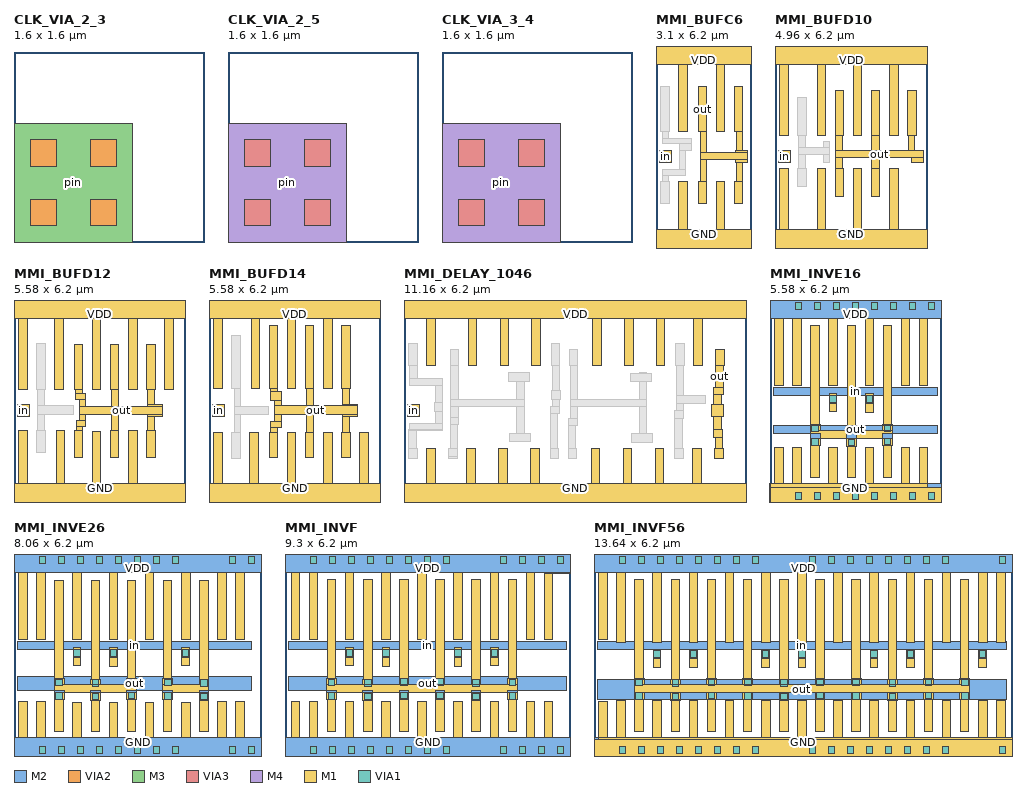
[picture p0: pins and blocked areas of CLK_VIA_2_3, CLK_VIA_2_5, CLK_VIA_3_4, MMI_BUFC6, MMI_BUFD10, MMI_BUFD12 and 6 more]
MACRO CLK_VIA_2_3
	CLASS CORE ;
	FOREIGN CLK_VIA_2_3 -0.3 -0.3 ;
	SIZE 1.6 BY 1.6 ;
	SYMMETRY X Y ;
	SITE CORE1 ;
	PIN pin
		DIRECTION inout ;
		USE SIGNAL ;
		PORT
			LAYER M2 ;
			RECT 0 0 1 1 ;
			LAYER VIA2 ;
			RECT 0.14 0.64 0.36 0.86 ;
			LAYER VIA2 ;
			RECT 0.64 0.64 0.86 0.86 ;
			LAYER VIA2 ;
			RECT 0.14 0.14 0.36 0.36 ;
			LAYER VIA2 ;
			RECT 0.64 0.14 0.86 0.36 ;
			LAYER M3 ;
			RECT 0 0 1 1 ;
		END
	END pin
	OBS
	END
END CLK_VIA_2_3
MACRO CLK_VIA_2_5
	CLASS CORE ;
	FOREIGN CLK_VIA_2_5 -0.3 -0.3 ;
	SIZE 1.6 BY 1.6 ;
	SYMMETRY X Y ;
	SITE CORE1 ;
	PIN pin
		DIRECTION output ;
		USE SIGNAL ;
		PORT
			LAYER M2 ;
			RECT 0 0 1 1 ;
			LAYER VIA2 ;
			RECT 0.14 0.64 0.36 0.86 ;
			LAYER VIA2 ;
			RECT 0.64 0.64 0.86 0.86 ;
			LAYER VIA2 ;
			RECT 0.14 0.14 0.36 0.36 ;
			LAYER VIA2 ;
			RECT 0.64 0.14 0.86 0.36 ;
			LAYER M3 ;
			RECT 0 0 1 1 ;
			LAYER VIA3 ;
			RECT 0.14 0.64 0.36 0.86 ;
			LAYER VIA3 ;
			RECT 0.64 0.64 0.86 0.86 ;
			LAYER VIA3 ;
			RECT 0.14 0.14 0.36 0.36 ;
			LAYER VIA3 ;
			RECT 0.64 0.14 0.86 0.36 ;
			LAYER M4 ;
			RECT 0 0 1 1 ;
		END
	END pin
	OBS
	END
END CLK_VIA_2_5
MACRO CLK_VIA_3_4
	CLASS CORE ;
	FOREIGN CLK_VIA_3_4 -0.3 -0.3 ;
	SIZE 1.6 BY 1.6 ;
	SYMMETRY X Y ;
	SITE CORE1 ;
	PIN pin
		DIRECTION inout ;
		USE SIGNAL ;
		PORT
			LAYER M3 ;
			RECT 0 0 1 1 ;
			LAYER VIA3 ;
			RECT 0.14 0.64 0.36 0.86 ;
			LAYER VIA3 ;
			RECT 0.64 0.64 0.86 0.86 ;
			LAYER VIA3 ;
			RECT 0.14 0.14 0.36 0.36 ;
			LAYER VIA3 ;
			RECT 0.64 0.14 0.86 0.36 ;
			LAYER M4 ;
			RECT 0 0 1 1 ;
		END
	END pin
	OBS
	END
END CLK_VIA_3_4
MACRO MMI_BUFC6
	CLASS CORE ;
	FOREIGN MMI_BUFC6 0 0 ;
	SIZE 3.1 BY 6.2 ;
	SYMMETRY X Y ;
	SITE CORE1 ;
	PIN out
		DIRECTION output ;
		USE SIGNAL ;
		PORT
			LAYER M1 ;
			RECT 1.375 3.59 1.655 5.06 ;
			LAYER M1 ;
			RECT 2.555 3.59 2.835 5.06 ;
			LAYER M1 ;
			RECT 1.465 2.92 1.655 3.59 ;
			LAYER M1 ;
			RECT 2.62 2.98 2.81 3.59 ;
			LAYER M1 ;
			RECT 2.6 2.92 2.98 2.98 ;
			LAYER M1 ;
			RECT 1.465 2.68 2.98 2.92 ;
			LAYER M1 ;
			RECT 1.465 1.96 1.655 2.68 ;
			LAYER M1 ;
			RECT 2.6 2.6 2.98 2.68 ;
			LAYER M1 ;
			RECT 2.62 1.96 2.81 2.6 ;
			LAYER M1 ;
			RECT 1.375 1.26 1.655 1.96 ;
			LAYER M1 ;
			RECT 2.555 1.26 2.835 1.96 ;
		END
	END out
	PIN GND
		DIRECTION inout ;
		USE GROUND ;
		PORT
			LAYER M1 ;
			RECT 0.745 0.42 1.025 1.96 ;
			LAYER M1 ;
			RECT 1.965 0.42 2.245 1.96 ;
			LAYER M1 ;
			RECT 0 -0.42 3.1 0.42 ;
		END
	END GND
	PIN VDD
		DIRECTION inout ;
		USE POWER ;
		PORT
			LAYER M1 ;
			RECT 0 5.78 3.1 6.62 ;
			LAYER M1 ;
			RECT 0.745 3.59 1.025 5.78 ;
			LAYER M1 ;
			RECT 1.965 3.59 2.245 5.78 ;
		END
	END VDD
	PIN in
		DIRECTION input ;
		USE SIGNAL ;
		PORT
			LAYER M1 ;
			RECT 0.12 2.6 0.5 2.98 ;
		END
		ANTENNASIZE 0.351 ;
	END in
	OBS
		LAYER M1 ;
		RECT 0.155 3.59 0.435 5.08 ;
		LAYER M1 ;
		RECT 0.225 3.39 0.415 3.59 ;
		LAYER M1 ;
		RECT 0.225 3.2 1.155 3.39 ;
		LAYER M1 ;
		RECT 0.77 2.97 1.155 3.2 ;
		LAYER M1 ;
		RECT 0.77 2.35 0.96 2.97 ;
		LAYER M1 ;
		RECT 0.22 2.16 0.96 2.35 ;
		LAYER M1 ;
		RECT 0.22 1.96 0.41 2.16 ;
		LAYER M1 ;
		RECT 0.155 1.25 0.435 1.96 ;
	END
END MMI_BUFC6
MACRO MMI_BUFD10
	CLASS CORE ;
	FOREIGN MMI_BUFD10 0 0 ;
	SIZE 4.96 BY 6.2 ;
	SYMMETRY X Y ;
	SITE CORE1 ;
	PIN out
		DIRECTION output ;
		USE SIGNAL ;
		PORT
			LAYER M1 ;
			RECT 1.965 3.49 2.245 4.96 ;
			LAYER M1 ;
			RECT 3.145 3.49 3.425 4.96 ;
			LAYER M1 ;
			RECT 4.325 3.49 4.605 4.96 ;
			LAYER M1 ;
			RECT 1.975 2.99 2.215 3.49 ;
			LAYER M1 ;
			RECT 3.16 2.99 3.4 3.49 ;
			LAYER M1 ;
			RECT 4.365 2.99 4.555 3.49 ;
			LAYER M1 ;
			RECT 1.975 2.98 4.56 2.99 ;
			LAYER M1 ;
			RECT 1.975 2.75 4.84 2.98 ;
			LAYER M1 ;
			RECT 1.975 2.39 2.215 2.75 ;
			LAYER M1 ;
			RECT 3.16 2.39 3.4 2.75 ;
			LAYER M1 ;
			RECT 4.46 2.6 4.84 2.75 ;
			LAYER M1 ;
			RECT 1.965 1.495 2.245 2.39 ;
			LAYER M1 ;
			RECT 3.145 1.495 3.425 2.39 ;
		END
	END out
	PIN GND
		DIRECTION inout ;
		USE GROUND ;
		PORT
			LAYER M1 ;
			RECT 0.155 0.42 0.435 2.39 ;
			LAYER M1 ;
			RECT 1.375 0.42 1.655 2.39 ;
			LAYER M1 ;
			RECT 2.555 0.42 2.835 2.39 ;
			LAYER M1 ;
			RECT 3.735 0.42 4.015 2.39 ;
			LAYER M1 ;
			RECT 0 -0.42 4.96 0.42 ;
		END
	END GND
	PIN VDD
		DIRECTION inout ;
		USE POWER ;
		PORT
			LAYER M1 ;
			RECT 0 5.78 4.96 6.62 ;
			LAYER M1 ;
			RECT 0.155 3.49 0.435 5.78 ;
			LAYER M1 ;
			RECT 1.375 3.49 1.655 5.78 ;
			LAYER M1 ;
			RECT 2.555 3.49 2.835 5.78 ;
			LAYER M1 ;
			RECT 3.735 3.49 4.015 5.78 ;
		END
	END VDD
	PIN in
		DIRECTION input ;
		USE SIGNAL ;
		PORT
			LAYER M1 ;
			RECT 0.12 2.6 0.5 2.98 ;
		END
		ANTENNASIZE 0.585 ;
	END in
	OBS
		LAYER M1 ;
		RECT 0.745 3.49 1.025 4.72 ;
		LAYER M1 ;
		RECT 0.765 3.09 1.005 3.49 ;
		LAYER M1 ;
		RECT 1.585 3.09 1.775 3.27 ;
		LAYER M1 ;
		RECT 0.765 2.85 1.775 3.09 ;
		LAYER M1 ;
		RECT 0.765 2.39 1.005 2.85 ;
		LAYER M1 ;
		RECT 1.585 2.6 1.775 2.85 ;
		LAYER M1 ;
		RECT 0.745 1.81 1.025 2.39 ;
	END
END MMI_BUFD10
MACRO MMI_BUFD12
	CLASS CORE ;
	FOREIGN MMI_BUFD12 0 0 ;
	SIZE 5.58 BY 6.2 ;
	SYMMETRY X Y ;
	SITE CORE1 ;
	PIN out
		DIRECTION output ;
		USE SIGNAL ;
		PORT
			LAYER M1 ;
			RECT 1.965 3.485 2.245 4.955 ;
			LAYER M1 ;
			RECT 3.145 3.485 3.425 4.955 ;
			LAYER M1 ;
			RECT 4.325 3.485 4.605 4.955 ;
			LAYER M1 ;
			RECT 2.005 3.35 2.245 3.485 ;
			LAYER M1 ;
			RECT 2.005 3.145 2.335 3.35 ;
			LAYER M1 ;
			RECT 2.145 2.91 2.335 3.145 ;
			LAYER M1 ;
			RECT 3.17 2.91 3.41 3.485 ;
			LAYER M1 ;
			RECT 4.355 2.98 4.595 3.485 ;
			LAYER M1 ;
			RECT 4.355 2.91 4.84 2.98 ;
			LAYER M1 ;
			RECT 2.145 2.67 4.84 2.91 ;
			LAYER M1 ;
			RECT 2.145 2.465 2.335 2.67 ;
			LAYER M1 ;
			RECT 2.035 2.275 2.335 2.465 ;
			LAYER M1 ;
			RECT 2.035 2.125 2.245 2.275 ;
			LAYER M1 ;
			RECT 3.17 2.125 3.41 2.67 ;
			LAYER M1 ;
			RECT 4.355 2.6 4.84 2.67 ;
			LAYER M1 ;
			RECT 4.355 2.125 4.595 2.6 ;
			LAYER M1 ;
			RECT 1.965 1.27 2.245 2.125 ;
			LAYER M1 ;
			RECT 3.145 1.27 3.425 2.125 ;
			LAYER M1 ;
			RECT 4.325 1.27 4.605 2.125 ;
		END
	END out
	PIN GND
		DIRECTION inout ;
		USE GROUND ;
		PORT
			LAYER M1 ;
			RECT 0.155 0.42 0.435 2.125 ;
			LAYER M1 ;
			RECT 1.375 0.42 1.655 2.125 ;
			LAYER M1 ;
			RECT 2.555 0.42 2.835 2.12 ;
			LAYER M1 ;
			RECT 3.735 0.42 4.015 2.125 ;
			LAYER M1 ;
			RECT 0 -0.42 5.58 0.42 ;
		END
	END GND
	PIN VDD
		DIRECTION inout ;
		USE POWER ;
		PORT
			LAYER M1 ;
			RECT 0 5.78 5.58 6.62 ;
			LAYER M1 ;
			RECT 0.155 3.485 0.435 5.78 ;
			LAYER M1 ;
			RECT 1.335 3.485 1.615 5.78 ;
			LAYER M1 ;
			RECT 2.555 3.485 2.835 5.78 ;
			LAYER M1 ;
			RECT 3.735 3.485 4.015 5.78 ;
			LAYER M1 ;
			RECT 4.915 3.485 5.195 5.78 ;
		END
	END VDD
	PIN in
		DIRECTION input ;
		USE SIGNAL ;
		PORT
			LAYER M1 ;
			RECT 0.12 2.6 0.5 2.98 ;
		END
		ANTENNASIZE 0.702 ;
	END in
	OBS
		LAYER M1 ;
		RECT 0.745 3.485 1.025 4.975 ;
		LAYER M1 ;
		RECT 0.76 2.945 1 3.485 ;
		LAYER M1 ;
		RECT 0.76 2.665 1.935 2.945 ;
		LAYER M1 ;
		RECT 0.76 2.125 1 2.665 ;
		LAYER M1 ;
		RECT 0.745 1.415 1.025 2.125 ;
	END
END MMI_BUFD12
MACRO MMI_BUFD14
	CLASS CORE ;
	FOREIGN MMI_BUFD14 0 0 ;
	SIZE 5.58 BY 6.2 ;
	SYMMETRY X Y ;
	SITE CORE1 ;
	PIN out
		DIRECTION output ;
		USE SIGNAL ;
		PORT
			LAYER M1 ;
			RECT 1.965 3.495 2.245 5.58 ;
			LAYER M1 ;
			RECT 3.145 3.495 3.425 5.58 ;
			LAYER M1 ;
			RECT 4.325 3.495 4.605 5.58 ;
			LAYER M1 ;
			RECT 2.005 3.425 2.245 3.495 ;
			LAYER M1 ;
			RECT 2.005 3.13 2.355 3.425 ;
			LAYER M1 ;
			RECT 2.135 2.94 2.355 3.13 ;
			LAYER M1 ;
			RECT 3.17 2.94 3.41 3.495 ;
			LAYER M1 ;
			RECT 4.34 2.98 4.58 3.495 ;
			LAYER M1 ;
			RECT 4.34 2.94 4.84 2.98 ;
			LAYER M1 ;
			RECT 2.135 2.66 4.84 2.94 ;
			LAYER M1 ;
			RECT 2.135 2.425 2.355 2.66 ;
			LAYER M1 ;
			RECT 2.005 2.235 2.355 2.425 ;
			LAYER M1 ;
			RECT 2.005 2.08 2.245 2.235 ;
			LAYER M1 ;
			RECT 3.17 2.08 3.41 2.66 ;
			LAYER M1 ;
			RECT 4.34 2.6 4.84 2.66 ;
			LAYER M1 ;
			RECT 4.34 2.08 4.58 2.6 ;
			LAYER M1 ;
			RECT 1.965 1.25 2.245 2.08 ;
			LAYER M1 ;
			RECT 3.145 1.25 3.425 2.08 ;
			LAYER M1 ;
			RECT 4.325 1.25 4.605 2.08 ;
		END
	END out
	PIN GND
		DIRECTION inout ;
		USE GROUND ;
		PORT
			LAYER M1 ;
			RECT 0.155 0.42 0.435 2.08 ;
			LAYER M1 ;
			RECT 1.335 0.42 1.615 2.08 ;
			LAYER M1 ;
			RECT 2.555 0.42 2.835 2.08 ;
			LAYER M1 ;
			RECT 3.735 0.42 4.015 2.08 ;
			LAYER M1 ;
			RECT 4.915 0.42 5.195 2.08 ;
			LAYER M1 ;
			RECT 0 -0.42 5.58 0.42 ;
		END
	END GND
	PIN VDD
		DIRECTION inout ;
		USE POWER ;
		PORT
			LAYER M1 ;
			RECT 0 5.78 5.58 6.62 ;
			LAYER M1 ;
			RECT 0.155 3.495 0.435 5.78 ;
			LAYER M1 ;
			RECT 1.375 3.495 1.655 5.78 ;
			LAYER M1 ;
			RECT 2.555 3.495 2.835 5.78 ;
			LAYER M1 ;
			RECT 3.735 3.495 4.015 5.78 ;
		END
	END VDD
	PIN in
		DIRECTION input ;
		USE SIGNAL ;
		PORT
			LAYER M1 ;
			RECT 0.12 2.6 0.5 2.98 ;
		END
		ANTENNASIZE 0.819 ;
	END in
	OBS
		LAYER M1 ;
		RECT 0.745 3.495 1.025 5.245 ;
		LAYER M1 ;
		RECT 0.825 2.93 1.015 3.495 ;
		LAYER M1 ;
		RECT 0.825 2.65 1.935 2.93 ;
		LAYER M1 ;
		RECT 0.825 2.08 1.015 2.65 ;
		LAYER M1 ;
		RECT 0.745 1.24 1.025 2.08 ;
	END
END MMI_BUFD14
MACRO MMI_DELAY_1046
	CLASS CORE ;
	FOREIGN MMI_DELAY_1046 0 0 ;
	SIZE 11.16 BY 6.2 ;
	SYMMETRY X Y ;
	SITE CORE1 ;
	PIN out
		DIRECTION output ;
		USE SIGNAL ;
		PORT
			LAYER M1 ;
			RECT 10.175 4.25 10.455 4.78 ;
			LAYER M1 ;
			RECT 10.18 3.55 10.42 4.25 ;
			LAYER M1 ;
			RECT 10.11 3.31 10.42 3.55 ;
			LAYER M1 ;
			RECT 10.11 2.98 10.35 3.31 ;
			LAYER M1 ;
			RECT 10.04 2.6 10.42 2.98 ;
			LAYER M1 ;
			RECT 10.11 2.17 10.35 2.6 ;
			LAYER M1 ;
			RECT 10.11 1.895 10.395 2.17 ;
			LAYER M1 ;
			RECT 10.155 1.55 10.395 1.895 ;
			LAYER M1 ;
			RECT 10.135 1.22 10.415 1.55 ;
		END
	END out
	PIN GND
		DIRECTION inout ;
		USE GROUND ;
		PORT
			LAYER M1 ;
			RECT 0.745 0.42 1.025 1.55 ;
			LAYER M1 ;
			RECT 2.055 0.42 2.335 1.55 ;
			LAYER M1 ;
			RECT 3.095 0.42 3.375 1.55 ;
			LAYER M1 ;
			RECT 4.135 0.42 4.415 1.55 ;
			LAYER M1 ;
			RECT 6.115 0.42 6.395 1.55 ;
			LAYER M1 ;
			RECT 7.155 0.42 7.435 1.55 ;
			LAYER M1 ;
			RECT 8.195 0.42 8.475 1.55 ;
			LAYER M1 ;
			RECT 9.415 0.42 9.695 1.55 ;
			LAYER M1 ;
			RECT 0 -0.42 11.16 0.42 ;
		END
	END GND
	PIN VDD
		DIRECTION inout ;
		USE POWER ;
		PORT
			LAYER M1 ;
			RECT 0 5.78 11.16 6.62 ;
			LAYER M1 ;
			RECT 0.745 4.25 1.025 5.78 ;
			LAYER M1 ;
			RECT 2.095 4.25 2.375 5.78 ;
			LAYER M1 ;
			RECT 3.135 4.25 3.415 5.78 ;
			LAYER M1 ;
			RECT 4.175 4.25 4.455 5.78 ;
			LAYER M1 ;
			RECT 6.155 4.25 6.435 5.78 ;
			LAYER M1 ;
			RECT 7.195 4.25 7.475 5.78 ;
			LAYER M1 ;
			RECT 8.235 4.25 8.515 5.78 ;
			LAYER M1 ;
			RECT 9.455 4.25 9.735 5.78 ;
		END
	END VDD
	PIN in
		DIRECTION input ;
		USE SIGNAL ;
		PORT
			LAYER M1 ;
			RECT 0.12 2.6 0.5 2.98 ;
		END
		ANTENNASIZE 0.18 ;
	END in
	OBS
		LAYER M1 ;
		RECT 0.155 4.25 0.435 4.98 ;
		LAYER M1 ;
		RECT 1.505 4.25 1.785 4.78 ;
		LAYER M1 ;
		RECT 4.805 4.25 5.085 4.98 ;
		LAYER M1 ;
		RECT 5.395 4.25 5.675 4.78 ;
		LAYER M1 ;
		RECT 8.865 4.25 9.145 4.98 ;
		LAYER M1 ;
		RECT 0.185 3.83 0.425 4.25 ;
		LAYER M1 ;
		RECT 0.185 3.59 1.265 3.83 ;
		LAYER M1 ;
		RECT 1.025 3.04 1.265 3.59 ;
		LAYER M1 ;
		RECT 1.525 3.165 1.765 4.25 ;
		LAYER M1 ;
		RECT 3.685 4.015 3.925 4.025 ;
		LAYER M1 ;
		RECT 3.42 3.735 4.09 4.015 ;
		LAYER M1 ;
		RECT 3.685 3.165 3.925 3.735 ;
		LAYER M1 ;
		RECT 4.83 3.435 5.07 4.25 ;
		LAYER M1 ;
		RECT 0.99 2.76 1.27 3.04 ;
		LAYER M1 ;
		RECT 1.525 2.925 3.925 3.165 ;
		LAYER M1 ;
		RECT 4.825 3.155 5.105 3.435 ;
		LAYER M1 ;
		RECT 5.42 3.16 5.66 4.25 ;
		LAYER M1 ;
		RECT 7.67 4.01 7.91 4.02 ;
		LAYER M1 ;
		RECT 7.405 3.73 8.075 4.01 ;
		LAYER M1 ;
		RECT 7.67 3.16 7.91 3.73 ;
		LAYER M1 ;
		RECT 4.83 2.93 5.07 3.155 ;
		LAYER M1 ;
		RECT 1.025 2.375 1.265 2.76 ;
		LAYER M1 ;
		RECT 1.525 2.565 1.765 2.925 ;
		LAYER M1 ;
		RECT 0.165 2.18 1.27 2.375 ;
		LAYER M1 ;
		RECT 0.16 2.135 1.27 2.18 ;
		LAYER M1 ;
		RECT 1.515 2.32 1.765 2.565 ;
		LAYER M1 ;
		RECT 0.16 1.55 0.4 2.135 ;
		LAYER M1 ;
		RECT 1.515 1.55 1.755 2.32 ;
		LAYER M1 ;
		RECT 3.685 2.045 3.925 2.925 ;
		LAYER M1 ;
		RECT 4.785 2.69 5.07 2.93 ;
		LAYER M1 ;
		RECT 5.42 2.92 7.91 3.16 ;
		LAYER M1 ;
		RECT 3.45 1.765 4.12 2.045 ;
		LAYER M1 ;
		RECT 4.785 1.55 5.025 2.69 ;
		LAYER M1 ;
		RECT 5.42 2.545 5.66 2.92 ;
		LAYER M1 ;
		RECT 5.36 2.305 5.66 2.545 ;
		LAYER M1 ;
		RECT 5.36 1.55 5.6 2.305 ;
		LAYER M1 ;
		RECT 7.67 2.04 7.91 2.92 ;
		LAYER M1 ;
		RECT 8.88 3.265 9.12 4.25 ;
		LAYER M1 ;
		RECT 9.545 3.265 9.825 3.285 ;
		LAYER M1 ;
		RECT 8.88 3.025 9.83 3.265 ;
		LAYER M1 ;
		RECT 8.88 2.785 9.12 3.025 ;
		LAYER M1 ;
		RECT 9.545 3.005 9.825 3.025 ;
		LAYER M1 ;
		RECT 8.84 2.545 9.12 2.785 ;
		LAYER M1 ;
		RECT 7.435 1.76 8.105 2.04 ;
		LAYER M1 ;
		RECT 8.84 1.55 9.08 2.545 ;
		LAYER M1 ;
		RECT 0.155 1.22 0.435 1.55 ;
		LAYER M1 ;
		RECT 1.465 1.29 1.755 1.55 ;
		LAYER M1 ;
		RECT 1.465 1.22 1.745 1.29 ;
		LAYER M1 ;
		RECT 4.765 1.22 5.045 1.55 ;
		LAYER M1 ;
		RECT 5.355 1.22 5.635 1.55 ;
		LAYER M1 ;
		RECT 8.825 1.22 9.105 1.55 ;
	END
END MMI_DELAY_1046
MACRO MMI_INVE16
	CLASS CORE ;
	FOREIGN MMI_INVE16 0 0 ;
	SIZE 5.58 BY 6.2 ;
	SYMMETRY X Y ;
	SITE CORE1 ;
	PIN out
		DIRECTION output ;
		USE SIGNAL ;
		PORT
			LAYER M1 ;
			RECT 1.335 2.32 1.615 5.58 ;
			LAYER M1 ;
			RECT 1.315 2.125 1.635 2.32 ;
			LAYER M1 ;
			RECT 2.515 2.305 2.795 5.58 ;
			LAYER M1 ;
			RECT 3.695 2.335 3.975 5.58 ;
			LAYER M1 ;
			RECT 2.5 2.13 2.82 2.305 ;
			LAYER M1 ;
			RECT 3.675 2.13 3.995 2.335 ;
			LAYER M1 ;
			RECT 2.5 2.125 3.995 2.13 ;
			LAYER M1 ;
			RECT 1.315 1.885 3.995 2.125 ;
			LAYER M1 ;
			RECT 1.315 1.64 1.635 1.885 ;
			LAYER M1 ;
			RECT 1.335 0.62 1.615 1.64 ;
			LAYER M1 ;
			RECT 2.5 1.625 2.82 1.885 ;
			LAYER M1 ;
			RECT 3.675 1.655 3.995 1.885 ;
			LAYER M1 ;
			RECT 2.515 0.62 2.795 1.625 ;
			LAYER M1 ;
			RECT 3.695 0.62 3.975 1.655 ;
			LAYER VIA1 ;
			RECT 1.365 2.09 1.585 2.31 ;
			LAYER VIA1 ;
			RECT 2.55 2.075 2.77 2.295 ;
			LAYER VIA1 ;
			RECT 3.725 2.105 3.945 2.325 ;
			LAYER VIA1 ;
			RECT 1.365 1.65 1.585 1.87 ;
			LAYER VIA1 ;
			RECT 2.55 1.635 2.77 1.855 ;
			LAYER VIA1 ;
			RECT 3.725 1.665 3.945 1.885 ;
			LAYER M2 ;
			RECT 1.315 2.29 1.635 2.32 ;
			LAYER M2 ;
			RECT 2.5 2.29 2.82 2.305 ;
			LAYER M2 ;
			RECT 3.675 2.29 3.995 2.335 ;
			LAYER M2 ;
			RECT 0.12 2.05 5.46 2.29 ;
			LAYER M2 ;
			RECT 1.315 1.64 1.635 2.05 ;
			LAYER M2 ;
			RECT 2.5 1.625 2.82 2.05 ;
			LAYER M2 ;
			RECT 3.675 1.655 3.995 2.05 ;
		END
	END out
	PIN GND
		DIRECTION inout ;
		USE GROUND ;
		PORT
			LAYER M1 ;
			RECT 0.155 0.42 0.435 1.575 ;
			LAYER M1 ;
			RECT 0.745 0.42 1.025 1.575 ;
			LAYER M1 ;
			RECT 1.925 0.42 2.205 1.575 ;
			LAYER M1 ;
			RECT 3.105 0.42 3.385 1.575 ;
			LAYER M1 ;
			RECT 4.285 0.42 4.565 1.575 ;
			LAYER M1 ;
			RECT 4.875 0.42 5.155 1.575 ;
			LAYER M1 ;
			RECT 0 0.265 5.155 0.42 ;
			LAYER M1 ;
			RECT 0 -0.42 5.58 0.265 ;
			LAYER VIA1 ;
			RECT 0.82 -0.11 1.04 0.11 ;
			LAYER VIA1 ;
			RECT 1.44 -0.11 1.66 0.11 ;
			LAYER VIA1 ;
			RECT 2.06 -0.11 2.28 0.11 ;
			LAYER VIA1 ;
			RECT 2.68 -0.11 2.9 0.11 ;
			LAYER VIA1 ;
			RECT 3.3 -0.11 3.52 0.11 ;
			LAYER VIA1 ;
			RECT 3.92 -0.11 4.14 0.11 ;
			LAYER VIA1 ;
			RECT 4.54 -0.11 4.76 0.11 ;
			LAYER VIA1 ;
			RECT 5.16 -0.11 5.38 0.11 ;
			LAYER M2 ;
			RECT -0.005 -0.415 5.58 0.42 ;
		END
	END GND
	PIN VDD
		DIRECTION inout ;
		USE POWER ;
		PORT
			LAYER M1 ;
			RECT 0 5.78 5.58 6.62 ;
			LAYER M1 ;
			RECT 0.155 3.595 0.435 5.78 ;
			LAYER M1 ;
			RECT 0.745 3.595 1.025 5.78 ;
			LAYER M1 ;
			RECT 1.925 3.595 2.205 5.78 ;
			LAYER M1 ;
			RECT 3.105 3.595 3.385 5.78 ;
			LAYER M1 ;
			RECT 4.285 3.595 4.565 5.78 ;
			LAYER M1 ;
			RECT 4.875 3.595 5.155 5.78 ;
			LAYER VIA1 ;
			RECT 0.82 6.09 1.04 6.31 ;
			LAYER VIA1 ;
			RECT 1.44 6.09 1.66 6.31 ;
			LAYER VIA1 ;
			RECT 2.06 6.09 2.28 6.31 ;
			LAYER VIA1 ;
			RECT 2.68 6.09 2.9 6.31 ;
			LAYER VIA1 ;
			RECT 3.3 6.09 3.52 6.31 ;
			LAYER VIA1 ;
			RECT 3.92 6.09 4.14 6.31 ;
			LAYER VIA1 ;
			RECT 4.54 6.09 4.76 6.31 ;
			LAYER VIA1 ;
			RECT 5.16 6.09 5.38 6.31 ;
			LAYER M2 ;
			RECT 0 5.78 5.58 6.615 ;
		END
	END VDD
	PIN in
		DIRECTION input ;
		USE SIGNAL ;
		PORT
			LAYER M1 ;
			RECT 1.94 2.75 2.18 3.35 ;
			LAYER M1 ;
			RECT 3.13 2.735 3.37 3.335 ;
			LAYER VIA1 ;
			RECT 1.95 3.065 2.17 3.285 ;
			LAYER VIA1 ;
			RECT 3.14 3.065 3.36 3.285 ;
			LAYER M2 ;
			RECT 0.12 3.29 5.46 3.53 ;
			LAYER M2 ;
			RECT 1.94 3.015 2.18 3.29 ;
			LAYER M2 ;
			RECT 3.13 3.015 3.37 3.29 ;
		END
		ANTENNASIZE 3.696 ;
	END in
	OBS
	END
END MMI_INVE16
MACRO MMI_INVE26
	CLASS CORE ;
	FOREIGN MMI_INVE26 0 0 ;
	SIZE 8.06 BY 6.2 ;
	SYMMETRY X Y ;
	SITE CORE1 ;
	PIN out
		DIRECTION output ;
		USE SIGNAL ;
		PORT
			LAYER M1 ;
			RECT 1.335 2.32 1.615 5.525 ;
			LAYER M1 ;
			RECT 1.315 2.125 1.635 2.32 ;
			LAYER M1 ;
			RECT 2.515 2.305 2.795 5.525 ;
			LAYER M1 ;
			RECT 3.695 2.335 3.975 5.525 ;
			LAYER M1 ;
			RECT 2.5 2.13 2.82 2.305 ;
			LAYER M1 ;
			RECT 3.675 2.13 3.995 2.335 ;
			LAYER M1 ;
			RECT 4.875 2.32 5.155 5.525 ;
			LAYER M1 ;
			RECT 2.5 2.125 3.995 2.13 ;
			LAYER M1 ;
			RECT 1.315 1.885 3.995 2.125 ;
			LAYER M1 ;
			RECT 1.315 1.64 1.635 1.885 ;
			LAYER M1 ;
			RECT 1.335 0.62 1.615 1.64 ;
			LAYER M1 ;
			RECT 2.5 1.625 2.82 1.885 ;
			LAYER M1 ;
			RECT 3.675 1.655 3.995 1.885 ;
			LAYER M1 ;
			RECT 4.855 2.125 5.175 2.32 ;
			LAYER M1 ;
			RECT 6.055 2.305 6.335 5.525 ;
			LAYER M1 ;
			RECT 6.04 2.125 6.36 2.305 ;
			LAYER M1 ;
			RECT 4.855 1.885 6.36 2.125 ;
			LAYER M1 ;
			RECT 2.515 0.62 2.795 1.625 ;
			LAYER M1 ;
			RECT 3.695 0.62 3.975 1.655 ;
			LAYER M1 ;
			RECT 4.855 1.64 5.175 1.885 ;
			LAYER M1 ;
			RECT 4.875 0.62 5.155 1.64 ;
			LAYER M1 ;
			RECT 6.04 1.625 6.36 1.885 ;
			LAYER M1 ;
			RECT 6.055 0.62 6.335 1.625 ;
			LAYER VIA1 ;
			RECT 1.365 2.09 1.585 2.31 ;
			LAYER VIA1 ;
			RECT 2.55 2.075 2.77 2.295 ;
			LAYER VIA1 ;
			RECT 3.725 2.105 3.945 2.325 ;
			LAYER VIA1 ;
			RECT 4.905 2.09 5.125 2.31 ;
			LAYER VIA1 ;
			RECT 6.09 2.075 6.31 2.295 ;
			LAYER VIA1 ;
			RECT 1.365 1.65 1.585 1.87 ;
			LAYER VIA1 ;
			RECT 2.55 1.635 2.77 1.855 ;
			LAYER VIA1 ;
			RECT 3.725 1.665 3.945 1.885 ;
			LAYER VIA1 ;
			RECT 4.905 1.65 5.125 1.87 ;
			LAYER VIA1 ;
			RECT 6.09 1.635 6.31 1.855 ;
			LAYER M2 ;
			RECT 0.12 1.93 7.75 2.41 ;
			LAYER M2 ;
			RECT 1.315 1.64 1.635 1.93 ;
			LAYER M2 ;
			RECT 2.5 1.625 2.82 1.93 ;
			LAYER M2 ;
			RECT 3.675 1.655 3.995 1.93 ;
			LAYER M2 ;
			RECT 4.855 1.64 5.175 1.93 ;
			LAYER M2 ;
			RECT 6.04 1.625 6.36 1.93 ;
		END
	END out
	PIN GND
		DIRECTION inout ;
		USE GROUND ;
		PORT
			LAYER M1 ;
			RECT 0.155 0.42 0.435 1.575 ;
			LAYER M1 ;
			RECT 0.745 0.42 1.025 1.575 ;
			LAYER M1 ;
			RECT 1.925 0.42 2.205 1.555 ;
			LAYER M1 ;
			RECT 3.105 0.42 3.385 1.555 ;
			LAYER M1 ;
			RECT 4.285 0.42 4.565 1.555 ;
			LAYER M1 ;
			RECT 5.465 0.42 5.745 1.555 ;
			LAYER M1 ;
			RECT 6.645 0.42 6.925 1.575 ;
			LAYER M1 ;
			RECT 7.235 0.42 7.515 1.575 ;
			LAYER M1 ;
			RECT 0 -0.42 8.06 0.42 ;
			LAYER VIA1 ;
			RECT 0.82 -0.11 1.04 0.11 ;
			LAYER VIA1 ;
			RECT 1.44 -0.11 1.66 0.11 ;
			LAYER VIA1 ;
			RECT 2.06 -0.11 2.28 0.11 ;
			LAYER VIA1 ;
			RECT 2.68 -0.11 2.9 0.11 ;
			LAYER VIA1 ;
			RECT 3.3 -0.11 3.52 0.11 ;
			LAYER VIA1 ;
			RECT 3.92 -0.11 4.14 0.11 ;
			LAYER VIA1 ;
			RECT 4.54 -0.11 4.76 0.11 ;
			LAYER VIA1 ;
			RECT 5.16 -0.11 5.38 0.11 ;
			LAYER VIA1 ;
			RECT 7.02 -0.11 7.24 0.11 ;
			LAYER VIA1 ;
			RECT 7.64 -0.11 7.86 0.11 ;
			LAYER M2 ;
			RECT 0 -0.415 8.06 0.42 ;
		END
	END GND
	PIN VDD
		DIRECTION inout ;
		USE POWER ;
		PORT
			LAYER M1 ;
			RECT 0 5.78 8.06 6.62 ;
			LAYER M1 ;
			RECT 0.155 3.595 0.435 5.78 ;
			LAYER M1 ;
			RECT 0.745 3.595 1.025 5.78 ;
			LAYER M1 ;
			RECT 1.925 3.595 2.205 5.78 ;
			LAYER M1 ;
			RECT 3.105 3.595 3.385 5.78 ;
			LAYER M1 ;
			RECT 4.285 3.595 4.565 5.78 ;
			LAYER M1 ;
			RECT 5.465 3.595 5.745 5.78 ;
			LAYER M1 ;
			RECT 6.645 3.595 6.925 5.78 ;
			LAYER M1 ;
			RECT 7.235 3.595 7.515 5.78 ;
			LAYER VIA1 ;
			RECT 0.82 6.09 1.04 6.31 ;
			LAYER VIA1 ;
			RECT 1.44 6.09 1.66 6.31 ;
			LAYER VIA1 ;
			RECT 2.06 6.09 2.28 6.31 ;
			LAYER VIA1 ;
			RECT 2.68 6.09 2.9 6.31 ;
			LAYER VIA1 ;
			RECT 3.3 6.09 3.52 6.31 ;
			LAYER VIA1 ;
			RECT 3.92 6.09 4.14 6.31 ;
			LAYER VIA1 ;
			RECT 4.54 6.09 4.76 6.31 ;
			LAYER VIA1 ;
			RECT 5.16 6.09 5.38 6.31 ;
			LAYER VIA1 ;
			RECT 7.02 6.09 7.24 6.31 ;
			LAYER VIA1 ;
			RECT 7.64 6.09 7.86 6.31 ;
			LAYER M2 ;
			RECT 0 5.78 8.06 6.615 ;
		END
	END VDD
	PIN in
		DIRECTION input ;
		USE SIGNAL ;
		PORT
			LAYER M1 ;
			RECT 1.94 2.75 2.18 3.35 ;
			LAYER M1 ;
			RECT 3.13 2.735 3.37 3.335 ;
			LAYER M1 ;
			RECT 5.48 2.75 5.72 3.35 ;
			LAYER VIA1 ;
			RECT 1.95 3.065 2.17 3.285 ;
			LAYER VIA1 ;
			RECT 3.14 3.065 3.36 3.285 ;
			LAYER VIA1 ;
			RECT 5.49 3.065 5.71 3.285 ;
			LAYER M2 ;
			RECT 0.12 3.29 7.75 3.53 ;
			LAYER M2 ;
			RECT 1.94 3.015 2.18 3.29 ;
			LAYER M2 ;
			RECT 3.13 3.015 3.37 3.29 ;
			LAYER M2 ;
			RECT 5.48 3.015 5.72 3.29 ;
		END
		ANTENNASIZE 5.409 ;
	END in
	OBS
	END
END MMI_INVE26
MACRO MMI_INVF
	CLASS CORE ;
	FOREIGN MMI_INVF 0 0 ;
	SIZE 9.3 BY 6.2 ;
	SYMMETRY X Y ;
	SITE CORE1 ;
	PIN out
		DIRECTION output ;
		USE SIGNAL ;
		PORT
			LAYER M1 ;
			RECT 1.38 2.32 1.66 5.58 ;
			LAYER M1 ;
			RECT 1.36 2.125 1.68 2.32 ;
			LAYER M1 ;
			RECT 2.56 2.305 2.84 5.58 ;
			LAYER M1 ;
			RECT 3.74 2.335 4.02 5.58 ;
			LAYER M1 ;
			RECT 4.92 2.335 5.2 5.58 ;
			LAYER M1 ;
			RECT 2.545 2.13 2.865 2.305 ;
			LAYER M1 ;
			RECT 3.72 2.13 4.04 2.335 ;
			LAYER M1 ;
			RECT 4.9 2.13 5.22 2.335 ;
			LAYER M1 ;
			RECT 6.1 2.305 6.38 5.58 ;
			LAYER M1 ;
			RECT 7.28 2.32 7.56 5.58 ;
			LAYER M1 ;
			RECT 6.075 2.13 6.395 2.305 ;
			LAYER M1 ;
			RECT 2.545 2.125 6.395 2.13 ;
			LAYER M1 ;
			RECT 7.26 2.125 7.58 2.32 ;
			LAYER M1 ;
			RECT 1.36 1.89 7.58 2.125 ;
			LAYER M1 ;
			RECT 1.36 1.885 4.04 1.89 ;
			LAYER M1 ;
			RECT 1.36 1.64 1.68 1.885 ;
			LAYER M1 ;
			RECT 1.38 0.62 1.66 1.64 ;
			LAYER M1 ;
			RECT 2.545 1.625 2.865 1.885 ;
			LAYER M1 ;
			RECT 3.72 1.655 4.04 1.885 ;
			LAYER M1 ;
			RECT 4.9 1.885 7.58 1.89 ;
			LAYER M1 ;
			RECT 4.9 1.655 5.22 1.885 ;
			LAYER M1 ;
			RECT 2.56 0.62 2.84 1.625 ;
			LAYER M1 ;
			RECT 3.74 0.62 4.02 1.655 ;
			LAYER M1 ;
			RECT 4.92 0.62 5.2 1.655 ;
			LAYER M1 ;
			RECT 6.075 1.625 6.395 1.885 ;
			LAYER M1 ;
			RECT 7.26 1.64 7.58 1.885 ;
			LAYER M1 ;
			RECT 6.1 0.62 6.38 1.625 ;
			LAYER M1 ;
			RECT 7.28 0.62 7.56 1.64 ;
			LAYER VIA1 ;
			RECT 1.41 2.09 1.63 2.31 ;
			LAYER VIA1 ;
			RECT 2.595 2.075 2.815 2.295 ;
			LAYER VIA1 ;
			RECT 3.77 2.105 3.99 2.325 ;
			LAYER VIA1 ;
			RECT 4.95 2.105 5.17 2.325 ;
			LAYER VIA1 ;
			RECT 6.125 2.075 6.345 2.295 ;
			LAYER VIA1 ;
			RECT 7.31 2.09 7.53 2.31 ;
			LAYER VIA1 ;
			RECT 1.41 1.65 1.63 1.87 ;
			LAYER VIA1 ;
			RECT 2.595 1.635 2.815 1.855 ;
			LAYER VIA1 ;
			RECT 3.77 1.665 3.99 1.885 ;
			LAYER VIA1 ;
			RECT 4.95 1.665 5.17 1.885 ;
			LAYER VIA1 ;
			RECT 6.125 1.635 6.345 1.855 ;
			LAYER VIA1 ;
			RECT 7.31 1.65 7.53 1.87 ;
			LAYER M2 ;
			RECT 0.12 1.93 9.18 2.41 ;
			LAYER M2 ;
			RECT 1.36 1.64 1.68 1.93 ;
			LAYER M2 ;
			RECT 2.545 1.625 2.865 1.93 ;
			LAYER M2 ;
			RECT 3.72 1.655 4.04 1.93 ;
			LAYER M2 ;
			RECT 4.9 1.655 5.22 1.93 ;
			LAYER M2 ;
			RECT 6.075 1.625 6.395 1.93 ;
			LAYER M2 ;
			RECT 7.26 1.64 7.58 1.93 ;
		END
	END out
	PIN GND
		DIRECTION inout ;
		USE GROUND ;
		PORT
			LAYER M1 ;
			RECT 0.2 0.42 0.48 1.575 ;
			LAYER M1 ;
			RECT 0.79 0.42 1.07 1.575 ;
			LAYER M1 ;
			RECT 1.97 0.42 2.25 1.575 ;
			LAYER M1 ;
			RECT 3.15 0.42 3.43 1.575 ;
			LAYER M1 ;
			RECT 4.33 0.42 4.61 1.575 ;
			LAYER M1 ;
			RECT 5.51 0.42 5.79 1.575 ;
			LAYER M1 ;
			RECT 6.69 0.42 6.97 1.575 ;
			LAYER M1 ;
			RECT 7.87 0.42 8.15 1.575 ;
			LAYER M1 ;
			RECT 8.46 0.42 8.74 1.575 ;
			LAYER M1 ;
			RECT 0 -0.42 9.3 0.42 ;
			LAYER VIA1 ;
			RECT 0.82 -0.11 1.04 0.11 ;
			LAYER VIA1 ;
			RECT 1.44 -0.11 1.66 0.11 ;
			LAYER VIA1 ;
			RECT 2.06 -0.11 2.28 0.11 ;
			LAYER VIA1 ;
			RECT 2.68 -0.11 2.9 0.11 ;
			LAYER VIA1 ;
			RECT 3.3 -0.11 3.52 0.11 ;
			LAYER VIA1 ;
			RECT 3.92 -0.11 4.14 0.11 ;
			LAYER VIA1 ;
			RECT 4.54 -0.11 4.76 0.11 ;
			LAYER VIA1 ;
			RECT 5.16 -0.11 5.38 0.11 ;
			LAYER VIA1 ;
			RECT 7.02 -0.11 7.24 0.11 ;
			LAYER VIA1 ;
			RECT 7.64 -0.11 7.86 0.11 ;
			LAYER VIA1 ;
			RECT 8.26 -0.11 8.48 0.11 ;
			LAYER VIA1 ;
			RECT 8.88 -0.11 9.1 0.11 ;
			LAYER M2 ;
			RECT 0 -0.415 9.3 0.42 ;
		END
	END GND
	PIN VDD
		DIRECTION inout ;
		USE POWER ;
		PORT
			LAYER M1 ;
			RECT 0 5.78 9.3 6.62 ;
			LAYER M1 ;
			RECT 0.2 3.595 0.48 5.78 ;
			LAYER M1 ;
			RECT 0.79 3.595 1.07 5.78 ;
			LAYER M1 ;
			RECT 1.97 3.595 2.25 5.78 ;
			LAYER M1 ;
			RECT 3.15 3.595 3.43 5.78 ;
			LAYER M1 ;
			RECT 4.33 3.595 4.61 5.78 ;
			LAYER M1 ;
			RECT 5.51 3.595 5.79 5.78 ;
			LAYER M1 ;
			RECT 6.69 3.595 6.97 5.78 ;
			LAYER M1 ;
			RECT 7.87 3.595 8.15 5.78 ;
			LAYER M1 ;
			RECT 8.455 5.775 9.3 5.78 ;
			LAYER M1 ;
			RECT 8.46 3.595 8.74 5.775 ;
			LAYER VIA1 ;
			RECT 0.82 6.09 1.04 6.31 ;
			LAYER VIA1 ;
			RECT 1.44 6.09 1.66 6.31 ;
			LAYER VIA1 ;
			RECT 2.06 6.09 2.28 6.31 ;
			LAYER VIA1 ;
			RECT 2.68 6.09 2.9 6.31 ;
			LAYER VIA1 ;
			RECT 3.3 6.09 3.52 6.31 ;
			LAYER VIA1 ;
			RECT 3.92 6.09 4.14 6.31 ;
			LAYER VIA1 ;
			RECT 4.54 6.09 4.76 6.31 ;
			LAYER VIA1 ;
			RECT 5.16 6.09 5.38 6.31 ;
			LAYER VIA1 ;
			RECT 7.02 6.09 7.24 6.31 ;
			LAYER VIA1 ;
			RECT 7.64 6.09 7.86 6.31 ;
			LAYER VIA1 ;
			RECT 8.26 6.09 8.48 6.31 ;
			LAYER VIA1 ;
			RECT 8.88 6.09 9.1 6.31 ;
			LAYER M2 ;
			RECT 0 5.78 9.3 6.615 ;
		END
	END VDD
	PIN in
		DIRECTION input ;
		USE SIGNAL ;
		PORT
			LAYER M1 ;
			RECT 1.985 2.75 2.225 3.35 ;
			LAYER M1 ;
			RECT 3.175 2.735 3.415 3.335 ;
			LAYER M1 ;
			RECT 5.525 2.735 5.765 3.335 ;
			LAYER M1 ;
			RECT 6.715 2.75 6.955 3.35 ;
			LAYER VIA1 ;
			RECT 1.995 3.065 2.215 3.285 ;
			LAYER VIA1 ;
			RECT 3.185 3.065 3.405 3.285 ;
			LAYER VIA1 ;
			RECT 5.535 3.065 5.755 3.285 ;
			LAYER VIA1 ;
			RECT 6.725 3.065 6.945 3.285 ;
			LAYER M2 ;
			RECT 0.12 3.29 9.18 3.53 ;
			LAYER M2 ;
			RECT 1.985 3.015 2.225 3.29 ;
			LAYER M2 ;
			RECT 3.175 3.015 3.415 3.29 ;
			LAYER M2 ;
			RECT 5.525 3.015 5.765 3.29 ;
			LAYER M2 ;
			RECT 6.715 3.015 6.955 3.29 ;
		END
		ANTENNASIZE 6.468 ;
	END in
	OBS
	END
END MMI_INVF
MACRO MMI_INVF56
	CLASS CORE ;
	FOREIGN MMI_INVF56 0 0 ;
	SIZE 13.64 BY 6.2 ;
	SYMMETRY X Y ;
	SITE CORE1 ;
	PIN out
		DIRECTION output ;
		USE SIGNAL ;
		PORT
			LAYER M1 ;
			RECT 1.335 2.32 1.615 5.58 ;
			LAYER M1 ;
			RECT 1.315 2.125 1.635 2.32 ;
			LAYER M1 ;
			RECT 2.515 2.305 2.795 5.58 ;
			LAYER M1 ;
			RECT 3.695 2.335 3.975 5.58 ;
			LAYER M1 ;
			RECT 2.5 2.13 2.82 2.305 ;
			LAYER M1 ;
			RECT 3.675 2.13 3.995 2.335 ;
			LAYER M1 ;
			RECT 4.875 2.32 5.155 5.58 ;
			LAYER M1 ;
			RECT 4.855 2.13 5.175 2.32 ;
			LAYER M1 ;
			RECT 6.055 2.305 6.335 5.58 ;
			LAYER M1 ;
			RECT 7.235 2.335 7.515 5.58 ;
			LAYER M1 ;
			RECT 2.5 2.125 5.175 2.13 ;
			LAYER M1 ;
			RECT 6.04 2.13 6.36 2.305 ;
			LAYER M1 ;
			RECT 7.215 2.13 7.535 2.335 ;
			LAYER M1 ;
			RECT 8.415 2.32 8.695 5.58 ;
			LAYER M1 ;
			RECT 8.395 2.13 8.715 2.32 ;
			LAYER M1 ;
			RECT 9.595 2.305 9.875 5.58 ;
			LAYER M1 ;
			RECT 10.775 2.335 11.055 5.58 ;
			LAYER M1 ;
			RECT 6.04 2.125 8.715 2.13 ;
			LAYER M1 ;
			RECT 9.58 2.13 9.9 2.305 ;
			LAYER M1 ;
			RECT 10.755 2.13 11.075 2.335 ;
			LAYER M1 ;
			RECT 11.955 2.32 12.235 5.58 ;
			LAYER M1 ;
			RECT 9.58 2.125 11.075 2.13 ;
			LAYER M1 ;
			RECT 11.935 2.125 12.255 2.32 ;
			LAYER M1 ;
			RECT 1.315 1.885 12.255 2.125 ;
			LAYER M1 ;
			RECT 1.315 1.64 1.635 1.885 ;
			LAYER M1 ;
			RECT 1.335 0.62 1.615 1.64 ;
			LAYER M1 ;
			RECT 2.5 1.625 2.82 1.885 ;
			LAYER M1 ;
			RECT 3.675 1.655 3.995 1.885 ;
			LAYER M1 ;
			RECT 2.515 0.62 2.795 1.625 ;
			LAYER M1 ;
			RECT 3.695 0.62 3.975 1.655 ;
			LAYER M1 ;
			RECT 4.855 1.64 5.175 1.885 ;
			LAYER M1 ;
			RECT 4.875 0.62 5.155 1.64 ;
			LAYER M1 ;
			RECT 6.04 1.625 6.36 1.885 ;
			LAYER M1 ;
			RECT 7.215 1.655 7.535 1.885 ;
			LAYER M1 ;
			RECT 6.055 0.62 6.335 1.625 ;
			LAYER M1 ;
			RECT 7.235 0.62 7.515 1.655 ;
			LAYER M1 ;
			RECT 8.395 1.64 8.715 1.885 ;
			LAYER M1 ;
			RECT 8.415 0.62 8.695 1.64 ;
			LAYER M1 ;
			RECT 9.58 1.625 9.9 1.885 ;
			LAYER M1 ;
			RECT 10.755 1.655 11.075 1.885 ;
			LAYER M1 ;
			RECT 9.595 0.62 9.875 1.625 ;
			LAYER M1 ;
			RECT 10.775 0.62 11.055 1.655 ;
			LAYER M1 ;
			RECT 11.935 1.64 12.255 1.885 ;
			LAYER M1 ;
			RECT 11.955 0.62 12.235 1.64 ;
			LAYER VIA1 ;
			RECT 1.365 2.09 1.585 2.31 ;
			LAYER VIA1 ;
			RECT 2.55 2.075 2.77 2.295 ;
			LAYER VIA1 ;
			RECT 3.725 2.105 3.945 2.325 ;
			LAYER VIA1 ;
			RECT 4.905 2.09 5.125 2.31 ;
			LAYER VIA1 ;
			RECT 6.09 2.075 6.31 2.295 ;
			LAYER VIA1 ;
			RECT 7.265 2.105 7.485 2.325 ;
			LAYER VIA1 ;
			RECT 8.445 2.09 8.665 2.31 ;
			LAYER VIA1 ;
			RECT 9.63 2.075 9.85 2.295 ;
			LAYER VIA1 ;
			RECT 10.805 2.105 11.025 2.325 ;
			LAYER VIA1 ;
			RECT 11.985 2.09 12.205 2.31 ;
			LAYER VIA1 ;
			RECT 1.365 1.65 1.585 1.87 ;
			LAYER VIA1 ;
			RECT 2.55 1.635 2.77 1.855 ;
			LAYER VIA1 ;
			RECT 3.725 1.665 3.945 1.885 ;
			LAYER VIA1 ;
			RECT 4.905 1.65 5.125 1.87 ;
			LAYER VIA1 ;
			RECT 6.09 1.635 6.31 1.855 ;
			LAYER VIA1 ;
			RECT 7.265 1.665 7.485 1.885 ;
			LAYER VIA1 ;
			RECT 8.445 1.65 8.665 1.87 ;
			LAYER VIA1 ;
			RECT 9.63 1.635 9.85 1.855 ;
			LAYER VIA1 ;
			RECT 10.805 1.665 11.025 1.885 ;
			LAYER VIA1 ;
			RECT 11.985 1.65 12.205 1.87 ;
			LAYER M2 ;
			RECT 1.315 2.3 1.635 2.32 ;
			LAYER M2 ;
			RECT 2.5 2.3 2.82 2.305 ;
			LAYER M2 ;
			RECT 3.675 2.3 3.995 2.335 ;
			LAYER M2 ;
			RECT 4.855 2.3 5.175 2.32 ;
			LAYER M2 ;
			RECT 6.04 2.3 6.36 2.305 ;
			LAYER M2 ;
			RECT 7.215 2.3 7.535 2.335 ;
			LAYER M2 ;
			RECT 8.395 2.3 8.715 2.32 ;
			LAYER M2 ;
			RECT 9.58 2.3 9.9 2.305 ;
			LAYER M2 ;
			RECT 10.755 2.3 11.075 2.335 ;
			LAYER M2 ;
			RECT 11.935 2.3 12.255 2.32 ;
			LAYER M2 ;
			RECT 0.12 1.66 13.45 2.3 ;
			LAYER M2 ;
			RECT 1.315 1.64 1.635 1.66 ;
			LAYER M2 ;
			RECT 2.5 1.625 2.82 1.66 ;
			LAYER M2 ;
			RECT 3.675 1.655 3.995 1.66 ;
			LAYER M2 ;
			RECT 4.855 1.64 5.175 1.66 ;
			LAYER M2 ;
			RECT 6.04 1.625 6.36 1.66 ;
			LAYER M2 ;
			RECT 7.215 1.655 7.535 1.66 ;
			LAYER M2 ;
			RECT 8.395 1.64 8.715 1.66 ;
			LAYER M2 ;
			RECT 9.58 1.625 9.9 1.66 ;
			LAYER M2 ;
			RECT 10.755 1.655 11.075 1.66 ;
			LAYER M2 ;
			RECT 11.935 1.64 12.255 1.66 ;
		END
	END out
	PIN GND
		DIRECTION inout ;
		USE GROUND ;
		PORT
			LAYER M1 ;
			RECT 0.155 0.42 0.435 1.575 ;
			LAYER M1 ;
			RECT 0.745 0.42 1.025 1.63 ;
			LAYER M1 ;
			RECT 1.925 0.42 2.205 1.63 ;
			LAYER M1 ;
			RECT 3.105 0.42 3.385 1.63 ;
			LAYER M1 ;
			RECT 4.285 0.42 4.565 1.63 ;
			LAYER M1 ;
			RECT 5.465 0.42 5.745 1.63 ;
			LAYER M1 ;
			RECT 6.645 0.42 6.925 1.63 ;
			LAYER M1 ;
			RECT 7.825 0.42 8.105 1.63 ;
			LAYER M1 ;
			RECT 9.005 0.42 9.285 1.63 ;
			LAYER M1 ;
			RECT 10.185 0.42 10.465 1.63 ;
			LAYER M1 ;
			RECT 11.365 0.42 11.645 1.63 ;
			LAYER M1 ;
			RECT 12.545 0.42 12.825 1.63 ;
			LAYER M1 ;
			RECT 13.135 0.42 13.415 1.63 ;
			LAYER M1 ;
			RECT 0.155 0.35 13.64 0.42 ;
			LAYER M1 ;
			RECT 0 -0.42 13.64 0.35 ;
			LAYER VIA1 ;
			RECT 0.82 -0.11 1.04 0.11 ;
			LAYER VIA1 ;
			RECT 1.44 -0.11 1.66 0.11 ;
			LAYER VIA1 ;
			RECT 2.06 -0.11 2.28 0.11 ;
			LAYER VIA1 ;
			RECT 2.68 -0.11 2.9 0.11 ;
			LAYER VIA1 ;
			RECT 3.3 -0.11 3.52 0.11 ;
			LAYER VIA1 ;
			RECT 3.92 -0.11 4.14 0.11 ;
			LAYER VIA1 ;
			RECT 4.54 -0.11 4.76 0.11 ;
			LAYER VIA1 ;
			RECT 5.16 -0.11 5.38 0.11 ;
			LAYER VIA1 ;
			RECT 7.02 -0.11 7.24 0.11 ;
			LAYER VIA1 ;
			RECT 7.64 -0.11 7.86 0.11 ;
			LAYER VIA1 ;
			RECT 8.26 -0.11 8.48 0.11 ;
			LAYER VIA1 ;
			RECT 8.88 -0.11 9.1 0.11 ;
			LAYER VIA1 ;
			RECT 9.5 -0.11 9.72 0.11 ;
			LAYER VIA1 ;
			RECT 10.12 -0.11 10.34 0.11 ;
			LAYER VIA1 ;
			RECT 10.74 -0.11 10.96 0.11 ;
			LAYER VIA1 ;
			RECT 11.36 -0.11 11.58 0.11 ;
			LAYER VIA1 ;
			RECT 13.22 -0.11 13.44 0.11 ;
			LAYER M2 ;
			RECT 0 -0.415 13.64 0.42 ;
		END
	END GND
	PIN VDD
		DIRECTION inout ;
		USE POWER ;
		PORT
			LAYER M1 ;
			RECT 0 5.78 13.64 6.62 ;
			LAYER M1 ;
			RECT 0.155 3.595 0.435 5.78 ;
			LAYER M1 ;
			RECT 0.745 3.495 1.025 5.78 ;
			LAYER M1 ;
			RECT 1.925 3.495 2.205 5.78 ;
			LAYER M1 ;
			RECT 3.105 3.495 3.385 5.78 ;
			LAYER M1 ;
			RECT 4.285 3.495 4.565 5.78 ;
			LAYER M1 ;
			RECT 5.465 3.495 5.745 5.78 ;
			LAYER M1 ;
			RECT 6.645 3.495 6.925 5.78 ;
			LAYER M1 ;
			RECT 7.825 3.495 8.105 5.78 ;
			LAYER M1 ;
			RECT 9.005 3.495 9.285 5.78 ;
			LAYER M1 ;
			RECT 10.185 3.495 10.465 5.78 ;
			LAYER M1 ;
			RECT 11.365 3.495 11.645 5.78 ;
			LAYER M1 ;
			RECT 12.545 3.495 12.825 5.78 ;
			LAYER M1 ;
			RECT 13.135 3.495 13.415 5.78 ;
			LAYER VIA1 ;
			RECT 0.82 6.09 1.04 6.31 ;
			LAYER VIA1 ;
			RECT 1.44 6.09 1.66 6.31 ;
			LAYER VIA1 ;
			RECT 2.06 6.09 2.28 6.31 ;
			LAYER VIA1 ;
			RECT 2.68 6.09 2.9 6.31 ;
			LAYER VIA1 ;
			RECT 3.3 6.09 3.52 6.31 ;
			LAYER VIA1 ;
			RECT 3.92 6.09 4.14 6.31 ;
			LAYER VIA1 ;
			RECT 4.54 6.09 4.76 6.31 ;
			LAYER VIA1 ;
			RECT 5.16 6.09 5.38 6.31 ;
			LAYER VIA1 ;
			RECT 7.02 6.09 7.24 6.31 ;
			LAYER VIA1 ;
			RECT 7.64 6.09 7.86 6.31 ;
			LAYER VIA1 ;
			RECT 8.26 6.09 8.48 6.31 ;
			LAYER VIA1 ;
			RECT 8.88 6.09 9.1 6.31 ;
			LAYER VIA1 ;
			RECT 9.5 6.09 9.72 6.31 ;
			LAYER VIA1 ;
			RECT 10.12 6.09 10.34 6.31 ;
			LAYER VIA1 ;
			RECT 10.74 6.09 10.96 6.31 ;
			LAYER VIA1 ;
			RECT 11.36 6.09 11.58 6.31 ;
			LAYER VIA1 ;
			RECT 13.22 6.09 13.44 6.31 ;
			LAYER M2 ;
			RECT 0 5.78 13.64 6.615 ;
		END
	END VDD
	PIN in
		DIRECTION input ;
		USE SIGNAL ;
		PORT
			LAYER M1 ;
			RECT 1.94 2.695 2.18 3.295 ;
			LAYER M1 ;
			RECT 3.13 2.695 3.37 3.295 ;
			LAYER M1 ;
			RECT 5.48 2.695 5.72 3.295 ;
			LAYER M1 ;
			RECT 6.67 2.695 6.91 3.295 ;
			LAYER M1 ;
			RECT 9.02 2.695 9.26 3.295 ;
			LAYER M1 ;
			RECT 10.21 2.695 10.45 3.295 ;
			LAYER M1 ;
			RECT 12.56 2.695 12.8 3.295 ;
			LAYER VIA1 ;
			RECT 1.95 3.025 2.17 3.245 ;
			LAYER VIA1 ;
			RECT 3.14 3.025 3.36 3.245 ;
			LAYER VIA1 ;
			RECT 5.49 3.025 5.71 3.245 ;
			LAYER VIA1 ;
			RECT 6.68 3.025 6.9 3.245 ;
			LAYER VIA1 ;
			RECT 9.03 3.025 9.25 3.245 ;
			LAYER VIA1 ;
			RECT 10.22 3.025 10.44 3.245 ;
			LAYER VIA1 ;
			RECT 12.57 3.025 12.79 3.245 ;
			LAYER M2 ;
			RECT 0.12 3.29 13.45 3.53 ;
			LAYER M2 ;
			RECT 1.94 2.975 2.18 3.29 ;
			LAYER M2 ;
			RECT 3.13 2.975 3.37 3.29 ;
			LAYER M2 ;
			RECT 5.48 2.975 5.72 3.29 ;
			LAYER M2 ;
			RECT 6.67 2.975 6.91 3.29 ;
			LAYER M2 ;
			RECT 9.02 2.975 9.26 3.29 ;
			LAYER M2 ;
			RECT 10.21 2.975 10.45 3.29 ;
			LAYER M2 ;
			RECT 12.56 2.975 12.8 3.29 ;
		END
		ANTENNASIZE 10.6755 ;
	END in
	OBS
	END
END MMI_INVF56
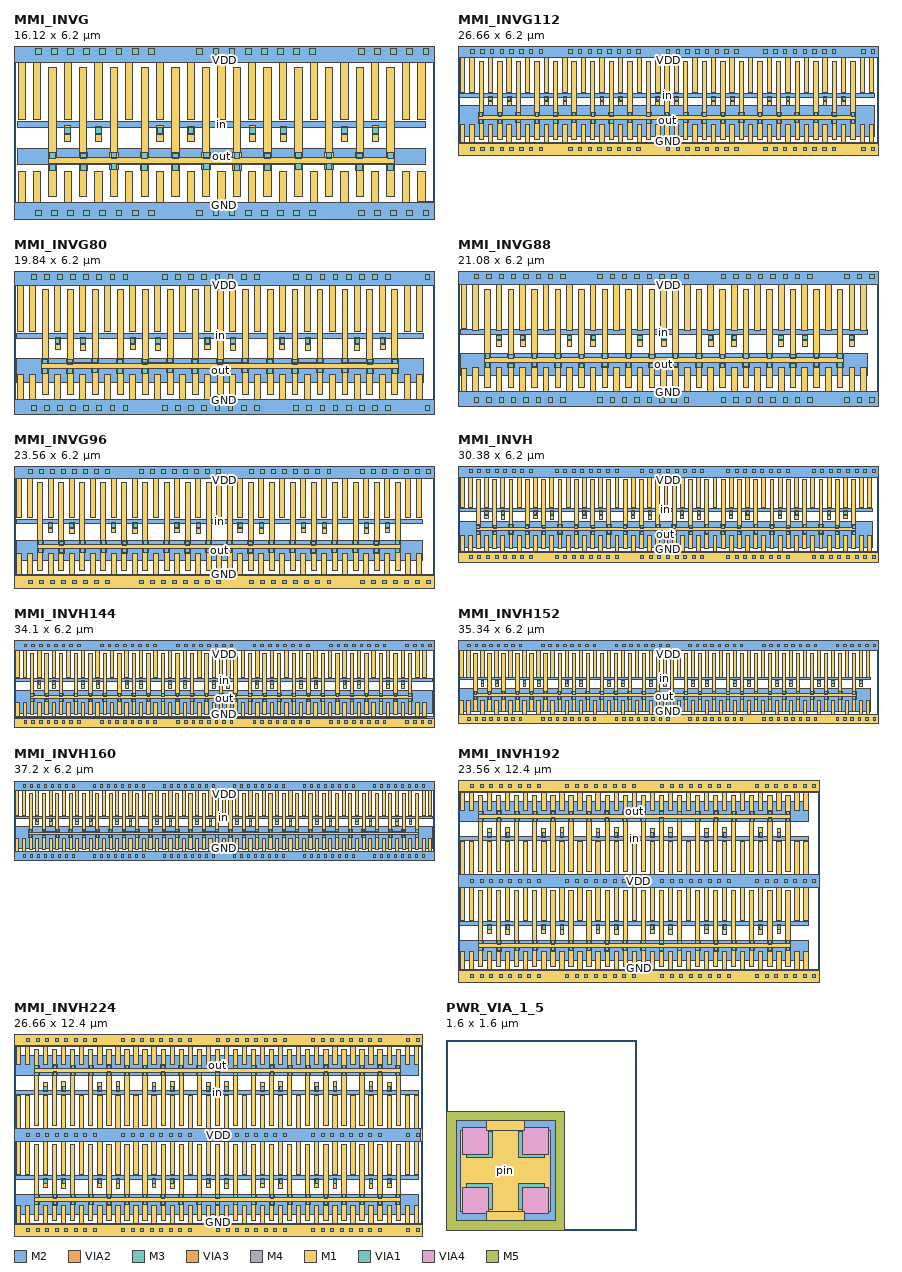
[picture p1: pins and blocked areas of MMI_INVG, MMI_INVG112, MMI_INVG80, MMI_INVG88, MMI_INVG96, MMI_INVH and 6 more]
MACRO MMI_INVG
	CLASS CORE ;
	FOREIGN MMI_INVG 0 0 ;
	SIZE 16.12 BY 6.2 ;
	SYMMETRY X Y ;
	SITE CORE1 ;
	PIN out
		DIRECTION output ;
		USE SIGNAL ;
		PORT
			LAYER M1 ;
			RECT 1.335 2.32 1.615 5.58 ;
			LAYER M1 ;
			RECT 1.315 2.125 1.635 2.32 ;
			LAYER M1 ;
			RECT 2.515 2.305 2.795 5.58 ;
			LAYER M1 ;
			RECT 3.695 2.335 3.975 5.58 ;
			LAYER M1 ;
			RECT 2.5 2.13 2.82 2.305 ;
			LAYER M1 ;
			RECT 3.675 2.13 3.995 2.335 ;
			LAYER M1 ;
			RECT 4.875 2.32 5.155 5.58 ;
			LAYER M1 ;
			RECT 2.5 2.125 3.995 2.13 ;
			LAYER M1 ;
			RECT 4.855 2.125 5.175 2.32 ;
			LAYER M1 ;
			RECT 6.055 2.305 6.335 5.58 ;
			LAYER M1 ;
			RECT 7.235 2.335 7.515 5.58 ;
			LAYER M1 ;
			RECT 6.04 2.13 6.36 2.305 ;
			LAYER M1 ;
			RECT 7.215 2.13 7.535 2.335 ;
			LAYER M1 ;
			RECT 8.415 2.32 8.695 5.58 ;
			LAYER M1 ;
			RECT 6.04 2.125 7.535 2.13 ;
			LAYER M1 ;
			RECT 8.395 2.125 8.715 2.32 ;
			LAYER M1 ;
			RECT 9.595 2.305 9.875 5.58 ;
			LAYER M1 ;
			RECT 10.775 2.335 11.055 5.58 ;
			LAYER M1 ;
			RECT 11.955 2.335 12.235 5.58 ;
			LAYER M1 ;
			RECT 9.58 2.13 9.9 2.305 ;
			LAYER M1 ;
			RECT 10.755 2.13 11.075 2.335 ;
			LAYER M1 ;
			RECT 9.58 2.125 11.075 2.13 ;
			LAYER M1 ;
			RECT 11.935 2.13 12.255 2.335 ;
			LAYER M1 ;
			RECT 13.135 2.305 13.415 5.58 ;
			LAYER M1 ;
			RECT 14.315 2.32 14.595 5.58 ;
			LAYER M1 ;
			RECT 13.11 2.13 13.43 2.305 ;
			LAYER M1 ;
			RECT 11.935 2.125 13.43 2.13 ;
			LAYER M1 ;
			RECT 14.295 2.125 14.615 2.32 ;
			LAYER M1 ;
			RECT 1.315 1.885 14.615 2.125 ;
			LAYER M1 ;
			RECT 1.315 1.64 1.635 1.885 ;
			LAYER M1 ;
			RECT 1.335 0.62 1.615 1.64 ;
			LAYER M1 ;
			RECT 2.5 1.625 2.82 1.885 ;
			LAYER M1 ;
			RECT 3.675 1.655 3.995 1.885 ;
			LAYER M1 ;
			RECT 2.515 0.62 2.795 1.625 ;
			LAYER M1 ;
			RECT 3.695 0.62 3.975 1.655 ;
			LAYER M1 ;
			RECT 4.855 1.64 5.175 1.885 ;
			LAYER M1 ;
			RECT 4.875 0.62 5.155 1.64 ;
			LAYER M1 ;
			RECT 6.04 1.625 6.36 1.885 ;
			LAYER M1 ;
			RECT 7.215 1.655 7.535 1.885 ;
			LAYER M1 ;
			RECT 6.055 0.62 6.335 1.625 ;
			LAYER M1 ;
			RECT 7.235 0.62 7.515 1.655 ;
			LAYER M1 ;
			RECT 8.395 1.64 8.715 1.885 ;
			LAYER M1 ;
			RECT 8.415 0.62 8.695 1.64 ;
			LAYER M1 ;
			RECT 9.58 1.625 9.9 1.885 ;
			LAYER M1 ;
			RECT 10.755 1.655 11.075 1.885 ;
			LAYER M1 ;
			RECT 11.935 1.655 12.255 1.885 ;
			LAYER M1 ;
			RECT 9.595 0.62 9.875 1.625 ;
			LAYER M1 ;
			RECT 10.775 0.62 11.055 1.655 ;
			LAYER M1 ;
			RECT 11.955 0.62 12.235 1.655 ;
			LAYER M1 ;
			RECT 13.11 1.625 13.43 1.885 ;
			LAYER M1 ;
			RECT 14.295 1.64 14.615 1.885 ;
			LAYER M1 ;
			RECT 13.135 0.62 13.415 1.625 ;
			LAYER M1 ;
			RECT 14.315 0.62 14.595 1.64 ;
			LAYER VIA1 ;
			RECT 1.365 2.09 1.585 2.31 ;
			LAYER VIA1 ;
			RECT 2.55 2.075 2.77 2.295 ;
			LAYER VIA1 ;
			RECT 3.725 2.105 3.945 2.325 ;
			LAYER VIA1 ;
			RECT 4.905 2.09 5.125 2.31 ;
			LAYER VIA1 ;
			RECT 6.09 2.075 6.31 2.295 ;
			LAYER VIA1 ;
			RECT 7.265 2.105 7.485 2.325 ;
			LAYER VIA1 ;
			RECT 8.445 2.09 8.665 2.31 ;
			LAYER VIA1 ;
			RECT 9.63 2.075 9.85 2.295 ;
			LAYER VIA1 ;
			RECT 10.805 2.105 11.025 2.325 ;
			LAYER VIA1 ;
			RECT 11.985 2.105 12.205 2.325 ;
			LAYER VIA1 ;
			RECT 13.16 2.075 13.38 2.295 ;
			LAYER VIA1 ;
			RECT 14.345 2.09 14.565 2.31 ;
			LAYER VIA1 ;
			RECT 1.365 1.65 1.585 1.87 ;
			LAYER VIA1 ;
			RECT 2.55 1.635 2.77 1.855 ;
			LAYER VIA1 ;
			RECT 3.725 1.665 3.945 1.885 ;
			LAYER VIA1 ;
			RECT 4.905 1.65 5.125 1.87 ;
			LAYER VIA1 ;
			RECT 6.09 1.635 6.31 1.855 ;
			LAYER VIA1 ;
			RECT 7.265 1.665 7.485 1.885 ;
			LAYER VIA1 ;
			RECT 8.445 1.65 8.665 1.87 ;
			LAYER VIA1 ;
			RECT 9.63 1.635 9.85 1.855 ;
			LAYER VIA1 ;
			RECT 10.805 1.665 11.025 1.885 ;
			LAYER VIA1 ;
			RECT 11.985 1.665 12.205 1.885 ;
			LAYER VIA1 ;
			RECT 13.16 1.635 13.38 1.855 ;
			LAYER VIA1 ;
			RECT 14.345 1.65 14.565 1.87 ;
			LAYER M2 ;
			RECT 0.12 1.85 15.81 2.49 ;
			LAYER M2 ;
			RECT 1.315 1.64 1.635 1.85 ;
			LAYER M2 ;
			RECT 2.5 1.625 2.82 1.85 ;
			LAYER M2 ;
			RECT 3.675 1.655 3.995 1.85 ;
			LAYER M2 ;
			RECT 4.855 1.64 5.175 1.85 ;
			LAYER M2 ;
			RECT 6.04 1.625 6.36 1.85 ;
			LAYER M2 ;
			RECT 7.215 1.655 7.535 1.85 ;
			LAYER M2 ;
			RECT 8.395 1.64 8.715 1.85 ;
			LAYER M2 ;
			RECT 9.58 1.625 9.9 1.85 ;
			LAYER M2 ;
			RECT 10.755 1.655 11.075 1.85 ;
			LAYER M2 ;
			RECT 11.935 1.655 12.255 1.85 ;
			LAYER M2 ;
			RECT 13.11 1.625 13.43 1.85 ;
			LAYER M2 ;
			RECT 14.295 1.64 14.615 1.85 ;
		END
	END out
	PIN GND
		DIRECTION inout ;
		USE GROUND ;
		PORT
			LAYER M1 ;
			RECT 0.155 0.42 0.435 1.575 ;
			LAYER M1 ;
			RECT 0.745 0.42 1.025 1.575 ;
			LAYER M1 ;
			RECT 1.925 0.42 2.205 1.575 ;
			LAYER M1 ;
			RECT 3.105 0.42 3.385 1.575 ;
			LAYER M1 ;
			RECT 4.285 0.42 4.565 1.575 ;
			LAYER M1 ;
			RECT 5.465 0.42 5.745 1.575 ;
			LAYER M1 ;
			RECT 6.645 0.42 6.925 1.575 ;
			LAYER M1 ;
			RECT 7.825 0.42 8.105 1.575 ;
			LAYER M1 ;
			RECT 9.005 0.42 9.285 1.575 ;
			LAYER M1 ;
			RECT 10.185 0.42 10.465 1.575 ;
			LAYER M1 ;
			RECT 11.365 0.42 11.645 1.575 ;
			LAYER M1 ;
			RECT 12.545 0.42 12.825 1.575 ;
			LAYER M1 ;
			RECT 13.725 0.42 14.005 1.575 ;
			LAYER M1 ;
			RECT 14.905 0.42 15.185 1.575 ;
			LAYER M1 ;
			RECT 15.495 0.425 15.775 1.575 ;
			LAYER M1 ;
			RECT 15.495 0.42 16.12 0.425 ;
			LAYER M1 ;
			RECT 0 -0.42 16.12 0.42 ;
			LAYER VIA1 ;
			RECT 0.82 -0.11 1.04 0.11 ;
			LAYER VIA1 ;
			RECT 1.44 -0.11 1.66 0.11 ;
			LAYER VIA1 ;
			RECT 2.06 -0.11 2.28 0.11 ;
			LAYER VIA1 ;
			RECT 2.68 -0.11 2.9 0.11 ;
			LAYER VIA1 ;
			RECT 3.3 -0.11 3.52 0.11 ;
			LAYER VIA1 ;
			RECT 3.92 -0.11 4.14 0.11 ;
			LAYER VIA1 ;
			RECT 4.54 -0.11 4.76 0.11 ;
			LAYER VIA1 ;
			RECT 5.16 -0.11 5.38 0.11 ;
			LAYER VIA1 ;
			RECT 7.02 -0.11 7.24 0.11 ;
			LAYER VIA1 ;
			RECT 7.64 -0.11 7.86 0.11 ;
			LAYER VIA1 ;
			RECT 8.26 -0.11 8.48 0.11 ;
			LAYER VIA1 ;
			RECT 8.88 -0.11 9.1 0.11 ;
			LAYER VIA1 ;
			RECT 9.5 -0.11 9.72 0.11 ;
			LAYER VIA1 ;
			RECT 10.12 -0.11 10.34 0.11 ;
			LAYER VIA1 ;
			RECT 10.74 -0.11 10.96 0.11 ;
			LAYER VIA1 ;
			RECT 11.36 -0.11 11.58 0.11 ;
			LAYER VIA1 ;
			RECT 13.22 -0.11 13.44 0.11 ;
			LAYER VIA1 ;
			RECT 13.84 -0.11 14.06 0.11 ;
			LAYER VIA1 ;
			RECT 14.46 -0.11 14.68 0.11 ;
			LAYER VIA1 ;
			RECT 15.08 -0.11 15.3 0.11 ;
			LAYER VIA1 ;
			RECT 15.7 -0.11 15.92 0.11 ;
			LAYER M2 ;
			RECT 0 -0.42 16.12 0.42 ;
		END
	END GND
	PIN VDD
		DIRECTION inout ;
		USE POWER ;
		PORT
			LAYER M1 ;
			RECT 0 5.78 16.12 6.62 ;
			LAYER M1 ;
			RECT 0.155 3.595 0.435 5.78 ;
			LAYER M1 ;
			RECT 0.745 3.595 1.025 5.78 ;
			LAYER M1 ;
			RECT 1.925 3.595 2.205 5.78 ;
			LAYER M1 ;
			RECT 3.105 3.595 3.385 5.78 ;
			LAYER M1 ;
			RECT 4.285 3.595 4.565 5.78 ;
			LAYER M1 ;
			RECT 5.465 3.595 5.745 5.78 ;
			LAYER M1 ;
			RECT 6.645 3.595 6.925 5.78 ;
			LAYER M1 ;
			RECT 7.825 3.595 8.105 5.78 ;
			LAYER M1 ;
			RECT 9.005 3.595 9.285 5.78 ;
			LAYER M1 ;
			RECT 10.185 3.595 10.465 5.78 ;
			LAYER M1 ;
			RECT 11.365 3.595 11.645 5.78 ;
			LAYER M1 ;
			RECT 12.545 3.595 12.825 5.78 ;
			LAYER M1 ;
			RECT 13.725 3.595 14.005 5.78 ;
			LAYER M1 ;
			RECT 14.905 3.595 15.185 5.78 ;
			LAYER M1 ;
			RECT 15.495 3.595 15.775 5.78 ;
			LAYER VIA1 ;
			RECT 0.82 6.09 1.04 6.31 ;
			LAYER VIA1 ;
			RECT 1.44 6.09 1.66 6.31 ;
			LAYER VIA1 ;
			RECT 2.06 6.09 2.28 6.31 ;
			LAYER VIA1 ;
			RECT 2.68 6.09 2.9 6.31 ;
			LAYER VIA1 ;
			RECT 3.3 6.09 3.52 6.31 ;
			LAYER VIA1 ;
			RECT 3.92 6.09 4.14 6.31 ;
			LAYER VIA1 ;
			RECT 4.54 6.09 4.76 6.31 ;
			LAYER VIA1 ;
			RECT 5.16 6.09 5.38 6.31 ;
			LAYER VIA1 ;
			RECT 7.02 6.09 7.24 6.31 ;
			LAYER VIA1 ;
			RECT 7.64 6.09 7.86 6.31 ;
			LAYER VIA1 ;
			RECT 8.26 6.09 8.48 6.31 ;
			LAYER VIA1 ;
			RECT 8.88 6.09 9.1 6.31 ;
			LAYER VIA1 ;
			RECT 9.5 6.09 9.72 6.31 ;
			LAYER VIA1 ;
			RECT 10.12 6.09 10.34 6.31 ;
			LAYER VIA1 ;
			RECT 10.74 6.09 10.96 6.31 ;
			LAYER VIA1 ;
			RECT 11.36 6.09 11.58 6.31 ;
			LAYER VIA1 ;
			RECT 13.22 6.09 13.44 6.31 ;
			LAYER VIA1 ;
			RECT 13.84 6.09 14.06 6.31 ;
			LAYER VIA1 ;
			RECT 14.46 6.09 14.68 6.31 ;
			LAYER VIA1 ;
			RECT 15.08 6.09 15.3 6.31 ;
			LAYER VIA1 ;
			RECT 15.7 6.09 15.92 6.31 ;
			LAYER M2 ;
			RECT 0 5.78 16.12 6.615 ;
		END
	END VDD
	PIN in
		DIRECTION input ;
		USE SIGNAL ;
		PORT
			LAYER M1 ;
			RECT 1.94 2.75 2.18 3.35 ;
			LAYER M1 ;
			RECT 3.13 2.735 3.37 3.335 ;
			LAYER M1 ;
			RECT 5.48 2.75 5.72 3.35 ;
			LAYER M1 ;
			RECT 6.67 2.735 6.91 3.335 ;
			LAYER M1 ;
			RECT 9.02 2.75 9.26 3.35 ;
			LAYER M1 ;
			RECT 10.21 2.735 10.45 3.335 ;
			LAYER M1 ;
			RECT 12.56 2.735 12.8 3.335 ;
			LAYER M1 ;
			RECT 13.75 2.75 13.99 3.35 ;
			LAYER VIA1 ;
			RECT 1.95 3.065 2.17 3.285 ;
			LAYER VIA1 ;
			RECT 3.14 3.065 3.36 3.285 ;
			LAYER VIA1 ;
			RECT 5.49 3.065 5.71 3.285 ;
			LAYER VIA1 ;
			RECT 6.68 3.065 6.9 3.285 ;
			LAYER VIA1 ;
			RECT 9.03 3.065 9.25 3.285 ;
			LAYER VIA1 ;
			RECT 10.22 3.065 10.44 3.285 ;
			LAYER VIA1 ;
			RECT 12.57 3.065 12.79 3.285 ;
			LAYER VIA1 ;
			RECT 13.76 3.065 13.98 3.285 ;
			LAYER M2 ;
			RECT 0.12 3.29 15.81 3.53 ;
			LAYER M2 ;
			RECT 1.94 3.015 2.18 3.29 ;
			LAYER M2 ;
			RECT 3.13 3.015 3.37 3.29 ;
			LAYER M2 ;
			RECT 5.48 3.015 5.72 3.29 ;
			LAYER M2 ;
			RECT 6.67 3.015 6.91 3.29 ;
			LAYER M2 ;
			RECT 9.02 3.015 9.26 3.29 ;
			LAYER M2 ;
			RECT 10.21 3.015 10.45 3.29 ;
			LAYER M2 ;
			RECT 12.56 3.015 12.8 3.29 ;
			LAYER M2 ;
			RECT 13.75 3.015 13.99 3.29 ;
		END
		ANTENNASIZE 12.012 ;
	END in
	OBS
	END
END MMI_INVG
MACRO MMI_INVG112
	CLASS CORE ;
	FOREIGN MMI_INVG112 0 0 ;
	SIZE 26.66 BY 6.2 ;
	SYMMETRY X Y ;
	SITE CORE1 ;
	PIN out
		DIRECTION output ;
		USE SIGNAL ;
		PORT
			LAYER M1 ;
			RECT 1.335 2.32 1.615 5.58 ;
			LAYER M1 ;
			RECT 1.315 2.125 1.635 2.32 ;
			LAYER M1 ;
			RECT 2.515 2.305 2.795 5.58 ;
			LAYER M1 ;
			RECT 3.695 2.335 3.975 5.58 ;
			LAYER M1 ;
			RECT 2.5 2.13 2.82 2.305 ;
			LAYER M1 ;
			RECT 3.675 2.13 3.995 2.335 ;
			LAYER M1 ;
			RECT 4.875 2.32 5.155 5.58 ;
			LAYER M1 ;
			RECT 2.5 2.125 3.995 2.13 ;
			LAYER M1 ;
			RECT 4.855 2.125 5.175 2.32 ;
			LAYER M1 ;
			RECT 6.055 2.305 6.335 5.58 ;
			LAYER M1 ;
			RECT 7.235 2.335 7.515 5.58 ;
			LAYER M1 ;
			RECT 6.04 2.13 6.36 2.305 ;
			LAYER M1 ;
			RECT 7.215 2.13 7.535 2.335 ;
			LAYER M1 ;
			RECT 8.415 2.32 8.695 5.58 ;
			LAYER M1 ;
			RECT 6.04 2.125 7.535 2.13 ;
			LAYER M1 ;
			RECT 8.395 2.125 8.715 2.32 ;
			LAYER M1 ;
			RECT 9.595 2.305 9.875 5.58 ;
			LAYER M1 ;
			RECT 10.775 2.335 11.055 5.58 ;
			LAYER M1 ;
			RECT 9.58 2.13 9.9 2.305 ;
			LAYER M1 ;
			RECT 10.755 2.13 11.075 2.335 ;
			LAYER M1 ;
			RECT 11.955 2.32 12.235 5.58 ;
			LAYER M1 ;
			RECT 9.58 2.125 11.075 2.13 ;
			LAYER M1 ;
			RECT 11.935 2.125 12.255 2.32 ;
			LAYER M1 ;
			RECT 13.135 2.305 13.415 5.58 ;
			LAYER M1 ;
			RECT 14.315 2.335 14.595 5.58 ;
			LAYER M1 ;
			RECT 13.12 2.13 13.44 2.305 ;
			LAYER M1 ;
			RECT 14.295 2.13 14.615 2.335 ;
			LAYER M1 ;
			RECT 15.495 2.32 15.775 5.58 ;
			LAYER M1 ;
			RECT 13.12 2.125 14.615 2.13 ;
			LAYER M1 ;
			RECT 15.475 2.125 15.795 2.32 ;
			LAYER M1 ;
			RECT 16.675 2.305 16.955 5.58 ;
			LAYER M1 ;
			RECT 17.855 2.335 18.135 5.58 ;
			LAYER M1 ;
			RECT 16.66 2.13 16.98 2.305 ;
			LAYER M1 ;
			RECT 17.835 2.13 18.155 2.335 ;
			LAYER M1 ;
			RECT 19.035 2.32 19.315 5.58 ;
			LAYER M1 ;
			RECT 16.66 2.125 18.155 2.13 ;
			LAYER M1 ;
			RECT 19.015 2.125 19.335 2.32 ;
			LAYER M1 ;
			RECT 20.215 2.305 20.495 5.58 ;
			LAYER M1 ;
			RECT 21.395 2.335 21.675 5.58 ;
			LAYER M1 ;
			RECT 22.575 2.335 22.855 5.58 ;
			LAYER M1 ;
			RECT 20.2 2.13 20.52 2.305 ;
			LAYER M1 ;
			RECT 21.375 2.13 21.695 2.335 ;
			LAYER M1 ;
			RECT 20.2 2.125 21.695 2.13 ;
			LAYER M1 ;
			RECT 22.555 2.13 22.875 2.335 ;
			LAYER M1 ;
			RECT 23.755 2.305 24.035 5.58 ;
			LAYER M1 ;
			RECT 24.935 2.32 25.215 5.58 ;
			LAYER M1 ;
			RECT 23.73 2.13 24.05 2.305 ;
			LAYER M1 ;
			RECT 22.555 2.125 24.05 2.13 ;
			LAYER M1 ;
			RECT 24.915 2.125 25.235 2.32 ;
			LAYER M1 ;
			RECT 1.315 1.885 25.235 2.125 ;
			LAYER M1 ;
			RECT 1.315 1.64 1.635 1.885 ;
			LAYER M1 ;
			RECT 1.335 0.62 1.615 1.64 ;
			LAYER M1 ;
			RECT 2.5 1.625 2.82 1.885 ;
			LAYER M1 ;
			RECT 3.675 1.655 3.995 1.885 ;
			LAYER M1 ;
			RECT 2.515 0.62 2.795 1.625 ;
			LAYER M1 ;
			RECT 3.695 0.62 3.975 1.655 ;
			LAYER M1 ;
			RECT 4.855 1.64 5.175 1.885 ;
			LAYER M1 ;
			RECT 4.875 0.62 5.155 1.64 ;
			LAYER M1 ;
			RECT 6.04 1.625 6.36 1.885 ;
			LAYER M1 ;
			RECT 7.215 1.655 7.535 1.885 ;
			LAYER M1 ;
			RECT 6.055 0.62 6.335 1.625 ;
			LAYER M1 ;
			RECT 7.235 0.62 7.515 1.655 ;
			LAYER M1 ;
			RECT 8.395 1.64 8.715 1.885 ;
			LAYER M1 ;
			RECT 8.415 0.62 8.695 1.64 ;
			LAYER M1 ;
			RECT 9.58 1.625 9.9 1.885 ;
			LAYER M1 ;
			RECT 10.755 1.655 11.075 1.885 ;
			LAYER M1 ;
			RECT 9.595 0.62 9.875 1.625 ;
			LAYER M1 ;
			RECT 10.775 0.62 11.055 1.655 ;
			LAYER M1 ;
			RECT 11.935 1.64 12.255 1.885 ;
			LAYER M1 ;
			RECT 11.955 0.62 12.235 1.64 ;
			LAYER M1 ;
			RECT 13.12 1.625 13.44 1.885 ;
			LAYER M1 ;
			RECT 14.295 1.655 14.615 1.885 ;
			LAYER M1 ;
			RECT 13.135 0.62 13.415 1.625 ;
			LAYER M1 ;
			RECT 14.315 0.62 14.595 1.655 ;
			LAYER M1 ;
			RECT 15.475 1.64 15.795 1.885 ;
			LAYER M1 ;
			RECT 15.495 0.62 15.775 1.64 ;
			LAYER M1 ;
			RECT 16.66 1.625 16.98 1.885 ;
			LAYER M1 ;
			RECT 17.835 1.655 18.155 1.885 ;
			LAYER M1 ;
			RECT 16.675 0.62 16.955 1.625 ;
			LAYER M1 ;
			RECT 17.855 0.62 18.135 1.655 ;
			LAYER M1 ;
			RECT 19.015 1.64 19.335 1.885 ;
			LAYER M1 ;
			RECT 19.035 0.62 19.315 1.64 ;
			LAYER M1 ;
			RECT 20.2 1.625 20.52 1.885 ;
			LAYER M1 ;
			RECT 21.375 1.655 21.695 1.885 ;
			LAYER M1 ;
			RECT 22.555 1.655 22.875 1.885 ;
			LAYER M1 ;
			RECT 20.215 0.62 20.495 1.625 ;
			LAYER M1 ;
			RECT 21.395 0.62 21.675 1.655 ;
			LAYER M1 ;
			RECT 22.575 0.62 22.855 1.655 ;
			LAYER M1 ;
			RECT 23.73 1.625 24.05 1.885 ;
			LAYER M1 ;
			RECT 24.915 1.64 25.235 1.885 ;
			LAYER M1 ;
			RECT 23.755 0.62 24.035 1.625 ;
			LAYER M1 ;
			RECT 24.935 0.62 25.215 1.64 ;
			LAYER VIA1 ;
			RECT 1.365 2.09 1.585 2.31 ;
			LAYER VIA1 ;
			RECT 2.55 2.075 2.77 2.295 ;
			LAYER VIA1 ;
			RECT 3.725 2.105 3.945 2.325 ;
			LAYER VIA1 ;
			RECT 4.905 2.09 5.125 2.31 ;
			LAYER VIA1 ;
			RECT 6.09 2.075 6.31 2.295 ;
			LAYER VIA1 ;
			RECT 7.265 2.105 7.485 2.325 ;
			LAYER VIA1 ;
			RECT 8.445 2.09 8.665 2.31 ;
			LAYER VIA1 ;
			RECT 9.63 2.075 9.85 2.295 ;
			LAYER VIA1 ;
			RECT 10.805 2.105 11.025 2.325 ;
			LAYER VIA1 ;
			RECT 11.985 2.09 12.205 2.31 ;
			LAYER VIA1 ;
			RECT 13.17 2.075 13.39 2.295 ;
			LAYER VIA1 ;
			RECT 14.345 2.105 14.565 2.325 ;
			LAYER VIA1 ;
			RECT 15.525 2.09 15.745 2.31 ;
			LAYER VIA1 ;
			RECT 16.71 2.075 16.93 2.295 ;
			LAYER VIA1 ;
			RECT 17.885 2.105 18.105 2.325 ;
			LAYER VIA1 ;
			RECT 19.065 2.09 19.285 2.31 ;
			LAYER VIA1 ;
			RECT 20.25 2.075 20.47 2.295 ;
			LAYER VIA1 ;
			RECT 21.425 2.105 21.645 2.325 ;
			LAYER VIA1 ;
			RECT 22.605 2.105 22.825 2.325 ;
			LAYER VIA1 ;
			RECT 23.78 2.075 24 2.295 ;
			LAYER VIA1 ;
			RECT 24.965 2.09 25.185 2.31 ;
			LAYER VIA1 ;
			RECT 1.365 1.65 1.585 1.87 ;
			LAYER VIA1 ;
			RECT 2.55 1.635 2.77 1.855 ;
			LAYER VIA1 ;
			RECT 3.725 1.665 3.945 1.885 ;
			LAYER VIA1 ;
			RECT 4.905 1.65 5.125 1.87 ;
			LAYER VIA1 ;
			RECT 6.09 1.635 6.31 1.855 ;
			LAYER VIA1 ;
			RECT 7.265 1.665 7.485 1.885 ;
			LAYER VIA1 ;
			RECT 8.445 1.65 8.665 1.87 ;
			LAYER VIA1 ;
			RECT 9.63 1.635 9.85 1.855 ;
			LAYER VIA1 ;
			RECT 10.805 1.665 11.025 1.885 ;
			LAYER VIA1 ;
			RECT 11.985 1.65 12.205 1.87 ;
			LAYER VIA1 ;
			RECT 13.17 1.635 13.39 1.855 ;
			LAYER VIA1 ;
			RECT 14.345 1.665 14.565 1.885 ;
			LAYER VIA1 ;
			RECT 15.525 1.65 15.745 1.87 ;
			LAYER VIA1 ;
			RECT 16.71 1.635 16.93 1.855 ;
			LAYER VIA1 ;
			RECT 17.885 1.665 18.105 1.885 ;
			LAYER VIA1 ;
			RECT 19.065 1.65 19.285 1.87 ;
			LAYER VIA1 ;
			RECT 20.25 1.635 20.47 1.855 ;
			LAYER VIA1 ;
			RECT 21.425 1.665 21.645 1.885 ;
			LAYER VIA1 ;
			RECT 22.605 1.665 22.825 1.885 ;
			LAYER VIA1 ;
			RECT 23.78 1.635 24 1.855 ;
			LAYER VIA1 ;
			RECT 24.965 1.65 25.185 1.87 ;
			LAYER M2 ;
			RECT 0.12 0.825 26.43 2.745 ;
		END
	END out
	PIN GND
		DIRECTION inout ;
		USE GROUND ;
		PORT
			LAYER M1 ;
			RECT 0.155 0.42 0.435 1.575 ;
			LAYER M1 ;
			RECT 0.745 0.42 1.025 1.575 ;
			LAYER M1 ;
			RECT 1.925 0.42 2.205 1.575 ;
			LAYER M1 ;
			RECT 3.105 0.42 3.385 1.575 ;
			LAYER M1 ;
			RECT 4.285 0.42 4.565 1.575 ;
			LAYER M1 ;
			RECT 5.465 0.42 5.745 1.575 ;
			LAYER M1 ;
			RECT 6.645 0.42 6.925 1.575 ;
			LAYER M1 ;
			RECT 7.825 0.42 8.105 1.575 ;
			LAYER M1 ;
			RECT 9.005 0.42 9.285 1.575 ;
			LAYER M1 ;
			RECT 10.185 0.42 10.465 1.575 ;
			LAYER M1 ;
			RECT 11.365 0.42 11.645 1.575 ;
			LAYER M1 ;
			RECT 12.545 0.42 12.825 1.575 ;
			LAYER M1 ;
			RECT 13.725 0.42 14.005 1.575 ;
			LAYER M1 ;
			RECT 14.905 0.42 15.185 1.575 ;
			LAYER M1 ;
			RECT 16.085 0.42 16.365 1.575 ;
			LAYER M1 ;
			RECT 17.265 0.42 17.545 1.575 ;
			LAYER M1 ;
			RECT 18.445 0.42 18.725 1.575 ;
			LAYER M1 ;
			RECT 19.625 0.42 19.905 1.575 ;
			LAYER M1 ;
			RECT 20.805 0.42 21.085 1.575 ;
			LAYER M1 ;
			RECT 21.985 0.42 22.265 1.575 ;
			LAYER M1 ;
			RECT 23.165 0.42 23.445 1.575 ;
			LAYER M1 ;
			RECT 24.345 0.42 24.625 1.575 ;
			LAYER M1 ;
			RECT 25.525 0.42 25.805 1.575 ;
			LAYER M1 ;
			RECT 26.115 0.42 26.395 1.575 ;
			LAYER M1 ;
			RECT 0 0.35 26.395 0.42 ;
			LAYER M1 ;
			RECT 0 -0.42 26.66 0.35 ;
			LAYER VIA1 ;
			RECT 0.82 -0.11 1.04 0.11 ;
			LAYER VIA1 ;
			RECT 1.44 -0.11 1.66 0.11 ;
			LAYER VIA1 ;
			RECT 2.06 -0.11 2.28 0.11 ;
			LAYER VIA1 ;
			RECT 2.68 -0.11 2.9 0.11 ;
			LAYER VIA1 ;
			RECT 3.3 -0.11 3.52 0.11 ;
			LAYER VIA1 ;
			RECT 3.92 -0.11 4.14 0.11 ;
			LAYER VIA1 ;
			RECT 4.54 -0.11 4.76 0.11 ;
			LAYER VIA1 ;
			RECT 5.16 -0.11 5.38 0.11 ;
			LAYER VIA1 ;
			RECT 7.02 -0.11 7.24 0.11 ;
			LAYER VIA1 ;
			RECT 7.64 -0.11 7.86 0.11 ;
			LAYER VIA1 ;
			RECT 8.26 -0.11 8.48 0.11 ;
			LAYER VIA1 ;
			RECT 8.88 -0.11 9.1 0.11 ;
			LAYER VIA1 ;
			RECT 9.5 -0.11 9.72 0.11 ;
			LAYER VIA1 ;
			RECT 10.12 -0.11 10.34 0.11 ;
			LAYER VIA1 ;
			RECT 10.74 -0.11 10.96 0.11 ;
			LAYER VIA1 ;
			RECT 11.36 -0.11 11.58 0.11 ;
			LAYER VIA1 ;
			RECT 13.22 -0.11 13.44 0.11 ;
			LAYER VIA1 ;
			RECT 13.84 -0.11 14.06 0.11 ;
			LAYER VIA1 ;
			RECT 14.46 -0.11 14.68 0.11 ;
			LAYER VIA1 ;
			RECT 15.08 -0.11 15.3 0.11 ;
			LAYER VIA1 ;
			RECT 15.7 -0.11 15.92 0.11 ;
			LAYER VIA1 ;
			RECT 16.32 -0.11 16.54 0.11 ;
			LAYER VIA1 ;
			RECT 16.94 -0.11 17.16 0.11 ;
			LAYER VIA1 ;
			RECT 17.56 -0.11 17.78 0.11 ;
			LAYER VIA1 ;
			RECT 19.42 -0.11 19.64 0.11 ;
			LAYER VIA1 ;
			RECT 20.04 -0.11 20.26 0.11 ;
			LAYER VIA1 ;
			RECT 20.66 -0.11 20.88 0.11 ;
			LAYER VIA1 ;
			RECT 21.28 -0.11 21.5 0.11 ;
			LAYER VIA1 ;
			RECT 21.9 -0.11 22.12 0.11 ;
			LAYER VIA1 ;
			RECT 22.52 -0.11 22.74 0.11 ;
			LAYER VIA1 ;
			RECT 23.14 -0.11 23.36 0.11 ;
			LAYER VIA1 ;
			RECT 23.76 -0.11 23.98 0.11 ;
			LAYER VIA1 ;
			RECT 25.62 -0.11 25.84 0.11 ;
			LAYER VIA1 ;
			RECT 26.24 -0.11 26.46 0.11 ;
			LAYER M2 ;
			RECT 0 -0.42 26.66 0.42 ;
		END
	END GND
	PIN VDD
		DIRECTION inout ;
		USE POWER ;
		PORT
			LAYER M1 ;
			RECT 0 5.78 26.66 6.62 ;
			LAYER M1 ;
			RECT 0.155 3.595 0.435 5.78 ;
			LAYER M1 ;
			RECT 0.745 3.595 1.025 5.78 ;
			LAYER M1 ;
			RECT 1.925 3.595 2.205 5.78 ;
			LAYER M1 ;
			RECT 3.105 3.595 3.385 5.78 ;
			LAYER M1 ;
			RECT 4.285 3.595 4.565 5.78 ;
			LAYER M1 ;
			RECT 5.465 3.595 5.745 5.78 ;
			LAYER M1 ;
			RECT 6.645 3.595 6.925 5.78 ;
			LAYER M1 ;
			RECT 7.825 3.595 8.105 5.78 ;
			LAYER M1 ;
			RECT 9.005 3.595 9.285 5.78 ;
			LAYER M1 ;
			RECT 10.185 3.595 10.465 5.78 ;
			LAYER M1 ;
			RECT 11.365 3.595 11.645 5.78 ;
			LAYER M1 ;
			RECT 12.545 3.595 12.825 5.78 ;
			LAYER M1 ;
			RECT 13.725 3.595 14.005 5.78 ;
			LAYER M1 ;
			RECT 14.905 3.595 15.185 5.78 ;
			LAYER M1 ;
			RECT 16.085 3.595 16.365 5.78 ;
			LAYER M1 ;
			RECT 17.265 3.595 17.545 5.78 ;
			LAYER M1 ;
			RECT 18.445 3.595 18.725 5.78 ;
			LAYER M1 ;
			RECT 19.625 3.595 19.905 5.78 ;
			LAYER M1 ;
			RECT 20.805 3.595 21.085 5.78 ;
			LAYER M1 ;
			RECT 21.985 3.595 22.265 5.78 ;
			LAYER M1 ;
			RECT 23.165 3.595 23.445 5.78 ;
			LAYER M1 ;
			RECT 24.345 3.595 24.625 5.78 ;
			LAYER M1 ;
			RECT 25.525 3.595 25.805 5.78 ;
			LAYER M1 ;
			RECT 26.115 3.595 26.395 5.78 ;
			LAYER VIA1 ;
			RECT 0.82 6.09 1.04 6.31 ;
			LAYER VIA1 ;
			RECT 1.44 6.09 1.66 6.31 ;
			LAYER VIA1 ;
			RECT 2.06 6.09 2.28 6.31 ;
			LAYER VIA1 ;
			RECT 2.68 6.09 2.9 6.31 ;
			LAYER VIA1 ;
			RECT 3.3 6.09 3.52 6.31 ;
			LAYER VIA1 ;
			RECT 3.92 6.09 4.14 6.31 ;
			LAYER VIA1 ;
			RECT 4.54 6.09 4.76 6.31 ;
			LAYER VIA1 ;
			RECT 5.16 6.09 5.38 6.31 ;
			LAYER VIA1 ;
			RECT 7.02 6.09 7.24 6.31 ;
			LAYER VIA1 ;
			RECT 7.64 6.09 7.86 6.31 ;
			LAYER VIA1 ;
			RECT 8.26 6.09 8.48 6.31 ;
			LAYER VIA1 ;
			RECT 8.88 6.09 9.1 6.31 ;
			LAYER VIA1 ;
			RECT 9.5 6.09 9.72 6.31 ;
			LAYER VIA1 ;
			RECT 10.12 6.09 10.34 6.31 ;
			LAYER VIA1 ;
			RECT 10.74 6.09 10.96 6.31 ;
			LAYER VIA1 ;
			RECT 11.36 6.09 11.58 6.31 ;
			LAYER VIA1 ;
			RECT 13.22 6.09 13.44 6.31 ;
			LAYER VIA1 ;
			RECT 13.84 6.09 14.06 6.31 ;
			LAYER VIA1 ;
			RECT 14.46 6.09 14.68 6.31 ;
			LAYER VIA1 ;
			RECT 15.08 6.09 15.3 6.31 ;
			LAYER VIA1 ;
			RECT 15.7 6.09 15.92 6.31 ;
			LAYER VIA1 ;
			RECT 16.32 6.09 16.54 6.31 ;
			LAYER VIA1 ;
			RECT 16.94 6.09 17.16 6.31 ;
			LAYER VIA1 ;
			RECT 17.56 6.09 17.78 6.31 ;
			LAYER VIA1 ;
			RECT 19.42 6.09 19.64 6.31 ;
			LAYER VIA1 ;
			RECT 20.04 6.09 20.26 6.31 ;
			LAYER VIA1 ;
			RECT 20.66 6.09 20.88 6.31 ;
			LAYER VIA1 ;
			RECT 21.28 6.09 21.5 6.31 ;
			LAYER VIA1 ;
			RECT 21.9 6.09 22.12 6.31 ;
			LAYER VIA1 ;
			RECT 22.52 6.09 22.74 6.31 ;
			LAYER VIA1 ;
			RECT 23.14 6.09 23.36 6.31 ;
			LAYER VIA1 ;
			RECT 23.76 6.09 23.98 6.31 ;
			LAYER VIA1 ;
			RECT 25.62 6.09 25.84 6.31 ;
			LAYER VIA1 ;
			RECT 26.24 6.09 26.46 6.31 ;
			LAYER M2 ;
			RECT 0 5.78 26.66 6.615 ;
		END
	END VDD
	PIN in
		DIRECTION input ;
		USE SIGNAL ;
		PORT
			LAYER M1 ;
			RECT 1.94 2.75 2.18 3.35 ;
			LAYER M1 ;
			RECT 3.13 2.735 3.37 3.335 ;
			LAYER M1 ;
			RECT 5.48 2.75 5.72 3.35 ;
			LAYER M1 ;
			RECT 6.67 2.735 6.91 3.335 ;
			LAYER M1 ;
			RECT 9.02 2.75 9.26 3.35 ;
			LAYER M1 ;
			RECT 10.21 2.735 10.45 3.335 ;
			LAYER M1 ;
			RECT 12.56 2.75 12.8 3.35 ;
			LAYER M1 ;
			RECT 13.75 2.735 13.99 3.335 ;
			LAYER M1 ;
			RECT 16.1 2.75 16.34 3.35 ;
			LAYER M1 ;
			RECT 17.29 2.735 17.53 3.335 ;
			LAYER M1 ;
			RECT 19.64 2.75 19.88 3.35 ;
			LAYER M1 ;
			RECT 20.83 2.735 21.07 3.335 ;
			LAYER M1 ;
			RECT 23.18 2.735 23.42 3.335 ;
			LAYER M1 ;
			RECT 24.37 2.75 24.61 3.35 ;
			LAYER VIA1 ;
			RECT 1.95 3.065 2.17 3.285 ;
			LAYER VIA1 ;
			RECT 3.14 3.065 3.36 3.285 ;
			LAYER VIA1 ;
			RECT 5.49 3.065 5.71 3.285 ;
			LAYER VIA1 ;
			RECT 6.68 3.065 6.9 3.285 ;
			LAYER VIA1 ;
			RECT 9.03 3.065 9.25 3.285 ;
			LAYER VIA1 ;
			RECT 10.22 3.065 10.44 3.285 ;
			LAYER VIA1 ;
			RECT 12.57 3.065 12.79 3.285 ;
			LAYER VIA1 ;
			RECT 13.76 3.065 13.98 3.285 ;
			LAYER VIA1 ;
			RECT 16.11 3.065 16.33 3.285 ;
			LAYER VIA1 ;
			RECT 17.3 3.065 17.52 3.285 ;
			LAYER VIA1 ;
			RECT 19.65 3.065 19.87 3.285 ;
			LAYER VIA1 ;
			RECT 20.84 3.065 21.06 3.285 ;
			LAYER VIA1 ;
			RECT 23.19 3.065 23.41 3.285 ;
			LAYER VIA1 ;
			RECT 24.38 3.065 24.6 3.285 ;
			LAYER M2 ;
			RECT 0.12 3.29 26.43 3.53 ;
			LAYER M2 ;
			RECT 1.94 3.015 2.18 3.29 ;
			LAYER M2 ;
			RECT 3.13 3.015 3.37 3.29 ;
			LAYER M2 ;
			RECT 5.48 3.015 5.72 3.29 ;
			LAYER M2 ;
			RECT 6.67 3.015 6.91 3.29 ;
			LAYER M2 ;
			RECT 9.02 3.015 9.26 3.29 ;
			LAYER M2 ;
			RECT 10.21 3.015 10.45 3.29 ;
			LAYER M2 ;
			RECT 12.56 3.015 12.8 3.29 ;
			LAYER M2 ;
			RECT 13.75 3.015 13.99 3.29 ;
			LAYER M2 ;
			RECT 16.1 3.015 16.34 3.29 ;
			LAYER M2 ;
			RECT 17.29 3.015 17.53 3.29 ;
			LAYER M2 ;
			RECT 19.64 3.015 19.88 3.29 ;
			LAYER M2 ;
			RECT 20.83 3.015 21.07 3.29 ;
			LAYER M2 ;
			RECT 23.18 3.015 23.42 3.29 ;
			LAYER M2 ;
			RECT 24.37 3.015 24.61 3.29 ;
		END
		ANTENNASIZE 20.328 ;
	END in
	OBS
	END
END MMI_INVG112
MACRO MMI_INVG80
	CLASS CORE ;
	FOREIGN MMI_INVG80 0 0 ;
	SIZE 19.84 BY 6.2 ;
	SYMMETRY X Y ;
	SITE CORE1 ;
	PIN out
		DIRECTION output ;
		USE SIGNAL ;
		PORT
			LAYER M1 ;
			RECT 1.335 2.32 1.615 5.58 ;
			LAYER M1 ;
			RECT 1.315 2.125 1.635 2.32 ;
			LAYER M1 ;
			RECT 2.515 2.305 2.795 5.58 ;
			LAYER M1 ;
			RECT 3.695 2.335 3.975 5.58 ;
			LAYER M1 ;
			RECT 2.5 2.13 2.82 2.305 ;
			LAYER M1 ;
			RECT 3.675 2.13 3.995 2.335 ;
			LAYER M1 ;
			RECT 4.875 2.32 5.155 5.58 ;
			LAYER M1 ;
			RECT 2.5 2.125 3.995 2.13 ;
			LAYER M1 ;
			RECT 4.855 2.125 5.175 2.32 ;
			LAYER M1 ;
			RECT 6.055 2.305 6.335 5.58 ;
			LAYER M1 ;
			RECT 7.235 2.335 7.515 5.58 ;
			LAYER M1 ;
			RECT 6.04 2.13 6.36 2.305 ;
			LAYER M1 ;
			RECT 7.215 2.13 7.535 2.335 ;
			LAYER M1 ;
			RECT 8.415 2.32 8.695 5.58 ;
			LAYER M1 ;
			RECT 6.04 2.125 7.535 2.13 ;
			LAYER M1 ;
			RECT 8.395 2.125 8.715 2.32 ;
			LAYER M1 ;
			RECT 9.595 2.305 9.875 5.58 ;
			LAYER M1 ;
			RECT 10.775 2.335 11.055 5.58 ;
			LAYER M1 ;
			RECT 9.58 2.13 9.9 2.305 ;
			LAYER M1 ;
			RECT 10.755 2.13 11.075 2.335 ;
			LAYER M1 ;
			RECT 11.955 2.32 12.235 5.58 ;
			LAYER M1 ;
			RECT 9.58 2.125 11.075 2.13 ;
			LAYER M1 ;
			RECT 11.935 2.125 12.255 2.32 ;
			LAYER M1 ;
			RECT 13.135 2.305 13.415 5.58 ;
			LAYER M1 ;
			RECT 14.315 2.335 14.595 5.58 ;
			LAYER M1 ;
			RECT 15.495 2.335 15.775 5.58 ;
			LAYER M1 ;
			RECT 13.12 2.13 13.44 2.305 ;
			LAYER M1 ;
			RECT 14.295 2.13 14.615 2.335 ;
			LAYER M1 ;
			RECT 13.12 2.125 14.615 2.13 ;
			LAYER M1 ;
			RECT 15.475 2.13 15.795 2.335 ;
			LAYER M1 ;
			RECT 16.675 2.305 16.955 5.58 ;
			LAYER M1 ;
			RECT 17.855 2.32 18.135 5.58 ;
			LAYER M1 ;
			RECT 16.65 2.13 16.97 2.305 ;
			LAYER M1 ;
			RECT 15.475 2.125 16.97 2.13 ;
			LAYER M1 ;
			RECT 17.835 2.125 18.155 2.32 ;
			LAYER M1 ;
			RECT 1.315 1.885 18.155 2.125 ;
			LAYER M1 ;
			RECT 1.315 1.64 1.635 1.885 ;
			LAYER M1 ;
			RECT 1.335 0.62 1.615 1.64 ;
			LAYER M1 ;
			RECT 2.5 1.625 2.82 1.885 ;
			LAYER M1 ;
			RECT 3.675 1.655 3.995 1.885 ;
			LAYER M1 ;
			RECT 2.515 0.62 2.795 1.625 ;
			LAYER M1 ;
			RECT 3.695 0.62 3.975 1.655 ;
			LAYER M1 ;
			RECT 4.855 1.64 5.175 1.885 ;
			LAYER M1 ;
			RECT 4.875 0.62 5.155 1.64 ;
			LAYER M1 ;
			RECT 6.04 1.625 6.36 1.885 ;
			LAYER M1 ;
			RECT 7.215 1.655 7.535 1.885 ;
			LAYER M1 ;
			RECT 6.055 0.62 6.335 1.625 ;
			LAYER M1 ;
			RECT 7.235 0.62 7.515 1.655 ;
			LAYER M1 ;
			RECT 8.395 1.64 8.715 1.885 ;
			LAYER M1 ;
			RECT 8.415 0.62 8.695 1.64 ;
			LAYER M1 ;
			RECT 9.58 1.625 9.9 1.885 ;
			LAYER M1 ;
			RECT 10.755 1.655 11.075 1.885 ;
			LAYER M1 ;
			RECT 9.595 0.62 9.875 1.625 ;
			LAYER M1 ;
			RECT 10.775 0.62 11.055 1.655 ;
			LAYER M1 ;
			RECT 11.935 1.64 12.255 1.885 ;
			LAYER M1 ;
			RECT 11.955 0.62 12.235 1.64 ;
			LAYER M1 ;
			RECT 13.12 1.625 13.44 1.885 ;
			LAYER M1 ;
			RECT 14.295 1.655 14.615 1.885 ;
			LAYER M1 ;
			RECT 15.475 1.655 15.795 1.885 ;
			LAYER M1 ;
			RECT 13.135 0.62 13.415 1.625 ;
			LAYER M1 ;
			RECT 14.315 0.62 14.595 1.655 ;
			LAYER M1 ;
			RECT 15.495 0.62 15.775 1.655 ;
			LAYER M1 ;
			RECT 16.65 1.625 16.97 1.885 ;
			LAYER M1 ;
			RECT 17.835 1.64 18.155 1.885 ;
			LAYER M1 ;
			RECT 16.675 0.62 16.955 1.625 ;
			LAYER M1 ;
			RECT 17.855 0.62 18.135 1.64 ;
			LAYER VIA1 ;
			RECT 1.365 2.09 1.585 2.31 ;
			LAYER VIA1 ;
			RECT 2.55 2.075 2.77 2.295 ;
			LAYER VIA1 ;
			RECT 3.725 2.105 3.945 2.325 ;
			LAYER VIA1 ;
			RECT 4.905 2.09 5.125 2.31 ;
			LAYER VIA1 ;
			RECT 6.09 2.075 6.31 2.295 ;
			LAYER VIA1 ;
			RECT 7.265 2.105 7.485 2.325 ;
			LAYER VIA1 ;
			RECT 8.445 2.09 8.665 2.31 ;
			LAYER VIA1 ;
			RECT 9.63 2.075 9.85 2.295 ;
			LAYER VIA1 ;
			RECT 10.805 2.105 11.025 2.325 ;
			LAYER VIA1 ;
			RECT 11.985 2.09 12.205 2.31 ;
			LAYER VIA1 ;
			RECT 13.17 2.075 13.39 2.295 ;
			LAYER VIA1 ;
			RECT 14.345 2.105 14.565 2.325 ;
			LAYER VIA1 ;
			RECT 15.525 2.105 15.745 2.325 ;
			LAYER VIA1 ;
			RECT 16.7 2.075 16.92 2.295 ;
			LAYER VIA1 ;
			RECT 17.885 2.09 18.105 2.31 ;
			LAYER VIA1 ;
			RECT 1.365 1.65 1.585 1.87 ;
			LAYER VIA1 ;
			RECT 2.55 1.635 2.77 1.855 ;
			LAYER VIA1 ;
			RECT 3.725 1.665 3.945 1.885 ;
			LAYER VIA1 ;
			RECT 4.905 1.65 5.125 1.87 ;
			LAYER VIA1 ;
			RECT 6.09 1.635 6.31 1.855 ;
			LAYER VIA1 ;
			RECT 7.265 1.665 7.485 1.885 ;
			LAYER VIA1 ;
			RECT 8.445 1.65 8.665 1.87 ;
			LAYER VIA1 ;
			RECT 9.63 1.635 9.85 1.855 ;
			LAYER VIA1 ;
			RECT 10.805 1.665 11.025 1.885 ;
			LAYER VIA1 ;
			RECT 11.985 1.65 12.205 1.87 ;
			LAYER VIA1 ;
			RECT 13.17 1.635 13.39 1.855 ;
			LAYER VIA1 ;
			RECT 14.345 1.665 14.565 1.885 ;
			LAYER VIA1 ;
			RECT 15.525 1.665 15.745 1.885 ;
			LAYER VIA1 ;
			RECT 16.7 1.635 16.92 1.855 ;
			LAYER VIA1 ;
			RECT 17.885 1.65 18.105 1.87 ;
			LAYER M2 ;
			RECT 3.675 2.325 3.995 2.335 ;
			LAYER M2 ;
			RECT 7.215 2.325 7.535 2.335 ;
			LAYER M2 ;
			RECT 10.755 2.325 11.075 2.335 ;
			LAYER M2 ;
			RECT 14.295 2.325 14.615 2.335 ;
			LAYER M2 ;
			RECT 15.475 2.325 15.795 2.335 ;
			LAYER M2 ;
			RECT 0.12 1.205 19.35 2.325 ;
		END
	END out
	PIN GND
		DIRECTION inout ;
		USE GROUND ;
		PORT
			LAYER M1 ;
			RECT 0.155 0.42 0.435 1.575 ;
			LAYER M1 ;
			RECT 0.745 0.42 1.025 1.575 ;
			LAYER M1 ;
			RECT 1.925 0.42 2.205 1.575 ;
			LAYER M1 ;
			RECT 3.105 0.42 3.385 1.575 ;
			LAYER M1 ;
			RECT 4.285 0.42 4.565 1.575 ;
			LAYER M1 ;
			RECT 5.465 0.42 5.745 1.575 ;
			LAYER M1 ;
			RECT 6.645 0.42 6.925 1.575 ;
			LAYER M1 ;
			RECT 7.825 0.42 8.105 1.575 ;
			LAYER M1 ;
			RECT 9.005 0.42 9.285 1.575 ;
			LAYER M1 ;
			RECT 10.185 0.42 10.465 1.575 ;
			LAYER M1 ;
			RECT 11.365 0.42 11.645 1.575 ;
			LAYER M1 ;
			RECT 12.545 0.42 12.825 1.575 ;
			LAYER M1 ;
			RECT 13.725 0.42 14.005 1.575 ;
			LAYER M1 ;
			RECT 14.905 0.42 15.185 1.575 ;
			LAYER M1 ;
			RECT 16.085 0.42 16.365 1.575 ;
			LAYER M1 ;
			RECT 17.265 0.42 17.545 1.575 ;
			LAYER M1 ;
			RECT 18.445 0.42 18.725 1.575 ;
			LAYER M1 ;
			RECT 19.035 0.42 19.315 1.575 ;
			LAYER M1 ;
			RECT 0 -0.42 19.84 0.42 ;
			LAYER VIA1 ;
			RECT 0.82 -0.11 1.04 0.11 ;
			LAYER VIA1 ;
			RECT 1.44 -0.11 1.66 0.11 ;
			LAYER VIA1 ;
			RECT 2.06 -0.11 2.28 0.11 ;
			LAYER VIA1 ;
			RECT 2.68 -0.11 2.9 0.11 ;
			LAYER VIA1 ;
			RECT 3.3 -0.11 3.52 0.11 ;
			LAYER VIA1 ;
			RECT 3.92 -0.11 4.14 0.11 ;
			LAYER VIA1 ;
			RECT 4.54 -0.11 4.76 0.11 ;
			LAYER VIA1 ;
			RECT 5.16 -0.11 5.38 0.11 ;
			LAYER VIA1 ;
			RECT 7.02 -0.11 7.24 0.11 ;
			LAYER VIA1 ;
			RECT 7.64 -0.11 7.86 0.11 ;
			LAYER VIA1 ;
			RECT 8.26 -0.11 8.48 0.11 ;
			LAYER VIA1 ;
			RECT 8.88 -0.11 9.1 0.11 ;
			LAYER VIA1 ;
			RECT 9.5 -0.11 9.72 0.11 ;
			LAYER VIA1 ;
			RECT 10.12 -0.11 10.34 0.11 ;
			LAYER VIA1 ;
			RECT 10.74 -0.11 10.96 0.11 ;
			LAYER VIA1 ;
			RECT 11.36 -0.11 11.58 0.11 ;
			LAYER VIA1 ;
			RECT 13.22 -0.11 13.44 0.11 ;
			LAYER VIA1 ;
			RECT 13.84 -0.11 14.06 0.11 ;
			LAYER VIA1 ;
			RECT 14.46 -0.11 14.68 0.11 ;
			LAYER VIA1 ;
			RECT 15.08 -0.11 15.3 0.11 ;
			LAYER VIA1 ;
			RECT 15.7 -0.11 15.92 0.11 ;
			LAYER VIA1 ;
			RECT 16.32 -0.11 16.54 0.11 ;
			LAYER VIA1 ;
			RECT 16.94 -0.11 17.16 0.11 ;
			LAYER VIA1 ;
			RECT 17.56 -0.11 17.78 0.11 ;
			LAYER VIA1 ;
			RECT 19.42 -0.11 19.64 0.11 ;
			LAYER M2 ;
			RECT 0 -0.415 19.84 0.42 ;
		END
	END GND
	PIN VDD
		DIRECTION inout ;
		USE POWER ;
		PORT
			LAYER M1 ;
			RECT 0 5.78 19.84 6.62 ;
			LAYER M1 ;
			RECT 0.155 3.595 0.435 5.78 ;
			LAYER M1 ;
			RECT 0.745 3.595 1.025 5.78 ;
			LAYER M1 ;
			RECT 1.925 3.595 2.205 5.78 ;
			LAYER M1 ;
			RECT 3.105 3.595 3.385 5.78 ;
			LAYER M1 ;
			RECT 4.285 3.595 4.565 5.78 ;
			LAYER M1 ;
			RECT 5.465 3.595 5.745 5.78 ;
			LAYER M1 ;
			RECT 6.645 3.595 6.925 5.78 ;
			LAYER M1 ;
			RECT 7.825 3.595 8.105 5.78 ;
			LAYER M1 ;
			RECT 9.005 3.595 9.285 5.78 ;
			LAYER M1 ;
			RECT 10.185 3.595 10.465 5.78 ;
			LAYER M1 ;
			RECT 11.365 3.595 11.645 5.78 ;
			LAYER M1 ;
			RECT 12.545 3.595 12.825 5.78 ;
			LAYER M1 ;
			RECT 13.725 3.595 14.005 5.78 ;
			LAYER M1 ;
			RECT 14.905 3.595 15.185 5.78 ;
			LAYER M1 ;
			RECT 16.085 3.595 16.365 5.78 ;
			LAYER M1 ;
			RECT 17.265 3.595 17.545 5.78 ;
			LAYER M1 ;
			RECT 18.445 3.595 18.725 5.78 ;
			LAYER M1 ;
			RECT 19.035 3.595 19.315 5.78 ;
			LAYER VIA1 ;
			RECT 0.82 6.09 1.04 6.31 ;
			LAYER VIA1 ;
			RECT 1.44 6.09 1.66 6.31 ;
			LAYER VIA1 ;
			RECT 2.06 6.09 2.28 6.31 ;
			LAYER VIA1 ;
			RECT 2.68 6.09 2.9 6.31 ;
			LAYER VIA1 ;
			RECT 3.3 6.09 3.52 6.31 ;
			LAYER VIA1 ;
			RECT 3.92 6.09 4.14 6.31 ;
			LAYER VIA1 ;
			RECT 4.54 6.09 4.76 6.31 ;
			LAYER VIA1 ;
			RECT 5.16 6.09 5.38 6.31 ;
			LAYER VIA1 ;
			RECT 7.02 6.09 7.24 6.31 ;
			LAYER VIA1 ;
			RECT 7.64 6.09 7.86 6.31 ;
			LAYER VIA1 ;
			RECT 8.26 6.09 8.48 6.31 ;
			LAYER VIA1 ;
			RECT 8.88 6.09 9.1 6.31 ;
			LAYER VIA1 ;
			RECT 9.5 6.09 9.72 6.31 ;
			LAYER VIA1 ;
			RECT 10.12 6.09 10.34 6.31 ;
			LAYER VIA1 ;
			RECT 10.74 6.09 10.96 6.31 ;
			LAYER VIA1 ;
			RECT 11.36 6.09 11.58 6.31 ;
			LAYER VIA1 ;
			RECT 13.22 6.09 13.44 6.31 ;
			LAYER VIA1 ;
			RECT 13.84 6.09 14.06 6.31 ;
			LAYER VIA1 ;
			RECT 14.46 6.09 14.68 6.31 ;
			LAYER VIA1 ;
			RECT 15.08 6.09 15.3 6.31 ;
			LAYER VIA1 ;
			RECT 15.7 6.09 15.92 6.31 ;
			LAYER VIA1 ;
			RECT 16.32 6.09 16.54 6.31 ;
			LAYER VIA1 ;
			RECT 16.94 6.09 17.16 6.31 ;
			LAYER VIA1 ;
			RECT 17.56 6.09 17.78 6.31 ;
			LAYER VIA1 ;
			RECT 19.42 6.09 19.64 6.31 ;
			LAYER M2 ;
			RECT 0 5.78 19.84 6.615 ;
		END
	END VDD
	PIN in
		DIRECTION input ;
		USE SIGNAL ;
		PORT
			LAYER M1 ;
			RECT 1.94 2.75 2.18 3.35 ;
			LAYER M1 ;
			RECT 3.13 2.735 3.37 3.335 ;
			LAYER M1 ;
			RECT 5.48 2.75 5.72 3.35 ;
			LAYER M1 ;
			RECT 6.67 2.735 6.91 3.335 ;
			LAYER M1 ;
			RECT 9.02 2.75 9.26 3.35 ;
			LAYER M1 ;
			RECT 10.21 2.735 10.45 3.335 ;
			LAYER M1 ;
			RECT 12.56 2.75 12.8 3.35 ;
			LAYER M1 ;
			RECT 13.75 2.735 13.99 3.335 ;
			LAYER M1 ;
			RECT 16.1 2.735 16.34 3.335 ;
			LAYER M1 ;
			RECT 17.29 2.75 17.53 3.35 ;
			LAYER VIA1 ;
			RECT 1.95 3.065 2.17 3.285 ;
			LAYER VIA1 ;
			RECT 3.14 3.065 3.36 3.285 ;
			LAYER VIA1 ;
			RECT 5.49 3.065 5.71 3.285 ;
			LAYER VIA1 ;
			RECT 6.68 3.065 6.9 3.285 ;
			LAYER VIA1 ;
			RECT 9.03 3.065 9.25 3.285 ;
			LAYER VIA1 ;
			RECT 10.22 3.065 10.44 3.285 ;
			LAYER VIA1 ;
			RECT 12.57 3.065 12.79 3.285 ;
			LAYER VIA1 ;
			RECT 13.76 3.065 13.98 3.285 ;
			LAYER VIA1 ;
			RECT 16.11 3.065 16.33 3.285 ;
			LAYER VIA1 ;
			RECT 17.3 3.065 17.52 3.285 ;
			LAYER M2 ;
			RECT 0.12 3.29 19.35 3.53 ;
			LAYER M2 ;
			RECT 1.94 3.015 2.18 3.29 ;
			LAYER M2 ;
			RECT 3.13 3.015 3.37 3.29 ;
			LAYER M2 ;
			RECT 5.48 3.015 5.72 3.29 ;
			LAYER M2 ;
			RECT 6.67 3.015 6.91 3.29 ;
			LAYER M2 ;
			RECT 9.02 3.015 9.26 3.29 ;
			LAYER M2 ;
			RECT 10.21 3.015 10.45 3.29 ;
			LAYER M2 ;
			RECT 12.56 3.015 12.8 3.29 ;
			LAYER M2 ;
			RECT 13.75 3.015 13.99 3.29 ;
			LAYER M2 ;
			RECT 16.1 3.015 16.34 3.29 ;
			LAYER M2 ;
			RECT 17.29 3.015 17.53 3.29 ;
		END
		ANTENNASIZE 14.784 ;
	END in
	OBS
	END
END MMI_INVG80
MACRO MMI_INVG88
	CLASS CORE ;
	FOREIGN MMI_INVG88 0 0 ;
	SIZE 21.08 BY 6.2 ;
	SYMMETRY X Y ;
	SITE CORE1 ;
	PIN out
		DIRECTION output ;
		USE SIGNAL ;
		PORT
			LAYER M1 ;
			RECT 1.335 2.32 1.615 5.545 ;
			LAYER M1 ;
			RECT 1.315 2.125 1.635 2.32 ;
			LAYER M1 ;
			RECT 2.515 2.305 2.795 5.545 ;
			LAYER M1 ;
			RECT 3.695 2.335 3.975 5.545 ;
			LAYER M1 ;
			RECT 2.5 2.13 2.82 2.305 ;
			LAYER M1 ;
			RECT 3.675 2.13 3.995 2.335 ;
			LAYER M1 ;
			RECT 4.875 2.32 5.155 5.545 ;
			LAYER M1 ;
			RECT 4.855 2.13 5.175 2.32 ;
			LAYER M1 ;
			RECT 6.055 2.305 6.335 5.545 ;
			LAYER M1 ;
			RECT 7.235 2.335 7.515 5.545 ;
			LAYER M1 ;
			RECT 6.04 2.13 6.36 2.305 ;
			LAYER M1 ;
			RECT 7.215 2.13 7.535 2.335 ;
			LAYER M1 ;
			RECT 8.415 2.32 8.695 5.545 ;
			LAYER M1 ;
			RECT 8.395 2.13 8.715 2.32 ;
			LAYER M1 ;
			RECT 9.595 2.305 9.875 5.545 ;
			LAYER M1 ;
			RECT 10.775 2.335 11.055 5.545 ;
			LAYER M1 ;
			RECT 9.58 2.13 9.9 2.305 ;
			LAYER M1 ;
			RECT 10.755 2.13 11.075 2.335 ;
			LAYER M1 ;
			RECT 11.955 2.32 12.235 5.545 ;
			LAYER M1 ;
			RECT 11.935 2.13 12.255 2.32 ;
			LAYER M1 ;
			RECT 13.135 2.305 13.415 5.545 ;
			LAYER M1 ;
			RECT 14.315 2.335 14.595 5.545 ;
			LAYER M1 ;
			RECT 13.12 2.13 13.44 2.305 ;
			LAYER M1 ;
			RECT 14.295 2.13 14.615 2.335 ;
			LAYER M1 ;
			RECT 15.495 2.32 15.775 5.545 ;
			LAYER M1 ;
			RECT 15.475 2.13 15.795 2.32 ;
			LAYER M1 ;
			RECT 16.675 2.305 16.955 5.545 ;
			LAYER M1 ;
			RECT 17.855 2.335 18.135 5.545 ;
			LAYER M1 ;
			RECT 2.5 2.125 15.795 2.13 ;
			LAYER M1 ;
			RECT 16.66 2.13 16.98 2.305 ;
			LAYER M1 ;
			RECT 17.835 2.13 18.155 2.335 ;
			LAYER M1 ;
			RECT 19.035 2.32 19.315 5.545 ;
			LAYER M1 ;
			RECT 16.66 2.125 18.155 2.13 ;
			LAYER M1 ;
			RECT 19.015 2.125 19.335 2.32 ;
			LAYER M1 ;
			RECT 1.315 1.885 19.335 2.125 ;
			LAYER M1 ;
			RECT 1.315 1.64 1.635 1.885 ;
			LAYER M1 ;
			RECT 1.335 0.62 1.615 1.64 ;
			LAYER M1 ;
			RECT 2.5 1.625 2.82 1.885 ;
			LAYER M1 ;
			RECT 3.675 1.655 3.995 1.885 ;
			LAYER M1 ;
			RECT 2.515 0.62 2.795 1.625 ;
			LAYER M1 ;
			RECT 3.695 0.62 3.975 1.655 ;
			LAYER M1 ;
			RECT 4.855 1.64 5.175 1.885 ;
			LAYER M1 ;
			RECT 4.875 0.62 5.155 1.64 ;
			LAYER M1 ;
			RECT 6.04 1.625 6.36 1.885 ;
			LAYER M1 ;
			RECT 7.215 1.655 7.535 1.885 ;
			LAYER M1 ;
			RECT 6.055 0.62 6.335 1.625 ;
			LAYER M1 ;
			RECT 7.235 0.62 7.515 1.655 ;
			LAYER M1 ;
			RECT 8.395 1.64 8.715 1.885 ;
			LAYER M1 ;
			RECT 8.415 0.62 8.695 1.64 ;
			LAYER M1 ;
			RECT 9.58 1.625 9.9 1.885 ;
			LAYER M1 ;
			RECT 10.755 1.655 11.075 1.885 ;
			LAYER M1 ;
			RECT 9.595 0.62 9.875 1.625 ;
			LAYER M1 ;
			RECT 10.775 0.62 11.055 1.655 ;
			LAYER M1 ;
			RECT 11.935 1.64 12.255 1.885 ;
			LAYER M1 ;
			RECT 11.955 0.62 12.235 1.64 ;
			LAYER M1 ;
			RECT 13.12 1.625 13.44 1.885 ;
			LAYER M1 ;
			RECT 14.295 1.655 14.615 1.885 ;
			LAYER M1 ;
			RECT 13.135 0.62 13.415 1.625 ;
			LAYER M1 ;
			RECT 14.315 0.62 14.595 1.655 ;
			LAYER M1 ;
			RECT 15.475 1.64 15.795 1.885 ;
			LAYER M1 ;
			RECT 15.495 0.62 15.775 1.64 ;
			LAYER M1 ;
			RECT 16.66 1.625 16.98 1.885 ;
			LAYER M1 ;
			RECT 17.835 1.655 18.155 1.885 ;
			LAYER M1 ;
			RECT 16.675 0.62 16.955 1.625 ;
			LAYER M1 ;
			RECT 17.855 0.62 18.135 1.655 ;
			LAYER M1 ;
			RECT 19.015 1.64 19.335 1.885 ;
			LAYER M1 ;
			RECT 19.035 0.62 19.315 1.64 ;
			LAYER VIA1 ;
			RECT 1.365 2.09 1.585 2.31 ;
			LAYER VIA1 ;
			RECT 2.55 2.075 2.77 2.295 ;
			LAYER VIA1 ;
			RECT 3.725 2.105 3.945 2.325 ;
			LAYER VIA1 ;
			RECT 4.905 2.09 5.125 2.31 ;
			LAYER VIA1 ;
			RECT 6.09 2.075 6.31 2.295 ;
			LAYER VIA1 ;
			RECT 7.265 2.105 7.485 2.325 ;
			LAYER VIA1 ;
			RECT 8.445 2.09 8.665 2.31 ;
			LAYER VIA1 ;
			RECT 9.63 2.075 9.85 2.295 ;
			LAYER VIA1 ;
			RECT 10.805 2.105 11.025 2.325 ;
			LAYER VIA1 ;
			RECT 11.985 2.09 12.205 2.31 ;
			LAYER VIA1 ;
			RECT 13.17 2.075 13.39 2.295 ;
			LAYER VIA1 ;
			RECT 14.345 2.105 14.565 2.325 ;
			LAYER VIA1 ;
			RECT 15.525 2.09 15.745 2.31 ;
			LAYER VIA1 ;
			RECT 16.71 2.075 16.93 2.295 ;
			LAYER VIA1 ;
			RECT 17.885 2.105 18.105 2.325 ;
			LAYER VIA1 ;
			RECT 19.065 2.09 19.285 2.31 ;
			LAYER VIA1 ;
			RECT 1.365 1.65 1.585 1.87 ;
			LAYER VIA1 ;
			RECT 2.55 1.635 2.77 1.855 ;
			LAYER VIA1 ;
			RECT 3.725 1.665 3.945 1.885 ;
			LAYER VIA1 ;
			RECT 4.905 1.65 5.125 1.87 ;
			LAYER VIA1 ;
			RECT 6.09 1.635 6.31 1.855 ;
			LAYER VIA1 ;
			RECT 7.265 1.665 7.485 1.885 ;
			LAYER VIA1 ;
			RECT 8.445 1.65 8.665 1.87 ;
			LAYER VIA1 ;
			RECT 9.63 1.635 9.85 1.855 ;
			LAYER VIA1 ;
			RECT 10.805 1.665 11.025 1.885 ;
			LAYER VIA1 ;
			RECT 11.985 1.65 12.205 1.87 ;
			LAYER VIA1 ;
			RECT 13.17 1.635 13.39 1.855 ;
			LAYER VIA1 ;
			RECT 14.345 1.665 14.565 1.885 ;
			LAYER VIA1 ;
			RECT 15.525 1.65 15.745 1.87 ;
			LAYER VIA1 ;
			RECT 16.71 1.635 16.93 1.855 ;
			LAYER VIA1 ;
			RECT 17.885 1.665 18.105 1.885 ;
			LAYER VIA1 ;
			RECT 19.065 1.65 19.285 1.87 ;
			LAYER M2 ;
			RECT 3.675 2.325 3.995 2.335 ;
			LAYER M2 ;
			RECT 7.215 2.325 7.535 2.335 ;
			LAYER M2 ;
			RECT 10.755 2.325 11.075 2.335 ;
			LAYER M2 ;
			RECT 14.295 2.325 14.615 2.335 ;
			LAYER M2 ;
			RECT 17.835 2.325 18.155 2.335 ;
			LAYER M2 ;
			RECT 0.12 1.205 20.53 2.325 ;
		END
	END out
	PIN GND
		DIRECTION inout ;
		USE GROUND ;
		PORT
			LAYER M1 ;
			RECT 0.155 0.42 0.435 1.575 ;
			LAYER M1 ;
			RECT 0.745 0.42 1.025 1.61 ;
			LAYER M1 ;
			RECT 1.925 0.42 2.205 1.61 ;
			LAYER M1 ;
			RECT 3.105 0.42 3.385 1.61 ;
			LAYER M1 ;
			RECT 4.285 0.42 4.565 1.61 ;
			LAYER M1 ;
			RECT 5.465 0.42 5.745 1.61 ;
			LAYER M1 ;
			RECT 6.645 0.42 6.925 1.61 ;
			LAYER M1 ;
			RECT 7.825 0.42 8.105 1.61 ;
			LAYER M1 ;
			RECT 9.005 0.42 9.285 1.61 ;
			LAYER M1 ;
			RECT 10.185 0.42 10.465 1.61 ;
			LAYER M1 ;
			RECT 11.365 0.42 11.645 1.61 ;
			LAYER M1 ;
			RECT 12.545 0.42 12.825 1.61 ;
			LAYER M1 ;
			RECT 13.725 0.42 14.005 1.61 ;
			LAYER M1 ;
			RECT 14.905 0.42 15.185 1.61 ;
			LAYER M1 ;
			RECT 16.085 0.42 16.365 1.61 ;
			LAYER M1 ;
			RECT 17.265 0.42 17.545 1.61 ;
			LAYER M1 ;
			RECT 18.445 0.42 18.725 1.61 ;
			LAYER M1 ;
			RECT 19.625 0.42 19.905 1.61 ;
			LAYER M1 ;
			RECT 20.215 0.42 20.495 1.61 ;
			LAYER M1 ;
			RECT 0 -0.42 21.08 0.42 ;
			LAYER VIA1 ;
			RECT 0.82 -0.11 1.04 0.11 ;
			LAYER VIA1 ;
			RECT 1.44 -0.11 1.66 0.11 ;
			LAYER VIA1 ;
			RECT 2.06 -0.11 2.28 0.11 ;
			LAYER VIA1 ;
			RECT 2.68 -0.11 2.9 0.11 ;
			LAYER VIA1 ;
			RECT 3.3 -0.11 3.52 0.11 ;
			LAYER VIA1 ;
			RECT 3.92 -0.11 4.14 0.11 ;
			LAYER VIA1 ;
			RECT 4.54 -0.11 4.76 0.11 ;
			LAYER VIA1 ;
			RECT 5.16 -0.11 5.38 0.11 ;
			LAYER VIA1 ;
			RECT 7.02 -0.11 7.24 0.11 ;
			LAYER VIA1 ;
			RECT 7.64 -0.11 7.86 0.11 ;
			LAYER VIA1 ;
			RECT 8.26 -0.11 8.48 0.11 ;
			LAYER VIA1 ;
			RECT 8.88 -0.11 9.1 0.11 ;
			LAYER VIA1 ;
			RECT 9.5 -0.11 9.72 0.11 ;
			LAYER VIA1 ;
			RECT 10.12 -0.11 10.34 0.11 ;
			LAYER VIA1 ;
			RECT 10.74 -0.11 10.96 0.11 ;
			LAYER VIA1 ;
			RECT 11.36 -0.11 11.58 0.11 ;
			LAYER VIA1 ;
			RECT 13.22 -0.11 13.44 0.11 ;
			LAYER VIA1 ;
			RECT 13.84 -0.11 14.06 0.11 ;
			LAYER VIA1 ;
			RECT 14.46 -0.11 14.68 0.11 ;
			LAYER VIA1 ;
			RECT 15.08 -0.11 15.3 0.11 ;
			LAYER VIA1 ;
			RECT 15.7 -0.11 15.92 0.11 ;
			LAYER VIA1 ;
			RECT 16.32 -0.11 16.54 0.11 ;
			LAYER VIA1 ;
			RECT 16.94 -0.11 17.16 0.11 ;
			LAYER VIA1 ;
			RECT 17.56 -0.11 17.78 0.11 ;
			LAYER VIA1 ;
			RECT 19.42 -0.11 19.64 0.11 ;
			LAYER VIA1 ;
			RECT 20.04 -0.11 20.26 0.11 ;
			LAYER VIA1 ;
			RECT 20.66 -0.11 20.88 0.11 ;
			LAYER M2 ;
			RECT 0 -0.415 21.08 0.42 ;
		END
	END GND
	PIN VDD
		DIRECTION inout ;
		USE POWER ;
		PORT
			LAYER M1 ;
			RECT 0 5.78 21.08 6.62 ;
			LAYER M1 ;
			RECT 0.155 3.595 0.435 5.78 ;
			LAYER M1 ;
			RECT 0.745 3.495 1.025 5.78 ;
			LAYER M1 ;
			RECT 1.925 3.495 2.205 5.78 ;
			LAYER M1 ;
			RECT 3.105 3.495 3.385 5.78 ;
			LAYER M1 ;
			RECT 4.285 3.495 4.565 5.78 ;
			LAYER M1 ;
			RECT 5.465 3.495 5.745 5.78 ;
			LAYER M1 ;
			RECT 6.645 3.495 6.925 5.78 ;
			LAYER M1 ;
			RECT 7.825 3.495 8.105 5.78 ;
			LAYER M1 ;
			RECT 9.005 3.495 9.285 5.78 ;
			LAYER M1 ;
			RECT 10.185 3.495 10.465 5.78 ;
			LAYER M1 ;
			RECT 11.365 3.495 11.645 5.78 ;
			LAYER M1 ;
			RECT 12.545 3.495 12.825 5.78 ;
			LAYER M1 ;
			RECT 13.725 3.495 14.005 5.78 ;
			LAYER M1 ;
			RECT 14.905 3.495 15.185 5.78 ;
			LAYER M1 ;
			RECT 16.085 3.495 16.365 5.78 ;
			LAYER M1 ;
			RECT 17.265 3.495 17.545 5.78 ;
			LAYER M1 ;
			RECT 18.445 3.495 18.725 5.78 ;
			LAYER M1 ;
			RECT 19.625 3.495 19.905 5.78 ;
			LAYER M1 ;
			RECT 20.215 3.495 20.495 5.78 ;
			LAYER VIA1 ;
			RECT 0.82 6.09 1.04 6.31 ;
			LAYER VIA1 ;
			RECT 1.44 6.09 1.66 6.31 ;
			LAYER VIA1 ;
			RECT 2.06 6.09 2.28 6.31 ;
			LAYER VIA1 ;
			RECT 2.68 6.09 2.9 6.31 ;
			LAYER VIA1 ;
			RECT 3.3 6.09 3.52 6.31 ;
			LAYER VIA1 ;
			RECT 3.92 6.09 4.14 6.31 ;
			LAYER VIA1 ;
			RECT 4.54 6.09 4.76 6.31 ;
			LAYER VIA1 ;
			RECT 5.16 6.09 5.38 6.31 ;
			LAYER VIA1 ;
			RECT 7.02 6.09 7.24 6.31 ;
			LAYER VIA1 ;
			RECT 7.64 6.09 7.86 6.31 ;
			LAYER VIA1 ;
			RECT 8.26 6.09 8.48 6.31 ;
			LAYER VIA1 ;
			RECT 8.88 6.09 9.1 6.31 ;
			LAYER VIA1 ;
			RECT 9.5 6.09 9.72 6.31 ;
			LAYER VIA1 ;
			RECT 10.12 6.09 10.34 6.31 ;
			LAYER VIA1 ;
			RECT 10.74 6.09 10.96 6.31 ;
			LAYER VIA1 ;
			RECT 11.36 6.09 11.58 6.31 ;
			LAYER VIA1 ;
			RECT 13.22 6.09 13.44 6.31 ;
			LAYER VIA1 ;
			RECT 13.84 6.09 14.06 6.31 ;
			LAYER VIA1 ;
			RECT 14.46 6.09 14.68 6.31 ;
			LAYER VIA1 ;
			RECT 15.08 6.09 15.3 6.31 ;
			LAYER VIA1 ;
			RECT 15.7 6.09 15.92 6.31 ;
			LAYER VIA1 ;
			RECT 16.32 6.09 16.54 6.31 ;
			LAYER VIA1 ;
			RECT 16.94 6.09 17.16 6.31 ;
			LAYER VIA1 ;
			RECT 17.56 6.09 17.78 6.31 ;
			LAYER VIA1 ;
			RECT 19.42 6.09 19.64 6.31 ;
			LAYER VIA1 ;
			RECT 20.04 6.09 20.26 6.31 ;
			LAYER VIA1 ;
			RECT 20.66 6.09 20.88 6.31 ;
			LAYER M2 ;
			RECT 0 5.78 21.08 6.615 ;
		END
	END VDD
	PIN in
		DIRECTION input ;
		USE SIGNAL ;
		PORT
			LAYER M1 ;
			RECT 1.94 2.695 2.18 3.295 ;
			LAYER M1 ;
			RECT 3.13 2.695 3.37 3.295 ;
			LAYER M1 ;
			RECT 5.48 2.695 5.72 3.295 ;
			LAYER M1 ;
			RECT 6.67 2.695 6.91 3.295 ;
			LAYER M1 ;
			RECT 9.02 2.695 9.26 3.295 ;
			LAYER M1 ;
			RECT 10.21 2.695 10.45 3.295 ;
			LAYER M1 ;
			RECT 12.56 2.695 12.8 3.295 ;
			LAYER M1 ;
			RECT 13.75 2.695 13.99 3.295 ;
			LAYER M1 ;
			RECT 16.1 2.695 16.34 3.295 ;
			LAYER M1 ;
			RECT 17.29 2.695 17.53 3.295 ;
			LAYER M1 ;
			RECT 19.64 2.695 19.88 3.295 ;
			LAYER VIA1 ;
			RECT 1.95 3.025 2.17 3.245 ;
			LAYER VIA1 ;
			RECT 3.14 3.025 3.36 3.245 ;
			LAYER VIA1 ;
			RECT 5.49 3.025 5.71 3.245 ;
			LAYER VIA1 ;
			RECT 6.68 3.025 6.9 3.245 ;
			LAYER VIA1 ;
			RECT 9.03 3.025 9.25 3.245 ;
			LAYER VIA1 ;
			RECT 10.22 3.025 10.44 3.245 ;
			LAYER VIA1 ;
			RECT 12.57 3.025 12.79 3.245 ;
			LAYER VIA1 ;
			RECT 13.76 3.025 13.98 3.245 ;
			LAYER VIA1 ;
			RECT 16.11 3.025 16.33 3.245 ;
			LAYER VIA1 ;
			RECT 17.3 3.025 17.52 3.245 ;
			LAYER VIA1 ;
			RECT 19.65 3.025 19.87 3.245 ;
			LAYER M2 ;
			RECT 0.12 3.28 20.53 3.52 ;
			LAYER M2 ;
			RECT 1.94 2.975 2.18 3.28 ;
			LAYER M2 ;
			RECT 3.13 2.975 3.37 3.28 ;
			LAYER M2 ;
			RECT 5.48 2.975 5.72 3.28 ;
			LAYER M2 ;
			RECT 6.67 2.975 6.91 3.28 ;
			LAYER M2 ;
			RECT 9.02 2.975 9.26 3.28 ;
			LAYER M2 ;
			RECT 10.21 2.975 10.45 3.28 ;
			LAYER M2 ;
			RECT 12.56 2.975 12.8 3.28 ;
			LAYER M2 ;
			RECT 13.75 2.975 13.99 3.28 ;
			LAYER M2 ;
			RECT 16.1 2.975 16.34 3.28 ;
			LAYER M2 ;
			RECT 17.29 2.975 17.53 3.28 ;
			LAYER M2 ;
			RECT 19.64 2.975 19.88 3.28 ;
		END
		ANTENNASIZE 16.218 ;
	END in
	OBS
	END
END MMI_INVG88
MACRO MMI_INVG96
	CLASS CORE ;
	FOREIGN MMI_INVG96 0 0 ;
	SIZE 23.56 BY 6.2 ;
	SYMMETRY X Y ;
	SITE CORE1 ;
	PIN out
		DIRECTION output ;
		USE SIGNAL ;
		PORT
			LAYER M1 ;
			RECT 1.335 2.32 1.615 5.58 ;
			LAYER M1 ;
			RECT 1.315 2.125 1.635 2.32 ;
			LAYER M1 ;
			RECT 2.515 2.305 2.795 5.58 ;
			LAYER M1 ;
			RECT 3.695 2.335 3.975 5.58 ;
			LAYER M1 ;
			RECT 2.5 2.13 2.82 2.305 ;
			LAYER M1 ;
			RECT 3.675 2.13 3.995 2.335 ;
			LAYER M1 ;
			RECT 4.875 2.32 5.155 5.58 ;
			LAYER M1 ;
			RECT 2.5 2.125 3.995 2.13 ;
			LAYER M1 ;
			RECT 4.855 2.125 5.175 2.32 ;
			LAYER M1 ;
			RECT 6.055 2.305 6.335 5.58 ;
			LAYER M1 ;
			RECT 7.235 2.335 7.515 5.58 ;
			LAYER M1 ;
			RECT 6.04 2.13 6.36 2.305 ;
			LAYER M1 ;
			RECT 7.215 2.13 7.535 2.335 ;
			LAYER M1 ;
			RECT 8.415 2.32 8.695 5.58 ;
			LAYER M1 ;
			RECT 6.04 2.125 7.535 2.13 ;
			LAYER M1 ;
			RECT 8.395 2.125 8.715 2.32 ;
			LAYER M1 ;
			RECT 9.595 2.305 9.875 5.58 ;
			LAYER M1 ;
			RECT 10.775 2.335 11.055 5.58 ;
			LAYER M1 ;
			RECT 9.58 2.13 9.9 2.305 ;
			LAYER M1 ;
			RECT 10.755 2.13 11.075 2.335 ;
			LAYER M1 ;
			RECT 11.955 2.32 12.235 5.58 ;
			LAYER M1 ;
			RECT 9.58 2.125 11.075 2.13 ;
			LAYER M1 ;
			RECT 11.935 2.125 12.255 2.32 ;
			LAYER M1 ;
			RECT 13.135 2.305 13.415 5.58 ;
			LAYER M1 ;
			RECT 14.315 2.335 14.595 5.58 ;
			LAYER M1 ;
			RECT 13.12 2.13 13.44 2.305 ;
			LAYER M1 ;
			RECT 14.295 2.13 14.615 2.335 ;
			LAYER M1 ;
			RECT 15.495 2.32 15.775 5.58 ;
			LAYER M1 ;
			RECT 13.12 2.125 14.615 2.13 ;
			LAYER M1 ;
			RECT 15.475 2.125 15.795 2.32 ;
			LAYER M1 ;
			RECT 16.675 2.305 16.955 5.58 ;
			LAYER M1 ;
			RECT 17.855 2.335 18.135 5.58 ;
			LAYER M1 ;
			RECT 19.035 2.335 19.315 5.58 ;
			LAYER M1 ;
			RECT 16.66 2.13 16.98 2.305 ;
			LAYER M1 ;
			RECT 17.835 2.13 18.155 2.335 ;
			LAYER M1 ;
			RECT 16.66 2.125 18.155 2.13 ;
			LAYER M1 ;
			RECT 19.015 2.13 19.335 2.335 ;
			LAYER M1 ;
			RECT 20.215 2.305 20.495 5.58 ;
			LAYER M1 ;
			RECT 21.395 2.32 21.675 5.58 ;
			LAYER M1 ;
			RECT 20.19 2.13 20.51 2.305 ;
			LAYER M1 ;
			RECT 19.015 2.125 20.51 2.13 ;
			LAYER M1 ;
			RECT 21.375 2.125 21.695 2.32 ;
			LAYER M1 ;
			RECT 1.315 1.885 21.695 2.125 ;
			LAYER M1 ;
			RECT 1.315 1.64 1.635 1.885 ;
			LAYER M1 ;
			RECT 1.335 0.62 1.615 1.64 ;
			LAYER M1 ;
			RECT 2.5 1.625 2.82 1.885 ;
			LAYER M1 ;
			RECT 3.675 1.655 3.995 1.885 ;
			LAYER M1 ;
			RECT 2.515 0.62 2.795 1.625 ;
			LAYER M1 ;
			RECT 3.695 0.62 3.975 1.655 ;
			LAYER M1 ;
			RECT 4.855 1.64 5.175 1.885 ;
			LAYER M1 ;
			RECT 4.875 0.62 5.155 1.64 ;
			LAYER M1 ;
			RECT 6.04 1.625 6.36 1.885 ;
			LAYER M1 ;
			RECT 7.215 1.655 7.535 1.885 ;
			LAYER M1 ;
			RECT 6.055 0.62 6.335 1.625 ;
			LAYER M1 ;
			RECT 7.235 0.62 7.515 1.655 ;
			LAYER M1 ;
			RECT 8.395 1.64 8.715 1.885 ;
			LAYER M1 ;
			RECT 8.415 0.62 8.695 1.64 ;
			LAYER M1 ;
			RECT 9.58 1.625 9.9 1.885 ;
			LAYER M1 ;
			RECT 10.755 1.655 11.075 1.885 ;
			LAYER M1 ;
			RECT 9.595 0.62 9.875 1.625 ;
			LAYER M1 ;
			RECT 10.775 0.62 11.055 1.655 ;
			LAYER M1 ;
			RECT 11.935 1.64 12.255 1.885 ;
			LAYER M1 ;
			RECT 11.955 0.62 12.235 1.64 ;
			LAYER M1 ;
			RECT 13.12 1.625 13.44 1.885 ;
			LAYER M1 ;
			RECT 14.295 1.655 14.615 1.885 ;
			LAYER M1 ;
			RECT 13.135 0.62 13.415 1.625 ;
			LAYER M1 ;
			RECT 14.315 0.62 14.595 1.655 ;
			LAYER M1 ;
			RECT 15.475 1.64 15.795 1.885 ;
			LAYER M1 ;
			RECT 15.495 0.62 15.775 1.64 ;
			LAYER M1 ;
			RECT 16.66 1.625 16.98 1.885 ;
			LAYER M1 ;
			RECT 17.835 1.655 18.155 1.885 ;
			LAYER M1 ;
			RECT 19.015 1.655 19.335 1.885 ;
			LAYER M1 ;
			RECT 16.675 0.62 16.955 1.625 ;
			LAYER M1 ;
			RECT 17.855 0.62 18.135 1.655 ;
			LAYER M1 ;
			RECT 19.035 0.62 19.315 1.655 ;
			LAYER M1 ;
			RECT 20.19 1.625 20.51 1.885 ;
			LAYER M1 ;
			RECT 21.375 1.64 21.695 1.885 ;
			LAYER M1 ;
			RECT 20.215 0.62 20.495 1.625 ;
			LAYER M1 ;
			RECT 21.395 0.62 21.675 1.64 ;
			LAYER VIA1 ;
			RECT 1.365 2.09 1.585 2.31 ;
			LAYER VIA1 ;
			RECT 2.55 2.075 2.77 2.295 ;
			LAYER VIA1 ;
			RECT 3.725 2.105 3.945 2.325 ;
			LAYER VIA1 ;
			RECT 4.905 2.09 5.125 2.31 ;
			LAYER VIA1 ;
			RECT 6.09 2.075 6.31 2.295 ;
			LAYER VIA1 ;
			RECT 7.265 2.105 7.485 2.325 ;
			LAYER VIA1 ;
			RECT 8.445 2.09 8.665 2.31 ;
			LAYER VIA1 ;
			RECT 9.63 2.075 9.85 2.295 ;
			LAYER VIA1 ;
			RECT 10.805 2.105 11.025 2.325 ;
			LAYER VIA1 ;
			RECT 11.985 2.09 12.205 2.31 ;
			LAYER VIA1 ;
			RECT 13.17 2.075 13.39 2.295 ;
			LAYER VIA1 ;
			RECT 14.345 2.105 14.565 2.325 ;
			LAYER VIA1 ;
			RECT 15.525 2.09 15.745 2.31 ;
			LAYER VIA1 ;
			RECT 16.71 2.075 16.93 2.295 ;
			LAYER VIA1 ;
			RECT 17.885 2.105 18.105 2.325 ;
			LAYER VIA1 ;
			RECT 19.065 2.105 19.285 2.325 ;
			LAYER VIA1 ;
			RECT 20.24 2.075 20.46 2.295 ;
			LAYER VIA1 ;
			RECT 21.425 2.09 21.645 2.31 ;
			LAYER VIA1 ;
			RECT 1.365 1.65 1.585 1.87 ;
			LAYER VIA1 ;
			RECT 2.55 1.635 2.77 1.855 ;
			LAYER VIA1 ;
			RECT 3.725 1.665 3.945 1.885 ;
			LAYER VIA1 ;
			RECT 4.905 1.65 5.125 1.87 ;
			LAYER VIA1 ;
			RECT 6.09 1.635 6.31 1.855 ;
			LAYER VIA1 ;
			RECT 7.265 1.665 7.485 1.885 ;
			LAYER VIA1 ;
			RECT 8.445 1.65 8.665 1.87 ;
			LAYER VIA1 ;
			RECT 9.63 1.635 9.85 1.855 ;
			LAYER VIA1 ;
			RECT 10.805 1.665 11.025 1.885 ;
			LAYER VIA1 ;
			RECT 11.985 1.65 12.205 1.87 ;
			LAYER VIA1 ;
			RECT 13.17 1.635 13.39 1.855 ;
			LAYER VIA1 ;
			RECT 14.345 1.665 14.565 1.885 ;
			LAYER VIA1 ;
			RECT 15.525 1.65 15.745 1.87 ;
			LAYER VIA1 ;
			RECT 16.71 1.635 16.93 1.855 ;
			LAYER VIA1 ;
			RECT 17.885 1.665 18.105 1.885 ;
			LAYER VIA1 ;
			RECT 19.065 1.665 19.285 1.885 ;
			LAYER VIA1 ;
			RECT 20.24 1.635 20.46 1.855 ;
			LAYER VIA1 ;
			RECT 21.425 1.65 21.645 1.87 ;
			LAYER M2 ;
			RECT 3.675 2.33 3.995 2.335 ;
			LAYER M2 ;
			RECT 7.215 2.33 7.535 2.335 ;
			LAYER M2 ;
			RECT 10.755 2.33 11.075 2.335 ;
			LAYER M2 ;
			RECT 14.295 2.33 14.615 2.335 ;
			LAYER M2 ;
			RECT 17.835 2.33 18.155 2.335 ;
			LAYER M2 ;
			RECT 19.015 2.33 19.335 2.335 ;
			LAYER M2 ;
			RECT 0.12 1.21 22.89 2.33 ;
		END
	END out
	PIN GND
		DIRECTION inout ;
		USE GROUND ;
		PORT
			LAYER M1 ;
			RECT 0.155 0.42 0.435 1.575 ;
			LAYER M1 ;
			RECT 0.745 0.42 1.025 1.575 ;
			LAYER M1 ;
			RECT 1.925 0.42 2.205 1.575 ;
			LAYER M1 ;
			RECT 3.105 0.42 3.385 1.575 ;
			LAYER M1 ;
			RECT 4.285 0.42 4.565 1.575 ;
			LAYER M1 ;
			RECT 5.465 0.42 5.745 1.575 ;
			LAYER M1 ;
			RECT 6.645 0.42 6.925 1.575 ;
			LAYER M1 ;
			RECT 7.825 0.42 8.105 1.575 ;
			LAYER M1 ;
			RECT 9.005 0.42 9.285 1.575 ;
			LAYER M1 ;
			RECT 10.185 0.42 10.465 1.575 ;
			LAYER M1 ;
			RECT 11.365 0.42 11.645 1.575 ;
			LAYER M1 ;
			RECT 12.545 0.42 12.825 1.575 ;
			LAYER M1 ;
			RECT 13.725 0.42 14.005 1.575 ;
			LAYER M1 ;
			RECT 14.905 0.42 15.185 1.575 ;
			LAYER M1 ;
			RECT 16.085 0.42 16.365 1.575 ;
			LAYER M1 ;
			RECT 17.265 0.42 17.545 1.575 ;
			LAYER M1 ;
			RECT 18.445 0.42 18.725 1.575 ;
			LAYER M1 ;
			RECT 19.625 0.42 19.905 1.575 ;
			LAYER M1 ;
			RECT 20.805 0.42 21.085 1.575 ;
			LAYER M1 ;
			RECT 21.985 0.42 22.265 1.575 ;
			LAYER M1 ;
			RECT 22.575 0.42 22.855 1.575 ;
			LAYER M1 ;
			RECT 0 0.35 22.855 0.42 ;
			LAYER M1 ;
			RECT 0 -0.42 23.56 0.35 ;
			LAYER VIA1 ;
			RECT 0.82 -0.11 1.04 0.11 ;
			LAYER VIA1 ;
			RECT 1.44 -0.11 1.66 0.11 ;
			LAYER VIA1 ;
			RECT 2.06 -0.11 2.28 0.11 ;
			LAYER VIA1 ;
			RECT 2.68 -0.11 2.9 0.11 ;
			LAYER VIA1 ;
			RECT 3.3 -0.11 3.52 0.11 ;
			LAYER VIA1 ;
			RECT 3.92 -0.11 4.14 0.11 ;
			LAYER VIA1 ;
			RECT 4.54 -0.11 4.76 0.11 ;
			LAYER VIA1 ;
			RECT 5.16 -0.11 5.38 0.11 ;
			LAYER VIA1 ;
			RECT 7.02 -0.11 7.24 0.11 ;
			LAYER VIA1 ;
			RECT 7.64 -0.11 7.86 0.11 ;
			LAYER VIA1 ;
			RECT 8.26 -0.11 8.48 0.11 ;
			LAYER VIA1 ;
			RECT 8.88 -0.11 9.1 0.11 ;
			LAYER VIA1 ;
			RECT 9.5 -0.11 9.72 0.11 ;
			LAYER VIA1 ;
			RECT 10.12 -0.11 10.34 0.11 ;
			LAYER VIA1 ;
			RECT 10.74 -0.11 10.96 0.11 ;
			LAYER VIA1 ;
			RECT 11.36 -0.11 11.58 0.11 ;
			LAYER VIA1 ;
			RECT 13.22 -0.11 13.44 0.11 ;
			LAYER VIA1 ;
			RECT 13.84 -0.11 14.06 0.11 ;
			LAYER VIA1 ;
			RECT 14.46 -0.11 14.68 0.11 ;
			LAYER VIA1 ;
			RECT 15.08 -0.11 15.3 0.11 ;
			LAYER VIA1 ;
			RECT 15.7 -0.11 15.92 0.11 ;
			LAYER VIA1 ;
			RECT 16.32 -0.11 16.54 0.11 ;
			LAYER VIA1 ;
			RECT 16.94 -0.11 17.16 0.11 ;
			LAYER VIA1 ;
			RECT 17.56 -0.11 17.78 0.11 ;
			LAYER VIA1 ;
			RECT 19.42 -0.11 19.64 0.11 ;
			LAYER VIA1 ;
			RECT 20.04 -0.11 20.26 0.11 ;
			LAYER VIA1 ;
			RECT 20.66 -0.11 20.88 0.11 ;
			LAYER VIA1 ;
			RECT 21.28 -0.11 21.5 0.11 ;
			LAYER VIA1 ;
			RECT 21.9 -0.11 22.12 0.11 ;
			LAYER VIA1 ;
			RECT 22.52 -0.11 22.74 0.11 ;
			LAYER VIA1 ;
			RECT 23.14 -0.11 23.36 0.11 ;
			LAYER M2 ;
			RECT 0 -0.415 23.56 0.42 ;
		END
	END GND
	PIN VDD
		DIRECTION inout ;
		USE POWER ;
		PORT
			LAYER M1 ;
			RECT 0 5.78 23.56 6.62 ;
			LAYER M1 ;
			RECT 0.155 3.595 0.435 5.78 ;
			LAYER M1 ;
			RECT 0.745 3.595 1.025 5.78 ;
			LAYER M1 ;
			RECT 1.925 3.595 2.205 5.78 ;
			LAYER M1 ;
			RECT 3.105 3.595 3.385 5.78 ;
			LAYER M1 ;
			RECT 4.285 3.595 4.565 5.78 ;
			LAYER M1 ;
			RECT 5.465 3.595 5.745 5.78 ;
			LAYER M1 ;
			RECT 6.645 3.595 6.925 5.78 ;
			LAYER M1 ;
			RECT 7.825 3.595 8.105 5.78 ;
			LAYER M1 ;
			RECT 9.005 3.595 9.285 5.78 ;
			LAYER M1 ;
			RECT 10.185 3.595 10.465 5.78 ;
			LAYER M1 ;
			RECT 11.365 3.595 11.645 5.78 ;
			LAYER M1 ;
			RECT 12.545 3.595 12.825 5.78 ;
			LAYER M1 ;
			RECT 13.725 3.595 14.005 5.78 ;
			LAYER M1 ;
			RECT 14.905 3.595 15.185 5.78 ;
			LAYER M1 ;
			RECT 16.085 3.595 16.365 5.78 ;
			LAYER M1 ;
			RECT 17.265 3.595 17.545 5.78 ;
			LAYER M1 ;
			RECT 18.445 3.595 18.725 5.78 ;
			LAYER M1 ;
			RECT 19.625 3.595 19.905 5.78 ;
			LAYER M1 ;
			RECT 20.805 3.595 21.085 5.78 ;
			LAYER M1 ;
			RECT 21.985 3.595 22.265 5.78 ;
			LAYER M1 ;
			RECT 22.575 3.595 22.855 5.78 ;
			LAYER VIA1 ;
			RECT 0.82 6.09 1.04 6.31 ;
			LAYER VIA1 ;
			RECT 1.44 6.09 1.66 6.31 ;
			LAYER VIA1 ;
			RECT 2.06 6.09 2.28 6.31 ;
			LAYER VIA1 ;
			RECT 2.68 6.09 2.9 6.31 ;
			LAYER VIA1 ;
			RECT 3.3 6.09 3.52 6.31 ;
			LAYER VIA1 ;
			RECT 3.92 6.09 4.14 6.31 ;
			LAYER VIA1 ;
			RECT 4.54 6.09 4.76 6.31 ;
			LAYER VIA1 ;
			RECT 5.16 6.09 5.38 6.31 ;
			LAYER VIA1 ;
			RECT 7.02 6.09 7.24 6.31 ;
			LAYER VIA1 ;
			RECT 7.64 6.09 7.86 6.31 ;
			LAYER VIA1 ;
			RECT 8.26 6.09 8.48 6.31 ;
			LAYER VIA1 ;
			RECT 8.88 6.09 9.1 6.31 ;
			LAYER VIA1 ;
			RECT 9.5 6.09 9.72 6.31 ;
			LAYER VIA1 ;
			RECT 10.12 6.09 10.34 6.31 ;
			LAYER VIA1 ;
			RECT 10.74 6.09 10.96 6.31 ;
			LAYER VIA1 ;
			RECT 11.36 6.09 11.58 6.31 ;
			LAYER VIA1 ;
			RECT 13.22 6.09 13.44 6.31 ;
			LAYER VIA1 ;
			RECT 13.84 6.09 14.06 6.31 ;
			LAYER VIA1 ;
			RECT 14.46 6.09 14.68 6.31 ;
			LAYER VIA1 ;
			RECT 15.08 6.09 15.3 6.31 ;
			LAYER VIA1 ;
			RECT 15.7 6.09 15.92 6.31 ;
			LAYER VIA1 ;
			RECT 16.32 6.09 16.54 6.31 ;
			LAYER VIA1 ;
			RECT 16.94 6.09 17.16 6.31 ;
			LAYER VIA1 ;
			RECT 17.56 6.09 17.78 6.31 ;
			LAYER VIA1 ;
			RECT 19.42 6.09 19.64 6.31 ;
			LAYER VIA1 ;
			RECT 20.04 6.09 20.26 6.31 ;
			LAYER VIA1 ;
			RECT 20.66 6.09 20.88 6.31 ;
			LAYER VIA1 ;
			RECT 21.28 6.09 21.5 6.31 ;
			LAYER VIA1 ;
			RECT 21.9 6.09 22.12 6.31 ;
			LAYER VIA1 ;
			RECT 22.52 6.09 22.74 6.31 ;
			LAYER VIA1 ;
			RECT 23.14 6.09 23.36 6.31 ;
			LAYER M2 ;
			RECT 0 5.78 23.56 6.615 ;
		END
	END VDD
	PIN in
		DIRECTION input ;
		USE SIGNAL ;
		PORT
			LAYER M1 ;
			RECT 1.94 2.75 2.18 3.35 ;
			LAYER M1 ;
			RECT 3.13 2.735 3.37 3.335 ;
			LAYER M1 ;
			RECT 5.48 2.75 5.72 3.35 ;
			LAYER M1 ;
			RECT 6.67 2.735 6.91 3.335 ;
			LAYER M1 ;
			RECT 9.02 2.75 9.26 3.35 ;
			LAYER M1 ;
			RECT 10.21 2.735 10.45 3.335 ;
			LAYER M1 ;
			RECT 12.56 2.75 12.8 3.35 ;
			LAYER M1 ;
			RECT 13.75 2.735 13.99 3.335 ;
			LAYER M1 ;
			RECT 16.1 2.75 16.34 3.35 ;
			LAYER M1 ;
			RECT 17.29 2.735 17.53 3.335 ;
			LAYER M1 ;
			RECT 19.64 2.735 19.88 3.335 ;
			LAYER M1 ;
			RECT 20.83 2.75 21.07 3.35 ;
			LAYER VIA1 ;
			RECT 1.95 3.065 2.17 3.285 ;
			LAYER VIA1 ;
			RECT 3.14 3.065 3.36 3.285 ;
			LAYER VIA1 ;
			RECT 5.49 3.065 5.71 3.285 ;
			LAYER VIA1 ;
			RECT 6.68 3.065 6.9 3.285 ;
			LAYER VIA1 ;
			RECT 9.03 3.065 9.25 3.285 ;
			LAYER VIA1 ;
			RECT 10.22 3.065 10.44 3.285 ;
			LAYER VIA1 ;
			RECT 12.57 3.065 12.79 3.285 ;
			LAYER VIA1 ;
			RECT 13.76 3.065 13.98 3.285 ;
			LAYER VIA1 ;
			RECT 16.11 3.065 16.33 3.285 ;
			LAYER VIA1 ;
			RECT 17.3 3.065 17.52 3.285 ;
			LAYER VIA1 ;
			RECT 19.65 3.065 19.87 3.285 ;
			LAYER VIA1 ;
			RECT 20.84 3.065 21.06 3.285 ;
			LAYER M2 ;
			RECT 0.12 3.29 22.89 3.53 ;
			LAYER M2 ;
			RECT 1.94 3.015 2.18 3.29 ;
			LAYER M2 ;
			RECT 3.13 3.015 3.37 3.29 ;
			LAYER M2 ;
			RECT 5.48 3.015 5.72 3.29 ;
			LAYER M2 ;
			RECT 6.67 3.015 6.91 3.29 ;
			LAYER M2 ;
			RECT 9.02 3.015 9.26 3.29 ;
			LAYER M2 ;
			RECT 10.21 3.015 10.45 3.29 ;
			LAYER M2 ;
			RECT 12.56 3.015 12.8 3.29 ;
			LAYER M2 ;
			RECT 13.75 3.015 13.99 3.29 ;
			LAYER M2 ;
			RECT 16.1 3.015 16.34 3.29 ;
			LAYER M2 ;
			RECT 17.29 3.015 17.53 3.29 ;
			LAYER M2 ;
			RECT 19.64 3.015 19.88 3.29 ;
			LAYER M2 ;
			RECT 20.83 3.015 21.07 3.29 ;
		END
		ANTENNASIZE 17.556 ;
	END in
	OBS
	END
END MMI_INVG96
MACRO MMI_INVH
	CLASS CORE ;
	FOREIGN MMI_INVH 0 0 ;
	SIZE 30.38 BY 6.2 ;
	SYMMETRY X Y ;
	SITE CORE1 ;
	PIN out
		DIRECTION output ;
		USE SIGNAL ;
		PORT
			LAYER M1 ;
			RECT 1.335 2.32 1.615 5.58 ;
			LAYER M1 ;
			RECT 1.315 2.125 1.635 2.32 ;
			LAYER M1 ;
			RECT 2.515 2.305 2.795 5.58 ;
			LAYER M1 ;
			RECT 3.695 2.335 3.975 5.58 ;
			LAYER M1 ;
			RECT 2.5 2.13 2.82 2.305 ;
			LAYER M1 ;
			RECT 3.675 2.13 3.995 2.335 ;
			LAYER M1 ;
			RECT 4.875 2.32 5.155 5.58 ;
			LAYER M1 ;
			RECT 2.5 2.125 3.995 2.13 ;
			LAYER M1 ;
			RECT 4.855 2.125 5.175 2.32 ;
			LAYER M1 ;
			RECT 6.055 2.305 6.335 5.58 ;
			LAYER M1 ;
			RECT 7.235 2.335 7.515 5.58 ;
			LAYER M1 ;
			RECT 6.04 2.13 6.36 2.305 ;
			LAYER M1 ;
			RECT 7.215 2.13 7.535 2.335 ;
			LAYER M1 ;
			RECT 8.415 2.32 8.695 5.58 ;
			LAYER M1 ;
			RECT 6.04 2.125 7.535 2.13 ;
			LAYER M1 ;
			RECT 8.395 2.125 8.715 2.32 ;
			LAYER M1 ;
			RECT 9.595 2.305 9.875 5.58 ;
			LAYER M1 ;
			RECT 10.775 2.335 11.055 5.58 ;
			LAYER M1 ;
			RECT 9.58 2.13 9.9 2.305 ;
			LAYER M1 ;
			RECT 10.755 2.13 11.075 2.335 ;
			LAYER M1 ;
			RECT 11.955 2.32 12.235 5.58 ;
			LAYER M1 ;
			RECT 9.58 2.125 11.075 2.13 ;
			LAYER M1 ;
			RECT 11.935 2.125 12.255 2.32 ;
			LAYER M1 ;
			RECT 13.135 2.305 13.415 5.58 ;
			LAYER M1 ;
			RECT 14.315 2.335 14.595 5.58 ;
			LAYER M1 ;
			RECT 13.12 2.13 13.44 2.305 ;
			LAYER M1 ;
			RECT 14.295 2.13 14.615 2.335 ;
			LAYER M1 ;
			RECT 15.495 2.32 15.775 5.58 ;
			LAYER M1 ;
			RECT 13.12 2.125 14.615 2.13 ;
			LAYER M1 ;
			RECT 15.475 2.125 15.795 2.32 ;
			LAYER M1 ;
			RECT 16.675 2.305 16.955 5.58 ;
			LAYER M1 ;
			RECT 17.855 2.335 18.135 5.58 ;
			LAYER M1 ;
			RECT 16.66 2.13 16.98 2.305 ;
			LAYER M1 ;
			RECT 17.835 2.13 18.155 2.335 ;
			LAYER M1 ;
			RECT 19.035 2.32 19.315 5.58 ;
			LAYER M1 ;
			RECT 16.66 2.125 18.155 2.13 ;
			LAYER M1 ;
			RECT 19.015 2.125 19.335 2.32 ;
			LAYER M1 ;
			RECT 20.215 2.305 20.495 5.58 ;
			LAYER M1 ;
			RECT 21.395 2.335 21.675 5.58 ;
			LAYER M1 ;
			RECT 20.2 2.13 20.52 2.305 ;
			LAYER M1 ;
			RECT 21.375 2.13 21.695 2.335 ;
			LAYER M1 ;
			RECT 22.575 2.32 22.855 5.58 ;
			LAYER M1 ;
			RECT 20.2 2.125 21.695 2.13 ;
			LAYER M1 ;
			RECT 22.555 2.125 22.875 2.32 ;
			LAYER M1 ;
			RECT 23.755 2.305 24.035 5.58 ;
			LAYER M1 ;
			RECT 24.935 2.335 25.215 5.58 ;
			LAYER M1 ;
			RECT 26.115 2.335 26.395 5.58 ;
			LAYER M1 ;
			RECT 23.74 2.13 24.06 2.305 ;
			LAYER M1 ;
			RECT 24.915 2.13 25.235 2.335 ;
			LAYER M1 ;
			RECT 23.74 2.125 25.235 2.13 ;
			LAYER M1 ;
			RECT 26.095 2.13 26.415 2.335 ;
			LAYER M1 ;
			RECT 27.295 2.305 27.575 5.58 ;
			LAYER M1 ;
			RECT 28.475 2.32 28.755 5.58 ;
			LAYER M1 ;
			RECT 27.27 2.13 27.59 2.305 ;
			LAYER M1 ;
			RECT 26.095 2.125 27.59 2.13 ;
			LAYER M1 ;
			RECT 28.455 2.125 28.775 2.32 ;
			LAYER M1 ;
			RECT 1.315 1.885 28.775 2.125 ;
			LAYER M1 ;
			RECT 1.315 1.64 1.635 1.885 ;
			LAYER M1 ;
			RECT 1.335 0.62 1.615 1.64 ;
			LAYER M1 ;
			RECT 2.5 1.625 2.82 1.885 ;
			LAYER M1 ;
			RECT 3.675 1.655 3.995 1.885 ;
			LAYER M1 ;
			RECT 2.515 0.62 2.795 1.625 ;
			LAYER M1 ;
			RECT 3.695 0.62 3.975 1.655 ;
			LAYER M1 ;
			RECT 4.855 1.64 5.175 1.885 ;
			LAYER M1 ;
			RECT 4.875 0.62 5.155 1.64 ;
			LAYER M1 ;
			RECT 6.04 1.625 6.36 1.885 ;
			LAYER M1 ;
			RECT 7.215 1.655 7.535 1.885 ;
			LAYER M1 ;
			RECT 6.055 0.62 6.335 1.625 ;
			LAYER M1 ;
			RECT 7.235 0.62 7.515 1.655 ;
			LAYER M1 ;
			RECT 8.395 1.64 8.715 1.885 ;
			LAYER M1 ;
			RECT 8.415 0.62 8.695 1.64 ;
			LAYER M1 ;
			RECT 9.58 1.625 9.9 1.885 ;
			LAYER M1 ;
			RECT 10.755 1.655 11.075 1.885 ;
			LAYER M1 ;
			RECT 9.595 0.62 9.875 1.625 ;
			LAYER M1 ;
			RECT 10.775 0.62 11.055 1.655 ;
			LAYER M1 ;
			RECT 11.935 1.64 12.255 1.885 ;
			LAYER M1 ;
			RECT 11.955 0.62 12.235 1.64 ;
			LAYER M1 ;
			RECT 13.12 1.625 13.44 1.885 ;
			LAYER M1 ;
			RECT 14.295 1.655 14.615 1.885 ;
			LAYER M1 ;
			RECT 13.135 0.62 13.415 1.625 ;
			LAYER M1 ;
			RECT 14.315 0.62 14.595 1.655 ;
			LAYER M1 ;
			RECT 15.475 1.64 15.795 1.885 ;
			LAYER M1 ;
			RECT 15.495 0.62 15.775 1.64 ;
			LAYER M1 ;
			RECT 16.66 1.625 16.98 1.885 ;
			LAYER M1 ;
			RECT 17.835 1.655 18.155 1.885 ;
			LAYER M1 ;
			RECT 16.675 0.62 16.955 1.625 ;
			LAYER M1 ;
			RECT 17.855 0.62 18.135 1.655 ;
			LAYER M1 ;
			RECT 19.015 1.64 19.335 1.885 ;
			LAYER M1 ;
			RECT 19.035 0.62 19.315 1.64 ;
			LAYER M1 ;
			RECT 20.2 1.625 20.52 1.885 ;
			LAYER M1 ;
			RECT 21.375 1.655 21.695 1.885 ;
			LAYER M1 ;
			RECT 20.215 0.62 20.495 1.625 ;
			LAYER M1 ;
			RECT 21.395 0.62 21.675 1.655 ;
			LAYER M1 ;
			RECT 22.555 1.64 22.875 1.885 ;
			LAYER M1 ;
			RECT 22.575 0.62 22.855 1.64 ;
			LAYER M1 ;
			RECT 23.74 1.625 24.06 1.885 ;
			LAYER M1 ;
			RECT 24.915 1.655 25.235 1.885 ;
			LAYER M1 ;
			RECT 26.095 1.655 26.415 1.885 ;
			LAYER M1 ;
			RECT 23.755 0.62 24.035 1.625 ;
			LAYER M1 ;
			RECT 24.935 0.62 25.215 1.655 ;
			LAYER M1 ;
			RECT 26.115 0.62 26.395 1.655 ;
			LAYER M1 ;
			RECT 27.27 1.625 27.59 1.885 ;
			LAYER M1 ;
			RECT 28.455 1.64 28.775 1.885 ;
			LAYER M1 ;
			RECT 27.295 0.62 27.575 1.625 ;
			LAYER M1 ;
			RECT 28.475 0.62 28.755 1.64 ;
			LAYER VIA1 ;
			RECT 1.365 2.09 1.585 2.31 ;
			LAYER VIA1 ;
			RECT 2.55 2.075 2.77 2.295 ;
			LAYER VIA1 ;
			RECT 3.725 2.105 3.945 2.325 ;
			LAYER VIA1 ;
			RECT 4.905 2.09 5.125 2.31 ;
			LAYER VIA1 ;
			RECT 6.09 2.075 6.31 2.295 ;
			LAYER VIA1 ;
			RECT 7.265 2.105 7.485 2.325 ;
			LAYER VIA1 ;
			RECT 8.445 2.09 8.665 2.31 ;
			LAYER VIA1 ;
			RECT 9.63 2.075 9.85 2.295 ;
			LAYER VIA1 ;
			RECT 10.805 2.105 11.025 2.325 ;
			LAYER VIA1 ;
			RECT 11.985 2.09 12.205 2.31 ;
			LAYER VIA1 ;
			RECT 13.17 2.075 13.39 2.295 ;
			LAYER VIA1 ;
			RECT 14.345 2.105 14.565 2.325 ;
			LAYER VIA1 ;
			RECT 15.525 2.09 15.745 2.31 ;
			LAYER VIA1 ;
			RECT 16.71 2.075 16.93 2.295 ;
			LAYER VIA1 ;
			RECT 17.885 2.105 18.105 2.325 ;
			LAYER VIA1 ;
			RECT 19.065 2.09 19.285 2.31 ;
			LAYER VIA1 ;
			RECT 20.25 2.075 20.47 2.295 ;
			LAYER VIA1 ;
			RECT 21.425 2.105 21.645 2.325 ;
			LAYER VIA1 ;
			RECT 22.605 2.09 22.825 2.31 ;
			LAYER VIA1 ;
			RECT 23.79 2.075 24.01 2.295 ;
			LAYER VIA1 ;
			RECT 24.965 2.105 25.185 2.325 ;
			LAYER VIA1 ;
			RECT 26.145 2.105 26.365 2.325 ;
			LAYER VIA1 ;
			RECT 27.32 2.075 27.54 2.295 ;
			LAYER VIA1 ;
			RECT 28.505 2.09 28.725 2.31 ;
			LAYER VIA1 ;
			RECT 1.365 1.65 1.585 1.87 ;
			LAYER VIA1 ;
			RECT 2.55 1.635 2.77 1.855 ;
			LAYER VIA1 ;
			RECT 3.725 1.665 3.945 1.885 ;
			LAYER VIA1 ;
			RECT 4.905 1.65 5.125 1.87 ;
			LAYER VIA1 ;
			RECT 6.09 1.635 6.31 1.855 ;
			LAYER VIA1 ;
			RECT 7.265 1.665 7.485 1.885 ;
			LAYER VIA1 ;
			RECT 8.445 1.65 8.665 1.87 ;
			LAYER VIA1 ;
			RECT 9.63 1.635 9.85 1.855 ;
			LAYER VIA1 ;
			RECT 10.805 1.665 11.025 1.885 ;
			LAYER VIA1 ;
			RECT 11.985 1.65 12.205 1.87 ;
			LAYER VIA1 ;
			RECT 13.17 1.635 13.39 1.855 ;
			LAYER VIA1 ;
			RECT 14.345 1.665 14.565 1.885 ;
			LAYER VIA1 ;
			RECT 15.525 1.65 15.745 1.87 ;
			LAYER VIA1 ;
			RECT 16.71 1.635 16.93 1.855 ;
			LAYER VIA1 ;
			RECT 17.885 1.665 18.105 1.885 ;
			LAYER VIA1 ;
			RECT 19.065 1.65 19.285 1.87 ;
			LAYER VIA1 ;
			RECT 20.25 1.635 20.47 1.855 ;
			LAYER VIA1 ;
			RECT 21.425 1.665 21.645 1.885 ;
			LAYER VIA1 ;
			RECT 22.605 1.65 22.825 1.87 ;
			LAYER VIA1 ;
			RECT 23.79 1.635 24.01 1.855 ;
			LAYER VIA1 ;
			RECT 24.965 1.665 25.185 1.885 ;
			LAYER VIA1 ;
			RECT 26.145 1.665 26.365 1.885 ;
			LAYER VIA1 ;
			RECT 27.32 1.635 27.54 1.855 ;
			LAYER VIA1 ;
			RECT 28.505 1.65 28.725 1.87 ;
			LAYER M2 ;
			RECT 0.12 0.66 29.97 2.58 ;
		END
	END out
	PIN GND
		DIRECTION inout ;
		USE GROUND ;
		PORT
			LAYER M1 ;
			RECT 0.155 0.42 0.435 1.575 ;
			LAYER M1 ;
			RECT 0.745 0.42 1.025 1.575 ;
			LAYER M1 ;
			RECT 1.925 0.42 2.205 1.575 ;
			LAYER M1 ;
			RECT 3.105 0.42 3.385 1.575 ;
			LAYER M1 ;
			RECT 4.285 0.42 4.565 1.575 ;
			LAYER M1 ;
			RECT 5.465 0.42 5.745 1.575 ;
			LAYER M1 ;
			RECT 6.645 0.42 6.925 1.575 ;
			LAYER M1 ;
			RECT 7.825 0.42 8.105 1.575 ;
			LAYER M1 ;
			RECT 9.005 0.42 9.285 1.575 ;
			LAYER M1 ;
			RECT 10.185 0.42 10.465 1.575 ;
			LAYER M1 ;
			RECT 11.365 0.42 11.645 1.575 ;
			LAYER M1 ;
			RECT 12.545 0.42 12.825 1.575 ;
			LAYER M1 ;
			RECT 13.725 0.42 14.005 1.575 ;
			LAYER M1 ;
			RECT 14.905 0.42 15.185 1.575 ;
			LAYER M1 ;
			RECT 16.085 0.42 16.365 1.575 ;
			LAYER M1 ;
			RECT 17.265 0.42 17.545 1.575 ;
			LAYER M1 ;
			RECT 18.445 0.42 18.725 1.575 ;
			LAYER M1 ;
			RECT 19.625 0.42 19.905 1.575 ;
			LAYER M1 ;
			RECT 20.805 0.42 21.085 1.575 ;
			LAYER M1 ;
			RECT 21.985 0.42 22.265 1.575 ;
			LAYER M1 ;
			RECT 23.165 0.42 23.445 1.575 ;
			LAYER M1 ;
			RECT 24.345 0.42 24.625 1.575 ;
			LAYER M1 ;
			RECT 25.525 0.42 25.805 1.575 ;
			LAYER M1 ;
			RECT 26.705 0.42 26.985 1.575 ;
			LAYER M1 ;
			RECT 27.885 0.42 28.165 1.575 ;
			LAYER M1 ;
			RECT 29.065 0.42 29.345 1.575 ;
			LAYER M1 ;
			RECT 29.655 0.42 29.935 1.575 ;
			LAYER M1 ;
			RECT 0 0.35 29.935 0.42 ;
			LAYER M1 ;
			RECT 0 -0.42 30.38 0.35 ;
			LAYER VIA1 ;
			RECT 0.82 -0.11 1.04 0.11 ;
			LAYER VIA1 ;
			RECT 1.44 -0.11 1.66 0.11 ;
			LAYER VIA1 ;
			RECT 2.06 -0.11 2.28 0.11 ;
			LAYER VIA1 ;
			RECT 2.68 -0.11 2.9 0.11 ;
			LAYER VIA1 ;
			RECT 3.3 -0.11 3.52 0.11 ;
			LAYER VIA1 ;
			RECT 3.92 -0.11 4.14 0.11 ;
			LAYER VIA1 ;
			RECT 4.54 -0.11 4.76 0.11 ;
			LAYER VIA1 ;
			RECT 5.16 -0.11 5.38 0.11 ;
			LAYER VIA1 ;
			RECT 7.02 -0.11 7.24 0.11 ;
			LAYER VIA1 ;
			RECT 7.64 -0.11 7.86 0.11 ;
			LAYER VIA1 ;
			RECT 8.26 -0.11 8.48 0.11 ;
			LAYER VIA1 ;
			RECT 8.88 -0.11 9.1 0.11 ;
			LAYER VIA1 ;
			RECT 9.5 -0.11 9.72 0.11 ;
			LAYER VIA1 ;
			RECT 10.12 -0.11 10.34 0.11 ;
			LAYER VIA1 ;
			RECT 10.74 -0.11 10.96 0.11 ;
			LAYER VIA1 ;
			RECT 11.36 -0.11 11.58 0.11 ;
			LAYER VIA1 ;
			RECT 13.22 -0.11 13.44 0.11 ;
			LAYER VIA1 ;
			RECT 13.84 -0.11 14.06 0.11 ;
			LAYER VIA1 ;
			RECT 14.46 -0.11 14.68 0.11 ;
			LAYER VIA1 ;
			RECT 15.08 -0.11 15.3 0.11 ;
			LAYER VIA1 ;
			RECT 15.7 -0.11 15.92 0.11 ;
			LAYER VIA1 ;
			RECT 16.32 -0.11 16.54 0.11 ;
			LAYER VIA1 ;
			RECT 16.94 -0.11 17.16 0.11 ;
			LAYER VIA1 ;
			RECT 17.56 -0.11 17.78 0.11 ;
			LAYER VIA1 ;
			RECT 19.42 -0.11 19.64 0.11 ;
			LAYER VIA1 ;
			RECT 20.04 -0.11 20.26 0.11 ;
			LAYER VIA1 ;
			RECT 20.66 -0.11 20.88 0.11 ;
			LAYER VIA1 ;
			RECT 21.28 -0.11 21.5 0.11 ;
			LAYER VIA1 ;
			RECT 21.9 -0.11 22.12 0.11 ;
			LAYER VIA1 ;
			RECT 22.52 -0.11 22.74 0.11 ;
			LAYER VIA1 ;
			RECT 23.14 -0.11 23.36 0.11 ;
			LAYER VIA1 ;
			RECT 23.76 -0.11 23.98 0.11 ;
			LAYER VIA1 ;
			RECT 25.62 -0.11 25.84 0.11 ;
			LAYER VIA1 ;
			RECT 26.24 -0.11 26.46 0.11 ;
			LAYER VIA1 ;
			RECT 26.86 -0.11 27.08 0.11 ;
			LAYER VIA1 ;
			RECT 27.48 -0.11 27.7 0.11 ;
			LAYER VIA1 ;
			RECT 28.1 -0.11 28.32 0.11 ;
			LAYER VIA1 ;
			RECT 28.72 -0.11 28.94 0.11 ;
			LAYER VIA1 ;
			RECT 29.34 -0.11 29.56 0.11 ;
			LAYER VIA1 ;
			RECT 29.96 -0.11 30.18 0.11 ;
			LAYER M2 ;
			RECT 0 -0.42 30.38 0.42 ;
		END
	END GND
	PIN VDD
		DIRECTION inout ;
		USE POWER ;
		PORT
			LAYER M1 ;
			RECT 0 5.78 30.38 6.62 ;
			LAYER M1 ;
			RECT 0.155 3.595 0.435 5.78 ;
			LAYER M1 ;
			RECT 0.745 3.595 1.025 5.78 ;
			LAYER M1 ;
			RECT 1.925 3.595 2.205 5.78 ;
			LAYER M1 ;
			RECT 3.105 3.595 3.385 5.78 ;
			LAYER M1 ;
			RECT 4.285 3.595 4.565 5.78 ;
			LAYER M1 ;
			RECT 5.465 3.595 5.745 5.78 ;
			LAYER M1 ;
			RECT 6.645 3.595 6.925 5.78 ;
			LAYER M1 ;
			RECT 7.825 3.595 8.105 5.78 ;
			LAYER M1 ;
			RECT 9.005 3.595 9.285 5.78 ;
			LAYER M1 ;
			RECT 10.185 3.595 10.465 5.78 ;
			LAYER M1 ;
			RECT 11.365 3.595 11.645 5.78 ;
			LAYER M1 ;
			RECT 12.545 3.595 12.825 5.78 ;
			LAYER M1 ;
			RECT 13.725 3.595 14.005 5.78 ;
			LAYER M1 ;
			RECT 14.905 3.595 15.185 5.78 ;
			LAYER M1 ;
			RECT 16.085 3.595 16.365 5.78 ;
			LAYER M1 ;
			RECT 17.265 3.595 17.545 5.78 ;
			LAYER M1 ;
			RECT 18.445 3.595 18.725 5.78 ;
			LAYER M1 ;
			RECT 19.625 3.595 19.905 5.78 ;
			LAYER M1 ;
			RECT 20.805 3.595 21.085 5.78 ;
			LAYER M1 ;
			RECT 21.985 3.595 22.265 5.78 ;
			LAYER M1 ;
			RECT 23.165 3.595 23.445 5.78 ;
			LAYER M1 ;
			RECT 24.345 3.595 24.625 5.78 ;
			LAYER M1 ;
			RECT 25.525 3.595 25.805 5.78 ;
			LAYER M1 ;
			RECT 26.705 3.595 26.985 5.78 ;
			LAYER M1 ;
			RECT 27.885 3.595 28.165 5.78 ;
			LAYER M1 ;
			RECT 29.065 3.595 29.345 5.78 ;
			LAYER M1 ;
			RECT 29.655 3.595 29.935 5.78 ;
			LAYER VIA1 ;
			RECT 0.82 6.09 1.04 6.31 ;
			LAYER VIA1 ;
			RECT 1.44 6.09 1.66 6.31 ;
			LAYER VIA1 ;
			RECT 2.06 6.09 2.28 6.31 ;
			LAYER VIA1 ;
			RECT 2.68 6.09 2.9 6.31 ;
			LAYER VIA1 ;
			RECT 3.3 6.09 3.52 6.31 ;
			LAYER VIA1 ;
			RECT 3.92 6.09 4.14 6.31 ;
			LAYER VIA1 ;
			RECT 4.54 6.09 4.76 6.31 ;
			LAYER VIA1 ;
			RECT 5.16 6.09 5.38 6.31 ;
			LAYER VIA1 ;
			RECT 7.02 6.09 7.24 6.31 ;
			LAYER VIA1 ;
			RECT 7.64 6.09 7.86 6.31 ;
			LAYER VIA1 ;
			RECT 8.26 6.09 8.48 6.31 ;
			LAYER VIA1 ;
			RECT 8.88 6.09 9.1 6.31 ;
			LAYER VIA1 ;
			RECT 9.5 6.09 9.72 6.31 ;
			LAYER VIA1 ;
			RECT 10.12 6.09 10.34 6.31 ;
			LAYER VIA1 ;
			RECT 10.74 6.09 10.96 6.31 ;
			LAYER VIA1 ;
			RECT 11.36 6.09 11.58 6.31 ;
			LAYER VIA1 ;
			RECT 13.22 6.09 13.44 6.31 ;
			LAYER VIA1 ;
			RECT 13.84 6.09 14.06 6.31 ;
			LAYER VIA1 ;
			RECT 14.46 6.09 14.68 6.31 ;
			LAYER VIA1 ;
			RECT 15.08 6.09 15.3 6.31 ;
			LAYER VIA1 ;
			RECT 15.7 6.09 15.92 6.31 ;
			LAYER VIA1 ;
			RECT 16.32 6.09 16.54 6.31 ;
			LAYER VIA1 ;
			RECT 16.94 6.09 17.16 6.31 ;
			LAYER VIA1 ;
			RECT 17.56 6.09 17.78 6.31 ;
			LAYER VIA1 ;
			RECT 19.42 6.09 19.64 6.31 ;
			LAYER VIA1 ;
			RECT 20.04 6.09 20.26 6.31 ;
			LAYER VIA1 ;
			RECT 20.66 6.09 20.88 6.31 ;
			LAYER VIA1 ;
			RECT 21.28 6.09 21.5 6.31 ;
			LAYER VIA1 ;
			RECT 21.9 6.09 22.12 6.31 ;
			LAYER VIA1 ;
			RECT 22.52 6.09 22.74 6.31 ;
			LAYER VIA1 ;
			RECT 23.14 6.09 23.36 6.31 ;
			LAYER VIA1 ;
			RECT 23.76 6.09 23.98 6.31 ;
			LAYER VIA1 ;
			RECT 25.62 6.09 25.84 6.31 ;
			LAYER VIA1 ;
			RECT 26.24 6.09 26.46 6.31 ;
			LAYER VIA1 ;
			RECT 26.86 6.09 27.08 6.31 ;
			LAYER VIA1 ;
			RECT 27.48 6.09 27.7 6.31 ;
			LAYER VIA1 ;
			RECT 28.1 6.09 28.32 6.31 ;
			LAYER VIA1 ;
			RECT 28.72 6.09 28.94 6.31 ;
			LAYER VIA1 ;
			RECT 29.34 6.09 29.56 6.31 ;
			LAYER VIA1 ;
			RECT 29.96 6.09 30.18 6.31 ;
			LAYER M2 ;
			RECT 0 5.78 30.38 6.62 ;
		END
	END VDD
	PIN in
		DIRECTION input ;
		USE SIGNAL ;
		PORT
			LAYER M1 ;
			RECT 1.94 2.75 2.18 3.35 ;
			LAYER M1 ;
			RECT 3.13 2.735 3.37 3.335 ;
			LAYER M1 ;
			RECT 5.48 2.75 5.72 3.35 ;
			LAYER M1 ;
			RECT 6.67 2.735 6.91 3.335 ;
			LAYER M1 ;
			RECT 9.02 2.75 9.26 3.35 ;
			LAYER M1 ;
			RECT 10.21 2.735 10.45 3.335 ;
			LAYER M1 ;
			RECT 12.56 2.75 12.8 3.35 ;
			LAYER M1 ;
			RECT 13.75 2.735 13.99 3.335 ;
			LAYER M1 ;
			RECT 16.1 2.75 16.34 3.35 ;
			LAYER M1 ;
			RECT 17.29 2.735 17.53 3.335 ;
			LAYER M1 ;
			RECT 19.64 2.75 19.88 3.35 ;
			LAYER M1 ;
			RECT 20.83 2.735 21.07 3.335 ;
			LAYER M1 ;
			RECT 23.18 2.75 23.42 3.35 ;
			LAYER M1 ;
			RECT 24.37 2.735 24.61 3.335 ;
			LAYER M1 ;
			RECT 26.72 2.735 26.96 3.335 ;
			LAYER M1 ;
			RECT 27.91 2.75 28.15 3.35 ;
			LAYER VIA1 ;
			RECT 1.95 3.065 2.17 3.285 ;
			LAYER VIA1 ;
			RECT 3.14 3.065 3.36 3.285 ;
			LAYER VIA1 ;
			RECT 5.49 3.065 5.71 3.285 ;
			LAYER VIA1 ;
			RECT 6.68 3.065 6.9 3.285 ;
			LAYER VIA1 ;
			RECT 9.03 3.065 9.25 3.285 ;
			LAYER VIA1 ;
			RECT 10.22 3.065 10.44 3.285 ;
			LAYER VIA1 ;
			RECT 12.57 3.065 12.79 3.285 ;
			LAYER VIA1 ;
			RECT 13.76 3.065 13.98 3.285 ;
			LAYER VIA1 ;
			RECT 16.11 3.065 16.33 3.285 ;
			LAYER VIA1 ;
			RECT 17.3 3.065 17.52 3.285 ;
			LAYER VIA1 ;
			RECT 19.65 3.065 19.87 3.285 ;
			LAYER VIA1 ;
			RECT 20.84 3.065 21.06 3.285 ;
			LAYER VIA1 ;
			RECT 23.19 3.065 23.41 3.285 ;
			LAYER VIA1 ;
			RECT 24.38 3.065 24.6 3.285 ;
			LAYER VIA1 ;
			RECT 26.73 3.065 26.95 3.285 ;
			LAYER VIA1 ;
			RECT 27.92 3.065 28.14 3.285 ;
			LAYER M2 ;
			RECT 0.12 3.29 29.97 3.53 ;
			LAYER M2 ;
			RECT 1.94 3.015 2.18 3.29 ;
			LAYER M2 ;
			RECT 3.13 3.015 3.37 3.29 ;
			LAYER M2 ;
			RECT 5.48 3.015 5.72 3.29 ;
			LAYER M2 ;
			RECT 6.67 3.015 6.91 3.29 ;
			LAYER M2 ;
			RECT 9.02 3.015 9.26 3.29 ;
			LAYER M2 ;
			RECT 10.21 3.015 10.45 3.29 ;
			LAYER M2 ;
			RECT 12.56 3.015 12.8 3.29 ;
			LAYER M2 ;
			RECT 13.75 3.015 13.99 3.29 ;
			LAYER M2 ;
			RECT 16.1 3.015 16.34 3.29 ;
			LAYER M2 ;
			RECT 17.29 3.015 17.53 3.29 ;
			LAYER M2 ;
			RECT 19.64 3.015 19.88 3.29 ;
			LAYER M2 ;
			RECT 20.83 3.015 21.07 3.29 ;
			LAYER M2 ;
			RECT 23.18 3.015 23.42 3.29 ;
			LAYER M2 ;
			RECT 24.37 3.015 24.61 3.29 ;
			LAYER M2 ;
			RECT 26.72 3.015 26.96 3.29 ;
			LAYER M2 ;
			RECT 27.91 3.015 28.15 3.29 ;
		END
		ANTENNASIZE 23.1 ;
	END in
	OBS
	END
END MMI_INVH
MACRO MMI_INVH144
	CLASS CORE ;
	FOREIGN MMI_INVH144 0 0 ;
	SIZE 34.1 BY 6.2 ;
	SYMMETRY X Y ;
	SITE CORE1 ;
	PIN out
		DIRECTION output ;
		USE SIGNAL ;
		PORT
			LAYER M1 ;
			RECT 1.335 2.32 1.615 5.58 ;
			LAYER M1 ;
			RECT 1.315 2.125 1.635 2.32 ;
			LAYER M1 ;
			RECT 2.515 2.305 2.795 5.58 ;
			LAYER M1 ;
			RECT 3.695 2.335 3.975 5.58 ;
			LAYER M1 ;
			RECT 2.5 2.13 2.82 2.305 ;
			LAYER M1 ;
			RECT 3.675 2.13 3.995 2.335 ;
			LAYER M1 ;
			RECT 4.875 2.32 5.155 5.58 ;
			LAYER M1 ;
			RECT 2.5 2.125 3.995 2.13 ;
			LAYER M1 ;
			RECT 4.855 2.125 5.175 2.32 ;
			LAYER M1 ;
			RECT 6.055 2.305 6.335 5.58 ;
			LAYER M1 ;
			RECT 7.235 2.335 7.515 5.58 ;
			LAYER M1 ;
			RECT 6.04 2.13 6.36 2.305 ;
			LAYER M1 ;
			RECT 7.215 2.13 7.535 2.335 ;
			LAYER M1 ;
			RECT 8.415 2.32 8.695 5.58 ;
			LAYER M1 ;
			RECT 6.04 2.125 7.535 2.13 ;
			LAYER M1 ;
			RECT 8.395 2.125 8.715 2.32 ;
			LAYER M1 ;
			RECT 9.595 2.305 9.875 5.58 ;
			LAYER M1 ;
			RECT 10.775 2.335 11.055 5.58 ;
			LAYER M1 ;
			RECT 9.58 2.13 9.9 2.305 ;
			LAYER M1 ;
			RECT 10.755 2.13 11.075 2.335 ;
			LAYER M1 ;
			RECT 11.955 2.32 12.235 5.58 ;
			LAYER M1 ;
			RECT 9.58 2.125 11.075 2.13 ;
			LAYER M1 ;
			RECT 11.935 2.125 12.255 2.32 ;
			LAYER M1 ;
			RECT 13.135 2.305 13.415 5.58 ;
			LAYER M1 ;
			RECT 14.315 2.335 14.595 5.58 ;
			LAYER M1 ;
			RECT 13.12 2.13 13.44 2.305 ;
			LAYER M1 ;
			RECT 14.295 2.13 14.615 2.335 ;
			LAYER M1 ;
			RECT 15.495 2.32 15.775 5.58 ;
			LAYER M1 ;
			RECT 13.12 2.125 14.615 2.13 ;
			LAYER M1 ;
			RECT 15.475 2.125 15.795 2.32 ;
			LAYER M1 ;
			RECT 16.675 2.305 16.955 5.58 ;
			LAYER M1 ;
			RECT 17.855 2.335 18.135 5.58 ;
			LAYER M1 ;
			RECT 16.66 2.13 16.98 2.305 ;
			LAYER M1 ;
			RECT 17.835 2.13 18.155 2.335 ;
			LAYER M1 ;
			RECT 19.035 2.32 19.315 5.58 ;
			LAYER M1 ;
			RECT 16.66 2.125 18.155 2.13 ;
			LAYER M1 ;
			RECT 19.015 2.125 19.335 2.32 ;
			LAYER M1 ;
			RECT 20.215 2.305 20.495 5.58 ;
			LAYER M1 ;
			RECT 21.395 2.335 21.675 5.58 ;
			LAYER M1 ;
			RECT 20.2 2.13 20.52 2.305 ;
			LAYER M1 ;
			RECT 21.375 2.13 21.695 2.335 ;
			LAYER M1 ;
			RECT 22.575 2.32 22.855 5.58 ;
			LAYER M1 ;
			RECT 20.2 2.125 21.695 2.13 ;
			LAYER M1 ;
			RECT 22.555 2.125 22.875 2.32 ;
			LAYER M1 ;
			RECT 23.755 2.305 24.035 5.58 ;
			LAYER M1 ;
			RECT 24.935 2.335 25.215 5.58 ;
			LAYER M1 ;
			RECT 23.74 2.13 24.06 2.305 ;
			LAYER M1 ;
			RECT 24.915 2.13 25.235 2.335 ;
			LAYER M1 ;
			RECT 26.115 2.32 26.395 5.58 ;
			LAYER M1 ;
			RECT 23.74 2.125 25.235 2.13 ;
			LAYER M1 ;
			RECT 26.095 2.125 26.415 2.32 ;
			LAYER M1 ;
			RECT 27.295 2.305 27.575 5.58 ;
			LAYER M1 ;
			RECT 28.475 2.335 28.755 5.58 ;
			LAYER M1 ;
			RECT 29.655 2.335 29.935 5.58 ;
			LAYER M1 ;
			RECT 27.28 2.13 27.6 2.305 ;
			LAYER M1 ;
			RECT 28.455 2.13 28.775 2.335 ;
			LAYER M1 ;
			RECT 27.28 2.125 28.775 2.13 ;
			LAYER M1 ;
			RECT 29.635 2.13 29.955 2.335 ;
			LAYER M1 ;
			RECT 30.835 2.305 31.115 5.58 ;
			LAYER M1 ;
			RECT 32.015 2.32 32.295 5.58 ;
			LAYER M1 ;
			RECT 30.81 2.13 31.13 2.305 ;
			LAYER M1 ;
			RECT 29.635 2.125 31.13 2.13 ;
			LAYER M1 ;
			RECT 31.995 2.125 32.315 2.32 ;
			LAYER M1 ;
			RECT 1.315 1.885 32.315 2.125 ;
			LAYER M1 ;
			RECT 1.315 1.64 1.635 1.885 ;
			LAYER M1 ;
			RECT 1.335 0.62 1.615 1.64 ;
			LAYER M1 ;
			RECT 2.5 1.625 2.82 1.885 ;
			LAYER M1 ;
			RECT 3.675 1.655 3.995 1.885 ;
			LAYER M1 ;
			RECT 2.515 0.62 2.795 1.625 ;
			LAYER M1 ;
			RECT 3.695 0.62 3.975 1.655 ;
			LAYER M1 ;
			RECT 4.855 1.64 5.175 1.885 ;
			LAYER M1 ;
			RECT 4.875 0.62 5.155 1.64 ;
			LAYER M1 ;
			RECT 6.04 1.625 6.36 1.885 ;
			LAYER M1 ;
			RECT 7.215 1.655 7.535 1.885 ;
			LAYER M1 ;
			RECT 6.055 0.62 6.335 1.625 ;
			LAYER M1 ;
			RECT 7.235 0.62 7.515 1.655 ;
			LAYER M1 ;
			RECT 8.395 1.64 8.715 1.885 ;
			LAYER M1 ;
			RECT 8.415 0.62 8.695 1.64 ;
			LAYER M1 ;
			RECT 9.58 1.625 9.9 1.885 ;
			LAYER M1 ;
			RECT 10.755 1.655 11.075 1.885 ;
			LAYER M1 ;
			RECT 9.595 0.62 9.875 1.625 ;
			LAYER M1 ;
			RECT 10.775 0.62 11.055 1.655 ;
			LAYER M1 ;
			RECT 11.935 1.64 12.255 1.885 ;
			LAYER M1 ;
			RECT 11.955 0.62 12.235 1.64 ;
			LAYER M1 ;
			RECT 13.12 1.625 13.44 1.885 ;
			LAYER M1 ;
			RECT 14.295 1.655 14.615 1.885 ;
			LAYER M1 ;
			RECT 13.135 0.62 13.415 1.625 ;
			LAYER M1 ;
			RECT 14.315 0.62 14.595 1.655 ;
			LAYER M1 ;
			RECT 15.475 1.64 15.795 1.885 ;
			LAYER M1 ;
			RECT 15.495 0.62 15.775 1.64 ;
			LAYER M1 ;
			RECT 16.66 1.625 16.98 1.885 ;
			LAYER M1 ;
			RECT 17.835 1.655 18.155 1.885 ;
			LAYER M1 ;
			RECT 16.675 0.62 16.955 1.625 ;
			LAYER M1 ;
			RECT 17.855 0.62 18.135 1.655 ;
			LAYER M1 ;
			RECT 19.015 1.64 19.335 1.885 ;
			LAYER M1 ;
			RECT 19.035 0.62 19.315 1.64 ;
			LAYER M1 ;
			RECT 20.2 1.625 20.52 1.885 ;
			LAYER M1 ;
			RECT 21.375 1.655 21.695 1.885 ;
			LAYER M1 ;
			RECT 20.215 0.62 20.495 1.625 ;
			LAYER M1 ;
			RECT 21.395 0.62 21.675 1.655 ;
			LAYER M1 ;
			RECT 22.555 1.64 22.875 1.885 ;
			LAYER M1 ;
			RECT 22.575 0.62 22.855 1.64 ;
			LAYER M1 ;
			RECT 23.74 1.625 24.06 1.885 ;
			LAYER M1 ;
			RECT 24.915 1.655 25.235 1.885 ;
			LAYER M1 ;
			RECT 23.755 0.62 24.035 1.625 ;
			LAYER M1 ;
			RECT 24.935 0.62 25.215 1.655 ;
			LAYER M1 ;
			RECT 26.095 1.64 26.415 1.885 ;
			LAYER M1 ;
			RECT 26.115 0.62 26.395 1.64 ;
			LAYER M1 ;
			RECT 27.28 1.625 27.6 1.885 ;
			LAYER M1 ;
			RECT 28.455 1.655 28.775 1.885 ;
			LAYER M1 ;
			RECT 29.635 1.655 29.955 1.885 ;
			LAYER M1 ;
			RECT 27.295 0.62 27.575 1.625 ;
			LAYER M1 ;
			RECT 28.475 0.62 28.755 1.655 ;
			LAYER M1 ;
			RECT 29.655 0.62 29.935 1.655 ;
			LAYER M1 ;
			RECT 30.81 1.625 31.13 1.885 ;
			LAYER M1 ;
			RECT 31.995 1.64 32.315 1.885 ;
			LAYER M1 ;
			RECT 30.835 0.62 31.115 1.625 ;
			LAYER M1 ;
			RECT 32.015 0.62 32.295 1.64 ;
			LAYER VIA1 ;
			RECT 1.365 2.09 1.585 2.31 ;
			LAYER VIA1 ;
			RECT 2.55 2.075 2.77 2.295 ;
			LAYER VIA1 ;
			RECT 3.725 2.105 3.945 2.325 ;
			LAYER VIA1 ;
			RECT 4.905 2.09 5.125 2.31 ;
			LAYER VIA1 ;
			RECT 6.09 2.075 6.31 2.295 ;
			LAYER VIA1 ;
			RECT 7.265 2.105 7.485 2.325 ;
			LAYER VIA1 ;
			RECT 8.445 2.09 8.665 2.31 ;
			LAYER VIA1 ;
			RECT 9.63 2.075 9.85 2.295 ;
			LAYER VIA1 ;
			RECT 10.805 2.105 11.025 2.325 ;
			LAYER VIA1 ;
			RECT 11.985 2.09 12.205 2.31 ;
			LAYER VIA1 ;
			RECT 13.17 2.075 13.39 2.295 ;
			LAYER VIA1 ;
			RECT 14.345 2.105 14.565 2.325 ;
			LAYER VIA1 ;
			RECT 15.525 2.09 15.745 2.31 ;
			LAYER VIA1 ;
			RECT 16.71 2.075 16.93 2.295 ;
			LAYER VIA1 ;
			RECT 17.885 2.105 18.105 2.325 ;
			LAYER VIA1 ;
			RECT 19.065 2.09 19.285 2.31 ;
			LAYER VIA1 ;
			RECT 20.25 2.075 20.47 2.295 ;
			LAYER VIA1 ;
			RECT 21.425 2.105 21.645 2.325 ;
			LAYER VIA1 ;
			RECT 22.605 2.09 22.825 2.31 ;
			LAYER VIA1 ;
			RECT 23.79 2.075 24.01 2.295 ;
			LAYER VIA1 ;
			RECT 24.965 2.105 25.185 2.325 ;
			LAYER VIA1 ;
			RECT 26.145 2.09 26.365 2.31 ;
			LAYER VIA1 ;
			RECT 27.33 2.075 27.55 2.295 ;
			LAYER VIA1 ;
			RECT 28.505 2.105 28.725 2.325 ;
			LAYER VIA1 ;
			RECT 29.685 2.105 29.905 2.325 ;
			LAYER VIA1 ;
			RECT 30.86 2.075 31.08 2.295 ;
			LAYER VIA1 ;
			RECT 32.045 2.09 32.265 2.31 ;
			LAYER VIA1 ;
			RECT 1.365 1.65 1.585 1.87 ;
			LAYER VIA1 ;
			RECT 2.55 1.635 2.77 1.855 ;
			LAYER VIA1 ;
			RECT 3.725 1.665 3.945 1.885 ;
			LAYER VIA1 ;
			RECT 4.905 1.65 5.125 1.87 ;
			LAYER VIA1 ;
			RECT 6.09 1.635 6.31 1.855 ;
			LAYER VIA1 ;
			RECT 7.265 1.665 7.485 1.885 ;
			LAYER VIA1 ;
			RECT 8.445 1.65 8.665 1.87 ;
			LAYER VIA1 ;
			RECT 9.63 1.635 9.85 1.855 ;
			LAYER VIA1 ;
			RECT 10.805 1.665 11.025 1.885 ;
			LAYER VIA1 ;
			RECT 11.985 1.65 12.205 1.87 ;
			LAYER VIA1 ;
			RECT 13.17 1.635 13.39 1.855 ;
			LAYER VIA1 ;
			RECT 14.345 1.665 14.565 1.885 ;
			LAYER VIA1 ;
			RECT 15.525 1.65 15.745 1.87 ;
			LAYER VIA1 ;
			RECT 16.71 1.635 16.93 1.855 ;
			LAYER VIA1 ;
			RECT 17.885 1.665 18.105 1.885 ;
			LAYER VIA1 ;
			RECT 19.065 1.65 19.285 1.87 ;
			LAYER VIA1 ;
			RECT 20.25 1.635 20.47 1.855 ;
			LAYER VIA1 ;
			RECT 21.425 1.665 21.645 1.885 ;
			LAYER VIA1 ;
			RECT 22.605 1.65 22.825 1.87 ;
			LAYER VIA1 ;
			RECT 23.79 1.635 24.01 1.855 ;
			LAYER VIA1 ;
			RECT 24.965 1.665 25.185 1.885 ;
			LAYER VIA1 ;
			RECT 26.145 1.65 26.365 1.87 ;
			LAYER VIA1 ;
			RECT 27.33 1.635 27.55 1.855 ;
			LAYER VIA1 ;
			RECT 28.505 1.665 28.725 1.885 ;
			LAYER VIA1 ;
			RECT 29.685 1.665 29.905 1.885 ;
			LAYER VIA1 ;
			RECT 30.86 1.635 31.08 1.855 ;
			LAYER VIA1 ;
			RECT 32.045 1.65 32.265 1.87 ;
			LAYER M2 ;
			RECT 0.12 0.66 33.98 2.58 ;
		END
	END out
	PIN GND
		DIRECTION inout ;
		USE GROUND ;
		PORT
			LAYER M1 ;
			RECT 0.155 0.42 0.435 1.575 ;
			LAYER M1 ;
			RECT 0.745 0.42 1.025 1.575 ;
			LAYER M1 ;
			RECT 1.925 0.42 2.205 1.575 ;
			LAYER M1 ;
			RECT 3.105 0.42 3.385 1.575 ;
			LAYER M1 ;
			RECT 4.285 0.42 4.565 1.575 ;
			LAYER M1 ;
			RECT 5.465 0.42 5.745 1.575 ;
			LAYER M1 ;
			RECT 6.645 0.42 6.925 1.575 ;
			LAYER M1 ;
			RECT 7.825 0.42 8.105 1.575 ;
			LAYER M1 ;
			RECT 9.005 0.42 9.285 1.575 ;
			LAYER M1 ;
			RECT 10.185 0.42 10.465 1.575 ;
			LAYER M1 ;
			RECT 11.365 0.42 11.645 1.575 ;
			LAYER M1 ;
			RECT 12.545 0.42 12.825 1.575 ;
			LAYER M1 ;
			RECT 13.725 0.42 14.005 1.575 ;
			LAYER M1 ;
			RECT 14.905 0.42 15.185 1.575 ;
			LAYER M1 ;
			RECT 16.085 0.42 16.365 1.575 ;
			LAYER M1 ;
			RECT 17.265 0.42 17.545 1.575 ;
			LAYER M1 ;
			RECT 18.445 0.42 18.725 1.575 ;
			LAYER M1 ;
			RECT 19.625 0.42 19.905 1.575 ;
			LAYER M1 ;
			RECT 20.805 0.42 21.085 1.575 ;
			LAYER M1 ;
			RECT 21.985 0.42 22.265 1.575 ;
			LAYER M1 ;
			RECT 23.165 0.42 23.445 1.575 ;
			LAYER M1 ;
			RECT 24.345 0.42 24.625 1.575 ;
			LAYER M1 ;
			RECT 25.525 0.42 25.805 1.575 ;
			LAYER M1 ;
			RECT 26.705 0.42 26.985 1.575 ;
			LAYER M1 ;
			RECT 27.885 0.42 28.165 1.575 ;
			LAYER M1 ;
			RECT 29.065 0.42 29.345 1.575 ;
			LAYER M1 ;
			RECT 30.245 0.42 30.525 1.575 ;
			LAYER M1 ;
			RECT 31.425 0.42 31.705 1.575 ;
			LAYER M1 ;
			RECT 32.605 0.42 32.885 1.575 ;
			LAYER M1 ;
			RECT 33.195 0.42 33.475 1.575 ;
			LAYER M1 ;
			RECT 0.155 0.35 33.475 0.42 ;
			LAYER M1 ;
			RECT 0 0.31 33.475 0.35 ;
			LAYER M1 ;
			RECT 0 -0.42 34.1 0.31 ;
			LAYER VIA1 ;
			RECT 0.82 -0.11 1.04 0.11 ;
			LAYER VIA1 ;
			RECT 1.44 -0.11 1.66 0.11 ;
			LAYER VIA1 ;
			RECT 2.06 -0.11 2.28 0.11 ;
			LAYER VIA1 ;
			RECT 2.68 -0.11 2.9 0.11 ;
			LAYER VIA1 ;
			RECT 3.3 -0.11 3.52 0.11 ;
			LAYER VIA1 ;
			RECT 3.92 -0.11 4.14 0.11 ;
			LAYER VIA1 ;
			RECT 4.54 -0.11 4.76 0.11 ;
			LAYER VIA1 ;
			RECT 5.16 -0.11 5.38 0.11 ;
			LAYER VIA1 ;
			RECT 7.02 -0.11 7.24 0.11 ;
			LAYER VIA1 ;
			RECT 7.64 -0.11 7.86 0.11 ;
			LAYER VIA1 ;
			RECT 8.26 -0.11 8.48 0.11 ;
			LAYER VIA1 ;
			RECT 8.88 -0.11 9.1 0.11 ;
			LAYER VIA1 ;
			RECT 9.5 -0.11 9.72 0.11 ;
			LAYER VIA1 ;
			RECT 10.12 -0.11 10.34 0.11 ;
			LAYER VIA1 ;
			RECT 10.74 -0.11 10.96 0.11 ;
			LAYER VIA1 ;
			RECT 11.36 -0.11 11.58 0.11 ;
			LAYER VIA1 ;
			RECT 13.22 -0.11 13.44 0.11 ;
			LAYER VIA1 ;
			RECT 13.84 -0.11 14.06 0.11 ;
			LAYER VIA1 ;
			RECT 14.46 -0.11 14.68 0.11 ;
			LAYER VIA1 ;
			RECT 15.08 -0.11 15.3 0.11 ;
			LAYER VIA1 ;
			RECT 15.7 -0.11 15.92 0.11 ;
			LAYER VIA1 ;
			RECT 16.32 -0.11 16.54 0.11 ;
			LAYER VIA1 ;
			RECT 16.94 -0.11 17.16 0.11 ;
			LAYER VIA1 ;
			RECT 17.56 -0.11 17.78 0.11 ;
			LAYER VIA1 ;
			RECT 19.42 -0.11 19.64 0.11 ;
			LAYER VIA1 ;
			RECT 20.04 -0.11 20.26 0.11 ;
			LAYER VIA1 ;
			RECT 20.66 -0.11 20.88 0.11 ;
			LAYER VIA1 ;
			RECT 21.28 -0.11 21.5 0.11 ;
			LAYER VIA1 ;
			RECT 21.9 -0.11 22.12 0.11 ;
			LAYER VIA1 ;
			RECT 22.52 -0.11 22.74 0.11 ;
			LAYER VIA1 ;
			RECT 23.14 -0.11 23.36 0.11 ;
			LAYER VIA1 ;
			RECT 23.76 -0.11 23.98 0.11 ;
			LAYER VIA1 ;
			RECT 25.62 -0.11 25.84 0.11 ;
			LAYER VIA1 ;
			RECT 26.24 -0.11 26.46 0.11 ;
			LAYER VIA1 ;
			RECT 26.86 -0.11 27.08 0.11 ;
			LAYER VIA1 ;
			RECT 27.48 -0.11 27.7 0.11 ;
			LAYER VIA1 ;
			RECT 28.1 -0.11 28.32 0.11 ;
			LAYER VIA1 ;
			RECT 28.72 -0.11 28.94 0.11 ;
			LAYER VIA1 ;
			RECT 29.34 -0.11 29.56 0.11 ;
			LAYER VIA1 ;
			RECT 29.96 -0.11 30.18 0.11 ;
			LAYER VIA1 ;
			RECT 31.82 -0.11 32.04 0.11 ;
			LAYER VIA1 ;
			RECT 32.44 -0.11 32.66 0.11 ;
			LAYER VIA1 ;
			RECT 33.06 -0.11 33.28 0.11 ;
			LAYER VIA1 ;
			RECT 33.68 -0.11 33.9 0.11 ;
			LAYER M2 ;
			RECT 0 -0.415 34.1 0.42 ;
		END
	END GND
	PIN VDD
		DIRECTION inout ;
		USE POWER ;
		PORT
			LAYER M1 ;
			RECT 0 5.78 34.1 6.62 ;
			LAYER M1 ;
			RECT 0.155 3.595 0.435 5.78 ;
			LAYER M1 ;
			RECT 0.745 3.595 1.025 5.78 ;
			LAYER M1 ;
			RECT 1.925 3.595 2.205 5.78 ;
			LAYER M1 ;
			RECT 3.105 3.595 3.385 5.78 ;
			LAYER M1 ;
			RECT 4.285 3.595 4.565 5.78 ;
			LAYER M1 ;
			RECT 5.465 3.595 5.745 5.78 ;
			LAYER M1 ;
			RECT 6.645 3.595 6.925 5.78 ;
			LAYER M1 ;
			RECT 7.825 3.595 8.105 5.78 ;
			LAYER M1 ;
			RECT 9.005 3.595 9.285 5.78 ;
			LAYER M1 ;
			RECT 10.185 3.595 10.465 5.78 ;
			LAYER M1 ;
			RECT 11.365 3.595 11.645 5.78 ;
			LAYER M1 ;
			RECT 12.545 3.595 12.825 5.78 ;
			LAYER M1 ;
			RECT 13.725 3.595 14.005 5.78 ;
			LAYER M1 ;
			RECT 14.905 3.595 15.185 5.78 ;
			LAYER M1 ;
			RECT 16.085 3.595 16.365 5.78 ;
			LAYER M1 ;
			RECT 17.265 3.595 17.545 5.78 ;
			LAYER M1 ;
			RECT 18.445 3.595 18.725 5.78 ;
			LAYER M1 ;
			RECT 19.625 3.595 19.905 5.78 ;
			LAYER M1 ;
			RECT 20.805 3.595 21.085 5.78 ;
			LAYER M1 ;
			RECT 21.985 3.595 22.265 5.78 ;
			LAYER M1 ;
			RECT 23.165 3.595 23.445 5.78 ;
			LAYER M1 ;
			RECT 24.345 3.595 24.625 5.78 ;
			LAYER M1 ;
			RECT 25.525 3.595 25.805 5.78 ;
			LAYER M1 ;
			RECT 26.705 3.595 26.985 5.78 ;
			LAYER M1 ;
			RECT 27.885 3.595 28.165 5.78 ;
			LAYER M1 ;
			RECT 29.065 3.595 29.345 5.78 ;
			LAYER M1 ;
			RECT 30.245 3.595 30.525 5.78 ;
			LAYER M1 ;
			RECT 31.425 3.595 31.705 5.78 ;
			LAYER M1 ;
			RECT 32.605 3.595 32.885 5.78 ;
			LAYER M1 ;
			RECT 33.195 3.595 33.475 5.78 ;
			LAYER VIA1 ;
			RECT 0.82 6.09 1.04 6.31 ;
			LAYER VIA1 ;
			RECT 1.44 6.09 1.66 6.31 ;
			LAYER VIA1 ;
			RECT 2.06 6.09 2.28 6.31 ;
			LAYER VIA1 ;
			RECT 2.68 6.09 2.9 6.31 ;
			LAYER VIA1 ;
			RECT 3.3 6.09 3.52 6.31 ;
			LAYER VIA1 ;
			RECT 3.92 6.09 4.14 6.31 ;
			LAYER VIA1 ;
			RECT 4.54 6.09 4.76 6.31 ;
			LAYER VIA1 ;
			RECT 5.16 6.09 5.38 6.31 ;
			LAYER VIA1 ;
			RECT 7.02 6.09 7.24 6.31 ;
			LAYER VIA1 ;
			RECT 7.64 6.09 7.86 6.31 ;
			LAYER VIA1 ;
			RECT 8.26 6.09 8.48 6.31 ;
			LAYER VIA1 ;
			RECT 8.88 6.09 9.1 6.31 ;
			LAYER VIA1 ;
			RECT 9.5 6.09 9.72 6.31 ;
			LAYER VIA1 ;
			RECT 10.12 6.09 10.34 6.31 ;
			LAYER VIA1 ;
			RECT 10.74 6.09 10.96 6.31 ;
			LAYER VIA1 ;
			RECT 11.36 6.09 11.58 6.31 ;
			LAYER VIA1 ;
			RECT 13.22 6.09 13.44 6.31 ;
			LAYER VIA1 ;
			RECT 13.84 6.09 14.06 6.31 ;
			LAYER VIA1 ;
			RECT 14.46 6.09 14.68 6.31 ;
			LAYER VIA1 ;
			RECT 15.08 6.09 15.3 6.31 ;
			LAYER VIA1 ;
			RECT 15.7 6.09 15.92 6.31 ;
			LAYER VIA1 ;
			RECT 16.32 6.09 16.54 6.31 ;
			LAYER VIA1 ;
			RECT 16.94 6.09 17.16 6.31 ;
			LAYER VIA1 ;
			RECT 17.56 6.09 17.78 6.31 ;
			LAYER VIA1 ;
			RECT 19.42 6.09 19.64 6.31 ;
			LAYER VIA1 ;
			RECT 20.04 6.09 20.26 6.31 ;
			LAYER VIA1 ;
			RECT 20.66 6.09 20.88 6.31 ;
			LAYER VIA1 ;
			RECT 21.28 6.09 21.5 6.31 ;
			LAYER VIA1 ;
			RECT 21.9 6.09 22.12 6.31 ;
			LAYER VIA1 ;
			RECT 22.52 6.09 22.74 6.31 ;
			LAYER VIA1 ;
			RECT 23.14 6.09 23.36 6.31 ;
			LAYER VIA1 ;
			RECT 23.76 6.09 23.98 6.31 ;
			LAYER VIA1 ;
			RECT 25.62 6.09 25.84 6.31 ;
			LAYER VIA1 ;
			RECT 26.24 6.09 26.46 6.31 ;
			LAYER VIA1 ;
			RECT 26.86 6.09 27.08 6.31 ;
			LAYER VIA1 ;
			RECT 27.48 6.09 27.7 6.31 ;
			LAYER VIA1 ;
			RECT 28.1 6.09 28.32 6.31 ;
			LAYER VIA1 ;
			RECT 28.72 6.09 28.94 6.31 ;
			LAYER VIA1 ;
			RECT 29.34 6.09 29.56 6.31 ;
			LAYER VIA1 ;
			RECT 29.96 6.09 30.18 6.31 ;
			LAYER VIA1 ;
			RECT 31.82 6.09 32.04 6.31 ;
			LAYER VIA1 ;
			RECT 32.44 6.09 32.66 6.31 ;
			LAYER VIA1 ;
			RECT 33.06 6.09 33.28 6.31 ;
			LAYER VIA1 ;
			RECT 33.68 6.09 33.9 6.31 ;
			LAYER M2 ;
			RECT 0 5.78 34.1 6.615 ;
		END
	END VDD
	PIN in
		DIRECTION input ;
		USE SIGNAL ;
		PORT
			LAYER M1 ;
			RECT 1.94 2.75 2.18 3.35 ;
			LAYER M1 ;
			RECT 3.13 2.735 3.37 3.335 ;
			LAYER M1 ;
			RECT 5.48 2.75 5.72 3.35 ;
			LAYER M1 ;
			RECT 6.67 2.735 6.91 3.335 ;
			LAYER M1 ;
			RECT 9.02 2.75 9.26 3.35 ;
			LAYER M1 ;
			RECT 10.21 2.735 10.45 3.335 ;
			LAYER M1 ;
			RECT 12.56 2.75 12.8 3.35 ;
			LAYER M1 ;
			RECT 13.75 2.735 13.99 3.335 ;
			LAYER M1 ;
			RECT 16.1 2.75 16.34 3.35 ;
			LAYER M1 ;
			RECT 17.29 2.735 17.53 3.335 ;
			LAYER M1 ;
			RECT 19.64 2.75 19.88 3.35 ;
			LAYER M1 ;
			RECT 20.83 2.735 21.07 3.335 ;
			LAYER M1 ;
			RECT 23.18 2.75 23.42 3.35 ;
			LAYER M1 ;
			RECT 24.37 2.735 24.61 3.335 ;
			LAYER M1 ;
			RECT 26.72 2.75 26.96 3.35 ;
			LAYER M1 ;
			RECT 27.91 2.735 28.15 3.335 ;
			LAYER M1 ;
			RECT 30.26 2.735 30.5 3.335 ;
			LAYER M1 ;
			RECT 31.45 2.75 31.69 3.35 ;
			LAYER VIA1 ;
			RECT 1.95 3.065 2.17 3.285 ;
			LAYER VIA1 ;
			RECT 3.14 3.065 3.36 3.285 ;
			LAYER VIA1 ;
			RECT 5.49 3.065 5.71 3.285 ;
			LAYER VIA1 ;
			RECT 6.68 3.065 6.9 3.285 ;
			LAYER VIA1 ;
			RECT 9.03 3.065 9.25 3.285 ;
			LAYER VIA1 ;
			RECT 10.22 3.065 10.44 3.285 ;
			LAYER VIA1 ;
			RECT 12.57 3.065 12.79 3.285 ;
			LAYER VIA1 ;
			RECT 13.76 3.065 13.98 3.285 ;
			LAYER VIA1 ;
			RECT 16.11 3.065 16.33 3.285 ;
			LAYER VIA1 ;
			RECT 17.3 3.065 17.52 3.285 ;
			LAYER VIA1 ;
			RECT 19.65 3.065 19.87 3.285 ;
			LAYER VIA1 ;
			RECT 20.84 3.065 21.06 3.285 ;
			LAYER VIA1 ;
			RECT 23.19 3.065 23.41 3.285 ;
			LAYER VIA1 ;
			RECT 24.38 3.065 24.6 3.285 ;
			LAYER VIA1 ;
			RECT 26.73 3.065 26.95 3.285 ;
			LAYER VIA1 ;
			RECT 27.92 3.065 28.14 3.285 ;
			LAYER VIA1 ;
			RECT 30.27 3.065 30.49 3.285 ;
			LAYER VIA1 ;
			RECT 31.46 3.065 31.68 3.285 ;
			LAYER M2 ;
			RECT 0.12 3.29 33.98 3.53 ;
			LAYER M2 ;
			RECT 1.94 3.015 2.18 3.29 ;
			LAYER M2 ;
			RECT 3.13 3.015 3.37 3.29 ;
			LAYER M2 ;
			RECT 5.48 3.015 5.72 3.29 ;
			LAYER M2 ;
			RECT 6.67 3.015 6.91 3.29 ;
			LAYER M2 ;
			RECT 9.02 3.015 9.26 3.29 ;
			LAYER M2 ;
			RECT 10.21 3.015 10.45 3.29 ;
			LAYER M2 ;
			RECT 12.56 3.015 12.8 3.29 ;
			LAYER M2 ;
			RECT 13.75 3.015 13.99 3.29 ;
			LAYER M2 ;
			RECT 16.1 3.015 16.34 3.29 ;
			LAYER M2 ;
			RECT 17.29 3.015 17.53 3.29 ;
			LAYER M2 ;
			RECT 19.64 3.015 19.88 3.29 ;
			LAYER M2 ;
			RECT 20.83 3.015 21.07 3.29 ;
			LAYER M2 ;
			RECT 23.18 3.015 23.42 3.29 ;
			LAYER M2 ;
			RECT 24.37 3.015 24.61 3.29 ;
			LAYER M2 ;
			RECT 26.72 3.015 26.96 3.29 ;
			LAYER M2 ;
			RECT 27.91 3.015 28.15 3.29 ;
			LAYER M2 ;
			RECT 30.26 3.015 30.5 3.29 ;
			LAYER M2 ;
			RECT 31.45 3.015 31.69 3.29 ;
		END
		ANTENNASIZE 25.872 ;
	END in
	OBS
	END
END MMI_INVH144
MACRO MMI_INVH152
	CLASS CORE ;
	FOREIGN MMI_INVH152 0 0 ;
	SIZE 35.34 BY 6.2 ;
	SYMMETRY X Y ;
	SITE CORE1 ;
	PIN out
		DIRECTION output ;
		USE SIGNAL ;
		PORT
			LAYER M1 ;
			RECT 1.335 2.32 1.615 5.48 ;
			LAYER M1 ;
			RECT 1.315 2.125 1.635 2.32 ;
			LAYER M1 ;
			RECT 2.515 2.305 2.795 5.48 ;
			LAYER M1 ;
			RECT 3.695 2.335 3.975 5.48 ;
			LAYER M1 ;
			RECT 2.5 2.13 2.82 2.305 ;
			LAYER M1 ;
			RECT 3.675 2.13 3.995 2.335 ;
			LAYER M1 ;
			RECT 4.875 2.32 5.155 5.48 ;
			LAYER M1 ;
			RECT 4.855 2.13 5.175 2.32 ;
			LAYER M1 ;
			RECT 6.055 2.305 6.335 5.48 ;
			LAYER M1 ;
			RECT 7.235 2.335 7.515 5.48 ;
			LAYER M1 ;
			RECT 6.04 2.13 6.36 2.305 ;
			LAYER M1 ;
			RECT 7.215 2.13 7.535 2.335 ;
			LAYER M1 ;
			RECT 8.415 2.32 8.695 5.48 ;
			LAYER M1 ;
			RECT 8.395 2.13 8.715 2.32 ;
			LAYER M1 ;
			RECT 9.595 2.305 9.875 5.48 ;
			LAYER M1 ;
			RECT 10.775 2.335 11.055 5.48 ;
			LAYER M1 ;
			RECT 9.58 2.13 9.9 2.305 ;
			LAYER M1 ;
			RECT 10.755 2.13 11.075 2.335 ;
			LAYER M1 ;
			RECT 11.955 2.32 12.235 5.48 ;
			LAYER M1 ;
			RECT 11.935 2.13 12.255 2.32 ;
			LAYER M1 ;
			RECT 13.135 2.305 13.415 5.48 ;
			LAYER M1 ;
			RECT 14.315 2.335 14.595 5.48 ;
			LAYER M1 ;
			RECT 2.5 2.125 12.255 2.13 ;
			LAYER M1 ;
			RECT 13.12 2.13 13.44 2.305 ;
			LAYER M1 ;
			RECT 14.295 2.13 14.615 2.335 ;
			LAYER M1 ;
			RECT 15.495 2.32 15.775 5.48 ;
			LAYER M1 ;
			RECT 13.12 2.125 14.615 2.13 ;
			LAYER M1 ;
			RECT 15.475 2.125 15.795 2.32 ;
			LAYER M1 ;
			RECT 16.675 2.305 16.955 5.48 ;
			LAYER M1 ;
			RECT 17.855 2.335 18.135 5.48 ;
			LAYER M1 ;
			RECT 16.66 2.13 16.98 2.305 ;
			LAYER M1 ;
			RECT 17.835 2.13 18.155 2.335 ;
			LAYER M1 ;
			RECT 19.035 2.32 19.315 5.48 ;
			LAYER M1 ;
			RECT 16.66 2.125 18.155 2.13 ;
			LAYER M1 ;
			RECT 19.015 2.125 19.335 2.32 ;
			LAYER M1 ;
			RECT 20.215 2.305 20.495 5.48 ;
			LAYER M1 ;
			RECT 21.395 2.335 21.675 5.48 ;
			LAYER M1 ;
			RECT 20.2 2.13 20.52 2.305 ;
			LAYER M1 ;
			RECT 21.375 2.13 21.695 2.335 ;
			LAYER M1 ;
			RECT 22.575 2.32 22.855 5.48 ;
			LAYER M1 ;
			RECT 20.2 2.125 21.695 2.13 ;
			LAYER M1 ;
			RECT 22.555 2.125 22.875 2.32 ;
			LAYER M1 ;
			RECT 23.755 2.305 24.035 5.48 ;
			LAYER M1 ;
			RECT 24.935 2.335 25.215 5.48 ;
			LAYER M1 ;
			RECT 23.74 2.13 24.06 2.305 ;
			LAYER M1 ;
			RECT 24.915 2.13 25.235 2.335 ;
			LAYER M1 ;
			RECT 26.115 2.32 26.395 5.48 ;
			LAYER M1 ;
			RECT 26.095 2.13 26.415 2.32 ;
			LAYER M1 ;
			RECT 27.295 2.305 27.575 5.48 ;
			LAYER M1 ;
			RECT 28.475 2.335 28.755 5.48 ;
			LAYER M1 ;
			RECT 27.28 2.13 27.6 2.305 ;
			LAYER M1 ;
			RECT 28.455 2.13 28.775 2.335 ;
			LAYER M1 ;
			RECT 29.655 2.32 29.935 5.48 ;
			LAYER M1 ;
			RECT 29.635 2.13 29.955 2.32 ;
			LAYER M1 ;
			RECT 30.835 2.305 31.115 5.48 ;
			LAYER M1 ;
			RECT 32.015 2.335 32.295 5.48 ;
			LAYER M1 ;
			RECT 30.82 2.13 31.14 2.305 ;
			LAYER M1 ;
			RECT 31.995 2.13 32.315 2.335 ;
			LAYER M1 ;
			RECT 33.195 2.32 33.475 5.48 ;
			LAYER M1 ;
			RECT 23.74 2.125 30.215 2.13 ;
			LAYER M1 ;
			RECT 30.82 2.125 32.315 2.13 ;
			LAYER M1 ;
			RECT 33.175 2.125 33.495 2.32 ;
			LAYER M1 ;
			RECT 1.315 1.885 33.495 2.125 ;
			LAYER M1 ;
			RECT 1.315 1.64 1.635 1.885 ;
			LAYER M1 ;
			RECT 1.335 0.62 1.615 1.64 ;
			LAYER M1 ;
			RECT 2.5 1.625 2.82 1.885 ;
			LAYER M1 ;
			RECT 3.675 1.655 3.995 1.885 ;
			LAYER M1 ;
			RECT 2.515 0.62 2.795 1.625 ;
			LAYER M1 ;
			RECT 3.695 0.62 3.975 1.655 ;
			LAYER M1 ;
			RECT 4.855 1.64 5.175 1.885 ;
			LAYER M1 ;
			RECT 4.875 0.62 5.155 1.64 ;
			LAYER M1 ;
			RECT 6.04 1.625 6.36 1.885 ;
			LAYER M1 ;
			RECT 7.215 1.655 7.535 1.885 ;
			LAYER M1 ;
			RECT 6.055 0.62 6.335 1.625 ;
			LAYER M1 ;
			RECT 7.235 0.62 7.515 1.655 ;
			LAYER M1 ;
			RECT 8.395 1.64 8.715 1.885 ;
			LAYER M1 ;
			RECT 8.415 0.62 8.695 1.64 ;
			LAYER M1 ;
			RECT 9.58 1.625 9.9 1.885 ;
			LAYER M1 ;
			RECT 10.755 1.655 11.075 1.885 ;
			LAYER M1 ;
			RECT 9.595 0.62 9.875 1.625 ;
			LAYER M1 ;
			RECT 10.775 0.62 11.055 1.655 ;
			LAYER M1 ;
			RECT 11.935 1.64 12.255 1.885 ;
			LAYER M1 ;
			RECT 11.955 0.62 12.235 1.64 ;
			LAYER M1 ;
			RECT 13.12 1.625 13.44 1.885 ;
			LAYER M1 ;
			RECT 14.295 1.655 14.615 1.885 ;
			LAYER M1 ;
			RECT 13.135 0.62 13.415 1.625 ;
			LAYER M1 ;
			RECT 14.315 0.62 14.595 1.655 ;
			LAYER M1 ;
			RECT 15.475 1.64 15.795 1.885 ;
			LAYER M1 ;
			RECT 15.495 0.62 15.775 1.64 ;
			LAYER M1 ;
			RECT 16.66 1.625 16.98 1.885 ;
			LAYER M1 ;
			RECT 17.835 1.655 18.155 1.885 ;
			LAYER M1 ;
			RECT 16.675 0.62 16.955 1.625 ;
			LAYER M1 ;
			RECT 17.855 0.62 18.135 1.655 ;
			LAYER M1 ;
			RECT 19.015 1.64 19.335 1.885 ;
			LAYER M1 ;
			RECT 19.035 0.62 19.315 1.64 ;
			LAYER M1 ;
			RECT 20.2 1.625 20.52 1.885 ;
			LAYER M1 ;
			RECT 21.375 1.655 21.695 1.885 ;
			LAYER M1 ;
			RECT 20.215 0.62 20.495 1.625 ;
			LAYER M1 ;
			RECT 21.395 0.62 21.675 1.655 ;
			LAYER M1 ;
			RECT 22.555 1.64 22.875 1.885 ;
			LAYER M1 ;
			RECT 22.575 0.62 22.855 1.64 ;
			LAYER M1 ;
			RECT 23.74 1.625 24.06 1.885 ;
			LAYER M1 ;
			RECT 24.915 1.655 25.235 1.885 ;
			LAYER M1 ;
			RECT 23.755 0.62 24.035 1.625 ;
			LAYER M1 ;
			RECT 24.935 0.62 25.215 1.655 ;
			LAYER M1 ;
			RECT 26.095 1.64 26.415 1.885 ;
			LAYER M1 ;
			RECT 26.115 0.62 26.395 1.64 ;
			LAYER M1 ;
			RECT 27.28 1.625 27.6 1.885 ;
			LAYER M1 ;
			RECT 28.455 1.655 28.775 1.885 ;
			LAYER M1 ;
			RECT 27.295 0.62 27.575 1.625 ;
			LAYER M1 ;
			RECT 28.475 0.62 28.755 1.655 ;
			LAYER M1 ;
			RECT 29.635 1.64 29.955 1.885 ;
			LAYER M1 ;
			RECT 29.655 0.62 29.935 1.64 ;
			LAYER M1 ;
			RECT 30.82 1.625 31.14 1.885 ;
			LAYER M1 ;
			RECT 31.995 1.655 32.315 1.885 ;
			LAYER M1 ;
			RECT 30.835 0.62 31.115 1.625 ;
			LAYER M1 ;
			RECT 32.015 0.62 32.295 1.655 ;
			LAYER M1 ;
			RECT 33.175 1.64 33.495 1.885 ;
			LAYER M1 ;
			RECT 33.195 0.62 33.475 1.64 ;
			LAYER VIA1 ;
			RECT 1.365 2.09 1.585 2.31 ;
			LAYER VIA1 ;
			RECT 2.55 2.075 2.77 2.295 ;
			LAYER VIA1 ;
			RECT 3.725 2.105 3.945 2.325 ;
			LAYER VIA1 ;
			RECT 4.905 2.09 5.125 2.31 ;
			LAYER VIA1 ;
			RECT 6.09 2.075 6.31 2.295 ;
			LAYER VIA1 ;
			RECT 7.265 2.105 7.485 2.325 ;
			LAYER VIA1 ;
			RECT 8.445 2.09 8.665 2.31 ;
			LAYER VIA1 ;
			RECT 9.63 2.075 9.85 2.295 ;
			LAYER VIA1 ;
			RECT 10.805 2.105 11.025 2.325 ;
			LAYER VIA1 ;
			RECT 11.985 2.09 12.205 2.31 ;
			LAYER VIA1 ;
			RECT 13.17 2.075 13.39 2.295 ;
			LAYER VIA1 ;
			RECT 14.345 2.105 14.565 2.325 ;
			LAYER VIA1 ;
			RECT 15.525 2.09 15.745 2.31 ;
			LAYER VIA1 ;
			RECT 16.71 2.075 16.93 2.295 ;
			LAYER VIA1 ;
			RECT 17.885 2.105 18.105 2.325 ;
			LAYER VIA1 ;
			RECT 19.065 2.09 19.285 2.31 ;
			LAYER VIA1 ;
			RECT 20.25 2.075 20.47 2.295 ;
			LAYER VIA1 ;
			RECT 21.425 2.105 21.645 2.325 ;
			LAYER VIA1 ;
			RECT 22.605 2.09 22.825 2.31 ;
			LAYER VIA1 ;
			RECT 23.79 2.075 24.01 2.295 ;
			LAYER VIA1 ;
			RECT 24.965 2.105 25.185 2.325 ;
			LAYER VIA1 ;
			RECT 26.145 2.09 26.365 2.31 ;
			LAYER VIA1 ;
			RECT 27.33 2.075 27.55 2.295 ;
			LAYER VIA1 ;
			RECT 28.505 2.105 28.725 2.325 ;
			LAYER VIA1 ;
			RECT 29.685 2.09 29.905 2.31 ;
			LAYER VIA1 ;
			RECT 30.87 2.075 31.09 2.295 ;
			LAYER VIA1 ;
			RECT 32.045 2.105 32.265 2.325 ;
			LAYER VIA1 ;
			RECT 33.225 2.09 33.445 2.31 ;
			LAYER VIA1 ;
			RECT 1.365 1.65 1.585 1.87 ;
			LAYER VIA1 ;
			RECT 2.55 1.635 2.77 1.855 ;
			LAYER VIA1 ;
			RECT 3.725 1.665 3.945 1.885 ;
			LAYER VIA1 ;
			RECT 4.905 1.65 5.125 1.87 ;
			LAYER VIA1 ;
			RECT 6.09 1.635 6.31 1.855 ;
			LAYER VIA1 ;
			RECT 7.265 1.665 7.485 1.885 ;
			LAYER VIA1 ;
			RECT 8.445 1.65 8.665 1.87 ;
			LAYER VIA1 ;
			RECT 9.63 1.635 9.85 1.855 ;
			LAYER VIA1 ;
			RECT 10.805 1.665 11.025 1.885 ;
			LAYER VIA1 ;
			RECT 11.985 1.65 12.205 1.87 ;
			LAYER VIA1 ;
			RECT 13.17 1.635 13.39 1.855 ;
			LAYER VIA1 ;
			RECT 14.345 1.665 14.565 1.885 ;
			LAYER VIA1 ;
			RECT 15.525 1.65 15.745 1.87 ;
			LAYER VIA1 ;
			RECT 16.71 1.635 16.93 1.855 ;
			LAYER VIA1 ;
			RECT 17.885 1.665 18.105 1.885 ;
			LAYER VIA1 ;
			RECT 19.065 1.65 19.285 1.87 ;
			LAYER VIA1 ;
			RECT 20.25 1.635 20.47 1.855 ;
			LAYER VIA1 ;
			RECT 21.425 1.665 21.645 1.885 ;
			LAYER VIA1 ;
			RECT 22.605 1.65 22.825 1.87 ;
			LAYER VIA1 ;
			RECT 23.79 1.635 24.01 1.855 ;
			LAYER VIA1 ;
			RECT 24.965 1.665 25.185 1.885 ;
			LAYER VIA1 ;
			RECT 26.145 1.65 26.365 1.87 ;
			LAYER VIA1 ;
			RECT 27.33 1.635 27.55 1.855 ;
			LAYER VIA1 ;
			RECT 28.505 1.665 28.725 1.885 ;
			LAYER VIA1 ;
			RECT 29.685 1.65 29.905 1.87 ;
			LAYER VIA1 ;
			RECT 30.87 1.635 31.09 1.855 ;
			LAYER VIA1 ;
			RECT 32.045 1.665 32.265 1.885 ;
			LAYER VIA1 ;
			RECT 33.225 1.65 33.445 1.87 ;
			LAYER M2 ;
			RECT 0.12 0.66 34.69 2.58 ;
		END
	END out
	PIN GND
		DIRECTION inout ;
		USE GROUND ;
		PORT
			LAYER M1 ;
			RECT 0.155 0.42 0.435 1.575 ;
			LAYER M1 ;
			RECT 0.745 0.42 1.025 1.595 ;
			LAYER M1 ;
			RECT 1.925 0.42 2.205 1.595 ;
			LAYER M1 ;
			RECT 3.105 0.42 3.385 1.595 ;
			LAYER M1 ;
			RECT 4.285 0.42 4.565 1.595 ;
			LAYER M1 ;
			RECT 5.465 0.42 5.745 1.595 ;
			LAYER M1 ;
			RECT 6.645 0.42 6.925 1.595 ;
			LAYER M1 ;
			RECT 7.825 0.42 8.105 1.595 ;
			LAYER M1 ;
			RECT 9.005 0.42 9.285 1.595 ;
			LAYER M1 ;
			RECT 10.185 0.42 10.465 1.595 ;
			LAYER M1 ;
			RECT 11.365 0.42 11.645 1.595 ;
			LAYER M1 ;
			RECT 12.545 0.42 12.825 1.595 ;
			LAYER M1 ;
			RECT 13.725 0.42 14.005 1.595 ;
			LAYER M1 ;
			RECT 14.905 0.42 15.185 1.595 ;
			LAYER M1 ;
			RECT 16.085 0.42 16.365 1.595 ;
			LAYER M1 ;
			RECT 17.265 0.42 17.545 1.595 ;
			LAYER M1 ;
			RECT 18.445 0.42 18.725 1.595 ;
			LAYER M1 ;
			RECT 19.625 0.42 19.905 1.595 ;
			LAYER M1 ;
			RECT 20.805 0.42 21.085 1.595 ;
			LAYER M1 ;
			RECT 21.985 0.42 22.265 1.595 ;
			LAYER M1 ;
			RECT 23.165 0.42 23.445 1.595 ;
			LAYER M1 ;
			RECT 24.345 0.42 24.625 1.595 ;
			LAYER M1 ;
			RECT 25.525 0.42 25.805 1.595 ;
			LAYER M1 ;
			RECT 26.705 0.42 26.985 1.595 ;
			LAYER M1 ;
			RECT 27.885 0.42 28.165 1.595 ;
			LAYER M1 ;
			RECT 29.065 0.42 29.345 1.595 ;
			LAYER M1 ;
			RECT 30.245 0.42 30.525 1.595 ;
			LAYER M1 ;
			RECT 31.425 0.42 31.705 1.595 ;
			LAYER M1 ;
			RECT 32.605 0.42 32.885 1.595 ;
			LAYER M1 ;
			RECT 33.785 0.42 34.065 1.595 ;
			LAYER M1 ;
			RECT 34.375 0.42 34.655 1.595 ;
			LAYER M1 ;
			RECT 0.155 0.35 35.34 0.42 ;
			LAYER M1 ;
			RECT 0 -0.42 35.34 0.35 ;
			LAYER VIA1 ;
			RECT 0.82 -0.11 1.04 0.11 ;
			LAYER VIA1 ;
			RECT 1.44 -0.11 1.66 0.11 ;
			LAYER VIA1 ;
			RECT 2.06 -0.11 2.28 0.11 ;
			LAYER VIA1 ;
			RECT 2.68 -0.11 2.9 0.11 ;
			LAYER VIA1 ;
			RECT 3.3 -0.11 3.52 0.11 ;
			LAYER VIA1 ;
			RECT 3.92 -0.11 4.14 0.11 ;
			LAYER VIA1 ;
			RECT 4.54 -0.11 4.76 0.11 ;
			LAYER VIA1 ;
			RECT 5.16 -0.11 5.38 0.11 ;
			LAYER VIA1 ;
			RECT 7.02 -0.11 7.24 0.11 ;
			LAYER VIA1 ;
			RECT 7.64 -0.11 7.86 0.11 ;
			LAYER VIA1 ;
			RECT 8.26 -0.11 8.48 0.11 ;
			LAYER VIA1 ;
			RECT 8.88 -0.11 9.1 0.11 ;
			LAYER VIA1 ;
			RECT 9.5 -0.11 9.72 0.11 ;
			LAYER VIA1 ;
			RECT 10.12 -0.11 10.34 0.11 ;
			LAYER VIA1 ;
			RECT 10.74 -0.11 10.96 0.11 ;
			LAYER VIA1 ;
			RECT 11.36 -0.11 11.58 0.11 ;
			LAYER VIA1 ;
			RECT 13.22 -0.11 13.44 0.11 ;
			LAYER VIA1 ;
			RECT 13.84 -0.11 14.06 0.11 ;
			LAYER VIA1 ;
			RECT 14.46 -0.11 14.68 0.11 ;
			LAYER VIA1 ;
			RECT 15.08 -0.11 15.3 0.11 ;
			LAYER VIA1 ;
			RECT 15.7 -0.11 15.92 0.11 ;
			LAYER VIA1 ;
			RECT 16.32 -0.11 16.54 0.11 ;
			LAYER VIA1 ;
			RECT 16.94 -0.11 17.16 0.11 ;
			LAYER VIA1 ;
			RECT 17.56 -0.11 17.78 0.11 ;
			LAYER VIA1 ;
			RECT 19.42 -0.11 19.64 0.11 ;
			LAYER VIA1 ;
			RECT 20.04 -0.11 20.26 0.11 ;
			LAYER VIA1 ;
			RECT 20.66 -0.11 20.88 0.11 ;
			LAYER VIA1 ;
			RECT 21.28 -0.11 21.5 0.11 ;
			LAYER VIA1 ;
			RECT 21.9 -0.11 22.12 0.11 ;
			LAYER VIA1 ;
			RECT 22.52 -0.11 22.74 0.11 ;
			LAYER VIA1 ;
			RECT 23.14 -0.11 23.36 0.11 ;
			LAYER VIA1 ;
			RECT 23.76 -0.11 23.98 0.11 ;
			LAYER VIA1 ;
			RECT 25.62 -0.11 25.84 0.11 ;
			LAYER VIA1 ;
			RECT 26.24 -0.11 26.46 0.11 ;
			LAYER VIA1 ;
			RECT 26.86 -0.11 27.08 0.11 ;
			LAYER VIA1 ;
			RECT 27.48 -0.11 27.7 0.11 ;
			LAYER VIA1 ;
			RECT 28.1 -0.11 28.32 0.11 ;
			LAYER VIA1 ;
			RECT 28.72 -0.11 28.94 0.11 ;
			LAYER VIA1 ;
			RECT 29.34 -0.11 29.56 0.11 ;
			LAYER VIA1 ;
			RECT 29.96 -0.11 30.18 0.11 ;
			LAYER VIA1 ;
			RECT 31.82 -0.11 32.04 0.11 ;
			LAYER VIA1 ;
			RECT 32.44 -0.11 32.66 0.11 ;
			LAYER VIA1 ;
			RECT 33.06 -0.11 33.28 0.11 ;
			LAYER VIA1 ;
			RECT 33.68 -0.11 33.9 0.11 ;
			LAYER VIA1 ;
			RECT 34.3 -0.11 34.52 0.11 ;
			LAYER VIA1 ;
			RECT 34.92 -0.11 35.14 0.11 ;
			LAYER M2 ;
			RECT 0 -0.415 35.34 0.42 ;
		END
	END GND
	PIN VDD
		DIRECTION inout ;
		USE POWER ;
		PORT
			LAYER M1 ;
			RECT 0 5.78 35.34 6.62 ;
			LAYER M1 ;
			RECT 0.155 3.49 0.435 5.78 ;
			LAYER M1 ;
			RECT 0.745 3.495 1.025 5.78 ;
			LAYER M1 ;
			RECT 1.925 3.495 2.205 5.78 ;
			LAYER M1 ;
			RECT 3.105 3.495 3.385 5.78 ;
			LAYER M1 ;
			RECT 4.285 3.495 4.565 5.78 ;
			LAYER M1 ;
			RECT 5.465 3.495 5.745 5.78 ;
			LAYER M1 ;
			RECT 6.645 3.495 6.925 5.78 ;
			LAYER M1 ;
			RECT 7.825 3.495 8.105 5.78 ;
			LAYER M1 ;
			RECT 9.005 3.495 9.285 5.78 ;
			LAYER M1 ;
			RECT 10.185 3.495 10.465 5.78 ;
			LAYER M1 ;
			RECT 11.365 3.495 11.645 5.78 ;
			LAYER M1 ;
			RECT 12.545 3.495 12.825 5.78 ;
			LAYER M1 ;
			RECT 13.725 3.495 14.005 5.78 ;
			LAYER M1 ;
			RECT 14.905 3.495 15.185 5.78 ;
			LAYER M1 ;
			RECT 16.085 3.495 16.365 5.78 ;
			LAYER M1 ;
			RECT 17.265 3.495 17.545 5.78 ;
			LAYER M1 ;
			RECT 18.445 3.495 18.725 5.78 ;
			LAYER M1 ;
			RECT 19.625 3.495 19.905 5.78 ;
			LAYER M1 ;
			RECT 20.805 3.495 21.085 5.78 ;
			LAYER M1 ;
			RECT 21.985 3.495 22.265 5.78 ;
			LAYER M1 ;
			RECT 23.165 3.495 23.445 5.78 ;
			LAYER M1 ;
			RECT 24.345 3.495 24.625 5.78 ;
			LAYER M1 ;
			RECT 25.525 3.495 25.805 5.78 ;
			LAYER M1 ;
			RECT 26.705 3.495 26.985 5.78 ;
			LAYER M1 ;
			RECT 27.885 3.495 28.165 5.78 ;
			LAYER M1 ;
			RECT 29.065 3.495 29.345 5.78 ;
			LAYER M1 ;
			RECT 30.245 3.495 30.525 5.78 ;
			LAYER M1 ;
			RECT 31.425 3.495 31.705 5.78 ;
			LAYER M1 ;
			RECT 32.605 3.495 32.885 5.78 ;
			LAYER M1 ;
			RECT 33.785 3.495 34.065 5.78 ;
			LAYER M1 ;
			RECT 34.375 3.495 34.655 5.78 ;
			LAYER VIA1 ;
			RECT 0.82 6.09 1.04 6.31 ;
			LAYER VIA1 ;
			RECT 1.44 6.09 1.66 6.31 ;
			LAYER VIA1 ;
			RECT 2.06 6.09 2.28 6.31 ;
			LAYER VIA1 ;
			RECT 2.68 6.09 2.9 6.31 ;
			LAYER VIA1 ;
			RECT 3.3 6.09 3.52 6.31 ;
			LAYER VIA1 ;
			RECT 3.92 6.09 4.14 6.31 ;
			LAYER VIA1 ;
			RECT 4.54 6.09 4.76 6.31 ;
			LAYER VIA1 ;
			RECT 5.16 6.09 5.38 6.31 ;
			LAYER VIA1 ;
			RECT 7.02 6.09 7.24 6.31 ;
			LAYER VIA1 ;
			RECT 7.64 6.09 7.86 6.31 ;
			LAYER VIA1 ;
			RECT 8.26 6.09 8.48 6.31 ;
			LAYER VIA1 ;
			RECT 8.88 6.09 9.1 6.31 ;
			LAYER VIA1 ;
			RECT 9.5 6.09 9.72 6.31 ;
			LAYER VIA1 ;
			RECT 10.12 6.09 10.34 6.31 ;
			LAYER VIA1 ;
			RECT 10.74 6.09 10.96 6.31 ;
			LAYER VIA1 ;
			RECT 11.36 6.09 11.58 6.31 ;
			LAYER VIA1 ;
			RECT 13.22 6.09 13.44 6.31 ;
			LAYER VIA1 ;
			RECT 13.84 6.09 14.06 6.31 ;
			LAYER VIA1 ;
			RECT 14.46 6.09 14.68 6.31 ;
			LAYER VIA1 ;
			RECT 15.08 6.09 15.3 6.31 ;
			LAYER VIA1 ;
			RECT 15.7 6.09 15.92 6.31 ;
			LAYER VIA1 ;
			RECT 16.32 6.09 16.54 6.31 ;
			LAYER VIA1 ;
			RECT 16.94 6.09 17.16 6.31 ;
			LAYER VIA1 ;
			RECT 17.56 6.09 17.78 6.31 ;
			LAYER VIA1 ;
			RECT 19.42 6.09 19.64 6.31 ;
			LAYER VIA1 ;
			RECT 20.04 6.09 20.26 6.31 ;
			LAYER VIA1 ;
			RECT 20.66 6.09 20.88 6.31 ;
			LAYER VIA1 ;
			RECT 21.28 6.09 21.5 6.31 ;
			LAYER VIA1 ;
			RECT 21.9 6.09 22.12 6.31 ;
			LAYER VIA1 ;
			RECT 22.52 6.09 22.74 6.31 ;
			LAYER VIA1 ;
			RECT 23.14 6.09 23.36 6.31 ;
			LAYER VIA1 ;
			RECT 23.76 6.09 23.98 6.31 ;
			LAYER VIA1 ;
			RECT 25.62 6.09 25.84 6.31 ;
			LAYER VIA1 ;
			RECT 26.24 6.09 26.46 6.31 ;
			LAYER VIA1 ;
			RECT 26.86 6.09 27.08 6.31 ;
			LAYER VIA1 ;
			RECT 27.48 6.09 27.7 6.31 ;
			LAYER VIA1 ;
			RECT 28.1 6.09 28.32 6.31 ;
			LAYER VIA1 ;
			RECT 28.72 6.09 28.94 6.31 ;
			LAYER VIA1 ;
			RECT 29.34 6.09 29.56 6.31 ;
			LAYER VIA1 ;
			RECT 29.96 6.09 30.18 6.31 ;
			LAYER VIA1 ;
			RECT 31.82 6.09 32.04 6.31 ;
			LAYER VIA1 ;
			RECT 32.44 6.09 32.66 6.31 ;
			LAYER VIA1 ;
			RECT 33.06 6.09 33.28 6.31 ;
			LAYER VIA1 ;
			RECT 33.68 6.09 33.9 6.31 ;
			LAYER VIA1 ;
			RECT 34.3 6.09 34.52 6.31 ;
			LAYER VIA1 ;
			RECT 34.92 6.09 35.14 6.31 ;
			LAYER M2 ;
			RECT 0 5.78 35.34 6.615 ;
		END
	END VDD
	PIN in
		DIRECTION input ;
		USE SIGNAL ;
		PORT
			LAYER M1 ;
			RECT 1.94 2.695 2.18 3.295 ;
			LAYER M1 ;
			RECT 3.13 2.695 3.37 3.295 ;
			LAYER M1 ;
			RECT 5.48 2.695 5.72 3.295 ;
			LAYER M1 ;
			RECT 6.67 2.695 6.91 3.295 ;
			LAYER M1 ;
			RECT 9.02 2.695 9.26 3.295 ;
			LAYER M1 ;
			RECT 10.21 2.695 10.45 3.295 ;
			LAYER M1 ;
			RECT 12.56 2.695 12.8 3.295 ;
			LAYER M1 ;
			RECT 13.75 2.695 13.99 3.295 ;
			LAYER M1 ;
			RECT 16.1 2.695 16.34 3.295 ;
			LAYER M1 ;
			RECT 17.29 2.695 17.53 3.295 ;
			LAYER M1 ;
			RECT 19.64 2.695 19.88 3.295 ;
			LAYER M1 ;
			RECT 20.83 2.695 21.07 3.295 ;
			LAYER M1 ;
			RECT 23.18 2.695 23.42 3.295 ;
			LAYER M1 ;
			RECT 24.37 2.695 24.61 3.295 ;
			LAYER M1 ;
			RECT 26.72 2.695 26.96 3.295 ;
			LAYER M1 ;
			RECT 27.91 2.695 28.15 3.295 ;
			LAYER M1 ;
			RECT 30.26 2.695 30.5 3.295 ;
			LAYER M1 ;
			RECT 31.45 2.695 31.69 3.295 ;
			LAYER M1 ;
			RECT 33.8 2.695 34.04 3.295 ;
			LAYER VIA1 ;
			RECT 1.95 3.025 2.17 3.245 ;
			LAYER VIA1 ;
			RECT 3.14 3.025 3.36 3.245 ;
			LAYER VIA1 ;
			RECT 5.49 3.025 5.71 3.245 ;
			LAYER VIA1 ;
			RECT 6.68 3.025 6.9 3.245 ;
			LAYER VIA1 ;
			RECT 9.03 3.025 9.25 3.245 ;
			LAYER VIA1 ;
			RECT 10.22 3.025 10.44 3.245 ;
			LAYER VIA1 ;
			RECT 12.57 3.025 12.79 3.245 ;
			LAYER VIA1 ;
			RECT 13.76 3.025 13.98 3.245 ;
			LAYER VIA1 ;
			RECT 16.11 3.025 16.33 3.245 ;
			LAYER VIA1 ;
			RECT 17.3 3.025 17.52 3.245 ;
			LAYER VIA1 ;
			RECT 19.65 3.025 19.87 3.245 ;
			LAYER VIA1 ;
			RECT 20.84 3.025 21.06 3.245 ;
			LAYER VIA1 ;
			RECT 23.19 3.025 23.41 3.245 ;
			LAYER VIA1 ;
			RECT 24.38 3.025 24.6 3.245 ;
			LAYER VIA1 ;
			RECT 26.73 3.025 26.95 3.245 ;
			LAYER VIA1 ;
			RECT 27.92 3.025 28.14 3.245 ;
			LAYER VIA1 ;
			RECT 30.27 3.025 30.49 3.245 ;
			LAYER VIA1 ;
			RECT 31.46 3.025 31.68 3.245 ;
			LAYER VIA1 ;
			RECT 33.81 3.025 34.03 3.245 ;
			LAYER M2 ;
			RECT 0.12 3.29 34.69 3.53 ;
			LAYER M2 ;
			RECT 1.94 2.975 2.18 3.29 ;
			LAYER M2 ;
			RECT 3.13 2.975 3.37 3.29 ;
			LAYER M2 ;
			RECT 5.48 2.975 5.72 3.29 ;
			LAYER M2 ;
			RECT 6.67 2.975 6.91 3.29 ;
			LAYER M2 ;
			RECT 9.02 2.975 9.26 3.29 ;
			LAYER M2 ;
			RECT 10.21 2.975 10.45 3.29 ;
			LAYER M2 ;
			RECT 12.56 2.975 12.8 3.29 ;
			LAYER M2 ;
			RECT 13.75 2.975 13.99 3.29 ;
			LAYER M2 ;
			RECT 16.1 2.975 16.34 3.29 ;
			LAYER M2 ;
			RECT 17.29 2.975 17.53 3.29 ;
			LAYER M2 ;
			RECT 19.64 2.975 19.88 3.29 ;
			LAYER M2 ;
			RECT 20.83 2.975 21.07 3.29 ;
			LAYER M2 ;
			RECT 23.18 2.975 23.42 3.29 ;
			LAYER M2 ;
			RECT 24.37 2.975 24.61 3.29 ;
			LAYER M2 ;
			RECT 26.72 2.975 26.96 3.29 ;
			LAYER M2 ;
			RECT 27.91 2.975 28.15 3.29 ;
			LAYER M2 ;
			RECT 30.26 2.975 30.5 3.29 ;
			LAYER M2 ;
			RECT 31.45 2.975 31.69 3.29 ;
			LAYER M2 ;
			RECT 33.8 2.975 34.04 3.29 ;
		END
		ANTENNASIZE 26.97 ;
	END in
	OBS
	END
END MMI_INVH152
MACRO MMI_INVH160
	CLASS CORE ;
	FOREIGN MMI_INVH160 0 0 ;
	SIZE 37.2 BY 6.2 ;
	SYMMETRY X Y ;
	SITE CORE1 ;
	PIN out
		DIRECTION output ;
		USE SIGNAL ;
		PORT
			LAYER M1 ;
			RECT 1.335 2.32 1.615 5.58 ;
			LAYER M1 ;
			RECT 1.315 2.125 1.635 2.32 ;
			LAYER M1 ;
			RECT 2.515 2.305 2.795 5.58 ;
			LAYER M1 ;
			RECT 3.695 2.335 3.975 5.58 ;
			LAYER M1 ;
			RECT 2.5 2.13 2.82 2.305 ;
			LAYER M1 ;
			RECT 3.675 2.13 3.995 2.335 ;
			LAYER M1 ;
			RECT 4.875 2.32 5.155 5.58 ;
			LAYER M1 ;
			RECT 2.5 2.125 3.995 2.13 ;
			LAYER M1 ;
			RECT 4.855 2.125 5.175 2.32 ;
			LAYER M1 ;
			RECT 6.055 2.305 6.335 5.58 ;
			LAYER M1 ;
			RECT 7.235 2.335 7.515 5.58 ;
			LAYER M1 ;
			RECT 6.04 2.13 6.36 2.305 ;
			LAYER M1 ;
			RECT 7.215 2.13 7.535 2.335 ;
			LAYER M1 ;
			RECT 8.415 2.32 8.695 5.58 ;
			LAYER M1 ;
			RECT 6.04 2.125 7.535 2.13 ;
			LAYER M1 ;
			RECT 8.395 2.125 8.715 2.32 ;
			LAYER M1 ;
			RECT 9.595 2.305 9.875 5.58 ;
			LAYER M1 ;
			RECT 10.775 2.335 11.055 5.58 ;
			LAYER M1 ;
			RECT 9.58 2.13 9.9 2.305 ;
			LAYER M1 ;
			RECT 10.755 2.13 11.075 2.335 ;
			LAYER M1 ;
			RECT 11.955 2.32 12.235 5.58 ;
			LAYER M1 ;
			RECT 9.58 2.125 11.075 2.13 ;
			LAYER M1 ;
			RECT 11.935 2.125 12.255 2.32 ;
			LAYER M1 ;
			RECT 13.135 2.305 13.415 5.58 ;
			LAYER M1 ;
			RECT 14.315 2.335 14.595 5.58 ;
			LAYER M1 ;
			RECT 13.12 2.13 13.44 2.305 ;
			LAYER M1 ;
			RECT 14.295 2.13 14.615 2.335 ;
			LAYER M1 ;
			RECT 15.495 2.32 15.775 5.58 ;
			LAYER M1 ;
			RECT 13.12 2.125 14.615 2.13 ;
			LAYER M1 ;
			RECT 15.475 2.125 15.795 2.32 ;
			LAYER M1 ;
			RECT 16.675 2.305 16.955 5.58 ;
			LAYER M1 ;
			RECT 17.855 2.335 18.135 5.58 ;
			LAYER M1 ;
			RECT 16.66 2.13 16.98 2.305 ;
			LAYER M1 ;
			RECT 17.835 2.13 18.155 2.335 ;
			LAYER M1 ;
			RECT 19.035 2.32 19.315 5.58 ;
			LAYER M1 ;
			RECT 16.66 2.125 18.155 2.13 ;
			LAYER M1 ;
			RECT 19.015 2.125 19.335 2.32 ;
			LAYER M1 ;
			RECT 20.215 2.305 20.495 5.58 ;
			LAYER M1 ;
			RECT 21.395 2.335 21.675 5.58 ;
			LAYER M1 ;
			RECT 20.2 2.13 20.52 2.305 ;
			LAYER M1 ;
			RECT 21.375 2.13 21.695 2.335 ;
			LAYER M1 ;
			RECT 22.575 2.32 22.855 5.58 ;
			LAYER M1 ;
			RECT 20.2 2.125 21.695 2.13 ;
			LAYER M1 ;
			RECT 22.555 2.125 22.875 2.32 ;
			LAYER M1 ;
			RECT 23.755 2.305 24.035 5.58 ;
			LAYER M1 ;
			RECT 24.935 2.335 25.215 5.58 ;
			LAYER M1 ;
			RECT 23.74 2.13 24.06 2.305 ;
			LAYER M1 ;
			RECT 24.915 2.13 25.235 2.335 ;
			LAYER M1 ;
			RECT 26.115 2.32 26.395 5.58 ;
			LAYER M1 ;
			RECT 23.74 2.125 25.235 2.13 ;
			LAYER M1 ;
			RECT 26.095 2.125 26.415 2.32 ;
			LAYER M1 ;
			RECT 27.295 2.305 27.575 5.58 ;
			LAYER M1 ;
			RECT 28.475 2.335 28.755 5.58 ;
			LAYER M1 ;
			RECT 27.28 2.13 27.6 2.305 ;
			LAYER M1 ;
			RECT 28.455 2.13 28.775 2.335 ;
			LAYER M1 ;
			RECT 29.655 2.32 29.935 5.58 ;
			LAYER M1 ;
			RECT 27.28 2.125 28.775 2.13 ;
			LAYER M1 ;
			RECT 29.635 2.125 29.955 2.32 ;
			LAYER M1 ;
			RECT 30.835 2.305 31.115 5.58 ;
			LAYER M1 ;
			RECT 32.015 2.335 32.295 5.58 ;
			LAYER M1 ;
			RECT 33.195 2.335 33.475 5.58 ;
			LAYER M1 ;
			RECT 30.82 2.13 31.14 2.305 ;
			LAYER M1 ;
			RECT 31.995 2.13 32.315 2.335 ;
			LAYER M1 ;
			RECT 30.82 2.125 32.315 2.13 ;
			LAYER M1 ;
			RECT 33.175 2.13 33.495 2.335 ;
			LAYER M1 ;
			RECT 34.375 2.305 34.655 5.58 ;
			LAYER M1 ;
			RECT 35.555 2.32 35.835 5.58 ;
			LAYER M1 ;
			RECT 34.35 2.13 34.67 2.305 ;
			LAYER M1 ;
			RECT 33.175 2.125 34.67 2.13 ;
			LAYER M1 ;
			RECT 35.535 2.125 35.855 2.32 ;
			LAYER M1 ;
			RECT 1.315 1.885 35.855 2.125 ;
			LAYER M1 ;
			RECT 1.315 1.64 1.635 1.885 ;
			LAYER M1 ;
			RECT 1.335 0.62 1.615 1.64 ;
			LAYER M1 ;
			RECT 2.5 1.625 2.82 1.885 ;
			LAYER M1 ;
			RECT 3.675 1.655 3.995 1.885 ;
			LAYER M1 ;
			RECT 2.515 0.62 2.795 1.625 ;
			LAYER M1 ;
			RECT 3.695 0.62 3.975 1.655 ;
			LAYER M1 ;
			RECT 4.855 1.64 5.175 1.885 ;
			LAYER M1 ;
			RECT 4.875 0.62 5.155 1.64 ;
			LAYER M1 ;
			RECT 6.04 1.625 6.36 1.885 ;
			LAYER M1 ;
			RECT 7.215 1.655 7.535 1.885 ;
			LAYER M1 ;
			RECT 6.055 0.62 6.335 1.625 ;
			LAYER M1 ;
			RECT 7.235 0.62 7.515 1.655 ;
			LAYER M1 ;
			RECT 8.395 1.64 8.715 1.885 ;
			LAYER M1 ;
			RECT 8.415 0.62 8.695 1.64 ;
			LAYER M1 ;
			RECT 9.58 1.625 9.9 1.885 ;
			LAYER M1 ;
			RECT 10.755 1.655 11.075 1.885 ;
			LAYER M1 ;
			RECT 9.595 0.62 9.875 1.625 ;
			LAYER M1 ;
			RECT 10.775 0.62 11.055 1.655 ;
			LAYER M1 ;
			RECT 11.935 1.64 12.255 1.885 ;
			LAYER M1 ;
			RECT 11.955 0.62 12.235 1.64 ;
			LAYER M1 ;
			RECT 13.12 1.625 13.44 1.885 ;
			LAYER M1 ;
			RECT 14.295 1.655 14.615 1.885 ;
			LAYER M1 ;
			RECT 13.135 0.62 13.415 1.625 ;
			LAYER M1 ;
			RECT 14.315 0.62 14.595 1.655 ;
			LAYER M1 ;
			RECT 15.475 1.64 15.795 1.885 ;
			LAYER M1 ;
			RECT 15.495 0.62 15.775 1.64 ;
			LAYER M1 ;
			RECT 16.66 1.625 16.98 1.885 ;
			LAYER M1 ;
			RECT 17.835 1.655 18.155 1.885 ;
			LAYER M1 ;
			RECT 16.675 0.62 16.955 1.625 ;
			LAYER M1 ;
			RECT 17.855 0.62 18.135 1.655 ;
			LAYER M1 ;
			RECT 19.015 1.64 19.335 1.885 ;
			LAYER M1 ;
			RECT 19.035 0.62 19.315 1.64 ;
			LAYER M1 ;
			RECT 20.2 1.625 20.52 1.885 ;
			LAYER M1 ;
			RECT 21.375 1.655 21.695 1.885 ;
			LAYER M1 ;
			RECT 20.215 0.62 20.495 1.625 ;
			LAYER M1 ;
			RECT 21.395 0.62 21.675 1.655 ;
			LAYER M1 ;
			RECT 22.555 1.64 22.875 1.885 ;
			LAYER M1 ;
			RECT 22.575 0.62 22.855 1.64 ;
			LAYER M1 ;
			RECT 23.74 1.625 24.06 1.885 ;
			LAYER M1 ;
			RECT 24.915 1.655 25.235 1.885 ;
			LAYER M1 ;
			RECT 23.755 0.62 24.035 1.625 ;
			LAYER M1 ;
			RECT 24.935 0.62 25.215 1.655 ;
			LAYER M1 ;
			RECT 26.095 1.64 26.415 1.885 ;
			LAYER M1 ;
			RECT 26.115 0.62 26.395 1.64 ;
			LAYER M1 ;
			RECT 27.28 1.625 27.6 1.885 ;
			LAYER M1 ;
			RECT 28.455 1.655 28.775 1.885 ;
			LAYER M1 ;
			RECT 27.295 0.62 27.575 1.625 ;
			LAYER M1 ;
			RECT 28.475 0.62 28.755 1.655 ;
			LAYER M1 ;
			RECT 29.635 1.64 29.955 1.885 ;
			LAYER M1 ;
			RECT 29.655 0.62 29.935 1.64 ;
			LAYER M1 ;
			RECT 30.82 1.625 31.14 1.885 ;
			LAYER M1 ;
			RECT 31.995 1.655 32.315 1.885 ;
			LAYER M1 ;
			RECT 33.175 1.655 33.495 1.885 ;
			LAYER M1 ;
			RECT 30.835 0.62 31.115 1.625 ;
			LAYER M1 ;
			RECT 32.015 0.62 32.295 1.655 ;
			LAYER M1 ;
			RECT 33.195 0.62 33.475 1.655 ;
			LAYER M1 ;
			RECT 34.35 1.625 34.67 1.885 ;
			LAYER M1 ;
			RECT 35.535 1.64 35.855 1.885 ;
			LAYER M1 ;
			RECT 34.375 0.62 34.655 1.625 ;
			LAYER M1 ;
			RECT 35.555 0.62 35.835 1.64 ;
			LAYER VIA1 ;
			RECT 1.365 2.09 1.585 2.31 ;
			LAYER VIA1 ;
			RECT 2.55 2.075 2.77 2.295 ;
			LAYER VIA1 ;
			RECT 3.725 2.105 3.945 2.325 ;
			LAYER VIA1 ;
			RECT 4.905 2.09 5.125 2.31 ;
			LAYER VIA1 ;
			RECT 6.09 2.075 6.31 2.295 ;
			LAYER VIA1 ;
			RECT 7.265 2.105 7.485 2.325 ;
			LAYER VIA1 ;
			RECT 8.445 2.09 8.665 2.31 ;
			LAYER VIA1 ;
			RECT 9.63 2.075 9.85 2.295 ;
			LAYER VIA1 ;
			RECT 10.805 2.105 11.025 2.325 ;
			LAYER VIA1 ;
			RECT 11.985 2.09 12.205 2.31 ;
			LAYER VIA1 ;
			RECT 13.17 2.075 13.39 2.295 ;
			LAYER VIA1 ;
			RECT 14.345 2.105 14.565 2.325 ;
			LAYER VIA1 ;
			RECT 15.525 2.09 15.745 2.31 ;
			LAYER VIA1 ;
			RECT 16.71 2.075 16.93 2.295 ;
			LAYER VIA1 ;
			RECT 17.885 2.105 18.105 2.325 ;
			LAYER VIA1 ;
			RECT 19.065 2.09 19.285 2.31 ;
			LAYER VIA1 ;
			RECT 20.25 2.075 20.47 2.295 ;
			LAYER VIA1 ;
			RECT 21.425 2.105 21.645 2.325 ;
			LAYER VIA1 ;
			RECT 22.605 2.09 22.825 2.31 ;
			LAYER VIA1 ;
			RECT 23.79 2.075 24.01 2.295 ;
			LAYER VIA1 ;
			RECT 24.965 2.105 25.185 2.325 ;
			LAYER VIA1 ;
			RECT 26.145 2.09 26.365 2.31 ;
			LAYER VIA1 ;
			RECT 27.33 2.075 27.55 2.295 ;
			LAYER VIA1 ;
			RECT 28.505 2.105 28.725 2.325 ;
			LAYER VIA1 ;
			RECT 29.685 2.09 29.905 2.31 ;
			LAYER VIA1 ;
			RECT 30.87 2.075 31.09 2.295 ;
			LAYER VIA1 ;
			RECT 32.045 2.105 32.265 2.325 ;
			LAYER VIA1 ;
			RECT 33.225 2.105 33.445 2.325 ;
			LAYER VIA1 ;
			RECT 34.4 2.075 34.62 2.295 ;
			LAYER VIA1 ;
			RECT 35.585 2.09 35.805 2.31 ;
			LAYER VIA1 ;
			RECT 1.365 1.65 1.585 1.87 ;
			LAYER VIA1 ;
			RECT 2.55 1.635 2.77 1.855 ;
			LAYER VIA1 ;
			RECT 3.725 1.665 3.945 1.885 ;
			LAYER VIA1 ;
			RECT 4.905 1.65 5.125 1.87 ;
			LAYER VIA1 ;
			RECT 6.09 1.635 6.31 1.855 ;
			LAYER VIA1 ;
			RECT 7.265 1.665 7.485 1.885 ;
			LAYER VIA1 ;
			RECT 8.445 1.65 8.665 1.87 ;
			LAYER VIA1 ;
			RECT 9.63 1.635 9.85 1.855 ;
			LAYER VIA1 ;
			RECT 10.805 1.665 11.025 1.885 ;
			LAYER VIA1 ;
			RECT 11.985 1.65 12.205 1.87 ;
			LAYER VIA1 ;
			RECT 13.17 1.635 13.39 1.855 ;
			LAYER VIA1 ;
			RECT 14.345 1.665 14.565 1.885 ;
			LAYER VIA1 ;
			RECT 15.525 1.65 15.745 1.87 ;
			LAYER VIA1 ;
			RECT 16.71 1.635 16.93 1.855 ;
			LAYER VIA1 ;
			RECT 17.885 1.665 18.105 1.885 ;
			LAYER VIA1 ;
			RECT 19.065 1.65 19.285 1.87 ;
			LAYER VIA1 ;
			RECT 20.25 1.635 20.47 1.855 ;
			LAYER VIA1 ;
			RECT 21.425 1.665 21.645 1.885 ;
			LAYER VIA1 ;
			RECT 22.605 1.65 22.825 1.87 ;
			LAYER VIA1 ;
			RECT 23.79 1.635 24.01 1.855 ;
			LAYER VIA1 ;
			RECT 24.965 1.665 25.185 1.885 ;
			LAYER VIA1 ;
			RECT 26.145 1.65 26.365 1.87 ;
			LAYER VIA1 ;
			RECT 27.33 1.635 27.55 1.855 ;
			LAYER VIA1 ;
			RECT 28.505 1.665 28.725 1.885 ;
			LAYER VIA1 ;
			RECT 29.685 1.65 29.905 1.87 ;
			LAYER VIA1 ;
			RECT 30.87 1.635 31.09 1.855 ;
			LAYER VIA1 ;
			RECT 32.045 1.665 32.265 1.885 ;
			LAYER VIA1 ;
			RECT 33.225 1.665 33.445 1.885 ;
			LAYER VIA1 ;
			RECT 34.4 1.635 34.62 1.855 ;
			LAYER VIA1 ;
			RECT 35.585 1.65 35.805 1.87 ;
			LAYER M2 ;
			RECT 0.115 0.665 37.045 2.585 ;
		END
	END out
	PIN GND
		DIRECTION inout ;
		USE GROUND ;
		PORT
			LAYER M1 ;
			RECT 0.155 0.42 0.435 1.575 ;
			LAYER M1 ;
			RECT 0.745 0.42 1.025 1.575 ;
			LAYER M1 ;
			RECT 1.925 0.42 2.205 1.575 ;
			LAYER M1 ;
			RECT 3.105 0.42 3.385 1.575 ;
			LAYER M1 ;
			RECT 4.285 0.42 4.565 1.575 ;
			LAYER M1 ;
			RECT 5.465 0.42 5.745 1.575 ;
			LAYER M1 ;
			RECT 6.645 0.42 6.925 1.575 ;
			LAYER M1 ;
			RECT 7.825 0.42 8.105 1.575 ;
			LAYER M1 ;
			RECT 9.005 0.42 9.285 1.575 ;
			LAYER M1 ;
			RECT 10.185 0.42 10.465 1.575 ;
			LAYER M1 ;
			RECT 11.365 0.42 11.645 1.575 ;
			LAYER M1 ;
			RECT 12.545 0.42 12.825 1.575 ;
			LAYER M1 ;
			RECT 13.725 0.42 14.005 1.575 ;
			LAYER M1 ;
			RECT 14.905 0.42 15.185 1.575 ;
			LAYER M1 ;
			RECT 16.085 0.42 16.365 1.575 ;
			LAYER M1 ;
			RECT 17.265 0.42 17.545 1.575 ;
			LAYER M1 ;
			RECT 18.445 0.42 18.725 1.575 ;
			LAYER M1 ;
			RECT 19.625 0.42 19.905 1.575 ;
			LAYER M1 ;
			RECT 20.805 0.42 21.085 1.575 ;
			LAYER M1 ;
			RECT 21.985 0.42 22.265 1.575 ;
			LAYER M1 ;
			RECT 23.165 0.42 23.445 1.575 ;
			LAYER M1 ;
			RECT 24.345 0.42 24.625 1.575 ;
			LAYER M1 ;
			RECT 25.525 0.42 25.805 1.575 ;
			LAYER M1 ;
			RECT 26.705 0.42 26.985 1.575 ;
			LAYER M1 ;
			RECT 27.885 0.42 28.165 1.575 ;
			LAYER M1 ;
			RECT 29.065 0.42 29.345 1.575 ;
			LAYER M1 ;
			RECT 30.245 0.42 30.525 1.575 ;
			LAYER M1 ;
			RECT 31.425 0.42 31.705 1.575 ;
			LAYER M1 ;
			RECT 32.605 0.42 32.885 1.575 ;
			LAYER M1 ;
			RECT 33.785 0.42 34.065 1.575 ;
			LAYER M1 ;
			RECT 34.965 0.42 35.245 1.575 ;
			LAYER M1 ;
			RECT 36.145 0.42 36.425 1.575 ;
			LAYER M1 ;
			RECT 36.735 0.42 37.015 1.575 ;
			LAYER M1 ;
			RECT 0 -0.42 37.2 0.42 ;
			LAYER VIA1 ;
			RECT 0.82 -0.11 1.04 0.11 ;
			LAYER VIA1 ;
			RECT 1.44 -0.11 1.66 0.11 ;
			LAYER VIA1 ;
			RECT 2.06 -0.11 2.28 0.11 ;
			LAYER VIA1 ;
			RECT 2.68 -0.11 2.9 0.11 ;
			LAYER VIA1 ;
			RECT 3.3 -0.11 3.52 0.11 ;
			LAYER VIA1 ;
			RECT 3.92 -0.11 4.14 0.11 ;
			LAYER VIA1 ;
			RECT 4.54 -0.11 4.76 0.11 ;
			LAYER VIA1 ;
			RECT 5.16 -0.11 5.38 0.11 ;
			LAYER VIA1 ;
			RECT 7.02 -0.11 7.24 0.11 ;
			LAYER VIA1 ;
			RECT 7.64 -0.11 7.86 0.11 ;
			LAYER VIA1 ;
			RECT 8.26 -0.11 8.48 0.11 ;
			LAYER VIA1 ;
			RECT 8.88 -0.11 9.1 0.11 ;
			LAYER VIA1 ;
			RECT 9.5 -0.11 9.72 0.11 ;
			LAYER VIA1 ;
			RECT 10.12 -0.11 10.34 0.11 ;
			LAYER VIA1 ;
			RECT 10.74 -0.11 10.96 0.11 ;
			LAYER VIA1 ;
			RECT 11.36 -0.11 11.58 0.11 ;
			LAYER VIA1 ;
			RECT 13.22 -0.11 13.44 0.11 ;
			LAYER VIA1 ;
			RECT 13.84 -0.11 14.06 0.11 ;
			LAYER VIA1 ;
			RECT 14.46 -0.11 14.68 0.11 ;
			LAYER VIA1 ;
			RECT 15.08 -0.11 15.3 0.11 ;
			LAYER VIA1 ;
			RECT 15.7 -0.11 15.92 0.11 ;
			LAYER VIA1 ;
			RECT 16.32 -0.11 16.54 0.11 ;
			LAYER VIA1 ;
			RECT 16.94 -0.11 17.16 0.11 ;
			LAYER VIA1 ;
			RECT 17.56 -0.11 17.78 0.11 ;
			LAYER VIA1 ;
			RECT 19.42 -0.11 19.64 0.11 ;
			LAYER VIA1 ;
			RECT 20.04 -0.11 20.26 0.11 ;
			LAYER VIA1 ;
			RECT 20.66 -0.11 20.88 0.11 ;
			LAYER VIA1 ;
			RECT 21.28 -0.11 21.5 0.11 ;
			LAYER VIA1 ;
			RECT 21.9 -0.11 22.12 0.11 ;
			LAYER VIA1 ;
			RECT 22.52 -0.11 22.74 0.11 ;
			LAYER VIA1 ;
			RECT 23.14 -0.11 23.36 0.11 ;
			LAYER VIA1 ;
			RECT 23.76 -0.11 23.98 0.11 ;
			LAYER VIA1 ;
			RECT 25.62 -0.11 25.84 0.11 ;
			LAYER VIA1 ;
			RECT 26.24 -0.11 26.46 0.11 ;
			LAYER VIA1 ;
			RECT 26.86 -0.11 27.08 0.11 ;
			LAYER VIA1 ;
			RECT 27.48 -0.11 27.7 0.11 ;
			LAYER VIA1 ;
			RECT 28.1 -0.11 28.32 0.11 ;
			LAYER VIA1 ;
			RECT 28.72 -0.11 28.94 0.11 ;
			LAYER VIA1 ;
			RECT 29.34 -0.11 29.56 0.11 ;
			LAYER VIA1 ;
			RECT 29.96 -0.11 30.18 0.11 ;
			LAYER VIA1 ;
			RECT 31.82 -0.11 32.04 0.11 ;
			LAYER VIA1 ;
			RECT 32.44 -0.11 32.66 0.11 ;
			LAYER VIA1 ;
			RECT 33.06 -0.11 33.28 0.11 ;
			LAYER VIA1 ;
			RECT 33.68 -0.11 33.9 0.11 ;
			LAYER VIA1 ;
			RECT 34.3 -0.11 34.52 0.11 ;
			LAYER VIA1 ;
			RECT 34.92 -0.11 35.14 0.11 ;
			LAYER VIA1 ;
			RECT 35.54 -0.11 35.76 0.11 ;
			LAYER VIA1 ;
			RECT 36.16 -0.11 36.38 0.11 ;
			LAYER M2 ;
			RECT 0 -0.415 37.2 0.42 ;
		END
	END GND
	PIN VDD
		DIRECTION inout ;
		USE POWER ;
		PORT
			LAYER M1 ;
			RECT 0 5.78 37.2 6.62 ;
			LAYER M1 ;
			RECT 0.155 3.595 0.435 5.78 ;
			LAYER M1 ;
			RECT 0.745 3.595 1.025 5.78 ;
			LAYER M1 ;
			RECT 1.925 3.595 2.205 5.78 ;
			LAYER M1 ;
			RECT 3.105 3.595 3.385 5.78 ;
			LAYER M1 ;
			RECT 4.285 3.595 4.565 5.78 ;
			LAYER M1 ;
			RECT 5.465 3.595 5.745 5.78 ;
			LAYER M1 ;
			RECT 6.645 3.595 6.925 5.78 ;
			LAYER M1 ;
			RECT 7.825 3.595 8.105 5.78 ;
			LAYER M1 ;
			RECT 9.005 3.595 9.285 5.78 ;
			LAYER M1 ;
			RECT 10.185 3.595 10.465 5.78 ;
			LAYER M1 ;
			RECT 11.365 3.595 11.645 5.78 ;
			LAYER M1 ;
			RECT 12.545 3.595 12.825 5.78 ;
			LAYER M1 ;
			RECT 13.725 3.595 14.005 5.78 ;
			LAYER M1 ;
			RECT 14.905 3.595 15.185 5.78 ;
			LAYER M1 ;
			RECT 16.085 3.595 16.365 5.78 ;
			LAYER M1 ;
			RECT 17.265 3.595 17.545 5.78 ;
			LAYER M1 ;
			RECT 18.445 3.595 18.725 5.78 ;
			LAYER M1 ;
			RECT 19.625 3.595 19.905 5.78 ;
			LAYER M1 ;
			RECT 20.805 3.595 21.085 5.78 ;
			LAYER M1 ;
			RECT 21.985 3.595 22.265 5.78 ;
			LAYER M1 ;
			RECT 23.165 3.595 23.445 5.78 ;
			LAYER M1 ;
			RECT 24.345 3.595 24.625 5.78 ;
			LAYER M1 ;
			RECT 25.525 3.595 25.805 5.78 ;
			LAYER M1 ;
			RECT 26.705 3.595 26.985 5.78 ;
			LAYER M1 ;
			RECT 27.885 3.595 28.165 5.78 ;
			LAYER M1 ;
			RECT 29.065 3.595 29.345 5.78 ;
			LAYER M1 ;
			RECT 30.245 3.595 30.525 5.78 ;
			LAYER M1 ;
			RECT 31.425 3.595 31.705 5.78 ;
			LAYER M1 ;
			RECT 32.605 3.595 32.885 5.78 ;
			LAYER M1 ;
			RECT 33.785 3.595 34.065 5.78 ;
			LAYER M1 ;
			RECT 34.965 3.595 35.245 5.78 ;
			LAYER M1 ;
			RECT 36.145 3.595 36.425 5.78 ;
			LAYER M1 ;
			RECT 36.735 3.595 37.015 5.78 ;
			LAYER VIA1 ;
			RECT 0.82 6.09 1.04 6.31 ;
			LAYER VIA1 ;
			RECT 1.44 6.09 1.66 6.31 ;
			LAYER VIA1 ;
			RECT 2.06 6.09 2.28 6.31 ;
			LAYER VIA1 ;
			RECT 2.68 6.09 2.9 6.31 ;
			LAYER VIA1 ;
			RECT 3.3 6.09 3.52 6.31 ;
			LAYER VIA1 ;
			RECT 3.92 6.09 4.14 6.31 ;
			LAYER VIA1 ;
			RECT 4.54 6.09 4.76 6.31 ;
			LAYER VIA1 ;
			RECT 5.16 6.09 5.38 6.31 ;
			LAYER VIA1 ;
			RECT 7.02 6.09 7.24 6.31 ;
			LAYER VIA1 ;
			RECT 7.64 6.09 7.86 6.31 ;
			LAYER VIA1 ;
			RECT 8.26 6.09 8.48 6.31 ;
			LAYER VIA1 ;
			RECT 8.88 6.09 9.1 6.31 ;
			LAYER VIA1 ;
			RECT 9.5 6.09 9.72 6.31 ;
			LAYER VIA1 ;
			RECT 10.12 6.09 10.34 6.31 ;
			LAYER VIA1 ;
			RECT 10.74 6.09 10.96 6.31 ;
			LAYER VIA1 ;
			RECT 11.36 6.09 11.58 6.31 ;
			LAYER VIA1 ;
			RECT 13.22 6.09 13.44 6.31 ;
			LAYER VIA1 ;
			RECT 13.84 6.09 14.06 6.31 ;
			LAYER VIA1 ;
			RECT 14.46 6.09 14.68 6.31 ;
			LAYER VIA1 ;
			RECT 15.08 6.09 15.3 6.31 ;
			LAYER VIA1 ;
			RECT 15.7 6.09 15.92 6.31 ;
			LAYER VIA1 ;
			RECT 16.32 6.09 16.54 6.31 ;
			LAYER VIA1 ;
			RECT 16.94 6.09 17.16 6.31 ;
			LAYER VIA1 ;
			RECT 17.56 6.09 17.78 6.31 ;
			LAYER VIA1 ;
			RECT 19.42 6.09 19.64 6.31 ;
			LAYER VIA1 ;
			RECT 20.04 6.09 20.26 6.31 ;
			LAYER VIA1 ;
			RECT 20.66 6.09 20.88 6.31 ;
			LAYER VIA1 ;
			RECT 21.28 6.09 21.5 6.31 ;
			LAYER VIA1 ;
			RECT 21.9 6.09 22.12 6.31 ;
			LAYER VIA1 ;
			RECT 22.52 6.09 22.74 6.31 ;
			LAYER VIA1 ;
			RECT 23.14 6.09 23.36 6.31 ;
			LAYER VIA1 ;
			RECT 23.76 6.09 23.98 6.31 ;
			LAYER VIA1 ;
			RECT 25.62 6.09 25.84 6.31 ;
			LAYER VIA1 ;
			RECT 26.24 6.09 26.46 6.31 ;
			LAYER VIA1 ;
			RECT 26.86 6.09 27.08 6.31 ;
			LAYER VIA1 ;
			RECT 27.48 6.09 27.7 6.31 ;
			LAYER VIA1 ;
			RECT 28.1 6.09 28.32 6.31 ;
			LAYER VIA1 ;
			RECT 28.72 6.09 28.94 6.31 ;
			LAYER VIA1 ;
			RECT 29.34 6.09 29.56 6.31 ;
			LAYER VIA1 ;
			RECT 29.96 6.09 30.18 6.31 ;
			LAYER VIA1 ;
			RECT 31.82 6.09 32.04 6.31 ;
			LAYER VIA1 ;
			RECT 32.44 6.09 32.66 6.31 ;
			LAYER VIA1 ;
			RECT 33.06 6.09 33.28 6.31 ;
			LAYER VIA1 ;
			RECT 33.68 6.09 33.9 6.31 ;
			LAYER VIA1 ;
			RECT 34.3 6.09 34.52 6.31 ;
			LAYER VIA1 ;
			RECT 34.92 6.09 35.14 6.31 ;
			LAYER VIA1 ;
			RECT 35.54 6.09 35.76 6.31 ;
			LAYER VIA1 ;
			RECT 36.16 6.09 36.38 6.31 ;
			LAYER M2 ;
			RECT 0 5.78 37.2 6.615 ;
		END
	END VDD
	PIN in
		DIRECTION input ;
		USE SIGNAL ;
		PORT
			LAYER M1 ;
			RECT 1.94 2.75 2.18 3.35 ;
			LAYER M1 ;
			RECT 3.13 2.735 3.37 3.335 ;
			LAYER M1 ;
			RECT 5.48 2.75 5.72 3.35 ;
			LAYER M1 ;
			RECT 6.67 2.735 6.91 3.335 ;
			LAYER M1 ;
			RECT 9.02 2.75 9.26 3.35 ;
			LAYER M1 ;
			RECT 10.21 2.735 10.45 3.335 ;
			LAYER M1 ;
			RECT 12.56 2.75 12.8 3.35 ;
			LAYER M1 ;
			RECT 13.75 2.735 13.99 3.335 ;
			LAYER M1 ;
			RECT 16.1 2.75 16.34 3.35 ;
			LAYER M1 ;
			RECT 17.29 2.735 17.53 3.335 ;
			LAYER M1 ;
			RECT 19.64 2.75 19.88 3.35 ;
			LAYER M1 ;
			RECT 20.83 2.735 21.07 3.335 ;
			LAYER M1 ;
			RECT 23.18 2.75 23.42 3.35 ;
			LAYER M1 ;
			RECT 24.37 2.735 24.61 3.335 ;
			LAYER M1 ;
			RECT 26.72 2.75 26.96 3.35 ;
			LAYER M1 ;
			RECT 27.91 2.735 28.15 3.335 ;
			LAYER M1 ;
			RECT 30.26 2.75 30.5 3.35 ;
			LAYER M1 ;
			RECT 31.45 2.735 31.69 3.335 ;
			LAYER M1 ;
			RECT 33.8 2.735 34.04 3.335 ;
			LAYER M1 ;
			RECT 34.99 2.75 35.23 3.35 ;
			LAYER VIA1 ;
			RECT 1.95 3.065 2.17 3.285 ;
			LAYER VIA1 ;
			RECT 3.14 3.065 3.36 3.285 ;
			LAYER VIA1 ;
			RECT 5.49 3.065 5.71 3.285 ;
			LAYER VIA1 ;
			RECT 6.68 3.065 6.9 3.285 ;
			LAYER VIA1 ;
			RECT 9.03 3.065 9.25 3.285 ;
			LAYER VIA1 ;
			RECT 10.22 3.065 10.44 3.285 ;
			LAYER VIA1 ;
			RECT 12.57 3.065 12.79 3.285 ;
			LAYER VIA1 ;
			RECT 13.76 3.065 13.98 3.285 ;
			LAYER VIA1 ;
			RECT 16.11 3.065 16.33 3.285 ;
			LAYER VIA1 ;
			RECT 17.3 3.065 17.52 3.285 ;
			LAYER VIA1 ;
			RECT 19.65 3.065 19.87 3.285 ;
			LAYER VIA1 ;
			RECT 20.84 3.065 21.06 3.285 ;
			LAYER VIA1 ;
			RECT 23.19 3.065 23.41 3.285 ;
			LAYER VIA1 ;
			RECT 24.38 3.065 24.6 3.285 ;
			LAYER VIA1 ;
			RECT 26.73 3.065 26.95 3.285 ;
			LAYER VIA1 ;
			RECT 27.92 3.065 28.14 3.285 ;
			LAYER VIA1 ;
			RECT 30.27 3.065 30.49 3.285 ;
			LAYER VIA1 ;
			RECT 31.46 3.065 31.68 3.285 ;
			LAYER VIA1 ;
			RECT 33.81 3.065 34.03 3.285 ;
			LAYER VIA1 ;
			RECT 35 3.065 35.22 3.285 ;
			LAYER M2 ;
			RECT 0.12 3.29 37.05 3.53 ;
			LAYER M2 ;
			RECT 1.94 3.015 2.18 3.29 ;
			LAYER M2 ;
			RECT 3.13 3.015 3.37 3.29 ;
			LAYER M2 ;
			RECT 5.48 3.015 5.72 3.29 ;
			LAYER M2 ;
			RECT 6.67 3.015 6.91 3.29 ;
			LAYER M2 ;
			RECT 9.02 3.015 9.26 3.29 ;
			LAYER M2 ;
			RECT 10.21 3.015 10.45 3.29 ;
			LAYER M2 ;
			RECT 12.56 3.015 12.8 3.29 ;
			LAYER M2 ;
			RECT 13.75 3.015 13.99 3.29 ;
			LAYER M2 ;
			RECT 16.1 3.015 16.34 3.29 ;
			LAYER M2 ;
			RECT 17.29 3.015 17.53 3.29 ;
			LAYER M2 ;
			RECT 19.64 3.015 19.88 3.29 ;
			LAYER M2 ;
			RECT 20.83 3.015 21.07 3.29 ;
			LAYER M2 ;
			RECT 23.18 3.015 23.42 3.29 ;
			LAYER M2 ;
			RECT 24.37 3.015 24.61 3.29 ;
			LAYER M2 ;
			RECT 26.72 3.015 26.96 3.29 ;
			LAYER M2 ;
			RECT 27.91 3.015 28.15 3.29 ;
			LAYER M2 ;
			RECT 30.26 3.015 30.5 3.29 ;
			LAYER M2 ;
			RECT 31.45 3.015 31.69 3.29 ;
			LAYER M2 ;
			RECT 33.8 3.015 34.04 3.29 ;
			LAYER M2 ;
			RECT 34.99 3.015 35.23 3.29 ;
		END
		ANTENNASIZE 28.644 ;
	END in
	OBS
	END
END MMI_INVH160
MACRO MMI_INVH192
	CLASS CORE ;
	FOREIGN MMI_INVH192 0 0 ;
	SIZE 23.56 BY 12.4 ;
	SYMMETRY X Y ;
	SITE CORE1 ;
	PIN out
		DIRECTION output ;
		USE SIGNAL ;
		PORT
			LAYER M1 ;
			RECT 1.335 2.32 1.615 5.58 ;
			LAYER M1 ;
			RECT 1.315 2.125 1.635 2.32 ;
			LAYER M1 ;
			RECT 2.515 2.305 2.795 5.58 ;
			LAYER M1 ;
			RECT 3.695 2.335 3.975 5.58 ;
			LAYER M1 ;
			RECT 2.5 2.13 2.82 2.305 ;
			LAYER M1 ;
			RECT 3.675 2.13 3.995 2.335 ;
			LAYER M1 ;
			RECT 4.875 2.32 5.155 5.58 ;
			LAYER M1 ;
			RECT 2.5 2.125 3.995 2.13 ;
			LAYER M1 ;
			RECT 4.855 2.125 5.175 2.32 ;
			LAYER M1 ;
			RECT 6.055 2.305 6.335 5.58 ;
			LAYER M1 ;
			RECT 7.235 2.335 7.515 5.58 ;
			LAYER M1 ;
			RECT 6.04 2.13 6.36 2.305 ;
			LAYER M1 ;
			RECT 7.215 2.13 7.535 2.335 ;
			LAYER M1 ;
			RECT 8.415 2.32 8.695 5.58 ;
			LAYER M1 ;
			RECT 6.04 2.125 7.535 2.13 ;
			LAYER M1 ;
			RECT 8.395 2.125 8.715 2.32 ;
			LAYER M1 ;
			RECT 9.595 2.305 9.875 5.58 ;
			LAYER M1 ;
			RECT 10.775 2.335 11.055 5.58 ;
			LAYER M1 ;
			RECT 9.58 2.13 9.9 2.305 ;
			LAYER M1 ;
			RECT 10.755 2.13 11.075 2.335 ;
			LAYER M1 ;
			RECT 11.955 2.32 12.235 5.58 ;
			LAYER M1 ;
			RECT 9.58 2.125 11.075 2.13 ;
			LAYER M1 ;
			RECT 11.935 2.125 12.255 2.32 ;
			LAYER M1 ;
			RECT 13.135 2.305 13.415 5.58 ;
			LAYER M1 ;
			RECT 14.315 2.335 14.595 5.58 ;
			LAYER M1 ;
			RECT 13.12 2.13 13.44 2.305 ;
			LAYER M1 ;
			RECT 14.295 2.13 14.615 2.335 ;
			LAYER M1 ;
			RECT 15.495 2.32 15.775 5.58 ;
			LAYER M1 ;
			RECT 13.12 2.125 14.615 2.13 ;
			LAYER M1 ;
			RECT 15.475 2.125 15.795 2.32 ;
			LAYER M1 ;
			RECT 16.675 2.305 16.955 5.58 ;
			LAYER M1 ;
			RECT 17.855 2.335 18.135 5.58 ;
			LAYER M1 ;
			RECT 19.035 2.335 19.315 5.58 ;
			LAYER M1 ;
			RECT 16.66 2.13 16.98 2.305 ;
			LAYER M1 ;
			RECT 17.835 2.13 18.155 2.335 ;
			LAYER M1 ;
			RECT 16.66 2.125 18.155 2.13 ;
			LAYER M1 ;
			RECT 19.015 2.13 19.335 2.335 ;
			LAYER M1 ;
			RECT 20.215 2.305 20.495 5.58 ;
			LAYER M1 ;
			RECT 21.395 2.32 21.675 5.58 ;
			LAYER M1 ;
			RECT 20.19 2.13 20.51 2.305 ;
			LAYER M1 ;
			RECT 19.015 2.125 20.51 2.13 ;
			LAYER M1 ;
			RECT 21.375 2.125 21.695 2.32 ;
			LAYER M1 ;
			RECT 1.315 1.885 21.695 2.125 ;
			LAYER M1 ;
			RECT 1.315 1.64 1.635 1.885 ;
			LAYER M1 ;
			RECT 1.335 0.62 1.615 1.64 ;
			LAYER M1 ;
			RECT 2.5 1.625 2.82 1.885 ;
			LAYER M1 ;
			RECT 3.675 1.655 3.995 1.885 ;
			LAYER M1 ;
			RECT 2.515 0.62 2.795 1.625 ;
			LAYER M1 ;
			RECT 3.695 0.62 3.975 1.655 ;
			LAYER M1 ;
			RECT 4.855 1.64 5.175 1.885 ;
			LAYER M1 ;
			RECT 4.875 0.62 5.155 1.64 ;
			LAYER M1 ;
			RECT 6.04 1.625 6.36 1.885 ;
			LAYER M1 ;
			RECT 7.215 1.655 7.535 1.885 ;
			LAYER M1 ;
			RECT 6.055 0.62 6.335 1.625 ;
			LAYER M1 ;
			RECT 7.235 0.62 7.515 1.655 ;
			LAYER M1 ;
			RECT 8.395 1.64 8.715 1.885 ;
			LAYER M1 ;
			RECT 8.415 0.62 8.695 1.64 ;
			LAYER M1 ;
			RECT 9.58 1.625 9.9 1.885 ;
			LAYER M1 ;
			RECT 10.755 1.655 11.075 1.885 ;
			LAYER M1 ;
			RECT 9.595 0.62 9.875 1.625 ;
			LAYER M1 ;
			RECT 10.775 0.62 11.055 1.655 ;
			LAYER M1 ;
			RECT 11.935 1.64 12.255 1.885 ;
			LAYER M1 ;
			RECT 11.955 0.62 12.235 1.64 ;
			LAYER M1 ;
			RECT 13.12 1.625 13.44 1.885 ;
			LAYER M1 ;
			RECT 14.295 1.655 14.615 1.885 ;
			LAYER M1 ;
			RECT 13.135 0.62 13.415 1.625 ;
			LAYER M1 ;
			RECT 14.315 0.62 14.595 1.655 ;
			LAYER M1 ;
			RECT 15.475 1.64 15.795 1.885 ;
			LAYER M1 ;
			RECT 15.495 0.62 15.775 1.64 ;
			LAYER M1 ;
			RECT 16.66 1.625 16.98 1.885 ;
			LAYER M1 ;
			RECT 17.835 1.655 18.155 1.885 ;
			LAYER M1 ;
			RECT 19.015 1.655 19.335 1.885 ;
			LAYER M1 ;
			RECT 16.675 0.62 16.955 1.625 ;
			LAYER M1 ;
			RECT 17.855 0.62 18.135 1.655 ;
			LAYER M1 ;
			RECT 19.035 0.62 19.315 1.655 ;
			LAYER M1 ;
			RECT 20.19 1.625 20.51 1.885 ;
			LAYER M1 ;
			RECT 21.375 1.64 21.695 1.885 ;
			LAYER M1 ;
			RECT 20.215 0.62 20.495 1.625 ;
			LAYER M1 ;
			RECT 21.395 0.62 21.675 1.64 ;
			LAYER VIA1 ;
			RECT 1.365 2.09 1.585 2.31 ;
			LAYER VIA1 ;
			RECT 2.55 2.075 2.77 2.295 ;
			LAYER VIA1 ;
			RECT 3.725 2.105 3.945 2.325 ;
			LAYER VIA1 ;
			RECT 4.905 2.09 5.125 2.31 ;
			LAYER VIA1 ;
			RECT 6.09 2.075 6.31 2.295 ;
			LAYER VIA1 ;
			RECT 7.265 2.105 7.485 2.325 ;
			LAYER VIA1 ;
			RECT 8.445 2.09 8.665 2.31 ;
			LAYER VIA1 ;
			RECT 9.63 2.075 9.85 2.295 ;
			LAYER VIA1 ;
			RECT 10.805 2.105 11.025 2.325 ;
			LAYER VIA1 ;
			RECT 11.985 2.09 12.205 2.31 ;
			LAYER VIA1 ;
			RECT 13.17 2.075 13.39 2.295 ;
			LAYER VIA1 ;
			RECT 14.345 2.105 14.565 2.325 ;
			LAYER VIA1 ;
			RECT 15.525 2.09 15.745 2.31 ;
			LAYER VIA1 ;
			RECT 16.71 2.075 16.93 2.295 ;
			LAYER VIA1 ;
			RECT 17.885 2.105 18.105 2.325 ;
			LAYER VIA1 ;
			RECT 19.065 2.105 19.285 2.325 ;
			LAYER VIA1 ;
			RECT 20.24 2.075 20.46 2.295 ;
			LAYER VIA1 ;
			RECT 21.425 2.09 21.645 2.31 ;
			LAYER VIA1 ;
			RECT 1.365 1.65 1.585 1.87 ;
			LAYER VIA1 ;
			RECT 2.55 1.635 2.77 1.855 ;
			LAYER VIA1 ;
			RECT 3.725 1.665 3.945 1.885 ;
			LAYER VIA1 ;
			RECT 4.905 1.65 5.125 1.87 ;
			LAYER VIA1 ;
			RECT 6.09 1.635 6.31 1.855 ;
			LAYER VIA1 ;
			RECT 7.265 1.665 7.485 1.885 ;
			LAYER VIA1 ;
			RECT 8.445 1.65 8.665 1.87 ;
			LAYER VIA1 ;
			RECT 9.63 1.635 9.85 1.855 ;
			LAYER VIA1 ;
			RECT 10.805 1.665 11.025 1.885 ;
			LAYER VIA1 ;
			RECT 11.985 1.65 12.205 1.87 ;
			LAYER VIA1 ;
			RECT 13.17 1.635 13.39 1.855 ;
			LAYER VIA1 ;
			RECT 14.345 1.665 14.565 1.885 ;
			LAYER VIA1 ;
			RECT 15.525 1.65 15.745 1.87 ;
			LAYER VIA1 ;
			RECT 16.71 1.635 16.93 1.855 ;
			LAYER VIA1 ;
			RECT 17.885 1.665 18.105 1.885 ;
			LAYER VIA1 ;
			RECT 19.065 1.665 19.285 1.885 ;
			LAYER VIA1 ;
			RECT 20.24 1.635 20.46 1.855 ;
			LAYER VIA1 ;
			RECT 21.425 1.65 21.645 1.87 ;
			LAYER M2 ;
			RECT 3.675 2.32 3.995 2.335 ;
			LAYER M2 ;
			RECT 7.215 2.32 7.535 2.335 ;
			LAYER M2 ;
			RECT 10.755 2.32 11.075 2.335 ;
			LAYER M2 ;
			RECT 14.295 2.32 14.615 2.335 ;
			LAYER M2 ;
			RECT 17.835 2.32 18.155 2.335 ;
			LAYER M2 ;
			RECT 19.015 2.32 19.335 2.335 ;
			LAYER M2 ;
			RECT 0.12 1 22.89 2.32 ;
			LAYER M1 ;
			RECT 1.335 10.76 1.615 11.78 ;
			LAYER M1 ;
			RECT 2.515 10.775 2.795 11.78 ;
			LAYER M1 ;
			RECT 1.315 10.515 1.635 10.76 ;
			LAYER M1 ;
			RECT 2.5 10.515 2.82 10.775 ;
			LAYER M1 ;
			RECT 3.695 10.745 3.975 11.78 ;
			LAYER M1 ;
			RECT 4.875 10.76 5.155 11.78 ;
			LAYER M1 ;
			RECT 6.055 10.775 6.335 11.78 ;
			LAYER M1 ;
			RECT 3.675 10.515 3.995 10.745 ;
			LAYER M1 ;
			RECT 4.855 10.515 5.175 10.76 ;
			LAYER M1 ;
			RECT 6.04 10.515 6.36 10.775 ;
			LAYER M1 ;
			RECT 7.235 10.745 7.515 11.78 ;
			LAYER M1 ;
			RECT 8.415 10.76 8.695 11.78 ;
			LAYER M1 ;
			RECT 9.595 10.775 9.875 11.78 ;
			LAYER M1 ;
			RECT 7.215 10.515 7.535 10.745 ;
			LAYER M1 ;
			RECT 8.395 10.515 8.715 10.76 ;
			LAYER M1 ;
			RECT 9.58 10.515 9.9 10.775 ;
			LAYER M1 ;
			RECT 10.775 10.745 11.055 11.78 ;
			LAYER M1 ;
			RECT 11.955 10.76 12.235 11.78 ;
			LAYER M1 ;
			RECT 13.135 10.775 13.415 11.78 ;
			LAYER M1 ;
			RECT 10.755 10.515 11.075 10.745 ;
			LAYER M1 ;
			RECT 11.935 10.515 12.255 10.76 ;
			LAYER M1 ;
			RECT 13.12 10.515 13.44 10.775 ;
			LAYER M1 ;
			RECT 14.315 10.745 14.595 11.78 ;
			LAYER M1 ;
			RECT 15.495 10.76 15.775 11.78 ;
			LAYER M1 ;
			RECT 16.675 10.775 16.955 11.78 ;
			LAYER M1 ;
			RECT 14.295 10.515 14.615 10.745 ;
			LAYER M1 ;
			RECT 15.475 10.515 15.795 10.76 ;
			LAYER M1 ;
			RECT 16.66 10.515 16.98 10.775 ;
			LAYER M1 ;
			RECT 17.855 10.745 18.135 11.78 ;
			LAYER M1 ;
			RECT 19.035 10.745 19.315 11.78 ;
			LAYER M1 ;
			RECT 20.215 10.775 20.495 11.78 ;
			LAYER M1 ;
			RECT 17.835 10.515 18.155 10.745 ;
			LAYER M1 ;
			RECT 19.015 10.515 19.335 10.745 ;
			LAYER M1 ;
			RECT 20.19 10.515 20.51 10.775 ;
			LAYER M1 ;
			RECT 21.395 10.76 21.675 11.78 ;
			LAYER M1 ;
			RECT 21.375 10.515 21.695 10.76 ;
			LAYER M1 ;
			RECT 1.315 10.275 21.695 10.515 ;
			LAYER M1 ;
			RECT 1.315 10.08 1.635 10.275 ;
			LAYER M1 ;
			RECT 2.5 10.27 3.995 10.275 ;
			LAYER M1 ;
			RECT 2.5 10.095 2.82 10.27 ;
			LAYER M1 ;
			RECT 1.335 6.82 1.615 10.08 ;
			LAYER M1 ;
			RECT 2.515 6.82 2.795 10.095 ;
			LAYER M1 ;
			RECT 3.675 10.065 3.995 10.27 ;
			LAYER M1 ;
			RECT 4.855 10.08 5.175 10.275 ;
			LAYER M1 ;
			RECT 6.04 10.27 7.535 10.275 ;
			LAYER M1 ;
			RECT 6.04 10.095 6.36 10.27 ;
			LAYER M1 ;
			RECT 3.695 6.82 3.975 10.065 ;
			LAYER M1 ;
			RECT 4.875 6.82 5.155 10.08 ;
			LAYER M1 ;
			RECT 6.055 6.82 6.335 10.095 ;
			LAYER M1 ;
			RECT 7.215 10.065 7.535 10.27 ;
			LAYER M1 ;
			RECT 8.395 10.08 8.715 10.275 ;
			LAYER M1 ;
			RECT 9.58 10.27 11.075 10.275 ;
			LAYER M1 ;
			RECT 9.58 10.095 9.9 10.27 ;
			LAYER M1 ;
			RECT 7.235 6.82 7.515 10.065 ;
			LAYER M1 ;
			RECT 8.415 6.82 8.695 10.08 ;
			LAYER M1 ;
			RECT 9.595 6.82 9.875 10.095 ;
			LAYER M1 ;
			RECT 10.755 10.065 11.075 10.27 ;
			LAYER M1 ;
			RECT 11.935 10.08 12.255 10.275 ;
			LAYER M1 ;
			RECT 13.12 10.27 14.615 10.275 ;
			LAYER M1 ;
			RECT 13.12 10.095 13.44 10.27 ;
			LAYER M1 ;
			RECT 10.775 6.82 11.055 10.065 ;
			LAYER M1 ;
			RECT 11.955 6.82 12.235 10.08 ;
			LAYER M1 ;
			RECT 13.135 6.82 13.415 10.095 ;
			LAYER M1 ;
			RECT 14.295 10.065 14.615 10.27 ;
			LAYER M1 ;
			RECT 15.475 10.08 15.795 10.275 ;
			LAYER M1 ;
			RECT 16.66 10.27 18.155 10.275 ;
			LAYER M1 ;
			RECT 16.66 10.095 16.98 10.27 ;
			LAYER M1 ;
			RECT 14.315 6.82 14.595 10.065 ;
			LAYER M1 ;
			RECT 15.495 6.82 15.775 10.08 ;
			LAYER M1 ;
			RECT 16.675 6.82 16.955 10.095 ;
			LAYER M1 ;
			RECT 17.835 10.065 18.155 10.27 ;
			LAYER M1 ;
			RECT 19.015 10.27 20.51 10.275 ;
			LAYER M1 ;
			RECT 19.015 10.065 19.335 10.27 ;
			LAYER M1 ;
			RECT 20.19 10.095 20.51 10.27 ;
			LAYER M1 ;
			RECT 17.855 6.82 18.135 10.065 ;
			LAYER M1 ;
			RECT 19.035 6.82 19.315 10.065 ;
			LAYER M1 ;
			RECT 20.215 6.82 20.495 10.095 ;
			LAYER M1 ;
			RECT 21.375 10.08 21.695 10.275 ;
			LAYER M1 ;
			RECT 21.395 6.82 21.675 10.08 ;
			LAYER VIA1 ;
			RECT 1.365 10.53 1.585 10.75 ;
			LAYER VIA1 ;
			RECT 2.55 10.545 2.77 10.765 ;
			LAYER VIA1 ;
			RECT 3.725 10.515 3.945 10.735 ;
			LAYER VIA1 ;
			RECT 4.905 10.53 5.125 10.75 ;
			LAYER VIA1 ;
			RECT 6.09 10.545 6.31 10.765 ;
			LAYER VIA1 ;
			RECT 7.265 10.515 7.485 10.735 ;
			LAYER VIA1 ;
			RECT 8.445 10.53 8.665 10.75 ;
			LAYER VIA1 ;
			RECT 9.63 10.545 9.85 10.765 ;
			LAYER VIA1 ;
			RECT 10.805 10.515 11.025 10.735 ;
			LAYER VIA1 ;
			RECT 11.985 10.53 12.205 10.75 ;
			LAYER VIA1 ;
			RECT 13.17 10.545 13.39 10.765 ;
			LAYER VIA1 ;
			RECT 14.345 10.515 14.565 10.735 ;
			LAYER VIA1 ;
			RECT 15.525 10.53 15.745 10.75 ;
			LAYER VIA1 ;
			RECT 16.71 10.545 16.93 10.765 ;
			LAYER VIA1 ;
			RECT 17.885 10.515 18.105 10.735 ;
			LAYER VIA1 ;
			RECT 19.065 10.515 19.285 10.735 ;
			LAYER VIA1 ;
			RECT 20.24 10.545 20.46 10.765 ;
			LAYER VIA1 ;
			RECT 21.425 10.53 21.645 10.75 ;
			LAYER VIA1 ;
			RECT 1.365 10.09 1.585 10.31 ;
			LAYER VIA1 ;
			RECT 2.55 10.105 2.77 10.325 ;
			LAYER VIA1 ;
			RECT 3.725 10.075 3.945 10.295 ;
			LAYER VIA1 ;
			RECT 4.905 10.09 5.125 10.31 ;
			LAYER VIA1 ;
			RECT 6.09 10.105 6.31 10.325 ;
			LAYER VIA1 ;
			RECT 7.265 10.075 7.485 10.295 ;
			LAYER VIA1 ;
			RECT 8.445 10.09 8.665 10.31 ;
			LAYER VIA1 ;
			RECT 9.63 10.105 9.85 10.325 ;
			LAYER VIA1 ;
			RECT 10.805 10.075 11.025 10.295 ;
			LAYER VIA1 ;
			RECT 11.985 10.09 12.205 10.31 ;
			LAYER VIA1 ;
			RECT 13.17 10.105 13.39 10.325 ;
			LAYER VIA1 ;
			RECT 14.345 10.075 14.565 10.295 ;
			LAYER VIA1 ;
			RECT 15.525 10.09 15.745 10.31 ;
			LAYER VIA1 ;
			RECT 16.71 10.105 16.93 10.325 ;
			LAYER VIA1 ;
			RECT 17.885 10.075 18.105 10.295 ;
			LAYER VIA1 ;
			RECT 19.065 10.075 19.285 10.295 ;
			LAYER VIA1 ;
			RECT 20.24 10.105 20.46 10.325 ;
			LAYER VIA1 ;
			RECT 21.425 10.09 21.645 10.31 ;
			LAYER M2 ;
			RECT 0.12 10.08 22.89 11.4 ;
			LAYER M2 ;
			RECT 3.675 10.065 3.995 10.08 ;
			LAYER M2 ;
			RECT 7.215 10.065 7.535 10.08 ;
			LAYER M2 ;
			RECT 10.755 10.065 11.075 10.08 ;
			LAYER M2 ;
			RECT 14.295 10.065 14.615 10.08 ;
			LAYER M2 ;
			RECT 17.835 10.065 18.155 10.08 ;
			LAYER M2 ;
			RECT 19.015 10.065 19.335 10.08 ;
		END
	END out
	PIN GND
		DIRECTION inout ;
		USE GROUND ;
		PORT
			LAYER M1 ;
			RECT 0.155 0.42 0.435 1.575 ;
			LAYER M1 ;
			RECT 0.745 0.42 1.025 1.575 ;
			LAYER M1 ;
			RECT 1.925 0.42 2.205 1.575 ;
			LAYER M1 ;
			RECT 3.105 0.42 3.385 1.575 ;
			LAYER M1 ;
			RECT 4.285 0.42 4.565 1.575 ;
			LAYER M1 ;
			RECT 5.465 0.42 5.745 1.575 ;
			LAYER M1 ;
			RECT 6.645 0.42 6.925 1.575 ;
			LAYER M1 ;
			RECT 7.825 0.42 8.105 1.575 ;
			LAYER M1 ;
			RECT 9.005 0.42 9.285 1.575 ;
			LAYER M1 ;
			RECT 10.185 0.42 10.465 1.575 ;
			LAYER M1 ;
			RECT 11.365 0.42 11.645 1.575 ;
			LAYER M1 ;
			RECT 12.545 0.42 12.825 1.575 ;
			LAYER M1 ;
			RECT 13.725 0.42 14.005 1.575 ;
			LAYER M1 ;
			RECT 14.905 0.42 15.185 1.575 ;
			LAYER M1 ;
			RECT 16.085 0.42 16.365 1.575 ;
			LAYER M1 ;
			RECT 17.265 0.42 17.545 1.575 ;
			LAYER M1 ;
			RECT 18.445 0.42 18.725 1.575 ;
			LAYER M1 ;
			RECT 19.625 0.42 19.905 1.575 ;
			LAYER M1 ;
			RECT 20.805 0.42 21.085 1.575 ;
			LAYER M1 ;
			RECT 21.985 0.42 22.265 1.575 ;
			LAYER M1 ;
			RECT 22.575 0.42 22.855 1.575 ;
			LAYER M1 ;
			RECT 0 0.35 22.855 0.42 ;
			LAYER M1 ;
			RECT 0 -0.42 23.56 0.35 ;
			LAYER VIA1 ;
			RECT 0.82 -0.11 1.04 0.11 ;
			LAYER VIA1 ;
			RECT 1.44 -0.11 1.66 0.11 ;
			LAYER VIA1 ;
			RECT 2.06 -0.11 2.28 0.11 ;
			LAYER VIA1 ;
			RECT 2.68 -0.11 2.9 0.11 ;
			LAYER VIA1 ;
			RECT 3.3 -0.11 3.52 0.11 ;
			LAYER VIA1 ;
			RECT 3.92 -0.11 4.14 0.11 ;
			LAYER VIA1 ;
			RECT 4.54 -0.11 4.76 0.11 ;
			LAYER VIA1 ;
			RECT 5.16 -0.11 5.38 0.11 ;
			LAYER VIA1 ;
			RECT 7.02 -0.11 7.24 0.11 ;
			LAYER VIA1 ;
			RECT 7.64 -0.11 7.86 0.11 ;
			LAYER VIA1 ;
			RECT 8.26 -0.11 8.48 0.11 ;
			LAYER VIA1 ;
			RECT 8.88 -0.11 9.1 0.11 ;
			LAYER VIA1 ;
			RECT 9.5 -0.11 9.72 0.11 ;
			LAYER VIA1 ;
			RECT 10.12 -0.11 10.34 0.11 ;
			LAYER VIA1 ;
			RECT 10.74 -0.11 10.96 0.11 ;
			LAYER VIA1 ;
			RECT 11.36 -0.11 11.58 0.11 ;
			LAYER VIA1 ;
			RECT 13.22 -0.11 13.44 0.11 ;
			LAYER VIA1 ;
			RECT 13.84 -0.11 14.06 0.11 ;
			LAYER VIA1 ;
			RECT 14.46 -0.11 14.68 0.11 ;
			LAYER VIA1 ;
			RECT 15.08 -0.11 15.3 0.11 ;
			LAYER VIA1 ;
			RECT 15.7 -0.11 15.92 0.11 ;
			LAYER VIA1 ;
			RECT 16.32 -0.11 16.54 0.11 ;
			LAYER VIA1 ;
			RECT 16.94 -0.11 17.16 0.11 ;
			LAYER VIA1 ;
			RECT 17.56 -0.11 17.78 0.11 ;
			LAYER VIA1 ;
			RECT 19.42 -0.11 19.64 0.11 ;
			LAYER VIA1 ;
			RECT 20.04 -0.11 20.26 0.11 ;
			LAYER VIA1 ;
			RECT 20.66 -0.11 20.88 0.11 ;
			LAYER VIA1 ;
			RECT 21.28 -0.11 21.5 0.11 ;
			LAYER VIA1 ;
			RECT 21.9 -0.11 22.12 0.11 ;
			LAYER VIA1 ;
			RECT 22.52 -0.11 22.74 0.11 ;
			LAYER VIA1 ;
			RECT 23.14 -0.11 23.36 0.11 ;
			LAYER M2 ;
			RECT 0 -0.415 23.56 0.42 ;
			LAYER M1 ;
			RECT 0 12.05 23.56 12.82 ;
			LAYER M1 ;
			RECT 0 11.98 22.855 12.05 ;
			LAYER M1 ;
			RECT 0.155 10.825 0.435 11.98 ;
			LAYER M1 ;
			RECT 0.745 10.825 1.025 11.98 ;
			LAYER M1 ;
			RECT 1.925 10.825 2.205 11.98 ;
			LAYER M1 ;
			RECT 3.105 10.825 3.385 11.98 ;
			LAYER M1 ;
			RECT 4.285 10.825 4.565 11.98 ;
			LAYER M1 ;
			RECT 5.465 10.825 5.745 11.98 ;
			LAYER M1 ;
			RECT 6.645 10.825 6.925 11.98 ;
			LAYER M1 ;
			RECT 7.825 10.825 8.105 11.98 ;
			LAYER M1 ;
			RECT 9.005 10.825 9.285 11.98 ;
			LAYER M1 ;
			RECT 10.185 10.825 10.465 11.98 ;
			LAYER M1 ;
			RECT 11.365 10.825 11.645 11.98 ;
			LAYER M1 ;
			RECT 12.545 10.825 12.825 11.98 ;
			LAYER M1 ;
			RECT 13.725 10.825 14.005 11.98 ;
			LAYER M1 ;
			RECT 14.905 10.825 15.185 11.98 ;
			LAYER M1 ;
			RECT 16.085 10.825 16.365 11.98 ;
			LAYER M1 ;
			RECT 17.265 10.825 17.545 11.98 ;
			LAYER M1 ;
			RECT 18.445 10.825 18.725 11.98 ;
			LAYER M1 ;
			RECT 19.625 10.825 19.905 11.98 ;
			LAYER M1 ;
			RECT 20.805 10.825 21.085 11.98 ;
			LAYER M1 ;
			RECT 21.985 10.825 22.265 11.98 ;
			LAYER M1 ;
			RECT 22.575 10.825 22.855 11.98 ;
			LAYER VIA1 ;
			RECT 0.82 12.29 1.04 12.51 ;
			LAYER VIA1 ;
			RECT 1.44 12.29 1.66 12.51 ;
			LAYER VIA1 ;
			RECT 2.06 12.29 2.28 12.51 ;
			LAYER VIA1 ;
			RECT 2.68 12.29 2.9 12.51 ;
			LAYER VIA1 ;
			RECT 3.3 12.29 3.52 12.51 ;
			LAYER VIA1 ;
			RECT 3.92 12.29 4.14 12.51 ;
			LAYER VIA1 ;
			RECT 4.54 12.29 4.76 12.51 ;
			LAYER VIA1 ;
			RECT 5.16 12.29 5.38 12.51 ;
			LAYER VIA1 ;
			RECT 7.02 12.29 7.24 12.51 ;
			LAYER VIA1 ;
			RECT 7.64 12.29 7.86 12.51 ;
			LAYER VIA1 ;
			RECT 8.26 12.29 8.48 12.51 ;
			LAYER VIA1 ;
			RECT 8.88 12.29 9.1 12.51 ;
			LAYER VIA1 ;
			RECT 9.5 12.29 9.72 12.51 ;
			LAYER VIA1 ;
			RECT 10.12 12.29 10.34 12.51 ;
			LAYER VIA1 ;
			RECT 10.74 12.29 10.96 12.51 ;
			LAYER VIA1 ;
			RECT 11.36 12.29 11.58 12.51 ;
			LAYER VIA1 ;
			RECT 13.22 12.29 13.44 12.51 ;
			LAYER VIA1 ;
			RECT 13.84 12.29 14.06 12.51 ;
			LAYER VIA1 ;
			RECT 14.46 12.29 14.68 12.51 ;
			LAYER VIA1 ;
			RECT 15.08 12.29 15.3 12.51 ;
			LAYER VIA1 ;
			RECT 15.7 12.29 15.92 12.51 ;
			LAYER VIA1 ;
			RECT 16.32 12.29 16.54 12.51 ;
			LAYER VIA1 ;
			RECT 16.94 12.29 17.16 12.51 ;
			LAYER VIA1 ;
			RECT 17.56 12.29 17.78 12.51 ;
			LAYER VIA1 ;
			RECT 19.42 12.29 19.64 12.51 ;
			LAYER VIA1 ;
			RECT 20.04 12.29 20.26 12.51 ;
			LAYER VIA1 ;
			RECT 20.66 12.29 20.88 12.51 ;
			LAYER VIA1 ;
			RECT 21.28 12.29 21.5 12.51 ;
			LAYER VIA1 ;
			RECT 21.9 12.29 22.12 12.51 ;
			LAYER VIA1 ;
			RECT 22.52 12.29 22.74 12.51 ;
			LAYER VIA1 ;
			RECT 23.14 12.29 23.36 12.51 ;
			LAYER M2 ;
			RECT 0 11.98 23.56 12.815 ;
		END
	END GND
	PIN VDD
		DIRECTION inout ;
		USE POWER ;
		PORT
			LAYER M1 ;
			RECT 0.155 6.62 0.435 8.805 ;
			LAYER M1 ;
			RECT 0.745 6.62 1.025 8.805 ;
			LAYER M1 ;
			RECT 1.925 6.62 2.205 8.805 ;
			LAYER M1 ;
			RECT 3.105 6.62 3.385 8.805 ;
			LAYER M1 ;
			RECT 4.285 6.62 4.565 8.805 ;
			LAYER M1 ;
			RECT 5.465 6.62 5.745 8.805 ;
			LAYER M1 ;
			RECT 6.645 6.62 6.925 8.805 ;
			LAYER M1 ;
			RECT 7.825 6.62 8.105 8.805 ;
			LAYER M1 ;
			RECT 9.005 6.62 9.285 8.805 ;
			LAYER M1 ;
			RECT 10.185 6.62 10.465 8.805 ;
			LAYER M1 ;
			RECT 11.365 6.62 11.645 8.805 ;
			LAYER M1 ;
			RECT 12.545 6.62 12.825 8.805 ;
			LAYER M1 ;
			RECT 13.725 6.62 14.005 8.805 ;
			LAYER M1 ;
			RECT 14.905 6.62 15.185 8.805 ;
			LAYER M1 ;
			RECT 16.085 6.62 16.365 8.805 ;
			LAYER M1 ;
			RECT 17.265 6.62 17.545 8.805 ;
			LAYER M1 ;
			RECT 18.445 6.62 18.725 8.805 ;
			LAYER M1 ;
			RECT 19.625 6.62 19.905 8.805 ;
			LAYER M1 ;
			RECT 20.805 6.62 21.085 8.805 ;
			LAYER M1 ;
			RECT 21.985 6.62 22.265 8.805 ;
			LAYER M1 ;
			RECT 22.575 6.62 22.855 8.805 ;
			LAYER M1 ;
			RECT 0 5.78 23.56 6.62 ;
			LAYER M1 ;
			RECT 0.155 3.595 0.435 5.78 ;
			LAYER M1 ;
			RECT 0.745 3.595 1.025 5.78 ;
			LAYER M1 ;
			RECT 1.925 3.595 2.205 5.78 ;
			LAYER M1 ;
			RECT 3.105 3.595 3.385 5.78 ;
			LAYER M1 ;
			RECT 4.285 3.595 4.565 5.78 ;
			LAYER M1 ;
			RECT 5.465 3.595 5.745 5.78 ;
			LAYER M1 ;
			RECT 6.645 3.595 6.925 5.78 ;
			LAYER M1 ;
			RECT 7.825 3.595 8.105 5.78 ;
			LAYER M1 ;
			RECT 9.005 3.595 9.285 5.78 ;
			LAYER M1 ;
			RECT 10.185 3.595 10.465 5.78 ;
			LAYER M1 ;
			RECT 11.365 3.595 11.645 5.78 ;
			LAYER M1 ;
			RECT 12.545 3.595 12.825 5.78 ;
			LAYER M1 ;
			RECT 13.725 3.595 14.005 5.78 ;
			LAYER M1 ;
			RECT 14.905 3.595 15.185 5.78 ;
			LAYER M1 ;
			RECT 16.085 3.595 16.365 5.78 ;
			LAYER M1 ;
			RECT 17.265 3.595 17.545 5.78 ;
			LAYER M1 ;
			RECT 18.445 3.595 18.725 5.78 ;
			LAYER M1 ;
			RECT 19.625 3.595 19.905 5.78 ;
			LAYER M1 ;
			RECT 20.805 3.595 21.085 5.78 ;
			LAYER M1 ;
			RECT 21.985 3.595 22.265 5.78 ;
			LAYER M1 ;
			RECT 22.575 3.595 22.855 5.78 ;
			LAYER VIA1 ;
			RECT 0.82 6.09 1.04 6.31 ;
			LAYER VIA1 ;
			RECT 1.44 6.09 1.66 6.31 ;
			LAYER VIA1 ;
			RECT 2.06 6.09 2.28 6.31 ;
			LAYER VIA1 ;
			RECT 2.68 6.09 2.9 6.31 ;
			LAYER VIA1 ;
			RECT 3.3 6.09 3.52 6.31 ;
			LAYER VIA1 ;
			RECT 3.92 6.09 4.14 6.31 ;
			LAYER VIA1 ;
			RECT 4.54 6.09 4.76 6.31 ;
			LAYER VIA1 ;
			RECT 5.16 6.09 5.38 6.31 ;
			LAYER VIA1 ;
			RECT 7.02 6.09 7.24 6.31 ;
			LAYER VIA1 ;
			RECT 7.64 6.09 7.86 6.31 ;
			LAYER VIA1 ;
			RECT 8.26 6.09 8.48 6.31 ;
			LAYER VIA1 ;
			RECT 8.88 6.09 9.1 6.31 ;
			LAYER VIA1 ;
			RECT 9.5 6.09 9.72 6.31 ;
			LAYER VIA1 ;
			RECT 10.12 6.09 10.34 6.31 ;
			LAYER VIA1 ;
			RECT 10.74 6.09 10.96 6.31 ;
			LAYER VIA1 ;
			RECT 11.36 6.09 11.58 6.31 ;
			LAYER VIA1 ;
			RECT 13.22 6.09 13.44 6.31 ;
			LAYER VIA1 ;
			RECT 13.84 6.09 14.06 6.31 ;
			LAYER VIA1 ;
			RECT 14.46 6.09 14.68 6.31 ;
			LAYER VIA1 ;
			RECT 15.08 6.09 15.3 6.31 ;
			LAYER VIA1 ;
			RECT 15.7 6.09 15.92 6.31 ;
			LAYER VIA1 ;
			RECT 16.32 6.09 16.54 6.31 ;
			LAYER VIA1 ;
			RECT 16.94 6.09 17.16 6.31 ;
			LAYER VIA1 ;
			RECT 17.56 6.09 17.78 6.31 ;
			LAYER VIA1 ;
			RECT 19.42 6.09 19.64 6.31 ;
			LAYER VIA1 ;
			RECT 20.04 6.09 20.26 6.31 ;
			LAYER VIA1 ;
			RECT 20.66 6.09 20.88 6.31 ;
			LAYER VIA1 ;
			RECT 21.28 6.09 21.5 6.31 ;
			LAYER VIA1 ;
			RECT 21.9 6.09 22.12 6.31 ;
			LAYER VIA1 ;
			RECT 22.52 6.09 22.74 6.31 ;
			LAYER VIA1 ;
			RECT 23.14 6.09 23.36 6.31 ;
			LAYER M2 ;
			RECT 0 5.78 23.56 6.62 ;
		END
	END VDD
	PIN in
		DIRECTION input ;
		USE SIGNAL ;
		PORT
			LAYER M1 ;
			RECT 1.94 2.75 2.18 3.35 ;
			LAYER M1 ;
			RECT 3.13 2.735 3.37 3.335 ;
			LAYER M1 ;
			RECT 5.48 2.75 5.72 3.35 ;
			LAYER M1 ;
			RECT 6.67 2.735 6.91 3.335 ;
			LAYER M1 ;
			RECT 9.02 2.75 9.26 3.35 ;
			LAYER M1 ;
			RECT 10.21 2.735 10.45 3.335 ;
			LAYER M1 ;
			RECT 12.56 2.75 12.8 3.35 ;
			LAYER M1 ;
			RECT 13.75 2.735 13.99 3.335 ;
			LAYER M1 ;
			RECT 16.1 2.75 16.34 3.35 ;
			LAYER M1 ;
			RECT 17.29 2.735 17.53 3.335 ;
			LAYER M1 ;
			RECT 19.64 2.735 19.88 3.335 ;
			LAYER M1 ;
			RECT 20.83 2.75 21.07 3.35 ;
			LAYER VIA1 ;
			RECT 1.95 3.065 2.17 3.285 ;
			LAYER VIA1 ;
			RECT 3.14 3.065 3.36 3.285 ;
			LAYER VIA1 ;
			RECT 5.49 3.065 5.71 3.285 ;
			LAYER VIA1 ;
			RECT 6.68 3.065 6.9 3.285 ;
			LAYER VIA1 ;
			RECT 9.03 3.065 9.25 3.285 ;
			LAYER VIA1 ;
			RECT 10.22 3.065 10.44 3.285 ;
			LAYER VIA1 ;
			RECT 12.57 3.065 12.79 3.285 ;
			LAYER VIA1 ;
			RECT 13.76 3.065 13.98 3.285 ;
			LAYER VIA1 ;
			RECT 16.11 3.065 16.33 3.285 ;
			LAYER VIA1 ;
			RECT 17.3 3.065 17.52 3.285 ;
			LAYER VIA1 ;
			RECT 19.65 3.065 19.87 3.285 ;
			LAYER VIA1 ;
			RECT 20.84 3.065 21.06 3.285 ;
			LAYER M2 ;
			RECT 0.12 3.29 22.89 3.53 ;
			LAYER M2 ;
			RECT 1.94 3.015 2.18 3.29 ;
			LAYER M2 ;
			RECT 3.13 3.015 3.37 3.29 ;
			LAYER M2 ;
			RECT 5.48 3.015 5.72 3.29 ;
			LAYER M2 ;
			RECT 6.67 3.015 6.91 3.29 ;
			LAYER M2 ;
			RECT 9.02 3.015 9.26 3.29 ;
			LAYER M2 ;
			RECT 10.21 3.015 10.45 3.29 ;
			LAYER M2 ;
			RECT 12.56 3.015 12.8 3.29 ;
			LAYER M2 ;
			RECT 13.75 3.015 13.99 3.29 ;
			LAYER M2 ;
			RECT 16.1 3.015 16.34 3.29 ;
			LAYER M2 ;
			RECT 17.29 3.015 17.53 3.29 ;
			LAYER M2 ;
			RECT 19.64 3.015 19.88 3.29 ;
			LAYER M2 ;
			RECT 20.83 3.015 21.07 3.29 ;
			LAYER M1 ;
			RECT 1.94 9.05 2.18 9.65 ;
			LAYER M1 ;
			RECT 3.13 9.065 3.37 9.665 ;
			LAYER M1 ;
			RECT 5.48 9.05 5.72 9.65 ;
			LAYER M1 ;
			RECT 6.67 9.065 6.91 9.665 ;
			LAYER M1 ;
			RECT 9.02 9.05 9.26 9.65 ;
			LAYER M1 ;
			RECT 10.21 9.065 10.45 9.665 ;
			LAYER M1 ;
			RECT 12.56 9.05 12.8 9.65 ;
			LAYER M1 ;
			RECT 13.75 9.065 13.99 9.665 ;
			LAYER M1 ;
			RECT 16.1 9.05 16.34 9.65 ;
			LAYER M1 ;
			RECT 17.29 9.065 17.53 9.665 ;
			LAYER M1 ;
			RECT 19.64 9.065 19.88 9.665 ;
			LAYER M1 ;
			RECT 20.83 9.05 21.07 9.65 ;
			LAYER VIA1 ;
			RECT 1.95 9.115 2.17 9.335 ;
			LAYER VIA1 ;
			RECT 3.14 9.115 3.36 9.335 ;
			LAYER VIA1 ;
			RECT 5.49 9.115 5.71 9.335 ;
			LAYER VIA1 ;
			RECT 6.68 9.115 6.9 9.335 ;
			LAYER VIA1 ;
			RECT 9.03 9.115 9.25 9.335 ;
			LAYER VIA1 ;
			RECT 10.22 9.115 10.44 9.335 ;
			LAYER VIA1 ;
			RECT 12.57 9.115 12.79 9.335 ;
			LAYER VIA1 ;
			RECT 13.76 9.115 13.98 9.335 ;
			LAYER VIA1 ;
			RECT 16.11 9.115 16.33 9.335 ;
			LAYER VIA1 ;
			RECT 17.3 9.115 17.52 9.335 ;
			LAYER VIA1 ;
			RECT 19.65 9.115 19.87 9.335 ;
			LAYER VIA1 ;
			RECT 20.84 9.115 21.06 9.335 ;
			LAYER M2 ;
			RECT 1.94 9.11 2.18 9.385 ;
			LAYER M2 ;
			RECT 3.13 9.11 3.37 9.385 ;
			LAYER M2 ;
			RECT 5.48 9.11 5.72 9.385 ;
			LAYER M2 ;
			RECT 6.67 9.11 6.91 9.385 ;
			LAYER M2 ;
			RECT 9.02 9.11 9.26 9.385 ;
			LAYER M2 ;
			RECT 10.21 9.11 10.45 9.385 ;
			LAYER M2 ;
			RECT 12.56 9.11 12.8 9.385 ;
			LAYER M2 ;
			RECT 13.75 9.11 13.99 9.385 ;
			LAYER M2 ;
			RECT 16.1 9.11 16.34 9.385 ;
			LAYER M2 ;
			RECT 17.29 9.11 17.53 9.385 ;
			LAYER M2 ;
			RECT 19.64 9.11 19.88 9.385 ;
			LAYER M2 ;
			RECT 20.83 9.11 21.07 9.385 ;
			LAYER M2 ;
			RECT 0.12 8.87 22.89 9.11 ;
		END
		ANTENNASIZE 17.556 ;
	END in
	OBS
	END
END MMI_INVH192
MACRO MMI_INVH224
	CLASS CORE ;
	FOREIGN MMI_INVH224 0 0 ;
	SIZE 26.66 BY 12.4 ;
	SYMMETRY X Y ;
	SITE CORE1 ;
	PIN out
		DIRECTION output ;
		USE SIGNAL ;
		PORT
			LAYER M1 ;
			RECT 1.335 2.32 1.615 5.58 ;
			LAYER M1 ;
			RECT 1.315 2.125 1.635 2.32 ;
			LAYER M1 ;
			RECT 2.515 2.305 2.795 5.58 ;
			LAYER M1 ;
			RECT 3.695 2.335 3.975 5.58 ;
			LAYER M1 ;
			RECT 2.5 2.13 2.82 2.305 ;
			LAYER M1 ;
			RECT 3.675 2.13 3.995 2.335 ;
			LAYER M1 ;
			RECT 4.875 2.32 5.155 5.58 ;
			LAYER M1 ;
			RECT 2.5 2.125 3.995 2.13 ;
			LAYER M1 ;
			RECT 4.855 2.125 5.175 2.32 ;
			LAYER M1 ;
			RECT 6.055 2.305 6.335 5.58 ;
			LAYER M1 ;
			RECT 7.235 2.335 7.515 5.58 ;
			LAYER M1 ;
			RECT 6.04 2.13 6.36 2.305 ;
			LAYER M1 ;
			RECT 7.215 2.13 7.535 2.335 ;
			LAYER M1 ;
			RECT 8.415 2.32 8.695 5.58 ;
			LAYER M1 ;
			RECT 6.04 2.125 7.535 2.13 ;
			LAYER M1 ;
			RECT 8.395 2.125 8.715 2.32 ;
			LAYER M1 ;
			RECT 9.595 2.305 9.875 5.58 ;
			LAYER M1 ;
			RECT 10.775 2.335 11.055 5.58 ;
			LAYER M1 ;
			RECT 9.58 2.13 9.9 2.305 ;
			LAYER M1 ;
			RECT 10.755 2.13 11.075 2.335 ;
			LAYER M1 ;
			RECT 11.955 2.32 12.235 5.58 ;
			LAYER M1 ;
			RECT 9.58 2.125 11.075 2.13 ;
			LAYER M1 ;
			RECT 11.935 2.125 12.255 2.32 ;
			LAYER M1 ;
			RECT 13.135 2.305 13.415 5.58 ;
			LAYER M1 ;
			RECT 14.315 2.335 14.595 5.58 ;
			LAYER M1 ;
			RECT 13.12 2.13 13.44 2.305 ;
			LAYER M1 ;
			RECT 14.295 2.13 14.615 2.335 ;
			LAYER M1 ;
			RECT 15.495 2.32 15.775 5.58 ;
			LAYER M1 ;
			RECT 13.12 2.125 14.615 2.13 ;
			LAYER M1 ;
			RECT 15.475 2.125 15.795 2.32 ;
			LAYER M1 ;
			RECT 16.675 2.305 16.955 5.58 ;
			LAYER M1 ;
			RECT 17.855 2.335 18.135 5.58 ;
			LAYER M1 ;
			RECT 16.66 2.13 16.98 2.305 ;
			LAYER M1 ;
			RECT 17.835 2.13 18.155 2.335 ;
			LAYER M1 ;
			RECT 19.035 2.32 19.315 5.58 ;
			LAYER M1 ;
			RECT 16.66 2.125 18.155 2.13 ;
			LAYER M1 ;
			RECT 19.015 2.125 19.335 2.32 ;
			LAYER M1 ;
			RECT 20.215 2.305 20.495 5.58 ;
			LAYER M1 ;
			RECT 21.395 2.335 21.675 5.58 ;
			LAYER M1 ;
			RECT 22.575 2.335 22.855 5.58 ;
			LAYER M1 ;
			RECT 20.2 2.13 20.52 2.305 ;
			LAYER M1 ;
			RECT 21.375 2.13 21.695 2.335 ;
			LAYER M1 ;
			RECT 20.2 2.125 21.695 2.13 ;
			LAYER M1 ;
			RECT 22.555 2.13 22.875 2.335 ;
			LAYER M1 ;
			RECT 23.755 2.305 24.035 5.58 ;
			LAYER M1 ;
			RECT 24.935 2.32 25.215 5.58 ;
			LAYER M1 ;
			RECT 23.73 2.13 24.05 2.305 ;
			LAYER M1 ;
			RECT 22.555 2.125 24.05 2.13 ;
			LAYER M1 ;
			RECT 24.915 2.125 25.235 2.32 ;
			LAYER M1 ;
			RECT 1.315 1.885 25.235 2.125 ;
			LAYER M1 ;
			RECT 1.315 1.64 1.635 1.885 ;
			LAYER M1 ;
			RECT 1.335 0.62 1.615 1.64 ;
			LAYER M1 ;
			RECT 2.5 1.625 2.82 1.885 ;
			LAYER M1 ;
			RECT 3.675 1.655 3.995 1.885 ;
			LAYER M1 ;
			RECT 2.515 0.62 2.795 1.625 ;
			LAYER M1 ;
			RECT 3.695 0.62 3.975 1.655 ;
			LAYER M1 ;
			RECT 4.855 1.64 5.175 1.885 ;
			LAYER M1 ;
			RECT 4.875 0.62 5.155 1.64 ;
			LAYER M1 ;
			RECT 6.04 1.625 6.36 1.885 ;
			LAYER M1 ;
			RECT 7.215 1.655 7.535 1.885 ;
			LAYER M1 ;
			RECT 6.055 0.62 6.335 1.625 ;
			LAYER M1 ;
			RECT 7.235 0.62 7.515 1.655 ;
			LAYER M1 ;
			RECT 8.395 1.64 8.715 1.885 ;
			LAYER M1 ;
			RECT 8.415 0.62 8.695 1.64 ;
			LAYER M1 ;
			RECT 9.58 1.625 9.9 1.885 ;
			LAYER M1 ;
			RECT 10.755 1.655 11.075 1.885 ;
			LAYER M1 ;
			RECT 9.595 0.62 9.875 1.625 ;
			LAYER M1 ;
			RECT 10.775 0.62 11.055 1.655 ;
			LAYER M1 ;
			RECT 11.935 1.64 12.255 1.885 ;
			LAYER M1 ;
			RECT 11.955 0.62 12.235 1.64 ;
			LAYER M1 ;
			RECT 13.12 1.625 13.44 1.885 ;
			LAYER M1 ;
			RECT 14.295 1.655 14.615 1.885 ;
			LAYER M1 ;
			RECT 13.135 0.62 13.415 1.625 ;
			LAYER M1 ;
			RECT 14.315 0.62 14.595 1.655 ;
			LAYER M1 ;
			RECT 15.475 1.64 15.795 1.885 ;
			LAYER M1 ;
			RECT 15.495 0.62 15.775 1.64 ;
			LAYER M1 ;
			RECT 16.66 1.625 16.98 1.885 ;
			LAYER M1 ;
			RECT 17.835 1.655 18.155 1.885 ;
			LAYER M1 ;
			RECT 16.675 0.62 16.955 1.625 ;
			LAYER M1 ;
			RECT 17.855 0.62 18.135 1.655 ;
			LAYER M1 ;
			RECT 19.015 1.64 19.335 1.885 ;
			LAYER M1 ;
			RECT 19.035 0.62 19.315 1.64 ;
			LAYER M1 ;
			RECT 20.2 1.625 20.52 1.885 ;
			LAYER M1 ;
			RECT 21.375 1.655 21.695 1.885 ;
			LAYER M1 ;
			RECT 22.555 1.655 22.875 1.885 ;
			LAYER M1 ;
			RECT 20.215 0.62 20.495 1.625 ;
			LAYER M1 ;
			RECT 21.395 0.62 21.675 1.655 ;
			LAYER M1 ;
			RECT 22.575 0.62 22.855 1.655 ;
			LAYER M1 ;
			RECT 23.73 1.625 24.05 1.885 ;
			LAYER M1 ;
			RECT 24.915 1.64 25.235 1.885 ;
			LAYER M1 ;
			RECT 23.755 0.62 24.035 1.625 ;
			LAYER M1 ;
			RECT 24.935 0.62 25.215 1.64 ;
			LAYER VIA1 ;
			RECT 1.365 2.09 1.585 2.31 ;
			LAYER VIA1 ;
			RECT 2.55 2.075 2.77 2.295 ;
			LAYER VIA1 ;
			RECT 3.725 2.105 3.945 2.325 ;
			LAYER VIA1 ;
			RECT 4.905 2.09 5.125 2.31 ;
			LAYER VIA1 ;
			RECT 6.09 2.075 6.31 2.295 ;
			LAYER VIA1 ;
			RECT 7.265 2.105 7.485 2.325 ;
			LAYER VIA1 ;
			RECT 8.445 2.09 8.665 2.31 ;
			LAYER VIA1 ;
			RECT 9.63 2.075 9.85 2.295 ;
			LAYER VIA1 ;
			RECT 10.805 2.105 11.025 2.325 ;
			LAYER VIA1 ;
			RECT 11.985 2.09 12.205 2.31 ;
			LAYER VIA1 ;
			RECT 13.17 2.075 13.39 2.295 ;
			LAYER VIA1 ;
			RECT 14.345 2.105 14.565 2.325 ;
			LAYER VIA1 ;
			RECT 15.525 2.09 15.745 2.31 ;
			LAYER VIA1 ;
			RECT 16.71 2.075 16.93 2.295 ;
			LAYER VIA1 ;
			RECT 17.885 2.105 18.105 2.325 ;
			LAYER VIA1 ;
			RECT 19.065 2.09 19.285 2.31 ;
			LAYER VIA1 ;
			RECT 20.25 2.075 20.47 2.295 ;
			LAYER VIA1 ;
			RECT 21.425 2.105 21.645 2.325 ;
			LAYER VIA1 ;
			RECT 22.605 2.105 22.825 2.325 ;
			LAYER VIA1 ;
			RECT 23.78 2.075 24 2.295 ;
			LAYER VIA1 ;
			RECT 24.965 2.09 25.185 2.31 ;
			LAYER VIA1 ;
			RECT 1.365 1.65 1.585 1.87 ;
			LAYER VIA1 ;
			RECT 2.55 1.635 2.77 1.855 ;
			LAYER VIA1 ;
			RECT 3.725 1.665 3.945 1.885 ;
			LAYER VIA1 ;
			RECT 4.905 1.65 5.125 1.87 ;
			LAYER VIA1 ;
			RECT 6.09 1.635 6.31 1.855 ;
			LAYER VIA1 ;
			RECT 7.265 1.665 7.485 1.885 ;
			LAYER VIA1 ;
			RECT 8.445 1.65 8.665 1.87 ;
			LAYER VIA1 ;
			RECT 9.63 1.635 9.85 1.855 ;
			LAYER VIA1 ;
			RECT 10.805 1.665 11.025 1.885 ;
			LAYER VIA1 ;
			RECT 11.985 1.65 12.205 1.87 ;
			LAYER VIA1 ;
			RECT 13.17 1.635 13.39 1.855 ;
			LAYER VIA1 ;
			RECT 14.345 1.665 14.565 1.885 ;
			LAYER VIA1 ;
			RECT 15.525 1.65 15.745 1.87 ;
			LAYER VIA1 ;
			RECT 16.71 1.635 16.93 1.855 ;
			LAYER VIA1 ;
			RECT 17.885 1.665 18.105 1.885 ;
			LAYER VIA1 ;
			RECT 19.065 1.65 19.285 1.87 ;
			LAYER VIA1 ;
			RECT 20.25 1.635 20.47 1.855 ;
			LAYER VIA1 ;
			RECT 21.425 1.665 21.645 1.885 ;
			LAYER VIA1 ;
			RECT 22.605 1.665 22.825 1.885 ;
			LAYER VIA1 ;
			RECT 23.78 1.635 24 1.855 ;
			LAYER VIA1 ;
			RECT 24.965 1.65 25.185 1.87 ;
			LAYER M2 ;
			RECT 0.12 1.015 26.43 2.335 ;
			LAYER M1 ;
			RECT 1.335 10.76 1.615 11.78 ;
			LAYER M1 ;
			RECT 2.515 10.775 2.795 11.78 ;
			LAYER M1 ;
			RECT 1.315 10.515 1.635 10.76 ;
			LAYER M1 ;
			RECT 2.5 10.515 2.82 10.775 ;
			LAYER M1 ;
			RECT 3.695 10.745 3.975 11.78 ;
			LAYER M1 ;
			RECT 4.875 10.76 5.155 11.78 ;
			LAYER M1 ;
			RECT 6.055 10.775 6.335 11.78 ;
			LAYER M1 ;
			RECT 3.675 10.515 3.995 10.745 ;
			LAYER M1 ;
			RECT 4.855 10.515 5.175 10.76 ;
			LAYER M1 ;
			RECT 6.04 10.515 6.36 10.775 ;
			LAYER M1 ;
			RECT 7.235 10.745 7.515 11.78 ;
			LAYER M1 ;
			RECT 8.415 10.76 8.695 11.78 ;
			LAYER M1 ;
			RECT 9.595 10.775 9.875 11.78 ;
			LAYER M1 ;
			RECT 7.215 10.515 7.535 10.745 ;
			LAYER M1 ;
			RECT 8.395 10.515 8.715 10.76 ;
			LAYER M1 ;
			RECT 9.58 10.515 9.9 10.775 ;
			LAYER M1 ;
			RECT 10.775 10.745 11.055 11.78 ;
			LAYER M1 ;
			RECT 11.955 10.76 12.235 11.78 ;
			LAYER M1 ;
			RECT 13.135 10.775 13.415 11.78 ;
			LAYER M1 ;
			RECT 10.755 10.515 11.075 10.745 ;
			LAYER M1 ;
			RECT 11.935 10.515 12.255 10.76 ;
			LAYER M1 ;
			RECT 13.12 10.515 13.44 10.775 ;
			LAYER M1 ;
			RECT 14.315 10.745 14.595 11.78 ;
			LAYER M1 ;
			RECT 15.495 10.76 15.775 11.78 ;
			LAYER M1 ;
			RECT 16.675 10.775 16.955 11.78 ;
			LAYER M1 ;
			RECT 14.295 10.515 14.615 10.745 ;
			LAYER M1 ;
			RECT 15.475 10.515 15.795 10.76 ;
			LAYER M1 ;
			RECT 16.66 10.515 16.98 10.775 ;
			LAYER M1 ;
			RECT 17.855 10.745 18.135 11.78 ;
			LAYER M1 ;
			RECT 19.035 10.76 19.315 11.78 ;
			LAYER M1 ;
			RECT 20.215 10.775 20.495 11.78 ;
			LAYER M1 ;
			RECT 17.835 10.515 18.155 10.745 ;
			LAYER M1 ;
			RECT 19.015 10.515 19.335 10.76 ;
			LAYER M1 ;
			RECT 20.2 10.515 20.52 10.775 ;
			LAYER M1 ;
			RECT 21.395 10.745 21.675 11.78 ;
			LAYER M1 ;
			RECT 22.575 10.745 22.855 11.78 ;
			LAYER M1 ;
			RECT 23.755 10.775 24.035 11.78 ;
			LAYER M1 ;
			RECT 21.375 10.515 21.695 10.745 ;
			LAYER M1 ;
			RECT 22.555 10.515 22.875 10.745 ;
			LAYER M1 ;
			RECT 23.73 10.515 24.05 10.775 ;
			LAYER M1 ;
			RECT 24.935 10.76 25.215 11.78 ;
			LAYER M1 ;
			RECT 24.915 10.515 25.235 10.76 ;
			LAYER M1 ;
			RECT 1.315 10.275 25.235 10.515 ;
			LAYER M1 ;
			RECT 1.315 10.08 1.635 10.275 ;
			LAYER M1 ;
			RECT 2.5 10.27 3.995 10.275 ;
			LAYER M1 ;
			RECT 2.5 10.095 2.82 10.27 ;
			LAYER M1 ;
			RECT 1.335 6.82 1.615 10.08 ;
			LAYER M1 ;
			RECT 2.515 6.82 2.795 10.095 ;
			LAYER M1 ;
			RECT 3.675 10.065 3.995 10.27 ;
			LAYER M1 ;
			RECT 4.855 10.08 5.175 10.275 ;
			LAYER M1 ;
			RECT 6.04 10.27 7.535 10.275 ;
			LAYER M1 ;
			RECT 6.04 10.095 6.36 10.27 ;
			LAYER M1 ;
			RECT 3.695 6.82 3.975 10.065 ;
			LAYER M1 ;
			RECT 4.875 6.82 5.155 10.08 ;
			LAYER M1 ;
			RECT 6.055 6.82 6.335 10.095 ;
			LAYER M1 ;
			RECT 7.215 10.065 7.535 10.27 ;
			LAYER M1 ;
			RECT 8.395 10.08 8.715 10.275 ;
			LAYER M1 ;
			RECT 9.58 10.27 11.075 10.275 ;
			LAYER M1 ;
			RECT 9.58 10.095 9.9 10.27 ;
			LAYER M1 ;
			RECT 7.235 6.82 7.515 10.065 ;
			LAYER M1 ;
			RECT 8.415 6.82 8.695 10.08 ;
			LAYER M1 ;
			RECT 9.595 6.82 9.875 10.095 ;
			LAYER M1 ;
			RECT 10.755 10.065 11.075 10.27 ;
			LAYER M1 ;
			RECT 11.935 10.08 12.255 10.275 ;
			LAYER M1 ;
			RECT 13.12 10.27 14.615 10.275 ;
			LAYER M1 ;
			RECT 13.12 10.095 13.44 10.27 ;
			LAYER M1 ;
			RECT 10.775 6.82 11.055 10.065 ;
			LAYER M1 ;
			RECT 11.955 6.82 12.235 10.08 ;
			LAYER M1 ;
			RECT 13.135 6.82 13.415 10.095 ;
			LAYER M1 ;
			RECT 14.295 10.065 14.615 10.27 ;
			LAYER M1 ;
			RECT 15.475 10.08 15.795 10.275 ;
			LAYER M1 ;
			RECT 16.66 10.27 18.155 10.275 ;
			LAYER M1 ;
			RECT 16.66 10.095 16.98 10.27 ;
			LAYER M1 ;
			RECT 14.315 6.82 14.595 10.065 ;
			LAYER M1 ;
			RECT 15.495 6.82 15.775 10.08 ;
			LAYER M1 ;
			RECT 16.675 6.82 16.955 10.095 ;
			LAYER M1 ;
			RECT 17.835 10.065 18.155 10.27 ;
			LAYER M1 ;
			RECT 19.015 10.08 19.335 10.275 ;
			LAYER M1 ;
			RECT 20.2 10.27 21.695 10.275 ;
			LAYER M1 ;
			RECT 20.2 10.095 20.52 10.27 ;
			LAYER M1 ;
			RECT 17.855 6.82 18.135 10.065 ;
			LAYER M1 ;
			RECT 19.035 6.82 19.315 10.08 ;
			LAYER M1 ;
			RECT 20.215 6.82 20.495 10.095 ;
			LAYER M1 ;
			RECT 21.375 10.065 21.695 10.27 ;
			LAYER M1 ;
			RECT 22.555 10.27 24.05 10.275 ;
			LAYER M1 ;
			RECT 22.555 10.065 22.875 10.27 ;
			LAYER M1 ;
			RECT 23.73 10.095 24.05 10.27 ;
			LAYER M1 ;
			RECT 21.395 6.82 21.675 10.065 ;
			LAYER M1 ;
			RECT 22.575 6.82 22.855 10.065 ;
			LAYER M1 ;
			RECT 23.755 6.82 24.035 10.095 ;
			LAYER M1 ;
			RECT 24.915 10.08 25.235 10.275 ;
			LAYER M1 ;
			RECT 24.935 6.82 25.215 10.08 ;
			LAYER VIA1 ;
			RECT 1.365 10.53 1.585 10.75 ;
			LAYER VIA1 ;
			RECT 2.55 10.545 2.77 10.765 ;
			LAYER VIA1 ;
			RECT 3.725 10.515 3.945 10.735 ;
			LAYER VIA1 ;
			RECT 4.905 10.53 5.125 10.75 ;
			LAYER VIA1 ;
			RECT 6.09 10.545 6.31 10.765 ;
			LAYER VIA1 ;
			RECT 7.265 10.515 7.485 10.735 ;
			LAYER VIA1 ;
			RECT 8.445 10.53 8.665 10.75 ;
			LAYER VIA1 ;
			RECT 9.63 10.545 9.85 10.765 ;
			LAYER VIA1 ;
			RECT 10.805 10.515 11.025 10.735 ;
			LAYER VIA1 ;
			RECT 11.985 10.53 12.205 10.75 ;
			LAYER VIA1 ;
			RECT 13.17 10.545 13.39 10.765 ;
			LAYER VIA1 ;
			RECT 14.345 10.515 14.565 10.735 ;
			LAYER VIA1 ;
			RECT 15.525 10.53 15.745 10.75 ;
			LAYER VIA1 ;
			RECT 16.71 10.545 16.93 10.765 ;
			LAYER VIA1 ;
			RECT 17.885 10.515 18.105 10.735 ;
			LAYER VIA1 ;
			RECT 19.065 10.53 19.285 10.75 ;
			LAYER VIA1 ;
			RECT 20.25 10.545 20.47 10.765 ;
			LAYER VIA1 ;
			RECT 21.425 10.515 21.645 10.735 ;
			LAYER VIA1 ;
			RECT 22.605 10.515 22.825 10.735 ;
			LAYER VIA1 ;
			RECT 23.78 10.545 24 10.765 ;
			LAYER VIA1 ;
			RECT 24.965 10.53 25.185 10.75 ;
			LAYER VIA1 ;
			RECT 1.365 10.09 1.585 10.31 ;
			LAYER VIA1 ;
			RECT 2.55 10.105 2.77 10.325 ;
			LAYER VIA1 ;
			RECT 3.725 10.075 3.945 10.295 ;
			LAYER VIA1 ;
			RECT 4.905 10.09 5.125 10.31 ;
			LAYER VIA1 ;
			RECT 6.09 10.105 6.31 10.325 ;
			LAYER VIA1 ;
			RECT 7.265 10.075 7.485 10.295 ;
			LAYER VIA1 ;
			RECT 8.445 10.09 8.665 10.31 ;
			LAYER VIA1 ;
			RECT 9.63 10.105 9.85 10.325 ;
			LAYER VIA1 ;
			RECT 10.805 10.075 11.025 10.295 ;
			LAYER VIA1 ;
			RECT 11.985 10.09 12.205 10.31 ;
			LAYER VIA1 ;
			RECT 13.17 10.105 13.39 10.325 ;
			LAYER VIA1 ;
			RECT 14.345 10.075 14.565 10.295 ;
			LAYER VIA1 ;
			RECT 15.525 10.09 15.745 10.31 ;
			LAYER VIA1 ;
			RECT 16.71 10.105 16.93 10.325 ;
			LAYER VIA1 ;
			RECT 17.885 10.075 18.105 10.295 ;
			LAYER VIA1 ;
			RECT 19.065 10.09 19.285 10.31 ;
			LAYER VIA1 ;
			RECT 20.25 10.105 20.47 10.325 ;
			LAYER VIA1 ;
			RECT 21.425 10.075 21.645 10.295 ;
			LAYER VIA1 ;
			RECT 22.605 10.075 22.825 10.295 ;
			LAYER VIA1 ;
			RECT 23.78 10.105 24 10.325 ;
			LAYER VIA1 ;
			RECT 24.965 10.09 25.185 10.31 ;
			LAYER M2 ;
			RECT 0.12 10.08 26.43 11.4 ;
			LAYER M2 ;
			RECT 3.675 10.065 3.995 10.08 ;
			LAYER M2 ;
			RECT 7.215 10.065 7.535 10.08 ;
			LAYER M2 ;
			RECT 10.755 10.065 11.075 10.08 ;
			LAYER M2 ;
			RECT 14.295 10.065 14.615 10.08 ;
			LAYER M2 ;
			RECT 17.835 10.065 18.155 10.08 ;
			LAYER M2 ;
			RECT 21.375 10.065 21.695 10.08 ;
			LAYER M2 ;
			RECT 22.555 10.065 22.875 10.08 ;
		END
	END out
	PIN GND
		DIRECTION inout ;
		USE GROUND ;
		PORT
			LAYER M1 ;
			RECT 0.155 0.42 0.435 1.575 ;
			LAYER M1 ;
			RECT 0.745 0.42 1.025 1.575 ;
			LAYER M1 ;
			RECT 1.925 0.42 2.205 1.575 ;
			LAYER M1 ;
			RECT 3.105 0.42 3.385 1.575 ;
			LAYER M1 ;
			RECT 4.285 0.42 4.565 1.575 ;
			LAYER M1 ;
			RECT 5.465 0.42 5.745 1.575 ;
			LAYER M1 ;
			RECT 6.645 0.42 6.925 1.575 ;
			LAYER M1 ;
			RECT 7.825 0.42 8.105 1.575 ;
			LAYER M1 ;
			RECT 9.005 0.42 9.285 1.575 ;
			LAYER M1 ;
			RECT 10.185 0.42 10.465 1.575 ;
			LAYER M1 ;
			RECT 11.365 0.42 11.645 1.575 ;
			LAYER M1 ;
			RECT 12.545 0.42 12.825 1.575 ;
			LAYER M1 ;
			RECT 13.725 0.42 14.005 1.575 ;
			LAYER M1 ;
			RECT 14.905 0.42 15.185 1.575 ;
			LAYER M1 ;
			RECT 16.085 0.42 16.365 1.575 ;
			LAYER M1 ;
			RECT 17.265 0.42 17.545 1.575 ;
			LAYER M1 ;
			RECT 18.445 0.42 18.725 1.575 ;
			LAYER M1 ;
			RECT 19.625 0.42 19.905 1.575 ;
			LAYER M1 ;
			RECT 20.805 0.42 21.085 1.575 ;
			LAYER M1 ;
			RECT 21.985 0.42 22.265 1.575 ;
			LAYER M1 ;
			RECT 23.165 0.42 23.445 1.575 ;
			LAYER M1 ;
			RECT 24.345 0.42 24.625 1.575 ;
			LAYER M1 ;
			RECT 25.525 0.42 25.805 1.575 ;
			LAYER M1 ;
			RECT 26.115 0.42 26.395 1.575 ;
			LAYER M1 ;
			RECT 0 0.35 26.395 0.42 ;
			LAYER M1 ;
			RECT 0 -0.42 26.66 0.35 ;
			LAYER VIA1 ;
			RECT 0.82 -0.11 1.04 0.11 ;
			LAYER VIA1 ;
			RECT 1.44 -0.11 1.66 0.11 ;
			LAYER VIA1 ;
			RECT 2.06 -0.11 2.28 0.11 ;
			LAYER VIA1 ;
			RECT 2.68 -0.11 2.9 0.11 ;
			LAYER VIA1 ;
			RECT 3.3 -0.11 3.52 0.11 ;
			LAYER VIA1 ;
			RECT 3.92 -0.11 4.14 0.11 ;
			LAYER VIA1 ;
			RECT 4.54 -0.11 4.76 0.11 ;
			LAYER VIA1 ;
			RECT 5.16 -0.11 5.38 0.11 ;
			LAYER VIA1 ;
			RECT 7.02 -0.11 7.24 0.11 ;
			LAYER VIA1 ;
			RECT 7.64 -0.11 7.86 0.11 ;
			LAYER VIA1 ;
			RECT 8.26 -0.11 8.48 0.11 ;
			LAYER VIA1 ;
			RECT 8.88 -0.11 9.1 0.11 ;
			LAYER VIA1 ;
			RECT 9.5 -0.11 9.72 0.11 ;
			LAYER VIA1 ;
			RECT 10.12 -0.11 10.34 0.11 ;
			LAYER VIA1 ;
			RECT 10.74 -0.11 10.96 0.11 ;
			LAYER VIA1 ;
			RECT 11.36 -0.11 11.58 0.11 ;
			LAYER VIA1 ;
			RECT 13.22 -0.11 13.44 0.11 ;
			LAYER VIA1 ;
			RECT 13.84 -0.11 14.06 0.11 ;
			LAYER VIA1 ;
			RECT 14.46 -0.11 14.68 0.11 ;
			LAYER VIA1 ;
			RECT 15.08 -0.11 15.3 0.11 ;
			LAYER VIA1 ;
			RECT 15.7 -0.11 15.92 0.11 ;
			LAYER VIA1 ;
			RECT 16.32 -0.11 16.54 0.11 ;
			LAYER VIA1 ;
			RECT 16.94 -0.11 17.16 0.11 ;
			LAYER VIA1 ;
			RECT 17.56 -0.11 17.78 0.11 ;
			LAYER VIA1 ;
			RECT 19.42 -0.11 19.64 0.11 ;
			LAYER VIA1 ;
			RECT 20.04 -0.11 20.26 0.11 ;
			LAYER VIA1 ;
			RECT 20.66 -0.11 20.88 0.11 ;
			LAYER VIA1 ;
			RECT 21.28 -0.11 21.5 0.11 ;
			LAYER VIA1 ;
			RECT 21.9 -0.11 22.12 0.11 ;
			LAYER VIA1 ;
			RECT 22.52 -0.11 22.74 0.11 ;
			LAYER VIA1 ;
			RECT 23.14 -0.11 23.36 0.11 ;
			LAYER VIA1 ;
			RECT 23.76 -0.11 23.98 0.11 ;
			LAYER VIA1 ;
			RECT 25.62 -0.11 25.84 0.11 ;
			LAYER VIA1 ;
			RECT 26.24 -0.11 26.46 0.11 ;
			LAYER M2 ;
			RECT 0 -0.415 26.66 0.42 ;
			LAYER M1 ;
			RECT 0 12.05 26.66 12.82 ;
			LAYER M1 ;
			RECT 0 11.98 26.395 12.05 ;
			LAYER M1 ;
			RECT 0.155 10.825 0.435 11.98 ;
			LAYER M1 ;
			RECT 0.745 10.825 1.025 11.98 ;
			LAYER M1 ;
			RECT 1.925 10.825 2.205 11.98 ;
			LAYER M1 ;
			RECT 3.105 10.825 3.385 11.98 ;
			LAYER M1 ;
			RECT 4.285 10.825 4.565 11.98 ;
			LAYER M1 ;
			RECT 5.465 10.825 5.745 11.98 ;
			LAYER M1 ;
			RECT 6.645 10.825 6.925 11.98 ;
			LAYER M1 ;
			RECT 7.825 10.825 8.105 11.98 ;
			LAYER M1 ;
			RECT 9.005 10.825 9.285 11.98 ;
			LAYER M1 ;
			RECT 10.185 10.825 10.465 11.98 ;
			LAYER M1 ;
			RECT 11.365 10.825 11.645 11.98 ;
			LAYER M1 ;
			RECT 12.545 10.825 12.825 11.98 ;
			LAYER M1 ;
			RECT 13.725 10.825 14.005 11.98 ;
			LAYER M1 ;
			RECT 14.905 10.825 15.185 11.98 ;
			LAYER M1 ;
			RECT 16.085 10.825 16.365 11.98 ;
			LAYER M1 ;
			RECT 17.265 10.825 17.545 11.98 ;
			LAYER M1 ;
			RECT 18.445 10.825 18.725 11.98 ;
			LAYER M1 ;
			RECT 19.625 10.825 19.905 11.98 ;
			LAYER M1 ;
			RECT 20.805 10.825 21.085 11.98 ;
			LAYER M1 ;
			RECT 21.985 10.825 22.265 11.98 ;
			LAYER M1 ;
			RECT 23.165 10.825 23.445 11.98 ;
			LAYER M1 ;
			RECT 24.345 10.825 24.625 11.98 ;
			LAYER M1 ;
			RECT 25.525 10.825 25.805 11.98 ;
			LAYER M1 ;
			RECT 26.115 10.825 26.395 11.98 ;
			LAYER VIA1 ;
			RECT 0.82 12.29 1.04 12.51 ;
			LAYER VIA1 ;
			RECT 1.44 12.29 1.66 12.51 ;
			LAYER VIA1 ;
			RECT 2.06 12.29 2.28 12.51 ;
			LAYER VIA1 ;
			RECT 2.68 12.29 2.9 12.51 ;
			LAYER VIA1 ;
			RECT 3.3 12.29 3.52 12.51 ;
			LAYER VIA1 ;
			RECT 3.92 12.29 4.14 12.51 ;
			LAYER VIA1 ;
			RECT 4.54 12.29 4.76 12.51 ;
			LAYER VIA1 ;
			RECT 5.16 12.29 5.38 12.51 ;
			LAYER VIA1 ;
			RECT 7.02 12.29 7.24 12.51 ;
			LAYER VIA1 ;
			RECT 7.64 12.29 7.86 12.51 ;
			LAYER VIA1 ;
			RECT 8.26 12.29 8.48 12.51 ;
			LAYER VIA1 ;
			RECT 8.88 12.29 9.1 12.51 ;
			LAYER VIA1 ;
			RECT 9.5 12.29 9.72 12.51 ;
			LAYER VIA1 ;
			RECT 10.12 12.29 10.34 12.51 ;
			LAYER VIA1 ;
			RECT 10.74 12.29 10.96 12.51 ;
			LAYER VIA1 ;
			RECT 11.36 12.29 11.58 12.51 ;
			LAYER VIA1 ;
			RECT 13.22 12.29 13.44 12.51 ;
			LAYER VIA1 ;
			RECT 13.84 12.29 14.06 12.51 ;
			LAYER VIA1 ;
			RECT 14.46 12.29 14.68 12.51 ;
			LAYER VIA1 ;
			RECT 15.08 12.29 15.3 12.51 ;
			LAYER VIA1 ;
			RECT 15.7 12.29 15.92 12.51 ;
			LAYER VIA1 ;
			RECT 16.32 12.29 16.54 12.51 ;
			LAYER VIA1 ;
			RECT 16.94 12.29 17.16 12.51 ;
			LAYER VIA1 ;
			RECT 17.56 12.29 17.78 12.51 ;
			LAYER VIA1 ;
			RECT 19.42 12.29 19.64 12.51 ;
			LAYER VIA1 ;
			RECT 20.04 12.29 20.26 12.51 ;
			LAYER VIA1 ;
			RECT 20.66 12.29 20.88 12.51 ;
			LAYER VIA1 ;
			RECT 21.28 12.29 21.5 12.51 ;
			LAYER VIA1 ;
			RECT 21.9 12.29 22.12 12.51 ;
			LAYER VIA1 ;
			RECT 22.52 12.29 22.74 12.51 ;
			LAYER VIA1 ;
			RECT 23.14 12.29 23.36 12.51 ;
			LAYER VIA1 ;
			RECT 23.76 12.29 23.98 12.51 ;
			LAYER VIA1 ;
			RECT 25.62 12.29 25.84 12.51 ;
			LAYER VIA1 ;
			RECT 26.24 12.29 26.46 12.51 ;
			LAYER M2 ;
			RECT 0 11.98 26.66 12.815 ;
		END
	END GND
	PIN VDD
		DIRECTION inout ;
		USE POWER ;
		PORT
			LAYER M1 ;
			RECT 0.155 6.62 0.435 8.805 ;
			LAYER M1 ;
			RECT 0.745 6.62 1.025 8.805 ;
			LAYER M1 ;
			RECT 1.925 6.62 2.205 8.805 ;
			LAYER M1 ;
			RECT 3.105 6.62 3.385 8.805 ;
			LAYER M1 ;
			RECT 4.285 6.62 4.565 8.805 ;
			LAYER M1 ;
			RECT 5.465 6.62 5.745 8.805 ;
			LAYER M1 ;
			RECT 6.645 6.62 6.925 8.805 ;
			LAYER M1 ;
			RECT 7.825 6.62 8.105 8.805 ;
			LAYER M1 ;
			RECT 9.005 6.62 9.285 8.805 ;
			LAYER M1 ;
			RECT 10.185 6.62 10.465 8.805 ;
			LAYER M1 ;
			RECT 11.365 6.62 11.645 8.805 ;
			LAYER M1 ;
			RECT 12.545 6.62 12.825 8.805 ;
			LAYER M1 ;
			RECT 13.725 6.62 14.005 8.805 ;
			LAYER M1 ;
			RECT 14.905 6.62 15.185 8.805 ;
			LAYER M1 ;
			RECT 16.085 6.62 16.365 8.805 ;
			LAYER M1 ;
			RECT 17.265 6.62 17.545 8.805 ;
			LAYER M1 ;
			RECT 18.445 6.62 18.725 8.805 ;
			LAYER M1 ;
			RECT 19.625 6.62 19.905 8.805 ;
			LAYER M1 ;
			RECT 20.805 6.62 21.085 8.805 ;
			LAYER M1 ;
			RECT 21.985 6.62 22.265 8.805 ;
			LAYER M1 ;
			RECT 23.165 6.62 23.445 8.805 ;
			LAYER M1 ;
			RECT 24.345 6.62 24.625 8.805 ;
			LAYER M1 ;
			RECT 25.525 6.62 25.805 8.805 ;
			LAYER M1 ;
			RECT 26.115 6.62 26.395 8.805 ;
			LAYER M1 ;
			RECT 0 5.78 26.66 6.62 ;
			LAYER M1 ;
			RECT 0.155 3.595 0.435 5.78 ;
			LAYER M1 ;
			RECT 0.745 3.595 1.025 5.78 ;
			LAYER M1 ;
			RECT 1.925 3.595 2.205 5.78 ;
			LAYER M1 ;
			RECT 3.105 3.595 3.385 5.78 ;
			LAYER M1 ;
			RECT 4.285 3.595 4.565 5.78 ;
			LAYER M1 ;
			RECT 5.465 3.595 5.745 5.78 ;
			LAYER M1 ;
			RECT 6.645 3.595 6.925 5.78 ;
			LAYER M1 ;
			RECT 7.825 3.595 8.105 5.78 ;
			LAYER M1 ;
			RECT 9.005 3.595 9.285 5.78 ;
			LAYER M1 ;
			RECT 10.185 3.595 10.465 5.78 ;
			LAYER M1 ;
			RECT 11.365 3.595 11.645 5.78 ;
			LAYER M1 ;
			RECT 12.545 3.595 12.825 5.78 ;
			LAYER M1 ;
			RECT 13.725 3.595 14.005 5.78 ;
			LAYER M1 ;
			RECT 14.905 3.595 15.185 5.78 ;
			LAYER M1 ;
			RECT 16.085 3.595 16.365 5.78 ;
			LAYER M1 ;
			RECT 17.265 3.595 17.545 5.78 ;
			LAYER M1 ;
			RECT 18.445 3.595 18.725 5.78 ;
			LAYER M1 ;
			RECT 19.625 3.595 19.905 5.78 ;
			LAYER M1 ;
			RECT 20.805 3.595 21.085 5.78 ;
			LAYER M1 ;
			RECT 21.985 3.595 22.265 5.78 ;
			LAYER M1 ;
			RECT 23.165 3.595 23.445 5.78 ;
			LAYER M1 ;
			RECT 24.345 3.595 24.625 5.78 ;
			LAYER M1 ;
			RECT 25.525 3.595 25.805 5.78 ;
			LAYER M1 ;
			RECT 26.115 3.595 26.395 5.78 ;
			LAYER VIA1 ;
			RECT 0.82 6.09 1.04 6.31 ;
			LAYER VIA1 ;
			RECT 1.44 6.09 1.66 6.31 ;
			LAYER VIA1 ;
			RECT 2.06 6.09 2.28 6.31 ;
			LAYER VIA1 ;
			RECT 2.68 6.09 2.9 6.31 ;
			LAYER VIA1 ;
			RECT 3.3 6.09 3.52 6.31 ;
			LAYER VIA1 ;
			RECT 3.92 6.09 4.14 6.31 ;
			LAYER VIA1 ;
			RECT 4.54 6.09 4.76 6.31 ;
			LAYER VIA1 ;
			RECT 5.16 6.09 5.38 6.31 ;
			LAYER VIA1 ;
			RECT 7.02 6.09 7.24 6.31 ;
			LAYER VIA1 ;
			RECT 7.64 6.09 7.86 6.31 ;
			LAYER VIA1 ;
			RECT 8.26 6.09 8.48 6.31 ;
			LAYER VIA1 ;
			RECT 8.88 6.09 9.1 6.31 ;
			LAYER VIA1 ;
			RECT 9.5 6.09 9.72 6.31 ;
			LAYER VIA1 ;
			RECT 10.12 6.09 10.34 6.31 ;
			LAYER VIA1 ;
			RECT 10.74 6.09 10.96 6.31 ;
			LAYER VIA1 ;
			RECT 11.36 6.09 11.58 6.31 ;
			LAYER VIA1 ;
			RECT 13.22 6.09 13.44 6.31 ;
			LAYER VIA1 ;
			RECT 13.84 6.09 14.06 6.31 ;
			LAYER VIA1 ;
			RECT 14.46 6.09 14.68 6.31 ;
			LAYER VIA1 ;
			RECT 15.08 6.09 15.3 6.31 ;
			LAYER VIA1 ;
			RECT 15.7 6.09 15.92 6.31 ;
			LAYER VIA1 ;
			RECT 16.32 6.09 16.54 6.31 ;
			LAYER VIA1 ;
			RECT 16.94 6.09 17.16 6.31 ;
			LAYER VIA1 ;
			RECT 17.56 6.09 17.78 6.31 ;
			LAYER VIA1 ;
			RECT 19.42 6.09 19.64 6.31 ;
			LAYER VIA1 ;
			RECT 20.04 6.09 20.26 6.31 ;
			LAYER VIA1 ;
			RECT 20.66 6.09 20.88 6.31 ;
			LAYER VIA1 ;
			RECT 21.28 6.09 21.5 6.31 ;
			LAYER VIA1 ;
			RECT 21.9 6.09 22.12 6.31 ;
			LAYER VIA1 ;
			RECT 22.52 6.09 22.74 6.31 ;
			LAYER VIA1 ;
			RECT 23.14 6.09 23.36 6.31 ;
			LAYER VIA1 ;
			RECT 23.76 6.09 23.98 6.31 ;
			LAYER VIA1 ;
			RECT 25.62 6.09 25.84 6.31 ;
			LAYER VIA1 ;
			RECT 26.24 6.09 26.46 6.31 ;
			LAYER M2 ;
			RECT 0 5.78 26.55 6.62 ;
		END
	END VDD
	PIN in
		DIRECTION input ;
		USE SIGNAL ;
		PORT
			LAYER M1 ;
			RECT 1.94 2.75 2.18 3.35 ;
			LAYER M1 ;
			RECT 3.13 2.735 3.37 3.335 ;
			LAYER M1 ;
			RECT 5.48 2.75 5.72 3.35 ;
			LAYER M1 ;
			RECT 6.67 2.735 6.91 3.335 ;
			LAYER M1 ;
			RECT 9.02 2.75 9.26 3.35 ;
			LAYER M1 ;
			RECT 10.21 2.735 10.45 3.335 ;
			LAYER M1 ;
			RECT 12.56 2.75 12.8 3.35 ;
			LAYER M1 ;
			RECT 13.75 2.735 13.99 3.335 ;
			LAYER M1 ;
			RECT 16.1 2.75 16.34 3.35 ;
			LAYER M1 ;
			RECT 17.29 2.735 17.53 3.335 ;
			LAYER M1 ;
			RECT 19.64 2.75 19.88 3.35 ;
			LAYER M1 ;
			RECT 20.83 2.735 21.07 3.335 ;
			LAYER M1 ;
			RECT 23.18 2.735 23.42 3.335 ;
			LAYER M1 ;
			RECT 24.37 2.75 24.61 3.35 ;
			LAYER VIA1 ;
			RECT 1.95 3.065 2.17 3.285 ;
			LAYER VIA1 ;
			RECT 3.14 3.065 3.36 3.285 ;
			LAYER VIA1 ;
			RECT 5.49 3.065 5.71 3.285 ;
			LAYER VIA1 ;
			RECT 6.68 3.065 6.9 3.285 ;
			LAYER VIA1 ;
			RECT 9.03 3.065 9.25 3.285 ;
			LAYER VIA1 ;
			RECT 10.22 3.065 10.44 3.285 ;
			LAYER VIA1 ;
			RECT 12.57 3.065 12.79 3.285 ;
			LAYER VIA1 ;
			RECT 13.76 3.065 13.98 3.285 ;
			LAYER VIA1 ;
			RECT 16.11 3.065 16.33 3.285 ;
			LAYER VIA1 ;
			RECT 17.3 3.065 17.52 3.285 ;
			LAYER VIA1 ;
			RECT 19.65 3.065 19.87 3.285 ;
			LAYER VIA1 ;
			RECT 20.84 3.065 21.06 3.285 ;
			LAYER VIA1 ;
			RECT 23.19 3.065 23.41 3.285 ;
			LAYER VIA1 ;
			RECT 24.38 3.065 24.6 3.285 ;
			LAYER M2 ;
			RECT 0.12 3.29 26.43 3.53 ;
			LAYER M2 ;
			RECT 1.94 3.015 2.18 3.29 ;
			LAYER M2 ;
			RECT 3.13 3.015 3.37 3.29 ;
			LAYER M2 ;
			RECT 5.48 3.015 5.72 3.29 ;
			LAYER M2 ;
			RECT 6.67 3.015 6.91 3.29 ;
			LAYER M2 ;
			RECT 9.02 3.015 9.26 3.29 ;
			LAYER M2 ;
			RECT 10.21 3.015 10.45 3.29 ;
			LAYER M2 ;
			RECT 12.56 3.015 12.8 3.29 ;
			LAYER M2 ;
			RECT 13.75 3.015 13.99 3.29 ;
			LAYER M2 ;
			RECT 16.1 3.015 16.34 3.29 ;
			LAYER M2 ;
			RECT 17.29 3.015 17.53 3.29 ;
			LAYER M2 ;
			RECT 19.64 3.015 19.88 3.29 ;
			LAYER M2 ;
			RECT 20.83 3.015 21.07 3.29 ;
			LAYER M2 ;
			RECT 23.18 3.015 23.42 3.29 ;
			LAYER M2 ;
			RECT 24.37 3.015 24.61 3.29 ;
			LAYER M1 ;
			RECT 1.94 9.05 2.18 9.65 ;
			LAYER M1 ;
			RECT 3.13 9.065 3.37 9.665 ;
			LAYER M1 ;
			RECT 5.48 9.05 5.72 9.65 ;
			LAYER M1 ;
			RECT 6.67 9.065 6.91 9.665 ;
			LAYER M1 ;
			RECT 9.02 9.05 9.26 9.65 ;
			LAYER M1 ;
			RECT 10.21 9.065 10.45 9.665 ;
			LAYER M1 ;
			RECT 12.56 9.05 12.8 9.65 ;
			LAYER M1 ;
			RECT 13.75 9.065 13.99 9.665 ;
			LAYER M1 ;
			RECT 16.1 9.05 16.34 9.65 ;
			LAYER M1 ;
			RECT 17.29 9.065 17.53 9.665 ;
			LAYER M1 ;
			RECT 19.64 9.05 19.88 9.65 ;
			LAYER M1 ;
			RECT 20.83 9.065 21.07 9.665 ;
			LAYER M1 ;
			RECT 23.18 9.065 23.42 9.665 ;
			LAYER M1 ;
			RECT 24.37 9.05 24.61 9.65 ;
			LAYER VIA1 ;
			RECT 1.95 9.115 2.17 9.335 ;
			LAYER VIA1 ;
			RECT 3.14 9.115 3.36 9.335 ;
			LAYER VIA1 ;
			RECT 5.49 9.115 5.71 9.335 ;
			LAYER VIA1 ;
			RECT 6.68 9.115 6.9 9.335 ;
			LAYER VIA1 ;
			RECT 9.03 9.115 9.25 9.335 ;
			LAYER VIA1 ;
			RECT 10.22 9.115 10.44 9.335 ;
			LAYER VIA1 ;
			RECT 12.57 9.115 12.79 9.335 ;
			LAYER VIA1 ;
			RECT 13.76 9.115 13.98 9.335 ;
			LAYER VIA1 ;
			RECT 16.11 9.115 16.33 9.335 ;
			LAYER VIA1 ;
			RECT 17.3 9.115 17.52 9.335 ;
			LAYER VIA1 ;
			RECT 19.65 9.115 19.87 9.335 ;
			LAYER VIA1 ;
			RECT 20.84 9.115 21.06 9.335 ;
			LAYER VIA1 ;
			RECT 23.19 9.115 23.41 9.335 ;
			LAYER VIA1 ;
			RECT 24.38 9.115 24.6 9.335 ;
			LAYER M2 ;
			RECT 1.94 9.11 2.18 9.385 ;
			LAYER M2 ;
			RECT 3.13 9.11 3.37 9.385 ;
			LAYER M2 ;
			RECT 5.48 9.11 5.72 9.385 ;
			LAYER M2 ;
			RECT 6.67 9.11 6.91 9.385 ;
			LAYER M2 ;
			RECT 9.02 9.11 9.26 9.385 ;
			LAYER M2 ;
			RECT 10.21 9.11 10.45 9.385 ;
			LAYER M2 ;
			RECT 12.56 9.11 12.8 9.385 ;
			LAYER M2 ;
			RECT 13.75 9.11 13.99 9.385 ;
			LAYER M2 ;
			RECT 16.1 9.11 16.34 9.385 ;
			LAYER M2 ;
			RECT 17.29 9.11 17.53 9.385 ;
			LAYER M2 ;
			RECT 19.64 9.11 19.88 9.385 ;
			LAYER M2 ;
			RECT 20.83 9.11 21.07 9.385 ;
			LAYER M2 ;
			RECT 23.18 9.11 23.42 9.385 ;
			LAYER M2 ;
			RECT 24.37 9.11 24.61 9.385 ;
			LAYER M2 ;
			RECT 0.12 8.87 26.43 9.11 ;
		END
		ANTENNASIZE 20.328 ;
	END in
	OBS
	END
END MMI_INVH224
MACRO PWR_VIA_1_5
	CLASS CORE ;
	FOREIGN PWR_VIA_1_5 -0.3 -0.3 ;
	SIZE 1.6 BY 1.6 ;
	SYMMETRY X Y ;
	SITE CORE1 ;
	PIN pin
		DIRECTION inout ;
		USE SIGNAL ;
		PORT
			LAYER M1 ;
			RECT 0.34 0.84 0.66 0.92 ;
			LAYER M1 ;
			RECT 0.12 0.16 0.88 0.84 ;
			LAYER M1 ;
			RECT 0.34 0.08 0.66 0.16 ;
			LAYER VIA1 ;
			RECT 0.17 0.61 0.39 0.83 ;
			LAYER VIA1 ;
			RECT 0.61 0.61 0.83 0.83 ;
			LAYER VIA1 ;
			RECT 0.17 0.17 0.39 0.39 ;
			LAYER VIA1 ;
			RECT 0.61 0.17 0.83 0.39 ;
			LAYER M2 ;
			RECT 0.085 0.08 0.92 0.92 ;
			LAYER VIA2 ;
			RECT 0.14 0.64 0.36 0.86 ;
			LAYER VIA2 ;
			RECT 0.64 0.64 0.86 0.86 ;
			LAYER VIA2 ;
			RECT 0.14 0.14 0.36 0.36 ;
			LAYER VIA2 ;
			RECT 0.64 0.14 0.86 0.36 ;
			LAYER M3 ;
			RECT 0 0 1 1 ;
			LAYER VIA3 ;
			RECT 0.14 0.64 0.36 0.86 ;
			LAYER VIA3 ;
			RECT 0.64 0.64 0.86 0.86 ;
			LAYER VIA3 ;
			RECT 0.14 0.14 0.36 0.36 ;
			LAYER VIA3 ;
			RECT 0.64 0.14 0.86 0.36 ;
			LAYER M4 ;
			RECT 0 0 1 1 ;
			LAYER VIA4 ;
			RECT 0.14 0.64 0.36 0.86 ;
			LAYER VIA4 ;
			RECT 0.64 0.64 0.86 0.86 ;
			LAYER VIA4 ;
			RECT 0.14 0.14 0.36 0.36 ;
			LAYER VIA4 ;
			RECT 0.64 0.14 0.86 0.36 ;
			LAYER M5 ;
			RECT 0 0 1 1 ;
		END
	END pin
	OBS
	END
END PWR_VIA_1_5
END LIBRARY
